VERSION 5.8 ;
BUSBITCHARS "[]" ;
DIVIDERCHAR "/" ;
UNITS
    DATABASE MICRONS 1000 ;
END UNITS

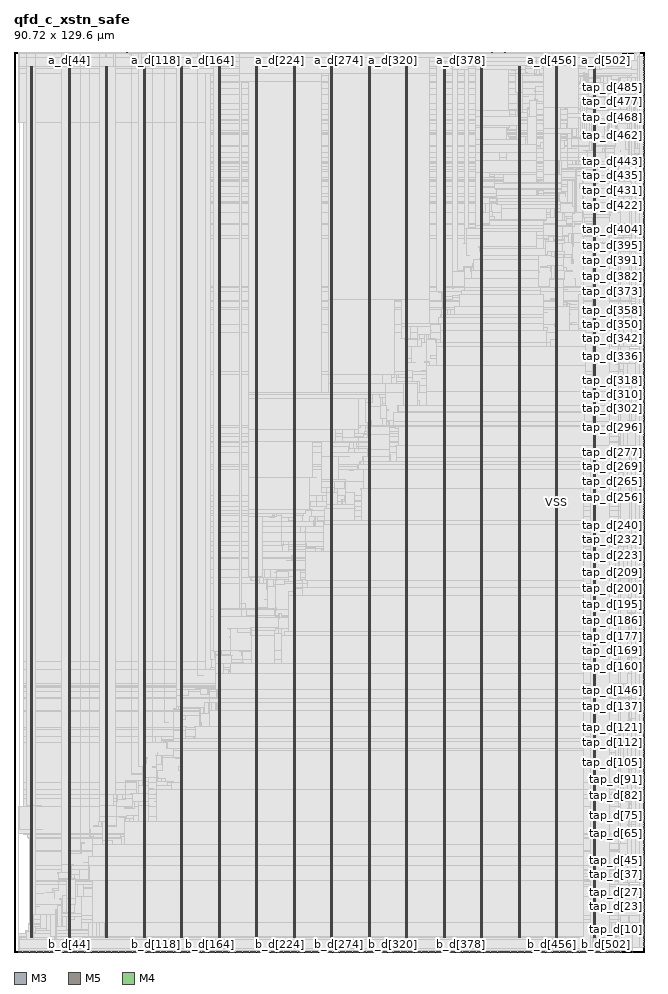
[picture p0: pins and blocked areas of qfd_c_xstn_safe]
MACRO qfd_c_xstn_safe
  FOREIGN qfd_c_xstn_safe 0 0 ;
  CLASS BLOCK ;
  SIZE 90.72 BY 129.6 ;
  PIN a_d[0]
    DIRECTION OUTPUT ;
    USE SIGNAL ;
    PORT
      LAYER M3 ;
        RECT  0.612 129.562 0.63 129.6 ;
    END
  END a_d[0]
  PIN a_d[100]
    DIRECTION OUTPUT ;
    USE SIGNAL ;
    PORT
      LAYER M3 ;
        RECT  17.46 129.562 17.478 129.6 ;
    END
  END a_d[100]
  PIN a_d[101]
    DIRECTION OUTPUT ;
    USE SIGNAL ;
    PORT
      LAYER M5 ;
        RECT  17.616 129.516 17.64 129.6 ;
    END
  END a_d[101]
  PIN a_d[102]
    DIRECTION OUTPUT ;
    USE SIGNAL ;
    PORT
      LAYER M3 ;
        RECT  17.784 129.562 17.802 129.6 ;
    END
  END a_d[102]
  PIN a_d[103]
    DIRECTION OUTPUT ;
    USE SIGNAL ;
    PORT
      LAYER M5 ;
        RECT  17.952 129.516 17.976 129.6 ;
    END
  END a_d[103]
  PIN a_d[104]
    DIRECTION OUTPUT ;
    USE SIGNAL ;
    PORT
      LAYER M3 ;
        RECT  18.144 129.562 18.162 129.6 ;
    END
  END a_d[104]
  PIN a_d[105]
    DIRECTION OUTPUT ;
    USE SIGNAL ;
    PORT
      LAYER M5 ;
        RECT  18.288 129.516 18.312 129.6 ;
    END
  END a_d[105]
  PIN a_d[106]
    DIRECTION OUTPUT ;
    USE SIGNAL ;
    PORT
      LAYER M3 ;
        RECT  18.468 129.562 18.486 129.6 ;
    END
  END a_d[106]
  PIN a_d[107]
    DIRECTION OUTPUT ;
    USE SIGNAL ;
    PORT
      LAYER M5 ;
        RECT  18.624 129.516 18.648 129.6 ;
    END
  END a_d[107]
  PIN a_d[108]
    DIRECTION OUTPUT ;
    USE SIGNAL ;
    PORT
      LAYER M3 ;
        RECT  18.828 129.562 18.846 129.6 ;
    END
  END a_d[108]
  PIN a_d[109]
    DIRECTION OUTPUT ;
    USE SIGNAL ;
    PORT
      LAYER M5 ;
        RECT  18.96 129.516 18.984 129.6 ;
    END
  END a_d[109]
  PIN a_d[10]
    DIRECTION OUTPUT ;
    USE SIGNAL ;
    PORT
      LAYER M3 ;
        RECT  2.304 129.562 2.322 129.6 ;
    END
  END a_d[10]
  PIN a_d[110]
    DIRECTION OUTPUT ;
    USE SIGNAL ;
    PORT
      LAYER M3 ;
        RECT  19.152 129.562 19.17 129.6 ;
    END
  END a_d[110]
  PIN a_d[111]
    DIRECTION OUTPUT ;
    USE SIGNAL ;
    PORT
      LAYER M5 ;
        RECT  19.296 129.516 19.32 129.6 ;
    END
  END a_d[111]
  PIN a_d[112]
    DIRECTION OUTPUT ;
    USE SIGNAL ;
    PORT
      LAYER M3 ;
        RECT  19.476 129.562 19.494 129.6 ;
    END
  END a_d[112]
  PIN a_d[113]
    DIRECTION OUTPUT ;
    USE SIGNAL ;
    PORT
      LAYER M5 ;
        RECT  19.632 129.516 19.656 129.6 ;
    END
  END a_d[113]
  PIN a_d[114]
    DIRECTION OUTPUT ;
    USE SIGNAL ;
    PORT
      LAYER M3 ;
        RECT  19.836 129.562 19.854 129.6 ;
    END
  END a_d[114]
  PIN a_d[115]
    DIRECTION OUTPUT ;
    USE SIGNAL ;
    PORT
      LAYER M5 ;
        RECT  19.968 129.516 19.992 129.6 ;
    END
  END a_d[115]
  PIN a_d[116]
    DIRECTION OUTPUT ;
    USE SIGNAL ;
    PORT
      LAYER M3 ;
        RECT  20.16 129.562 20.178 129.6 ;
    END
  END a_d[116]
  PIN a_d[117]
    DIRECTION OUTPUT ;
    USE SIGNAL ;
    PORT
      LAYER M5 ;
        RECT  20.304 129.516 20.328 129.6 ;
    END
  END a_d[117]
  PIN a_d[118]
    DIRECTION OUTPUT ;
    USE SIGNAL ;
    PORT
      LAYER M3 ;
        RECT  20.484 129.562 20.502 129.6 ;
    END
  END a_d[118]
  PIN a_d[119]
    DIRECTION OUTPUT ;
    USE SIGNAL ;
    PORT
      LAYER M5 ;
        RECT  20.64 129.516 20.664 129.6 ;
    END
  END a_d[119]
  PIN a_d[11]
    DIRECTION OUTPUT ;
    USE SIGNAL ;
    PORT
      LAYER M5 ;
        RECT  2.448 129.516 2.472 129.6 ;
    END
  END a_d[11]
  PIN a_d[120]
    DIRECTION OUTPUT ;
    USE SIGNAL ;
    PORT
      LAYER M3 ;
        RECT  20.844 129.562 20.862 129.6 ;
    END
  END a_d[120]
  PIN a_d[121]
    DIRECTION OUTPUT ;
    USE SIGNAL ;
    PORT
      LAYER M5 ;
        RECT  20.976 129.516 21 129.6 ;
    END
  END a_d[121]
  PIN a_d[122]
    DIRECTION OUTPUT ;
    USE SIGNAL ;
    PORT
      LAYER M3 ;
        RECT  21.168 129.562 21.186 129.6 ;
    END
  END a_d[122]
  PIN a_d[123]
    DIRECTION OUTPUT ;
    USE SIGNAL ;
    PORT
      LAYER M5 ;
        RECT  21.36 129.516 21.384 129.6 ;
    END
  END a_d[123]
  PIN a_d[124]
    DIRECTION OUTPUT ;
    USE SIGNAL ;
    PORT
      LAYER M3 ;
        RECT  21.492 129.562 21.51 129.6 ;
    END
  END a_d[124]
  PIN a_d[125]
    DIRECTION OUTPUT ;
    USE SIGNAL ;
    PORT
      LAYER M5 ;
        RECT  21.696 129.516 21.72 129.6 ;
    END
  END a_d[125]
  PIN a_d[126]
    DIRECTION OUTPUT ;
    USE SIGNAL ;
    PORT
      LAYER M3 ;
        RECT  21.852 129.562 21.87 129.6 ;
    END
  END a_d[126]
  PIN a_d[127]
    DIRECTION OUTPUT ;
    USE SIGNAL ;
    PORT
      LAYER M5 ;
        RECT  22.032 129.516 22.056 129.6 ;
    END
  END a_d[127]
  PIN a_d[128]
    DIRECTION OUTPUT ;
    USE SIGNAL ;
    PORT
      LAYER M3 ;
        RECT  22.176 129.562 22.194 129.6 ;
    END
  END a_d[128]
  PIN a_d[129]
    DIRECTION OUTPUT ;
    USE SIGNAL ;
    PORT
      LAYER M5 ;
        RECT  22.368 129.516 22.392 129.6 ;
    END
  END a_d[129]
  PIN a_d[12]
    DIRECTION OUTPUT ;
    USE SIGNAL ;
    PORT
      LAYER M3 ;
        RECT  2.628 129.562 2.646 129.6 ;
    END
  END a_d[12]
  PIN a_d[130]
    DIRECTION OUTPUT ;
    USE SIGNAL ;
    PORT
      LAYER M3 ;
        RECT  22.536 129.562 22.554 129.6 ;
    END
  END a_d[130]
  PIN a_d[131]
    DIRECTION OUTPUT ;
    USE SIGNAL ;
    PORT
      LAYER M5 ;
        RECT  22.704 129.516 22.728 129.6 ;
    END
  END a_d[131]
  PIN a_d[132]
    DIRECTION OUTPUT ;
    USE SIGNAL ;
    PORT
      LAYER M3 ;
        RECT  22.86 129.562 22.878 129.6 ;
    END
  END a_d[132]
  PIN a_d[133]
    DIRECTION OUTPUT ;
    USE SIGNAL ;
    PORT
      LAYER M5 ;
        RECT  23.04 129.516 23.064 129.6 ;
    END
  END a_d[133]
  PIN a_d[134]
    DIRECTION OUTPUT ;
    USE SIGNAL ;
    PORT
      LAYER M3 ;
        RECT  23.184 129.562 23.202 129.6 ;
    END
  END a_d[134]
  PIN a_d[135]
    DIRECTION OUTPUT ;
    USE SIGNAL ;
    PORT
      LAYER M5 ;
        RECT  23.376 129.516 23.4 129.6 ;
    END
  END a_d[135]
  PIN a_d[136]
    DIRECTION OUTPUT ;
    USE SIGNAL ;
    PORT
      LAYER M3 ;
        RECT  23.544 129.562 23.562 129.6 ;
    END
  END a_d[136]
  PIN a_d[137]
    DIRECTION OUTPUT ;
    USE SIGNAL ;
    PORT
      LAYER M5 ;
        RECT  23.712 129.516 23.736 129.6 ;
    END
  END a_d[137]
  PIN a_d[138]
    DIRECTION OUTPUT ;
    USE SIGNAL ;
    PORT
      LAYER M3 ;
        RECT  23.868 129.562 23.886 129.6 ;
    END
  END a_d[138]
  PIN a_d[139]
    DIRECTION OUTPUT ;
    USE SIGNAL ;
    PORT
      LAYER M5 ;
        RECT  24.048 129.516 24.072 129.6 ;
    END
  END a_d[139]
  PIN a_d[13]
    DIRECTION OUTPUT ;
    USE SIGNAL ;
    PORT
      LAYER M5 ;
        RECT  2.784 129.516 2.808 129.6 ;
    END
  END a_d[13]
  PIN a_d[140]
    DIRECTION OUTPUT ;
    USE SIGNAL ;
    PORT
      LAYER M3 ;
        RECT  24.192 129.562 24.21 129.6 ;
    END
  END a_d[140]
  PIN a_d[141]
    DIRECTION OUTPUT ;
    USE SIGNAL ;
    PORT
      LAYER M5 ;
        RECT  24.384 129.516 24.408 129.6 ;
    END
  END a_d[141]
  PIN a_d[142]
    DIRECTION OUTPUT ;
    USE SIGNAL ;
    PORT
      LAYER M3 ;
        RECT  24.552 129.562 24.57 129.6 ;
    END
  END a_d[142]
  PIN a_d[143]
    DIRECTION OUTPUT ;
    USE SIGNAL ;
    PORT
      LAYER M5 ;
        RECT  24.72 129.516 24.744 129.6 ;
    END
  END a_d[143]
  PIN a_d[144]
    DIRECTION OUTPUT ;
    USE SIGNAL ;
    PORT
      LAYER M3 ;
        RECT  24.876 129.562 24.894 129.6 ;
    END
  END a_d[144]
  PIN a_d[145]
    DIRECTION OUTPUT ;
    USE SIGNAL ;
    PORT
      LAYER M5 ;
        RECT  25.056 129.516 25.08 129.6 ;
    END
  END a_d[145]
  PIN a_d[146]
    DIRECTION OUTPUT ;
    USE SIGNAL ;
    PORT
      LAYER M3 ;
        RECT  25.2 129.562 25.218 129.6 ;
    END
  END a_d[146]
  PIN a_d[147]
    DIRECTION OUTPUT ;
    USE SIGNAL ;
    PORT
      LAYER M5 ;
        RECT  25.392 129.516 25.416 129.6 ;
    END
  END a_d[147]
  PIN a_d[148]
    DIRECTION OUTPUT ;
    USE SIGNAL ;
    PORT
      LAYER M3 ;
        RECT  25.56 129.562 25.578 129.6 ;
    END
  END a_d[148]
  PIN a_d[149]
    DIRECTION OUTPUT ;
    USE SIGNAL ;
    PORT
      LAYER M5 ;
        RECT  25.728 129.516 25.752 129.6 ;
    END
  END a_d[149]
  PIN a_d[14]
    DIRECTION OUTPUT ;
    USE SIGNAL ;
    PORT
      LAYER M3 ;
        RECT  2.988 129.562 3.006 129.6 ;
    END
  END a_d[14]
  PIN a_d[150]
    DIRECTION OUTPUT ;
    USE SIGNAL ;
    PORT
      LAYER M3 ;
        RECT  25.884 129.562 25.902 129.6 ;
    END
  END a_d[150]
  PIN a_d[151]
    DIRECTION OUTPUT ;
    USE SIGNAL ;
    PORT
      LAYER M5 ;
        RECT  26.064 129.516 26.088 129.6 ;
    END
  END a_d[151]
  PIN a_d[152]
    DIRECTION OUTPUT ;
    USE SIGNAL ;
    PORT
      LAYER M3 ;
        RECT  26.208 129.562 26.226 129.6 ;
    END
  END a_d[152]
  PIN a_d[153]
    DIRECTION OUTPUT ;
    USE SIGNAL ;
    PORT
      LAYER M5 ;
        RECT  26.4 129.516 26.424 129.6 ;
    END
  END a_d[153]
  PIN a_d[154]
    DIRECTION OUTPUT ;
    USE SIGNAL ;
    PORT
      LAYER M3 ;
        RECT  26.568 129.562 26.586 129.6 ;
    END
  END a_d[154]
  PIN a_d[155]
    DIRECTION OUTPUT ;
    USE SIGNAL ;
    PORT
      LAYER M5 ;
        RECT  26.736 129.516 26.76 129.6 ;
    END
  END a_d[155]
  PIN a_d[156]
    DIRECTION OUTPUT ;
    USE SIGNAL ;
    PORT
      LAYER M3 ;
        RECT  26.892 129.562 26.91 129.6 ;
    END
  END a_d[156]
  PIN a_d[157]
    DIRECTION OUTPUT ;
    USE SIGNAL ;
    PORT
      LAYER M5 ;
        RECT  27.072 129.516 27.096 129.6 ;
    END
  END a_d[157]
  PIN a_d[158]
    DIRECTION OUTPUT ;
    USE SIGNAL ;
    PORT
      LAYER M3 ;
        RECT  27.252 129.562 27.27 129.6 ;
    END
  END a_d[158]
  PIN a_d[159]
    DIRECTION OUTPUT ;
    USE SIGNAL ;
    PORT
      LAYER M5 ;
        RECT  27.408 129.516 27.432 129.6 ;
    END
  END a_d[159]
  PIN a_d[15]
    DIRECTION OUTPUT ;
    USE SIGNAL ;
    PORT
      LAYER M5 ;
        RECT  3.12 129.516 3.144 129.6 ;
    END
  END a_d[15]
  PIN a_d[160]
    DIRECTION OUTPUT ;
    USE SIGNAL ;
    PORT
      LAYER M3 ;
        RECT  27.576 129.562 27.594 129.6 ;
    END
  END a_d[160]
  PIN a_d[161]
    DIRECTION OUTPUT ;
    USE SIGNAL ;
    PORT
      LAYER M5 ;
        RECT  27.744 129.516 27.768 129.6 ;
    END
  END a_d[161]
  PIN a_d[162]
    DIRECTION OUTPUT ;
    USE SIGNAL ;
    PORT
      LAYER M3 ;
        RECT  27.9 129.562 27.918 129.6 ;
    END
  END a_d[162]
  PIN a_d[163]
    DIRECTION OUTPUT ;
    USE SIGNAL ;
    PORT
      LAYER M5 ;
        RECT  28.08 129.516 28.104 129.6 ;
    END
  END a_d[163]
  PIN a_d[164]
    DIRECTION OUTPUT ;
    USE SIGNAL ;
    PORT
      LAYER M3 ;
        RECT  28.26 129.562 28.278 129.6 ;
    END
  END a_d[164]
  PIN a_d[165]
    DIRECTION OUTPUT ;
    USE SIGNAL ;
    PORT
      LAYER M5 ;
        RECT  28.416 129.516 28.44 129.6 ;
    END
  END a_d[165]
  PIN a_d[166]
    DIRECTION OUTPUT ;
    USE SIGNAL ;
    PORT
      LAYER M3 ;
        RECT  28.584 129.562 28.602 129.6 ;
    END
  END a_d[166]
  PIN a_d[167]
    DIRECTION OUTPUT ;
    USE SIGNAL ;
    PORT
      LAYER M5 ;
        RECT  28.752 129.516 28.776 129.6 ;
    END
  END a_d[167]
  PIN a_d[168]
    DIRECTION OUTPUT ;
    USE SIGNAL ;
    PORT
      LAYER M3 ;
        RECT  28.908 129.562 28.926 129.6 ;
    END
  END a_d[168]
  PIN a_d[169]
    DIRECTION OUTPUT ;
    USE SIGNAL ;
    PORT
      LAYER M5 ;
        RECT  29.088 129.516 29.112 129.6 ;
    END
  END a_d[169]
  PIN a_d[16]
    DIRECTION OUTPUT ;
    USE SIGNAL ;
    PORT
      LAYER M3 ;
        RECT  3.312 129.562 3.33 129.6 ;
    END
  END a_d[16]
  PIN a_d[170]
    DIRECTION OUTPUT ;
    USE SIGNAL ;
    PORT
      LAYER M3 ;
        RECT  29.268 129.562 29.286 129.6 ;
    END
  END a_d[170]
  PIN a_d[171]
    DIRECTION OUTPUT ;
    USE SIGNAL ;
    PORT
      LAYER M5 ;
        RECT  29.424 129.516 29.448 129.6 ;
    END
  END a_d[171]
  PIN a_d[172]
    DIRECTION OUTPUT ;
    USE SIGNAL ;
    PORT
      LAYER M3 ;
        RECT  29.592 129.562 29.61 129.6 ;
    END
  END a_d[172]
  PIN a_d[173]
    DIRECTION OUTPUT ;
    USE SIGNAL ;
    PORT
      LAYER M5 ;
        RECT  29.76 129.516 29.784 129.6 ;
    END
  END a_d[173]
  PIN a_d[174]
    DIRECTION OUTPUT ;
    USE SIGNAL ;
    PORT
      LAYER M3 ;
        RECT  29.916 129.562 29.934 129.6 ;
    END
  END a_d[174]
  PIN a_d[175]
    DIRECTION OUTPUT ;
    USE SIGNAL ;
    PORT
      LAYER M5 ;
        RECT  30.096 129.516 30.12 129.6 ;
    END
  END a_d[175]
  PIN a_d[176]
    DIRECTION OUTPUT ;
    USE SIGNAL ;
    PORT
      LAYER M3 ;
        RECT  30.276 129.562 30.294 129.6 ;
    END
  END a_d[176]
  PIN a_d[177]
    DIRECTION OUTPUT ;
    USE SIGNAL ;
    PORT
      LAYER M5 ;
        RECT  30.432 129.516 30.456 129.6 ;
    END
  END a_d[177]
  PIN a_d[178]
    DIRECTION OUTPUT ;
    USE SIGNAL ;
    PORT
      LAYER M3 ;
        RECT  30.6 129.562 30.618 129.6 ;
    END
  END a_d[178]
  PIN a_d[179]
    DIRECTION OUTPUT ;
    USE SIGNAL ;
    PORT
      LAYER M5 ;
        RECT  30.768 129.516 30.792 129.6 ;
    END
  END a_d[179]
  PIN a_d[17]
    DIRECTION OUTPUT ;
    USE SIGNAL ;
    PORT
      LAYER M5 ;
        RECT  3.456 129.516 3.48 129.6 ;
    END
  END a_d[17]
  PIN a_d[180]
    DIRECTION OUTPUT ;
    USE SIGNAL ;
    PORT
      LAYER M3 ;
        RECT  30.96 129.562 30.978 129.6 ;
    END
  END a_d[180]
  PIN a_d[181]
    DIRECTION OUTPUT ;
    USE SIGNAL ;
    PORT
      LAYER M5 ;
        RECT  31.104 129.516 31.128 129.6 ;
    END
  END a_d[181]
  PIN a_d[182]
    DIRECTION OUTPUT ;
    USE SIGNAL ;
    PORT
      LAYER M3 ;
        RECT  31.284 129.562 31.302 129.6 ;
    END
  END a_d[182]
  PIN a_d[183]
    DIRECTION OUTPUT ;
    USE SIGNAL ;
    PORT
      LAYER M5 ;
        RECT  31.44 129.516 31.464 129.6 ;
    END
  END a_d[183]
  PIN a_d[184]
    DIRECTION OUTPUT ;
    USE SIGNAL ;
    PORT
      LAYER M3 ;
        RECT  31.608 129.562 31.626 129.6 ;
    END
  END a_d[184]
  PIN a_d[185]
    DIRECTION OUTPUT ;
    USE SIGNAL ;
    PORT
      LAYER M5 ;
        RECT  31.776 129.516 31.8 129.6 ;
    END
  END a_d[185]
  PIN a_d[186]
    DIRECTION OUTPUT ;
    USE SIGNAL ;
    PORT
      LAYER M3 ;
        RECT  31.968 129.562 31.986 129.6 ;
    END
  END a_d[186]
  PIN a_d[187]
    DIRECTION OUTPUT ;
    USE SIGNAL ;
    PORT
      LAYER M5 ;
        RECT  32.112 129.516 32.136 129.6 ;
    END
  END a_d[187]
  PIN a_d[188]
    DIRECTION OUTPUT ;
    USE SIGNAL ;
    PORT
      LAYER M3 ;
        RECT  32.292 129.562 32.31 129.6 ;
    END
  END a_d[188]
  PIN a_d[189]
    DIRECTION OUTPUT ;
    USE SIGNAL ;
    PORT
      LAYER M5 ;
        RECT  32.448 129.516 32.472 129.6 ;
    END
  END a_d[189]
  PIN a_d[18]
    DIRECTION OUTPUT ;
    USE SIGNAL ;
    PORT
      LAYER M3 ;
        RECT  3.636 129.562 3.654 129.6 ;
    END
  END a_d[18]
  PIN a_d[190]
    DIRECTION OUTPUT ;
    USE SIGNAL ;
    PORT
      LAYER M3 ;
        RECT  32.616 129.562 32.634 129.6 ;
    END
  END a_d[190]
  PIN a_d[191]
    DIRECTION OUTPUT ;
    USE SIGNAL ;
    PORT
      LAYER M5 ;
        RECT  32.784 129.516 32.808 129.6 ;
    END
  END a_d[191]
  PIN a_d[192]
    DIRECTION OUTPUT ;
    USE SIGNAL ;
    PORT
      LAYER M3 ;
        RECT  32.976 129.562 32.994 129.6 ;
    END
  END a_d[192]
  PIN a_d[193]
    DIRECTION OUTPUT ;
    USE SIGNAL ;
    PORT
      LAYER M5 ;
        RECT  33.12 129.516 33.144 129.6 ;
    END
  END a_d[193]
  PIN a_d[194]
    DIRECTION OUTPUT ;
    USE SIGNAL ;
    PORT
      LAYER M3 ;
        RECT  33.3 129.562 33.318 129.6 ;
    END
  END a_d[194]
  PIN a_d[195]
    DIRECTION OUTPUT ;
    USE SIGNAL ;
    PORT
      LAYER M5 ;
        RECT  33.456 129.516 33.48 129.6 ;
    END
  END a_d[195]
  PIN a_d[196]
    DIRECTION OUTPUT ;
    USE SIGNAL ;
    PORT
      LAYER M3 ;
        RECT  33.624 129.562 33.642 129.6 ;
    END
  END a_d[196]
  PIN a_d[197]
    DIRECTION OUTPUT ;
    USE SIGNAL ;
    PORT
      LAYER M5 ;
        RECT  33.792 129.516 33.816 129.6 ;
    END
  END a_d[197]
  PIN a_d[198]
    DIRECTION OUTPUT ;
    USE SIGNAL ;
    PORT
      LAYER M3 ;
        RECT  33.984 129.562 34.002 129.6 ;
    END
  END a_d[198]
  PIN a_d[199]
    DIRECTION OUTPUT ;
    USE SIGNAL ;
    PORT
      LAYER M5 ;
        RECT  34.128 129.516 34.152 129.6 ;
    END
  END a_d[199]
  PIN a_d[19]
    DIRECTION OUTPUT ;
    USE SIGNAL ;
    PORT
      LAYER M5 ;
        RECT  3.792 129.516 3.816 129.6 ;
    END
  END a_d[19]
  PIN a_d[1]
    DIRECTION OUTPUT ;
    USE SIGNAL ;
    PORT
      LAYER M5 ;
        RECT  0.768 129.516 0.792 129.6 ;
    END
  END a_d[1]
  PIN a_d[200]
    DIRECTION OUTPUT ;
    USE SIGNAL ;
    PORT
      LAYER M3 ;
        RECT  34.308 129.562 34.326 129.6 ;
    END
  END a_d[200]
  PIN a_d[201]
    DIRECTION OUTPUT ;
    USE SIGNAL ;
    PORT
      LAYER M5 ;
        RECT  34.464 129.516 34.488 129.6 ;
    END
  END a_d[201]
  PIN a_d[202]
    DIRECTION OUTPUT ;
    USE SIGNAL ;
    PORT
      LAYER M3 ;
        RECT  34.668 129.562 34.686 129.6 ;
    END
  END a_d[202]
  PIN a_d[203]
    DIRECTION OUTPUT ;
    USE SIGNAL ;
    PORT
      LAYER M5 ;
        RECT  34.8 129.516 34.824 129.6 ;
    END
  END a_d[203]
  PIN a_d[204]
    DIRECTION OUTPUT ;
    USE SIGNAL ;
    PORT
      LAYER M3 ;
        RECT  34.992 129.562 35.01 129.6 ;
    END
  END a_d[204]
  PIN a_d[205]
    DIRECTION OUTPUT ;
    USE SIGNAL ;
    PORT
      LAYER M5 ;
        RECT  35.136 129.516 35.16 129.6 ;
    END
  END a_d[205]
  PIN a_d[206]
    DIRECTION OUTPUT ;
    USE SIGNAL ;
    PORT
      LAYER M3 ;
        RECT  35.316 129.562 35.334 129.6 ;
    END
  END a_d[206]
  PIN a_d[207]
    DIRECTION OUTPUT ;
    USE SIGNAL ;
    PORT
      LAYER M5 ;
        RECT  35.472 129.516 35.496 129.6 ;
    END
  END a_d[207]
  PIN a_d[208]
    DIRECTION OUTPUT ;
    USE SIGNAL ;
    PORT
      LAYER M3 ;
        RECT  35.676 129.562 35.694 129.6 ;
    END
  END a_d[208]
  PIN a_d[209]
    DIRECTION OUTPUT ;
    USE SIGNAL ;
    PORT
      LAYER M5 ;
        RECT  35.808 129.516 35.832 129.6 ;
    END
  END a_d[209]
  PIN a_d[20]
    DIRECTION OUTPUT ;
    USE SIGNAL ;
    PORT
      LAYER M3 ;
        RECT  3.996 129.562 4.014 129.6 ;
    END
  END a_d[20]
  PIN a_d[210]
    DIRECTION OUTPUT ;
    USE SIGNAL ;
    PORT
      LAYER M3 ;
        RECT  36 129.562 36.018 129.6 ;
    END
  END a_d[210]
  PIN a_d[211]
    DIRECTION OUTPUT ;
    USE SIGNAL ;
    PORT
      LAYER M5 ;
        RECT  36.144 129.516 36.168 129.6 ;
    END
  END a_d[211]
  PIN a_d[212]
    DIRECTION OUTPUT ;
    USE SIGNAL ;
    PORT
      LAYER M3 ;
        RECT  36.324 129.562 36.342 129.6 ;
    END
  END a_d[212]
  PIN a_d[213]
    DIRECTION OUTPUT ;
    USE SIGNAL ;
    PORT
      LAYER M5 ;
        RECT  36.48 129.516 36.504 129.6 ;
    END
  END a_d[213]
  PIN a_d[214]
    DIRECTION OUTPUT ;
    USE SIGNAL ;
    PORT
      LAYER M3 ;
        RECT  36.684 129.562 36.702 129.6 ;
    END
  END a_d[214]
  PIN a_d[215]
    DIRECTION OUTPUT ;
    USE SIGNAL ;
    PORT
      LAYER M5 ;
        RECT  36.816 129.516 36.84 129.6 ;
    END
  END a_d[215]
  PIN a_d[216]
    DIRECTION OUTPUT ;
    USE SIGNAL ;
    PORT
      LAYER M3 ;
        RECT  37.008 129.562 37.026 129.6 ;
    END
  END a_d[216]
  PIN a_d[217]
    DIRECTION OUTPUT ;
    USE SIGNAL ;
    PORT
      LAYER M5 ;
        RECT  37.152 129.516 37.176 129.6 ;
    END
  END a_d[217]
  PIN a_d[218]
    DIRECTION OUTPUT ;
    USE SIGNAL ;
    PORT
      LAYER M3 ;
        RECT  37.332 129.562 37.35 129.6 ;
    END
  END a_d[218]
  PIN a_d[219]
    DIRECTION OUTPUT ;
    USE SIGNAL ;
    PORT
      LAYER M5 ;
        RECT  37.488 129.516 37.512 129.6 ;
    END
  END a_d[219]
  PIN a_d[21]
    DIRECTION OUTPUT ;
    USE SIGNAL ;
    PORT
      LAYER M5 ;
        RECT  4.128 129.516 4.152 129.6 ;
    END
  END a_d[21]
  PIN a_d[220]
    DIRECTION OUTPUT ;
    USE SIGNAL ;
    PORT
      LAYER M3 ;
        RECT  37.692 129.562 37.71 129.6 ;
    END
  END a_d[220]
  PIN a_d[221]
    DIRECTION OUTPUT ;
    USE SIGNAL ;
    PORT
      LAYER M5 ;
        RECT  37.872 129.516 37.896 129.6 ;
    END
  END a_d[221]
  PIN a_d[222]
    DIRECTION OUTPUT ;
    USE SIGNAL ;
    PORT
      LAYER M3 ;
        RECT  38.016 129.562 38.034 129.6 ;
    END
  END a_d[222]
  PIN a_d[223]
    DIRECTION OUTPUT ;
    USE SIGNAL ;
    PORT
      LAYER M5 ;
        RECT  38.208 129.516 38.232 129.6 ;
    END
  END a_d[223]
  PIN a_d[224]
    DIRECTION OUTPUT ;
    USE SIGNAL ;
    PORT
      LAYER M3 ;
        RECT  38.34 129.562 38.358 129.6 ;
    END
  END a_d[224]
  PIN a_d[225]
    DIRECTION OUTPUT ;
    USE SIGNAL ;
    PORT
      LAYER M5 ;
        RECT  38.544 129.516 38.568 129.6 ;
    END
  END a_d[225]
  PIN a_d[226]
    DIRECTION OUTPUT ;
    USE SIGNAL ;
    PORT
      LAYER M3 ;
        RECT  38.7 129.562 38.718 129.6 ;
    END
  END a_d[226]
  PIN a_d[227]
    DIRECTION OUTPUT ;
    USE SIGNAL ;
    PORT
      LAYER M5 ;
        RECT  38.88 129.516 38.904 129.6 ;
    END
  END a_d[227]
  PIN a_d[228]
    DIRECTION OUTPUT ;
    USE SIGNAL ;
    PORT
      LAYER M3 ;
        RECT  39.024 129.562 39.042 129.6 ;
    END
  END a_d[228]
  PIN a_d[229]
    DIRECTION OUTPUT ;
    USE SIGNAL ;
    PORT
      LAYER M5 ;
        RECT  39.216 129.516 39.24 129.6 ;
    END
  END a_d[229]
  PIN a_d[22]
    DIRECTION OUTPUT ;
    USE SIGNAL ;
    PORT
      LAYER M3 ;
        RECT  4.32 129.562 4.338 129.6 ;
    END
  END a_d[22]
  PIN a_d[230]
    DIRECTION OUTPUT ;
    USE SIGNAL ;
    PORT
      LAYER M3 ;
        RECT  39.384 129.562 39.402 129.6 ;
    END
  END a_d[230]
  PIN a_d[231]
    DIRECTION OUTPUT ;
    USE SIGNAL ;
    PORT
      LAYER M5 ;
        RECT  39.552 129.516 39.576 129.6 ;
    END
  END a_d[231]
  PIN a_d[232]
    DIRECTION OUTPUT ;
    USE SIGNAL ;
    PORT
      LAYER M3 ;
        RECT  39.708 129.562 39.726 129.6 ;
    END
  END a_d[232]
  PIN a_d[233]
    DIRECTION OUTPUT ;
    USE SIGNAL ;
    PORT
      LAYER M5 ;
        RECT  39.888 129.516 39.912 129.6 ;
    END
  END a_d[233]
  PIN a_d[234]
    DIRECTION OUTPUT ;
    USE SIGNAL ;
    PORT
      LAYER M3 ;
        RECT  40.032 129.562 40.05 129.6 ;
    END
  END a_d[234]
  PIN a_d[235]
    DIRECTION OUTPUT ;
    USE SIGNAL ;
    PORT
      LAYER M5 ;
        RECT  40.224 129.516 40.248 129.6 ;
    END
  END a_d[235]
  PIN a_d[236]
    DIRECTION OUTPUT ;
    USE SIGNAL ;
    PORT
      LAYER M3 ;
        RECT  40.392 129.562 40.41 129.6 ;
    END
  END a_d[236]
  PIN a_d[237]
    DIRECTION OUTPUT ;
    USE SIGNAL ;
    PORT
      LAYER M5 ;
        RECT  40.56 129.516 40.584 129.6 ;
    END
  END a_d[237]
  PIN a_d[238]
    DIRECTION OUTPUT ;
    USE SIGNAL ;
    PORT
      LAYER M3 ;
        RECT  40.716 129.562 40.734 129.6 ;
    END
  END a_d[238]
  PIN a_d[239]
    DIRECTION OUTPUT ;
    USE SIGNAL ;
    PORT
      LAYER M5 ;
        RECT  40.896 129.516 40.92 129.6 ;
    END
  END a_d[239]
  PIN a_d[23]
    DIRECTION OUTPUT ;
    USE SIGNAL ;
    PORT
      LAYER M5 ;
        RECT  4.464 129.516 4.488 129.6 ;
    END
  END a_d[23]
  PIN a_d[240]
    DIRECTION OUTPUT ;
    USE SIGNAL ;
    PORT
      LAYER M3 ;
        RECT  41.04 129.562 41.058 129.6 ;
    END
  END a_d[240]
  PIN a_d[241]
    DIRECTION OUTPUT ;
    USE SIGNAL ;
    PORT
      LAYER M5 ;
        RECT  41.232 129.516 41.256 129.6 ;
    END
  END a_d[241]
  PIN a_d[242]
    DIRECTION OUTPUT ;
    USE SIGNAL ;
    PORT
      LAYER M3 ;
        RECT  41.4 129.562 41.418 129.6 ;
    END
  END a_d[242]
  PIN a_d[243]
    DIRECTION OUTPUT ;
    USE SIGNAL ;
    PORT
      LAYER M5 ;
        RECT  41.568 129.516 41.592 129.6 ;
    END
  END a_d[243]
  PIN a_d[244]
    DIRECTION OUTPUT ;
    USE SIGNAL ;
    PORT
      LAYER M3 ;
        RECT  41.724 129.562 41.742 129.6 ;
    END
  END a_d[244]
  PIN a_d[245]
    DIRECTION OUTPUT ;
    USE SIGNAL ;
    PORT
      LAYER M5 ;
        RECT  41.904 129.516 41.928 129.6 ;
    END
  END a_d[245]
  PIN a_d[246]
    DIRECTION OUTPUT ;
    USE SIGNAL ;
    PORT
      LAYER M3 ;
        RECT  42.048 129.562 42.066 129.6 ;
    END
  END a_d[246]
  PIN a_d[247]
    DIRECTION OUTPUT ;
    USE SIGNAL ;
    PORT
      LAYER M5 ;
        RECT  42.24 129.516 42.264 129.6 ;
    END
  END a_d[247]
  PIN a_d[248]
    DIRECTION OUTPUT ;
    USE SIGNAL ;
    PORT
      LAYER M3 ;
        RECT  42.408 129.562 42.426 129.6 ;
    END
  END a_d[248]
  PIN a_d[249]
    DIRECTION OUTPUT ;
    USE SIGNAL ;
    PORT
      LAYER M5 ;
        RECT  42.576 129.516 42.6 129.6 ;
    END
  END a_d[249]
  PIN a_d[24]
    DIRECTION OUTPUT ;
    USE SIGNAL ;
    PORT
      LAYER M3 ;
        RECT  4.644 129.562 4.662 129.6 ;
    END
  END a_d[24]
  PIN a_d[250]
    DIRECTION OUTPUT ;
    USE SIGNAL ;
    PORT
      LAYER M3 ;
        RECT  42.732 129.562 42.75 129.6 ;
    END
  END a_d[250]
  PIN a_d[251]
    DIRECTION OUTPUT ;
    USE SIGNAL ;
    PORT
      LAYER M5 ;
        RECT  42.912 129.516 42.936 129.6 ;
    END
  END a_d[251]
  PIN a_d[252]
    DIRECTION OUTPUT ;
    USE SIGNAL ;
    PORT
      LAYER M3 ;
        RECT  43.092 129.562 43.11 129.6 ;
    END
  END a_d[252]
  PIN a_d[253]
    DIRECTION OUTPUT ;
    USE SIGNAL ;
    PORT
      LAYER M5 ;
        RECT  43.248 129.516 43.272 129.6 ;
    END
  END a_d[253]
  PIN a_d[254]
    DIRECTION OUTPUT ;
    USE SIGNAL ;
    PORT
      LAYER M3 ;
        RECT  43.416 129.562 43.434 129.6 ;
    END
  END a_d[254]
  PIN a_d[255]
    DIRECTION OUTPUT ;
    USE SIGNAL ;
    PORT
      LAYER M5 ;
        RECT  43.584 129.516 43.608 129.6 ;
    END
  END a_d[255]
  PIN a_d[256]
    DIRECTION OUTPUT ;
    USE SIGNAL ;
    PORT
      LAYER M3 ;
        RECT  43.74 129.562 43.758 129.6 ;
    END
  END a_d[256]
  PIN a_d[257]
    DIRECTION OUTPUT ;
    USE SIGNAL ;
    PORT
      LAYER M5 ;
        RECT  43.92 129.516 43.944 129.6 ;
    END
  END a_d[257]
  PIN a_d[258]
    DIRECTION OUTPUT ;
    USE SIGNAL ;
    PORT
      LAYER M3 ;
        RECT  44.1 129.562 44.118 129.6 ;
    END
  END a_d[258]
  PIN a_d[259]
    DIRECTION OUTPUT ;
    USE SIGNAL ;
    PORT
      LAYER M5 ;
        RECT  44.256 129.516 44.28 129.6 ;
    END
  END a_d[259]
  PIN a_d[25]
    DIRECTION OUTPUT ;
    USE SIGNAL ;
    PORT
      LAYER M5 ;
        RECT  4.848 129.516 4.872 129.6 ;
    END
  END a_d[25]
  PIN a_d[260]
    DIRECTION OUTPUT ;
    USE SIGNAL ;
    PORT
      LAYER M3 ;
        RECT  44.424 129.562 44.442 129.6 ;
    END
  END a_d[260]
  PIN a_d[261]
    DIRECTION OUTPUT ;
    USE SIGNAL ;
    PORT
      LAYER M5 ;
        RECT  44.592 129.516 44.616 129.6 ;
    END
  END a_d[261]
  PIN a_d[262]
    DIRECTION OUTPUT ;
    USE SIGNAL ;
    PORT
      LAYER M3 ;
        RECT  44.748 129.562 44.766 129.6 ;
    END
  END a_d[262]
  PIN a_d[263]
    DIRECTION OUTPUT ;
    USE SIGNAL ;
    PORT
      LAYER M5 ;
        RECT  44.928 129.516 44.952 129.6 ;
    END
  END a_d[263]
  PIN a_d[264]
    DIRECTION OUTPUT ;
    USE SIGNAL ;
    PORT
      LAYER M3 ;
        RECT  45.108 129.562 45.126 129.6 ;
    END
  END a_d[264]
  PIN a_d[265]
    DIRECTION OUTPUT ;
    USE SIGNAL ;
    PORT
      LAYER M5 ;
        RECT  45.264 129.516 45.288 129.6 ;
    END
  END a_d[265]
  PIN a_d[266]
    DIRECTION OUTPUT ;
    USE SIGNAL ;
    PORT
      LAYER M3 ;
        RECT  45.432 129.562 45.45 129.6 ;
    END
  END a_d[266]
  PIN a_d[267]
    DIRECTION OUTPUT ;
    USE SIGNAL ;
    PORT
      LAYER M5 ;
        RECT  45.6 129.516 45.624 129.6 ;
    END
  END a_d[267]
  PIN a_d[268]
    DIRECTION OUTPUT ;
    USE SIGNAL ;
    PORT
      LAYER M3 ;
        RECT  45.756 129.562 45.774 129.6 ;
    END
  END a_d[268]
  PIN a_d[269]
    DIRECTION OUTPUT ;
    USE SIGNAL ;
    PORT
      LAYER M5 ;
        RECT  45.936 129.516 45.96 129.6 ;
    END
  END a_d[269]
  PIN a_d[26]
    DIRECTION OUTPUT ;
    USE SIGNAL ;
    PORT
      LAYER M3 ;
        RECT  5.004 129.562 5.022 129.6 ;
    END
  END a_d[26]
  PIN a_d[270]
    DIRECTION OUTPUT ;
    USE SIGNAL ;
    PORT
      LAYER M3 ;
        RECT  46.116 129.562 46.134 129.6 ;
    END
  END a_d[270]
  PIN a_d[271]
    DIRECTION OUTPUT ;
    USE SIGNAL ;
    PORT
      LAYER M5 ;
        RECT  46.272 129.516 46.296 129.6 ;
    END
  END a_d[271]
  PIN a_d[272]
    DIRECTION OUTPUT ;
    USE SIGNAL ;
    PORT
      LAYER M3 ;
        RECT  46.44 129.562 46.458 129.6 ;
    END
  END a_d[272]
  PIN a_d[273]
    DIRECTION OUTPUT ;
    USE SIGNAL ;
    PORT
      LAYER M5 ;
        RECT  46.608 129.516 46.632 129.6 ;
    END
  END a_d[273]
  PIN a_d[274]
    DIRECTION OUTPUT ;
    USE SIGNAL ;
    PORT
      LAYER M3 ;
        RECT  46.764 129.562 46.782 129.6 ;
    END
  END a_d[274]
  PIN a_d[275]
    DIRECTION OUTPUT ;
    USE SIGNAL ;
    PORT
      LAYER M5 ;
        RECT  46.944 129.516 46.968 129.6 ;
    END
  END a_d[275]
  PIN a_d[276]
    DIRECTION OUTPUT ;
    USE SIGNAL ;
    PORT
      LAYER M3 ;
        RECT  47.124 129.562 47.142 129.6 ;
    END
  END a_d[276]
  PIN a_d[277]
    DIRECTION OUTPUT ;
    USE SIGNAL ;
    PORT
      LAYER M5 ;
        RECT  47.28 129.516 47.304 129.6 ;
    END
  END a_d[277]
  PIN a_d[278]
    DIRECTION OUTPUT ;
    USE SIGNAL ;
    PORT
      LAYER M3 ;
        RECT  47.448 129.562 47.466 129.6 ;
    END
  END a_d[278]
  PIN a_d[279]
    DIRECTION OUTPUT ;
    USE SIGNAL ;
    PORT
      LAYER M5 ;
        RECT  47.616 129.516 47.64 129.6 ;
    END
  END a_d[279]
  PIN a_d[27]
    DIRECTION OUTPUT ;
    USE SIGNAL ;
    PORT
      LAYER M5 ;
        RECT  5.184 129.516 5.208 129.6 ;
    END
  END a_d[27]
  PIN a_d[280]
    DIRECTION OUTPUT ;
    USE SIGNAL ;
    PORT
      LAYER M3 ;
        RECT  47.808 129.562 47.826 129.6 ;
    END
  END a_d[280]
  PIN a_d[281]
    DIRECTION OUTPUT ;
    USE SIGNAL ;
    PORT
      LAYER M5 ;
        RECT  47.952 129.516 47.976 129.6 ;
    END
  END a_d[281]
  PIN a_d[282]
    DIRECTION OUTPUT ;
    USE SIGNAL ;
    PORT
      LAYER M3 ;
        RECT  48.132 129.562 48.15 129.6 ;
    END
  END a_d[282]
  PIN a_d[283]
    DIRECTION OUTPUT ;
    USE SIGNAL ;
    PORT
      LAYER M5 ;
        RECT  48.288 129.516 48.312 129.6 ;
    END
  END a_d[283]
  PIN a_d[284]
    DIRECTION OUTPUT ;
    USE SIGNAL ;
    PORT
      LAYER M3 ;
        RECT  48.456 129.562 48.474 129.6 ;
    END
  END a_d[284]
  PIN a_d[285]
    DIRECTION OUTPUT ;
    USE SIGNAL ;
    PORT
      LAYER M5 ;
        RECT  48.624 129.516 48.648 129.6 ;
    END
  END a_d[285]
  PIN a_d[286]
    DIRECTION OUTPUT ;
    USE SIGNAL ;
    PORT
      LAYER M3 ;
        RECT  48.816 129.562 48.834 129.6 ;
    END
  END a_d[286]
  PIN a_d[287]
    DIRECTION OUTPUT ;
    USE SIGNAL ;
    PORT
      LAYER M5 ;
        RECT  48.96 129.516 48.984 129.6 ;
    END
  END a_d[287]
  PIN a_d[288]
    DIRECTION OUTPUT ;
    USE SIGNAL ;
    PORT
      LAYER M3 ;
        RECT  49.14 129.562 49.158 129.6 ;
    END
  END a_d[288]
  PIN a_d[289]
    DIRECTION OUTPUT ;
    USE SIGNAL ;
    PORT
      LAYER M5 ;
        RECT  49.296 129.516 49.32 129.6 ;
    END
  END a_d[289]
  PIN a_d[28]
    DIRECTION OUTPUT ;
    USE SIGNAL ;
    PORT
      LAYER M3 ;
        RECT  5.328 129.562 5.346 129.6 ;
    END
  END a_d[28]
  PIN a_d[290]
    DIRECTION OUTPUT ;
    USE SIGNAL ;
    PORT
      LAYER M3 ;
        RECT  49.464 129.562 49.482 129.6 ;
    END
  END a_d[290]
  PIN a_d[291]
    DIRECTION OUTPUT ;
    USE SIGNAL ;
    PORT
      LAYER M5 ;
        RECT  49.632 129.516 49.656 129.6 ;
    END
  END a_d[291]
  PIN a_d[292]
    DIRECTION OUTPUT ;
    USE SIGNAL ;
    PORT
      LAYER M3 ;
        RECT  49.824 129.562 49.842 129.6 ;
    END
  END a_d[292]
  PIN a_d[293]
    DIRECTION OUTPUT ;
    USE SIGNAL ;
    PORT
      LAYER M5 ;
        RECT  49.968 129.516 49.992 129.6 ;
    END
  END a_d[293]
  PIN a_d[294]
    DIRECTION OUTPUT ;
    USE SIGNAL ;
    PORT
      LAYER M3 ;
        RECT  50.148 129.562 50.166 129.6 ;
    END
  END a_d[294]
  PIN a_d[295]
    DIRECTION OUTPUT ;
    USE SIGNAL ;
    PORT
      LAYER M5 ;
        RECT  50.304 129.516 50.328 129.6 ;
    END
  END a_d[295]
  PIN a_d[296]
    DIRECTION OUTPUT ;
    USE SIGNAL ;
    PORT
      LAYER M3 ;
        RECT  50.472 129.562 50.49 129.6 ;
    END
  END a_d[296]
  PIN a_d[297]
    DIRECTION OUTPUT ;
    USE SIGNAL ;
    PORT
      LAYER M5 ;
        RECT  50.64 129.516 50.664 129.6 ;
    END
  END a_d[297]
  PIN a_d[298]
    DIRECTION OUTPUT ;
    USE SIGNAL ;
    PORT
      LAYER M3 ;
        RECT  50.832 129.562 50.85 129.6 ;
    END
  END a_d[298]
  PIN a_d[299]
    DIRECTION OUTPUT ;
    USE SIGNAL ;
    PORT
      LAYER M5 ;
        RECT  50.976 129.516 51 129.6 ;
    END
  END a_d[299]
  PIN a_d[29]
    DIRECTION OUTPUT ;
    USE SIGNAL ;
    PORT
      LAYER M5 ;
        RECT  5.52 129.516 5.544 129.6 ;
    END
  END a_d[29]
  PIN a_d[2]
    DIRECTION OUTPUT ;
    USE SIGNAL ;
    PORT
      LAYER M3 ;
        RECT  0.936 129.562 0.954 129.6 ;
    END
  END a_d[2]
  PIN a_d[300]
    DIRECTION OUTPUT ;
    USE SIGNAL ;
    PORT
      LAYER M3 ;
        RECT  51.156 129.562 51.174 129.6 ;
    END
  END a_d[300]
  PIN a_d[301]
    DIRECTION OUTPUT ;
    USE SIGNAL ;
    PORT
      LAYER M5 ;
        RECT  51.312 129.516 51.336 129.6 ;
    END
  END a_d[301]
  PIN a_d[302]
    DIRECTION OUTPUT ;
    USE SIGNAL ;
    PORT
      LAYER M3 ;
        RECT  51.516 129.562 51.534 129.6 ;
    END
  END a_d[302]
  PIN a_d[303]
    DIRECTION OUTPUT ;
    USE SIGNAL ;
    PORT
      LAYER M5 ;
        RECT  51.648 129.516 51.672 129.6 ;
    END
  END a_d[303]
  PIN a_d[304]
    DIRECTION OUTPUT ;
    USE SIGNAL ;
    PORT
      LAYER M3 ;
        RECT  51.84 129.562 51.858 129.6 ;
    END
  END a_d[304]
  PIN a_d[305]
    DIRECTION OUTPUT ;
    USE SIGNAL ;
    PORT
      LAYER M5 ;
        RECT  51.984 129.516 52.008 129.6 ;
    END
  END a_d[305]
  PIN a_d[306]
    DIRECTION OUTPUT ;
    USE SIGNAL ;
    PORT
      LAYER M3 ;
        RECT  52.164 129.562 52.182 129.6 ;
    END
  END a_d[306]
  PIN a_d[307]
    DIRECTION OUTPUT ;
    USE SIGNAL ;
    PORT
      LAYER M5 ;
        RECT  52.32 129.516 52.344 129.6 ;
    END
  END a_d[307]
  PIN a_d[308]
    DIRECTION OUTPUT ;
    USE SIGNAL ;
    PORT
      LAYER M3 ;
        RECT  52.524 129.562 52.542 129.6 ;
    END
  END a_d[308]
  PIN a_d[309]
    DIRECTION OUTPUT ;
    USE SIGNAL ;
    PORT
      LAYER M5 ;
        RECT  52.656 129.516 52.68 129.6 ;
    END
  END a_d[309]
  PIN a_d[30]
    DIRECTION OUTPUT ;
    USE SIGNAL ;
    PORT
      LAYER M3 ;
        RECT  5.688 129.562 5.706 129.6 ;
    END
  END a_d[30]
  PIN a_d[310]
    DIRECTION OUTPUT ;
    USE SIGNAL ;
    PORT
      LAYER M3 ;
        RECT  52.848 129.562 52.866 129.6 ;
    END
  END a_d[310]
  PIN a_d[311]
    DIRECTION OUTPUT ;
    USE SIGNAL ;
    PORT
      LAYER M5 ;
        RECT  52.992 129.516 53.016 129.6 ;
    END
  END a_d[311]
  PIN a_d[312]
    DIRECTION OUTPUT ;
    USE SIGNAL ;
    PORT
      LAYER M3 ;
        RECT  53.172 129.562 53.19 129.6 ;
    END
  END a_d[312]
  PIN a_d[313]
    DIRECTION OUTPUT ;
    USE SIGNAL ;
    PORT
      LAYER M5 ;
        RECT  53.328 129.516 53.352 129.6 ;
    END
  END a_d[313]
  PIN a_d[314]
    DIRECTION OUTPUT ;
    USE SIGNAL ;
    PORT
      LAYER M3 ;
        RECT  53.532 129.562 53.55 129.6 ;
    END
  END a_d[314]
  PIN a_d[315]
    DIRECTION OUTPUT ;
    USE SIGNAL ;
    PORT
      LAYER M5 ;
        RECT  53.664 129.516 53.688 129.6 ;
    END
  END a_d[315]
  PIN a_d[316]
    DIRECTION OUTPUT ;
    USE SIGNAL ;
    PORT
      LAYER M3 ;
        RECT  53.856 129.562 53.874 129.6 ;
    END
  END a_d[316]
  PIN a_d[317]
    DIRECTION OUTPUT ;
    USE SIGNAL ;
    PORT
      LAYER M5 ;
        RECT  54 129.516 54.024 129.6 ;
    END
  END a_d[317]
  PIN a_d[318]
    DIRECTION OUTPUT ;
    USE SIGNAL ;
    PORT
      LAYER M3 ;
        RECT  54.18 129.562 54.198 129.6 ;
    END
  END a_d[318]
  PIN a_d[319]
    DIRECTION OUTPUT ;
    USE SIGNAL ;
    PORT
      LAYER M5 ;
        RECT  54.384 129.516 54.408 129.6 ;
    END
  END a_d[319]
  PIN a_d[31]
    DIRECTION OUTPUT ;
    USE SIGNAL ;
    PORT
      LAYER M5 ;
        RECT  5.856 129.516 5.88 129.6 ;
    END
  END a_d[31]
  PIN a_d[320]
    DIRECTION OUTPUT ;
    USE SIGNAL ;
    PORT
      LAYER M3 ;
        RECT  54.54 129.562 54.558 129.6 ;
    END
  END a_d[320]
  PIN a_d[321]
    DIRECTION OUTPUT ;
    USE SIGNAL ;
    PORT
      LAYER M5 ;
        RECT  54.72 129.516 54.744 129.6 ;
    END
  END a_d[321]
  PIN a_d[322]
    DIRECTION OUTPUT ;
    USE SIGNAL ;
    PORT
      LAYER M3 ;
        RECT  54.864 129.562 54.882 129.6 ;
    END
  END a_d[322]
  PIN a_d[323]
    DIRECTION OUTPUT ;
    USE SIGNAL ;
    PORT
      LAYER M5 ;
        RECT  55.056 129.516 55.08 129.6 ;
    END
  END a_d[323]
  PIN a_d[324]
    DIRECTION OUTPUT ;
    USE SIGNAL ;
    PORT
      LAYER M3 ;
        RECT  55.188 129.562 55.206 129.6 ;
    END
  END a_d[324]
  PIN a_d[325]
    DIRECTION OUTPUT ;
    USE SIGNAL ;
    PORT
      LAYER M5 ;
        RECT  55.392 129.516 55.416 129.6 ;
    END
  END a_d[325]
  PIN a_d[326]
    DIRECTION OUTPUT ;
    USE SIGNAL ;
    PORT
      LAYER M3 ;
        RECT  55.548 129.562 55.566 129.6 ;
    END
  END a_d[326]
  PIN a_d[327]
    DIRECTION OUTPUT ;
    USE SIGNAL ;
    PORT
      LAYER M5 ;
        RECT  55.728 129.516 55.752 129.6 ;
    END
  END a_d[327]
  PIN a_d[328]
    DIRECTION OUTPUT ;
    USE SIGNAL ;
    PORT
      LAYER M3 ;
        RECT  55.872 129.562 55.89 129.6 ;
    END
  END a_d[328]
  PIN a_d[329]
    DIRECTION OUTPUT ;
    USE SIGNAL ;
    PORT
      LAYER M5 ;
        RECT  56.064 129.516 56.088 129.6 ;
    END
  END a_d[329]
  PIN a_d[32]
    DIRECTION OUTPUT ;
    USE SIGNAL ;
    PORT
      LAYER M3 ;
        RECT  6.012 129.562 6.03 129.6 ;
    END
  END a_d[32]
  PIN a_d[330]
    DIRECTION OUTPUT ;
    USE SIGNAL ;
    PORT
      LAYER M3 ;
        RECT  56.232 129.562 56.25 129.6 ;
    END
  END a_d[330]
  PIN a_d[331]
    DIRECTION OUTPUT ;
    USE SIGNAL ;
    PORT
      LAYER M5 ;
        RECT  56.4 129.516 56.424 129.6 ;
    END
  END a_d[331]
  PIN a_d[332]
    DIRECTION OUTPUT ;
    USE SIGNAL ;
    PORT
      LAYER M3 ;
        RECT  56.556 129.562 56.574 129.6 ;
    END
  END a_d[332]
  PIN a_d[333]
    DIRECTION OUTPUT ;
    USE SIGNAL ;
    PORT
      LAYER M5 ;
        RECT  56.736 129.516 56.76 129.6 ;
    END
  END a_d[333]
  PIN a_d[334]
    DIRECTION OUTPUT ;
    USE SIGNAL ;
    PORT
      LAYER M3 ;
        RECT  56.88 129.562 56.898 129.6 ;
    END
  END a_d[334]
  PIN a_d[335]
    DIRECTION OUTPUT ;
    USE SIGNAL ;
    PORT
      LAYER M5 ;
        RECT  57.072 129.516 57.096 129.6 ;
    END
  END a_d[335]
  PIN a_d[336]
    DIRECTION OUTPUT ;
    USE SIGNAL ;
    PORT
      LAYER M3 ;
        RECT  57.24 129.562 57.258 129.6 ;
    END
  END a_d[336]
  PIN a_d[337]
    DIRECTION OUTPUT ;
    USE SIGNAL ;
    PORT
      LAYER M5 ;
        RECT  57.408 129.516 57.432 129.6 ;
    END
  END a_d[337]
  PIN a_d[338]
    DIRECTION OUTPUT ;
    USE SIGNAL ;
    PORT
      LAYER M3 ;
        RECT  57.564 129.562 57.582 129.6 ;
    END
  END a_d[338]
  PIN a_d[339]
    DIRECTION OUTPUT ;
    USE SIGNAL ;
    PORT
      LAYER M5 ;
        RECT  57.744 129.516 57.768 129.6 ;
    END
  END a_d[339]
  PIN a_d[33]
    DIRECTION OUTPUT ;
    USE SIGNAL ;
    PORT
      LAYER M5 ;
        RECT  6.192 129.516 6.216 129.6 ;
    END
  END a_d[33]
  PIN a_d[340]
    DIRECTION OUTPUT ;
    USE SIGNAL ;
    PORT
      LAYER M3 ;
        RECT  57.888 129.562 57.906 129.6 ;
    END
  END a_d[340]
  PIN a_d[341]
    DIRECTION OUTPUT ;
    USE SIGNAL ;
    PORT
      LAYER M5 ;
        RECT  58.08 129.516 58.104 129.6 ;
    END
  END a_d[341]
  PIN a_d[342]
    DIRECTION OUTPUT ;
    USE SIGNAL ;
    PORT
      LAYER M3 ;
        RECT  58.248 129.562 58.266 129.6 ;
    END
  END a_d[342]
  PIN a_d[343]
    DIRECTION OUTPUT ;
    USE SIGNAL ;
    PORT
      LAYER M5 ;
        RECT  58.416 129.516 58.44 129.6 ;
    END
  END a_d[343]
  PIN a_d[344]
    DIRECTION OUTPUT ;
    USE SIGNAL ;
    PORT
      LAYER M3 ;
        RECT  58.572 129.562 58.59 129.6 ;
    END
  END a_d[344]
  PIN a_d[345]
    DIRECTION OUTPUT ;
    USE SIGNAL ;
    PORT
      LAYER M5 ;
        RECT  58.752 129.516 58.776 129.6 ;
    END
  END a_d[345]
  PIN a_d[346]
    DIRECTION OUTPUT ;
    USE SIGNAL ;
    PORT
      LAYER M3 ;
        RECT  58.896 129.562 58.914 129.6 ;
    END
  END a_d[346]
  PIN a_d[347]
    DIRECTION OUTPUT ;
    USE SIGNAL ;
    PORT
      LAYER M5 ;
        RECT  59.088 129.516 59.112 129.6 ;
    END
  END a_d[347]
  PIN a_d[348]
    DIRECTION OUTPUT ;
    USE SIGNAL ;
    PORT
      LAYER M3 ;
        RECT  59.256 129.562 59.274 129.6 ;
    END
  END a_d[348]
  PIN a_d[349]
    DIRECTION OUTPUT ;
    USE SIGNAL ;
    PORT
      LAYER M5 ;
        RECT  59.424 129.516 59.448 129.6 ;
    END
  END a_d[349]
  PIN a_d[34]
    DIRECTION OUTPUT ;
    USE SIGNAL ;
    PORT
      LAYER M3 ;
        RECT  6.336 129.562 6.354 129.6 ;
    END
  END a_d[34]
  PIN a_d[350]
    DIRECTION OUTPUT ;
    USE SIGNAL ;
    PORT
      LAYER M3 ;
        RECT  59.58 129.562 59.598 129.6 ;
    END
  END a_d[350]
  PIN a_d[351]
    DIRECTION OUTPUT ;
    USE SIGNAL ;
    PORT
      LAYER M5 ;
        RECT  59.76 129.516 59.784 129.6 ;
    END
  END a_d[351]
  PIN a_d[352]
    DIRECTION OUTPUT ;
    USE SIGNAL ;
    PORT
      LAYER M3 ;
        RECT  59.94 129.562 59.958 129.6 ;
    END
  END a_d[352]
  PIN a_d[353]
    DIRECTION OUTPUT ;
    USE SIGNAL ;
    PORT
      LAYER M5 ;
        RECT  60.096 129.516 60.12 129.6 ;
    END
  END a_d[353]
  PIN a_d[354]
    DIRECTION OUTPUT ;
    USE SIGNAL ;
    PORT
      LAYER M3 ;
        RECT  60.264 129.562 60.282 129.6 ;
    END
  END a_d[354]
  PIN a_d[355]
    DIRECTION OUTPUT ;
    USE SIGNAL ;
    PORT
      LAYER M5 ;
        RECT  60.432 129.516 60.456 129.6 ;
    END
  END a_d[355]
  PIN a_d[356]
    DIRECTION OUTPUT ;
    USE SIGNAL ;
    PORT
      LAYER M3 ;
        RECT  60.588 129.562 60.606 129.6 ;
    END
  END a_d[356]
  PIN a_d[357]
    DIRECTION OUTPUT ;
    USE SIGNAL ;
    PORT
      LAYER M5 ;
        RECT  60.768 129.516 60.792 129.6 ;
    END
  END a_d[357]
  PIN a_d[358]
    DIRECTION OUTPUT ;
    USE SIGNAL ;
    PORT
      LAYER M3 ;
        RECT  60.948 129.562 60.966 129.6 ;
    END
  END a_d[358]
  PIN a_d[359]
    DIRECTION OUTPUT ;
    USE SIGNAL ;
    PORT
      LAYER M5 ;
        RECT  61.104 129.516 61.128 129.6 ;
    END
  END a_d[359]
  PIN a_d[35]
    DIRECTION OUTPUT ;
    USE SIGNAL ;
    PORT
      LAYER M5 ;
        RECT  6.528 129.516 6.552 129.6 ;
    END
  END a_d[35]
  PIN a_d[360]
    DIRECTION OUTPUT ;
    USE SIGNAL ;
    PORT
      LAYER M3 ;
        RECT  61.272 129.562 61.29 129.6 ;
    END
  END a_d[360]
  PIN a_d[361]
    DIRECTION OUTPUT ;
    USE SIGNAL ;
    PORT
      LAYER M5 ;
        RECT  61.44 129.516 61.464 129.6 ;
    END
  END a_d[361]
  PIN a_d[362]
    DIRECTION OUTPUT ;
    USE SIGNAL ;
    PORT
      LAYER M3 ;
        RECT  61.596 129.562 61.614 129.6 ;
    END
  END a_d[362]
  PIN a_d[363]
    DIRECTION OUTPUT ;
    USE SIGNAL ;
    PORT
      LAYER M5 ;
        RECT  61.776 129.516 61.8 129.6 ;
    END
  END a_d[363]
  PIN a_d[364]
    DIRECTION OUTPUT ;
    USE SIGNAL ;
    PORT
      LAYER M3 ;
        RECT  61.956 129.562 61.974 129.6 ;
    END
  END a_d[364]
  PIN a_d[365]
    DIRECTION OUTPUT ;
    USE SIGNAL ;
    PORT
      LAYER M5 ;
        RECT  62.112 129.516 62.136 129.6 ;
    END
  END a_d[365]
  PIN a_d[366]
    DIRECTION OUTPUT ;
    USE SIGNAL ;
    PORT
      LAYER M3 ;
        RECT  62.28 129.562 62.298 129.6 ;
    END
  END a_d[366]
  PIN a_d[367]
    DIRECTION OUTPUT ;
    USE SIGNAL ;
    PORT
      LAYER M5 ;
        RECT  62.448 129.516 62.472 129.6 ;
    END
  END a_d[367]
  PIN a_d[368]
    DIRECTION OUTPUT ;
    USE SIGNAL ;
    PORT
      LAYER M3 ;
        RECT  62.604 129.562 62.622 129.6 ;
    END
  END a_d[368]
  PIN a_d[369]
    DIRECTION OUTPUT ;
    USE SIGNAL ;
    PORT
      LAYER M5 ;
        RECT  62.784 129.516 62.808 129.6 ;
    END
  END a_d[369]
  PIN a_d[36]
    DIRECTION OUTPUT ;
    USE SIGNAL ;
    PORT
      LAYER M3 ;
        RECT  6.696 129.562 6.714 129.6 ;
    END
  END a_d[36]
  PIN a_d[370]
    DIRECTION OUTPUT ;
    USE SIGNAL ;
    PORT
      LAYER M3 ;
        RECT  62.964 129.562 62.982 129.6 ;
    END
  END a_d[370]
  PIN a_d[371]
    DIRECTION OUTPUT ;
    USE SIGNAL ;
    PORT
      LAYER M5 ;
        RECT  63.12 129.516 63.144 129.6 ;
    END
  END a_d[371]
  PIN a_d[372]
    DIRECTION OUTPUT ;
    USE SIGNAL ;
    PORT
      LAYER M3 ;
        RECT  63.288 129.562 63.306 129.6 ;
    END
  END a_d[372]
  PIN a_d[373]
    DIRECTION OUTPUT ;
    USE SIGNAL ;
    PORT
      LAYER M5 ;
        RECT  63.456 129.516 63.48 129.6 ;
    END
  END a_d[373]
  PIN a_d[374]
    DIRECTION OUTPUT ;
    USE SIGNAL ;
    PORT
      LAYER M3 ;
        RECT  63.648 129.562 63.666 129.6 ;
    END
  END a_d[374]
  PIN a_d[375]
    DIRECTION OUTPUT ;
    USE SIGNAL ;
    PORT
      LAYER M5 ;
        RECT  63.792 129.516 63.816 129.6 ;
    END
  END a_d[375]
  PIN a_d[376]
    DIRECTION OUTPUT ;
    USE SIGNAL ;
    PORT
      LAYER M3 ;
        RECT  63.972 129.562 63.99 129.6 ;
    END
  END a_d[376]
  PIN a_d[377]
    DIRECTION OUTPUT ;
    USE SIGNAL ;
    PORT
      LAYER M5 ;
        RECT  64.128 129.516 64.152 129.6 ;
    END
  END a_d[377]
  PIN a_d[378]
    DIRECTION OUTPUT ;
    USE SIGNAL ;
    PORT
      LAYER M3 ;
        RECT  64.296 129.562 64.314 129.6 ;
    END
  END a_d[378]
  PIN a_d[379]
    DIRECTION OUTPUT ;
    USE SIGNAL ;
    PORT
      LAYER M5 ;
        RECT  64.464 129.516 64.488 129.6 ;
    END
  END a_d[379]
  PIN a_d[37]
    DIRECTION OUTPUT ;
    USE SIGNAL ;
    PORT
      LAYER M5 ;
        RECT  6.864 129.516 6.888 129.6 ;
    END
  END a_d[37]
  PIN a_d[380]
    DIRECTION OUTPUT ;
    USE SIGNAL ;
    PORT
      LAYER M3 ;
        RECT  64.656 129.562 64.674 129.6 ;
    END
  END a_d[380]
  PIN a_d[381]
    DIRECTION OUTPUT ;
    USE SIGNAL ;
    PORT
      LAYER M5 ;
        RECT  64.8 129.516 64.824 129.6 ;
    END
  END a_d[381]
  PIN a_d[382]
    DIRECTION OUTPUT ;
    USE SIGNAL ;
    PORT
      LAYER M3 ;
        RECT  64.98 129.562 64.998 129.6 ;
    END
  END a_d[382]
  PIN a_d[383]
    DIRECTION OUTPUT ;
    USE SIGNAL ;
    PORT
      LAYER M5 ;
        RECT  65.136 129.516 65.16 129.6 ;
    END
  END a_d[383]
  PIN a_d[384]
    DIRECTION OUTPUT ;
    USE SIGNAL ;
    PORT
      LAYER M3 ;
        RECT  65.304 129.562 65.322 129.6 ;
    END
  END a_d[384]
  PIN a_d[385]
    DIRECTION OUTPUT ;
    USE SIGNAL ;
    PORT
      LAYER M5 ;
        RECT  65.472 129.516 65.496 129.6 ;
    END
  END a_d[385]
  PIN a_d[386]
    DIRECTION OUTPUT ;
    USE SIGNAL ;
    PORT
      LAYER M3 ;
        RECT  65.664 129.562 65.682 129.6 ;
    END
  END a_d[386]
  PIN a_d[387]
    DIRECTION OUTPUT ;
    USE SIGNAL ;
    PORT
      LAYER M5 ;
        RECT  65.808 129.516 65.832 129.6 ;
    END
  END a_d[387]
  PIN a_d[388]
    DIRECTION OUTPUT ;
    USE SIGNAL ;
    PORT
      LAYER M3 ;
        RECT  65.988 129.562 66.006 129.6 ;
    END
  END a_d[388]
  PIN a_d[389]
    DIRECTION OUTPUT ;
    USE SIGNAL ;
    PORT
      LAYER M5 ;
        RECT  66.144 129.516 66.168 129.6 ;
    END
  END a_d[389]
  PIN a_d[38]
    DIRECTION OUTPUT ;
    USE SIGNAL ;
    PORT
      LAYER M3 ;
        RECT  7.02 129.562 7.038 129.6 ;
    END
  END a_d[38]
  PIN a_d[390]
    DIRECTION OUTPUT ;
    USE SIGNAL ;
    PORT
      LAYER M3 ;
        RECT  66.312 129.562 66.33 129.6 ;
    END
  END a_d[390]
  PIN a_d[391]
    DIRECTION OUTPUT ;
    USE SIGNAL ;
    PORT
      LAYER M5 ;
        RECT  66.48 129.516 66.504 129.6 ;
    END
  END a_d[391]
  PIN a_d[392]
    DIRECTION OUTPUT ;
    USE SIGNAL ;
    PORT
      LAYER M3 ;
        RECT  66.672 129.562 66.69 129.6 ;
    END
  END a_d[392]
  PIN a_d[393]
    DIRECTION OUTPUT ;
    USE SIGNAL ;
    PORT
      LAYER M5 ;
        RECT  66.816 129.516 66.84 129.6 ;
    END
  END a_d[393]
  PIN a_d[394]
    DIRECTION OUTPUT ;
    USE SIGNAL ;
    PORT
      LAYER M3 ;
        RECT  66.996 129.562 67.014 129.6 ;
    END
  END a_d[394]
  PIN a_d[395]
    DIRECTION OUTPUT ;
    USE SIGNAL ;
    PORT
      LAYER M5 ;
        RECT  67.152 129.516 67.176 129.6 ;
    END
  END a_d[395]
  PIN a_d[396]
    DIRECTION OUTPUT ;
    USE SIGNAL ;
    PORT
      LAYER M3 ;
        RECT  67.32 129.562 67.338 129.6 ;
    END
  END a_d[396]
  PIN a_d[397]
    DIRECTION OUTPUT ;
    USE SIGNAL ;
    PORT
      LAYER M5 ;
        RECT  67.488 129.516 67.512 129.6 ;
    END
  END a_d[397]
  PIN a_d[398]
    DIRECTION OUTPUT ;
    USE SIGNAL ;
    PORT
      LAYER M3 ;
        RECT  67.68 129.562 67.698 129.6 ;
    END
  END a_d[398]
  PIN a_d[399]
    DIRECTION OUTPUT ;
    USE SIGNAL ;
    PORT
      LAYER M5 ;
        RECT  67.824 129.516 67.848 129.6 ;
    END
  END a_d[399]
  PIN a_d[39]
    DIRECTION OUTPUT ;
    USE SIGNAL ;
    PORT
      LAYER M5 ;
        RECT  7.2 129.516 7.224 129.6 ;
    END
  END a_d[39]
  PIN a_d[3]
    DIRECTION OUTPUT ;
    USE SIGNAL ;
    PORT
      LAYER M5 ;
        RECT  1.104 129.516 1.128 129.6 ;
    END
  END a_d[3]
  PIN a_d[400]
    DIRECTION OUTPUT ;
    USE SIGNAL ;
    PORT
      LAYER M3 ;
        RECT  68.004 129.562 68.022 129.6 ;
    END
  END a_d[400]
  PIN a_d[401]
    DIRECTION OUTPUT ;
    USE SIGNAL ;
    PORT
      LAYER M5 ;
        RECT  68.16 129.516 68.184 129.6 ;
    END
  END a_d[401]
  PIN a_d[402]
    DIRECTION OUTPUT ;
    USE SIGNAL ;
    PORT
      LAYER M3 ;
        RECT  68.364 129.562 68.382 129.6 ;
    END
  END a_d[402]
  PIN a_d[403]
    DIRECTION OUTPUT ;
    USE SIGNAL ;
    PORT
      LAYER M5 ;
        RECT  68.496 129.516 68.52 129.6 ;
    END
  END a_d[403]
  PIN a_d[404]
    DIRECTION OUTPUT ;
    USE SIGNAL ;
    PORT
      LAYER M3 ;
        RECT  68.688 129.562 68.706 129.6 ;
    END
  END a_d[404]
  PIN a_d[405]
    DIRECTION OUTPUT ;
    USE SIGNAL ;
    PORT
      LAYER M5 ;
        RECT  68.832 129.516 68.856 129.6 ;
    END
  END a_d[405]
  PIN a_d[406]
    DIRECTION OUTPUT ;
    USE SIGNAL ;
    PORT
      LAYER M3 ;
        RECT  69.012 129.562 69.03 129.6 ;
    END
  END a_d[406]
  PIN a_d[407]
    DIRECTION OUTPUT ;
    USE SIGNAL ;
    PORT
      LAYER M5 ;
        RECT  69.168 129.516 69.192 129.6 ;
    END
  END a_d[407]
  PIN a_d[408]
    DIRECTION OUTPUT ;
    USE SIGNAL ;
    PORT
      LAYER M3 ;
        RECT  69.372 129.562 69.39 129.6 ;
    END
  END a_d[408]
  PIN a_d[409]
    DIRECTION OUTPUT ;
    USE SIGNAL ;
    PORT
      LAYER M5 ;
        RECT  69.504 129.516 69.528 129.6 ;
    END
  END a_d[409]
  PIN a_d[40]
    DIRECTION OUTPUT ;
    USE SIGNAL ;
    PORT
      LAYER M3 ;
        RECT  7.344 129.562 7.362 129.6 ;
    END
  END a_d[40]
  PIN a_d[410]
    DIRECTION OUTPUT ;
    USE SIGNAL ;
    PORT
      LAYER M3 ;
        RECT  69.696 129.562 69.714 129.6 ;
    END
  END a_d[410]
  PIN a_d[411]
    DIRECTION OUTPUT ;
    USE SIGNAL ;
    PORT
      LAYER M5 ;
        RECT  69.84 129.516 69.864 129.6 ;
    END
  END a_d[411]
  PIN a_d[412]
    DIRECTION OUTPUT ;
    USE SIGNAL ;
    PORT
      LAYER M3 ;
        RECT  70.02 129.562 70.038 129.6 ;
    END
  END a_d[412]
  PIN a_d[413]
    DIRECTION OUTPUT ;
    USE SIGNAL ;
    PORT
      LAYER M5 ;
        RECT  70.176 129.516 70.2 129.6 ;
    END
  END a_d[413]
  PIN a_d[414]
    DIRECTION OUTPUT ;
    USE SIGNAL ;
    PORT
      LAYER M3 ;
        RECT  70.38 129.562 70.398 129.6 ;
    END
  END a_d[414]
  PIN a_d[415]
    DIRECTION OUTPUT ;
    USE SIGNAL ;
    PORT
      LAYER M5 ;
        RECT  70.512 129.516 70.536 129.6 ;
    END
  END a_d[415]
  PIN a_d[416]
    DIRECTION OUTPUT ;
    USE SIGNAL ;
    PORT
      LAYER M3 ;
        RECT  70.704 129.562 70.722 129.6 ;
    END
  END a_d[416]
  PIN a_d[417]
    DIRECTION OUTPUT ;
    USE SIGNAL ;
    PORT
      LAYER M5 ;
        RECT  70.896 129.516 70.92 129.6 ;
    END
  END a_d[417]
  PIN a_d[418]
    DIRECTION OUTPUT ;
    USE SIGNAL ;
    PORT
      LAYER M3 ;
        RECT  71.028 129.562 71.046 129.6 ;
    END
  END a_d[418]
  PIN a_d[419]
    DIRECTION OUTPUT ;
    USE SIGNAL ;
    PORT
      LAYER M5 ;
        RECT  71.232 129.516 71.256 129.6 ;
    END
  END a_d[419]
  PIN a_d[41]
    DIRECTION OUTPUT ;
    USE SIGNAL ;
    PORT
      LAYER M5 ;
        RECT  7.536 129.516 7.56 129.6 ;
    END
  END a_d[41]
  PIN a_d[420]
    DIRECTION OUTPUT ;
    USE SIGNAL ;
    PORT
      LAYER M3 ;
        RECT  71.388 129.562 71.406 129.6 ;
    END
  END a_d[420]
  PIN a_d[421]
    DIRECTION OUTPUT ;
    USE SIGNAL ;
    PORT
      LAYER M5 ;
        RECT  71.568 129.516 71.592 129.6 ;
    END
  END a_d[421]
  PIN a_d[422]
    DIRECTION OUTPUT ;
    USE SIGNAL ;
    PORT
      LAYER M3 ;
        RECT  71.712 129.562 71.73 129.6 ;
    END
  END a_d[422]
  PIN a_d[423]
    DIRECTION OUTPUT ;
    USE SIGNAL ;
    PORT
      LAYER M5 ;
        RECT  71.904 129.516 71.928 129.6 ;
    END
  END a_d[423]
  PIN a_d[424]
    DIRECTION OUTPUT ;
    USE SIGNAL ;
    PORT
      LAYER M3 ;
        RECT  72.072 129.562 72.09 129.6 ;
    END
  END a_d[424]
  PIN a_d[425]
    DIRECTION OUTPUT ;
    USE SIGNAL ;
    PORT
      LAYER M5 ;
        RECT  72.24 129.516 72.264 129.6 ;
    END
  END a_d[425]
  PIN a_d[426]
    DIRECTION OUTPUT ;
    USE SIGNAL ;
    PORT
      LAYER M3 ;
        RECT  72.396 129.562 72.414 129.6 ;
    END
  END a_d[426]
  PIN a_d[427]
    DIRECTION OUTPUT ;
    USE SIGNAL ;
    PORT
      LAYER M5 ;
        RECT  72.576 129.516 72.6 129.6 ;
    END
  END a_d[427]
  PIN a_d[428]
    DIRECTION OUTPUT ;
    USE SIGNAL ;
    PORT
      LAYER M3 ;
        RECT  72.72 129.562 72.738 129.6 ;
    END
  END a_d[428]
  PIN a_d[429]
    DIRECTION OUTPUT ;
    USE SIGNAL ;
    PORT
      LAYER M5 ;
        RECT  72.912 129.516 72.936 129.6 ;
    END
  END a_d[429]
  PIN a_d[42]
    DIRECTION OUTPUT ;
    USE SIGNAL ;
    PORT
      LAYER M3 ;
        RECT  7.704 129.562 7.722 129.6 ;
    END
  END a_d[42]
  PIN a_d[430]
    DIRECTION OUTPUT ;
    USE SIGNAL ;
    PORT
      LAYER M3 ;
        RECT  73.08 129.562 73.098 129.6 ;
    END
  END a_d[430]
  PIN a_d[431]
    DIRECTION OUTPUT ;
    USE SIGNAL ;
    PORT
      LAYER M5 ;
        RECT  73.248 129.516 73.272 129.6 ;
    END
  END a_d[431]
  PIN a_d[432]
    DIRECTION OUTPUT ;
    USE SIGNAL ;
    PORT
      LAYER M3 ;
        RECT  73.404 129.562 73.422 129.6 ;
    END
  END a_d[432]
  PIN a_d[433]
    DIRECTION OUTPUT ;
    USE SIGNAL ;
    PORT
      LAYER M5 ;
        RECT  73.584 129.516 73.608 129.6 ;
    END
  END a_d[433]
  PIN a_d[434]
    DIRECTION OUTPUT ;
    USE SIGNAL ;
    PORT
      LAYER M3 ;
        RECT  73.728 129.562 73.746 129.6 ;
    END
  END a_d[434]
  PIN a_d[435]
    DIRECTION OUTPUT ;
    USE SIGNAL ;
    PORT
      LAYER M5 ;
        RECT  73.92 129.516 73.944 129.6 ;
    END
  END a_d[435]
  PIN a_d[436]
    DIRECTION OUTPUT ;
    USE SIGNAL ;
    PORT
      LAYER M3 ;
        RECT  74.088 129.562 74.106 129.6 ;
    END
  END a_d[436]
  PIN a_d[437]
    DIRECTION OUTPUT ;
    USE SIGNAL ;
    PORT
      LAYER M5 ;
        RECT  74.256 129.516 74.28 129.6 ;
    END
  END a_d[437]
  PIN a_d[438]
    DIRECTION OUTPUT ;
    USE SIGNAL ;
    PORT
      LAYER M3 ;
        RECT  74.412 129.562 74.43 129.6 ;
    END
  END a_d[438]
  PIN a_d[439]
    DIRECTION OUTPUT ;
    USE SIGNAL ;
    PORT
      LAYER M5 ;
        RECT  74.592 129.516 74.616 129.6 ;
    END
  END a_d[439]
  PIN a_d[43]
    DIRECTION OUTPUT ;
    USE SIGNAL ;
    PORT
      LAYER M5 ;
        RECT  7.872 129.516 7.896 129.6 ;
    END
  END a_d[43]
  PIN a_d[440]
    DIRECTION OUTPUT ;
    USE SIGNAL ;
    PORT
      LAYER M3 ;
        RECT  74.736 129.562 74.754 129.6 ;
    END
  END a_d[440]
  PIN a_d[441]
    DIRECTION OUTPUT ;
    USE SIGNAL ;
    PORT
      LAYER M5 ;
        RECT  74.928 129.516 74.952 129.6 ;
    END
  END a_d[441]
  PIN a_d[442]
    DIRECTION OUTPUT ;
    USE SIGNAL ;
    PORT
      LAYER M3 ;
        RECT  75.096 129.562 75.114 129.6 ;
    END
  END a_d[442]
  PIN a_d[443]
    DIRECTION OUTPUT ;
    USE SIGNAL ;
    PORT
      LAYER M5 ;
        RECT  75.264 129.516 75.288 129.6 ;
    END
  END a_d[443]
  PIN a_d[444]
    DIRECTION OUTPUT ;
    USE SIGNAL ;
    PORT
      LAYER M3 ;
        RECT  75.42 129.562 75.438 129.6 ;
    END
  END a_d[444]
  PIN a_d[445]
    DIRECTION OUTPUT ;
    USE SIGNAL ;
    PORT
      LAYER M5 ;
        RECT  75.6 129.516 75.624 129.6 ;
    END
  END a_d[445]
  PIN a_d[446]
    DIRECTION OUTPUT ;
    USE SIGNAL ;
    PORT
      LAYER M3 ;
        RECT  75.744 129.562 75.762 129.6 ;
    END
  END a_d[446]
  PIN a_d[447]
    DIRECTION OUTPUT ;
    USE SIGNAL ;
    PORT
      LAYER M5 ;
        RECT  75.936 129.516 75.96 129.6 ;
    END
  END a_d[447]
  PIN a_d[448]
    DIRECTION OUTPUT ;
    USE SIGNAL ;
    PORT
      LAYER M3 ;
        RECT  76.104 129.562 76.122 129.6 ;
    END
  END a_d[448]
  PIN a_d[449]
    DIRECTION OUTPUT ;
    USE SIGNAL ;
    PORT
      LAYER M5 ;
        RECT  76.272 129.516 76.296 129.6 ;
    END
  END a_d[449]
  PIN a_d[44]
    DIRECTION OUTPUT ;
    USE SIGNAL ;
    PORT
      LAYER M3 ;
        RECT  8.028 129.562 8.046 129.6 ;
    END
  END a_d[44]
  PIN a_d[450]
    DIRECTION OUTPUT ;
    USE SIGNAL ;
    PORT
      LAYER M3 ;
        RECT  76.428 129.562 76.446 129.6 ;
    END
  END a_d[450]
  PIN a_d[451]
    DIRECTION OUTPUT ;
    USE SIGNAL ;
    PORT
      LAYER M5 ;
        RECT  76.608 129.516 76.632 129.6 ;
    END
  END a_d[451]
  PIN a_d[452]
    DIRECTION OUTPUT ;
    USE SIGNAL ;
    PORT
      LAYER M3 ;
        RECT  76.788 129.562 76.806 129.6 ;
    END
  END a_d[452]
  PIN a_d[453]
    DIRECTION OUTPUT ;
    USE SIGNAL ;
    PORT
      LAYER M5 ;
        RECT  76.944 129.516 76.968 129.6 ;
    END
  END a_d[453]
  PIN a_d[454]
    DIRECTION OUTPUT ;
    USE SIGNAL ;
    PORT
      LAYER M3 ;
        RECT  77.112 129.562 77.13 129.6 ;
    END
  END a_d[454]
  PIN a_d[455]
    DIRECTION OUTPUT ;
    USE SIGNAL ;
    PORT
      LAYER M5 ;
        RECT  77.28 129.516 77.304 129.6 ;
    END
  END a_d[455]
  PIN a_d[456]
    DIRECTION OUTPUT ;
    USE SIGNAL ;
    PORT
      LAYER M3 ;
        RECT  77.436 129.562 77.454 129.6 ;
    END
  END a_d[456]
  PIN a_d[457]
    DIRECTION OUTPUT ;
    USE SIGNAL ;
    PORT
      LAYER M5 ;
        RECT  77.616 129.516 77.64 129.6 ;
    END
  END a_d[457]
  PIN a_d[458]
    DIRECTION OUTPUT ;
    USE SIGNAL ;
    PORT
      LAYER M3 ;
        RECT  77.796 129.562 77.814 129.6 ;
    END
  END a_d[458]
  PIN a_d[459]
    DIRECTION OUTPUT ;
    USE SIGNAL ;
    PORT
      LAYER M5 ;
        RECT  77.952 129.516 77.976 129.6 ;
    END
  END a_d[459]
  PIN a_d[45]
    DIRECTION OUTPUT ;
    USE SIGNAL ;
    PORT
      LAYER M5 ;
        RECT  8.208 129.516 8.232 129.6 ;
    END
  END a_d[45]
  PIN a_d[460]
    DIRECTION OUTPUT ;
    USE SIGNAL ;
    PORT
      LAYER M3 ;
        RECT  78.12 129.562 78.138 129.6 ;
    END
  END a_d[460]
  PIN a_d[461]
    DIRECTION OUTPUT ;
    USE SIGNAL ;
    PORT
      LAYER M5 ;
        RECT  78.288 129.516 78.312 129.6 ;
    END
  END a_d[461]
  PIN a_d[462]
    DIRECTION OUTPUT ;
    USE SIGNAL ;
    PORT
      LAYER M3 ;
        RECT  78.444 129.562 78.462 129.6 ;
    END
  END a_d[462]
  PIN a_d[463]
    DIRECTION OUTPUT ;
    USE SIGNAL ;
    PORT
      LAYER M5 ;
        RECT  78.624 129.516 78.648 129.6 ;
    END
  END a_d[463]
  PIN a_d[464]
    DIRECTION OUTPUT ;
    USE SIGNAL ;
    PORT
      LAYER M3 ;
        RECT  78.804 129.562 78.822 129.6 ;
    END
  END a_d[464]
  PIN a_d[465]
    DIRECTION OUTPUT ;
    USE SIGNAL ;
    PORT
      LAYER M5 ;
        RECT  78.96 129.516 78.984 129.6 ;
    END
  END a_d[465]
  PIN a_d[466]
    DIRECTION OUTPUT ;
    USE SIGNAL ;
    PORT
      LAYER M3 ;
        RECT  79.128 129.562 79.146 129.6 ;
    END
  END a_d[466]
  PIN a_d[467]
    DIRECTION OUTPUT ;
    USE SIGNAL ;
    PORT
      LAYER M5 ;
        RECT  79.296 129.516 79.32 129.6 ;
    END
  END a_d[467]
  PIN a_d[468]
    DIRECTION OUTPUT ;
    USE SIGNAL ;
    PORT
      LAYER M3 ;
        RECT  79.452 129.562 79.47 129.6 ;
    END
  END a_d[468]
  PIN a_d[469]
    DIRECTION OUTPUT ;
    USE SIGNAL ;
    PORT
      LAYER M5 ;
        RECT  79.632 129.516 79.656 129.6 ;
    END
  END a_d[469]
  PIN a_d[46]
    DIRECTION OUTPUT ;
    USE SIGNAL ;
    PORT
      LAYER M3 ;
        RECT  8.352 129.562 8.37 129.6 ;
    END
  END a_d[46]
  PIN a_d[470]
    DIRECTION OUTPUT ;
    USE SIGNAL ;
    PORT
      LAYER M3 ;
        RECT  79.812 129.562 79.83 129.6 ;
    END
  END a_d[470]
  PIN a_d[471]
    DIRECTION OUTPUT ;
    USE SIGNAL ;
    PORT
      LAYER M5 ;
        RECT  79.968 129.516 79.992 129.6 ;
    END
  END a_d[471]
  PIN a_d[472]
    DIRECTION OUTPUT ;
    USE SIGNAL ;
    PORT
      LAYER M3 ;
        RECT  80.136 129.562 80.154 129.6 ;
    END
  END a_d[472]
  PIN a_d[473]
    DIRECTION OUTPUT ;
    USE SIGNAL ;
    PORT
      LAYER M5 ;
        RECT  80.304 129.516 80.328 129.6 ;
    END
  END a_d[473]
  PIN a_d[474]
    DIRECTION OUTPUT ;
    USE SIGNAL ;
    PORT
      LAYER M3 ;
        RECT  80.496 129.562 80.514 129.6 ;
    END
  END a_d[474]
  PIN a_d[475]
    DIRECTION OUTPUT ;
    USE SIGNAL ;
    PORT
      LAYER M5 ;
        RECT  80.64 129.516 80.664 129.6 ;
    END
  END a_d[475]
  PIN a_d[476]
    DIRECTION OUTPUT ;
    USE SIGNAL ;
    PORT
      LAYER M3 ;
        RECT  80.82 129.562 80.838 129.6 ;
    END
  END a_d[476]
  PIN a_d[477]
    DIRECTION OUTPUT ;
    USE SIGNAL ;
    PORT
      LAYER M5 ;
        RECT  80.976 129.516 81 129.6 ;
    END
  END a_d[477]
  PIN a_d[478]
    DIRECTION OUTPUT ;
    USE SIGNAL ;
    PORT
      LAYER M3 ;
        RECT  81.144 129.562 81.162 129.6 ;
    END
  END a_d[478]
  PIN a_d[479]
    DIRECTION OUTPUT ;
    USE SIGNAL ;
    PORT
      LAYER M5 ;
        RECT  81.312 129.516 81.336 129.6 ;
    END
  END a_d[479]
  PIN a_d[47]
    DIRECTION OUTPUT ;
    USE SIGNAL ;
    PORT
      LAYER M5 ;
        RECT  8.544 129.516 8.568 129.6 ;
    END
  END a_d[47]
  PIN a_d[480]
    DIRECTION OUTPUT ;
    USE SIGNAL ;
    PORT
      LAYER M3 ;
        RECT  81.504 129.562 81.522 129.6 ;
    END
  END a_d[480]
  PIN a_d[481]
    DIRECTION OUTPUT ;
    USE SIGNAL ;
    PORT
      LAYER M5 ;
        RECT  81.648 129.516 81.672 129.6 ;
    END
  END a_d[481]
  PIN a_d[482]
    DIRECTION OUTPUT ;
    USE SIGNAL ;
    PORT
      LAYER M3 ;
        RECT  81.828 129.562 81.846 129.6 ;
    END
  END a_d[482]
  PIN a_d[483]
    DIRECTION OUTPUT ;
    USE SIGNAL ;
    PORT
      LAYER M5 ;
        RECT  81.984 129.516 82.008 129.6 ;
    END
  END a_d[483]
  PIN a_d[484]
    DIRECTION OUTPUT ;
    USE SIGNAL ;
    PORT
      LAYER M3 ;
        RECT  82.152 129.562 82.17 129.6 ;
    END
  END a_d[484]
  PIN a_d[485]
    DIRECTION OUTPUT ;
    USE SIGNAL ;
    PORT
      LAYER M5 ;
        RECT  82.32 129.516 82.344 129.6 ;
    END
  END a_d[485]
  PIN a_d[486]
    DIRECTION OUTPUT ;
    USE SIGNAL ;
    PORT
      LAYER M3 ;
        RECT  82.512 129.562 82.53 129.6 ;
    END
  END a_d[486]
  PIN a_d[487]
    DIRECTION OUTPUT ;
    USE SIGNAL ;
    PORT
      LAYER M5 ;
        RECT  82.656 129.516 82.68 129.6 ;
    END
  END a_d[487]
  PIN a_d[488]
    DIRECTION OUTPUT ;
    USE SIGNAL ;
    PORT
      LAYER M3 ;
        RECT  82.836 129.562 82.854 129.6 ;
    END
  END a_d[488]
  PIN a_d[489]
    DIRECTION OUTPUT ;
    USE SIGNAL ;
    PORT
      LAYER M5 ;
        RECT  82.992 129.516 83.016 129.6 ;
    END
  END a_d[489]
  PIN a_d[48]
    DIRECTION OUTPUT ;
    USE SIGNAL ;
    PORT
      LAYER M3 ;
        RECT  8.712 129.562 8.73 129.6 ;
    END
  END a_d[48]
  PIN a_d[490]
    DIRECTION OUTPUT ;
    USE SIGNAL ;
    PORT
      LAYER M3 ;
        RECT  83.16 129.562 83.178 129.6 ;
    END
  END a_d[490]
  PIN a_d[491]
    DIRECTION OUTPUT ;
    USE SIGNAL ;
    PORT
      LAYER M5 ;
        RECT  83.328 129.516 83.352 129.6 ;
    END
  END a_d[491]
  PIN a_d[492]
    DIRECTION OUTPUT ;
    USE SIGNAL ;
    PORT
      LAYER M3 ;
        RECT  83.52 129.562 83.538 129.6 ;
    END
  END a_d[492]
  PIN a_d[493]
    DIRECTION OUTPUT ;
    USE SIGNAL ;
    PORT
      LAYER M5 ;
        RECT  83.664 129.516 83.688 129.6 ;
    END
  END a_d[493]
  PIN a_d[494]
    DIRECTION OUTPUT ;
    USE SIGNAL ;
    PORT
      LAYER M3 ;
        RECT  83.844 129.562 83.862 129.6 ;
    END
  END a_d[494]
  PIN a_d[495]
    DIRECTION OUTPUT ;
    USE SIGNAL ;
    PORT
      LAYER M5 ;
        RECT  84 129.516 84.024 129.6 ;
    END
  END a_d[495]
  PIN a_d[496]
    DIRECTION OUTPUT ;
    USE SIGNAL ;
    PORT
      LAYER M3 ;
        RECT  84.168 129.562 84.186 129.6 ;
    END
  END a_d[496]
  PIN a_d[497]
    DIRECTION OUTPUT ;
    USE SIGNAL ;
    PORT
      LAYER M5 ;
        RECT  84.336 129.516 84.36 129.6 ;
    END
  END a_d[497]
  PIN a_d[498]
    DIRECTION OUTPUT ;
    USE SIGNAL ;
    PORT
      LAYER M3 ;
        RECT  84.528 129.562 84.546 129.6 ;
    END
  END a_d[498]
  PIN a_d[499]
    DIRECTION OUTPUT ;
    USE SIGNAL ;
    PORT
      LAYER M5 ;
        RECT  84.672 129.516 84.696 129.6 ;
    END
  END a_d[499]
  PIN a_d[49]
    DIRECTION OUTPUT ;
    USE SIGNAL ;
    PORT
      LAYER M5 ;
        RECT  8.88 129.516 8.904 129.6 ;
    END
  END a_d[49]
  PIN a_d[4]
    DIRECTION OUTPUT ;
    USE SIGNAL ;
    PORT
      LAYER M3 ;
        RECT  1.296 129.562 1.314 129.6 ;
    END
  END a_d[4]
  PIN a_d[500]
    DIRECTION OUTPUT ;
    USE SIGNAL ;
    PORT
      LAYER M3 ;
        RECT  84.852 129.562 84.87 129.6 ;
    END
  END a_d[500]
  PIN a_d[501]
    DIRECTION OUTPUT ;
    USE SIGNAL ;
    PORT
      LAYER M5 ;
        RECT  85.008 129.516 85.032 129.6 ;
    END
  END a_d[501]
  PIN a_d[502]
    DIRECTION OUTPUT ;
    USE SIGNAL ;
    PORT
      LAYER M3 ;
        RECT  85.212 129.562 85.23 129.6 ;
    END
  END a_d[502]
  PIN a_d[503]
    DIRECTION OUTPUT ;
    USE SIGNAL ;
    PORT
      LAYER M5 ;
        RECT  85.344 129.516 85.368 129.6 ;
    END
  END a_d[503]
  PIN a_d[504]
    DIRECTION OUTPUT ;
    USE SIGNAL ;
    PORT
      LAYER M3 ;
        RECT  85.536 129.562 85.554 129.6 ;
    END
  END a_d[504]
  PIN a_d[505]
    DIRECTION OUTPUT ;
    USE SIGNAL ;
    PORT
      LAYER M5 ;
        RECT  85.68 129.516 85.704 129.6 ;
    END
  END a_d[505]
  PIN a_d[506]
    DIRECTION OUTPUT ;
    USE SIGNAL ;
    PORT
      LAYER M3 ;
        RECT  85.86 129.562 85.878 129.6 ;
    END
  END a_d[506]
  PIN a_d[507]
    DIRECTION OUTPUT ;
    USE SIGNAL ;
    PORT
      LAYER M5 ;
        RECT  86.016 129.516 86.04 129.6 ;
    END
  END a_d[507]
  PIN a_d[508]
    DIRECTION OUTPUT ;
    USE SIGNAL ;
    PORT
      LAYER M3 ;
        RECT  86.22 129.562 86.238 129.6 ;
    END
  END a_d[508]
  PIN a_d[509]
    DIRECTION OUTPUT ;
    USE SIGNAL ;
    PORT
      LAYER M5 ;
        RECT  86.352 129.516 86.376 129.6 ;
    END
  END a_d[509]
  PIN a_d[50]
    DIRECTION OUTPUT ;
    USE SIGNAL ;
    PORT
      LAYER M3 ;
        RECT  9.036 129.562 9.054 129.6 ;
    END
  END a_d[50]
  PIN a_d[510]
    DIRECTION OUTPUT ;
    USE SIGNAL ;
    PORT
      LAYER M3 ;
        RECT  86.544 129.562 86.562 129.6 ;
    END
  END a_d[510]
  PIN a_d[511]
    DIRECTION OUTPUT ;
    USE SIGNAL ;
    PORT
      LAYER M5 ;
        RECT  86.688 129.516 86.712 129.6 ;
    END
  END a_d[511]
  PIN a_d[512]
    DIRECTION OUTPUT ;
    USE SIGNAL ;
    PORT
      LAYER M3 ;
        RECT  86.868 129.562 86.886 129.6 ;
    END
  END a_d[512]
  PIN a_d[513]
    DIRECTION OUTPUT ;
    USE SIGNAL ;
    PORT
      LAYER M5 ;
        RECT  87.024 129.516 87.048 129.6 ;
    END
  END a_d[513]
  PIN a_d[514]
    DIRECTION OUTPUT ;
    USE SIGNAL ;
    PORT
      LAYER M3 ;
        RECT  87.228 129.562 87.246 129.6 ;
    END
  END a_d[514]
  PIN a_d[515]
    DIRECTION OUTPUT ;
    USE SIGNAL ;
    PORT
      LAYER M5 ;
        RECT  87.408 129.516 87.432 129.6 ;
    END
  END a_d[515]
  PIN a_d[51]
    DIRECTION OUTPUT ;
    USE SIGNAL ;
    PORT
      LAYER M5 ;
        RECT  9.216 129.516 9.24 129.6 ;
    END
  END a_d[51]
  PIN a_d[52]
    DIRECTION OUTPUT ;
    USE SIGNAL ;
    PORT
      LAYER M3 ;
        RECT  9.36 129.562 9.378 129.6 ;
    END
  END a_d[52]
  PIN a_d[53]
    DIRECTION OUTPUT ;
    USE SIGNAL ;
    PORT
      LAYER M5 ;
        RECT  9.552 129.516 9.576 129.6 ;
    END
  END a_d[53]
  PIN a_d[54]
    DIRECTION OUTPUT ;
    USE SIGNAL ;
    PORT
      LAYER M3 ;
        RECT  9.72 129.562 9.738 129.6 ;
    END
  END a_d[54]
  PIN a_d[55]
    DIRECTION OUTPUT ;
    USE SIGNAL ;
    PORT
      LAYER M5 ;
        RECT  9.888 129.516 9.912 129.6 ;
    END
  END a_d[55]
  PIN a_d[56]
    DIRECTION OUTPUT ;
    USE SIGNAL ;
    PORT
      LAYER M3 ;
        RECT  10.044 129.562 10.062 129.6 ;
    END
  END a_d[56]
  PIN a_d[57]
    DIRECTION OUTPUT ;
    USE SIGNAL ;
    PORT
      LAYER M5 ;
        RECT  10.224 129.516 10.248 129.6 ;
    END
  END a_d[57]
  PIN a_d[58]
    DIRECTION OUTPUT ;
    USE SIGNAL ;
    PORT
      LAYER M3 ;
        RECT  10.404 129.562 10.422 129.6 ;
    END
  END a_d[58]
  PIN a_d[59]
    DIRECTION OUTPUT ;
    USE SIGNAL ;
    PORT
      LAYER M5 ;
        RECT  10.56 129.516 10.584 129.6 ;
    END
  END a_d[59]
  PIN a_d[5]
    DIRECTION OUTPUT ;
    USE SIGNAL ;
    PORT
      LAYER M5 ;
        RECT  1.44 129.516 1.464 129.6 ;
    END
  END a_d[5]
  PIN a_d[60]
    DIRECTION OUTPUT ;
    USE SIGNAL ;
    PORT
      LAYER M3 ;
        RECT  10.728 129.562 10.746 129.6 ;
    END
  END a_d[60]
  PIN a_d[61]
    DIRECTION OUTPUT ;
    USE SIGNAL ;
    PORT
      LAYER M5 ;
        RECT  10.896 129.516 10.92 129.6 ;
    END
  END a_d[61]
  PIN a_d[62]
    DIRECTION OUTPUT ;
    USE SIGNAL ;
    PORT
      LAYER M3 ;
        RECT  11.052 129.562 11.07 129.6 ;
    END
  END a_d[62]
  PIN a_d[63]
    DIRECTION OUTPUT ;
    USE SIGNAL ;
    PORT
      LAYER M5 ;
        RECT  11.232 129.516 11.256 129.6 ;
    END
  END a_d[63]
  PIN a_d[64]
    DIRECTION OUTPUT ;
    USE SIGNAL ;
    PORT
      LAYER M3 ;
        RECT  11.412 129.562 11.43 129.6 ;
    END
  END a_d[64]
  PIN a_d[65]
    DIRECTION OUTPUT ;
    USE SIGNAL ;
    PORT
      LAYER M5 ;
        RECT  11.568 129.516 11.592 129.6 ;
    END
  END a_d[65]
  PIN a_d[66]
    DIRECTION OUTPUT ;
    USE SIGNAL ;
    PORT
      LAYER M3 ;
        RECT  11.736 129.562 11.754 129.6 ;
    END
  END a_d[66]
  PIN a_d[67]
    DIRECTION OUTPUT ;
    USE SIGNAL ;
    PORT
      LAYER M5 ;
        RECT  11.904 129.516 11.928 129.6 ;
    END
  END a_d[67]
  PIN a_d[68]
    DIRECTION OUTPUT ;
    USE SIGNAL ;
    PORT
      LAYER M3 ;
        RECT  12.06 129.562 12.078 129.6 ;
    END
  END a_d[68]
  PIN a_d[69]
    DIRECTION OUTPUT ;
    USE SIGNAL ;
    PORT
      LAYER M5 ;
        RECT  12.24 129.516 12.264 129.6 ;
    END
  END a_d[69]
  PIN a_d[6]
    DIRECTION OUTPUT ;
    USE SIGNAL ;
    PORT
      LAYER M3 ;
        RECT  1.62 129.562 1.638 129.6 ;
    END
  END a_d[6]
  PIN a_d[70]
    DIRECTION OUTPUT ;
    USE SIGNAL ;
    PORT
      LAYER M3 ;
        RECT  12.42 129.562 12.438 129.6 ;
    END
  END a_d[70]
  PIN a_d[71]
    DIRECTION OUTPUT ;
    USE SIGNAL ;
    PORT
      LAYER M5 ;
        RECT  12.576 129.516 12.6 129.6 ;
    END
  END a_d[71]
  PIN a_d[72]
    DIRECTION OUTPUT ;
    USE SIGNAL ;
    PORT
      LAYER M3 ;
        RECT  12.744 129.562 12.762 129.6 ;
    END
  END a_d[72]
  PIN a_d[73]
    DIRECTION OUTPUT ;
    USE SIGNAL ;
    PORT
      LAYER M5 ;
        RECT  12.912 129.516 12.936 129.6 ;
    END
  END a_d[73]
  PIN a_d[74]
    DIRECTION OUTPUT ;
    USE SIGNAL ;
    PORT
      LAYER M3 ;
        RECT  13.068 129.562 13.086 129.6 ;
    END
  END a_d[74]
  PIN a_d[75]
    DIRECTION OUTPUT ;
    USE SIGNAL ;
    PORT
      LAYER M5 ;
        RECT  13.248 129.516 13.272 129.6 ;
    END
  END a_d[75]
  PIN a_d[76]
    DIRECTION OUTPUT ;
    USE SIGNAL ;
    PORT
      LAYER M3 ;
        RECT  13.428 129.562 13.446 129.6 ;
    END
  END a_d[76]
  PIN a_d[77]
    DIRECTION OUTPUT ;
    USE SIGNAL ;
    PORT
      LAYER M5 ;
        RECT  13.584 129.516 13.608 129.6 ;
    END
  END a_d[77]
  PIN a_d[78]
    DIRECTION OUTPUT ;
    USE SIGNAL ;
    PORT
      LAYER M3 ;
        RECT  13.752 129.562 13.77 129.6 ;
    END
  END a_d[78]
  PIN a_d[79]
    DIRECTION OUTPUT ;
    USE SIGNAL ;
    PORT
      LAYER M5 ;
        RECT  13.92 129.516 13.944 129.6 ;
    END
  END a_d[79]
  PIN a_d[7]
    DIRECTION OUTPUT ;
    USE SIGNAL ;
    PORT
      LAYER M5 ;
        RECT  1.776 129.516 1.8 129.6 ;
    END
  END a_d[7]
  PIN a_d[80]
    DIRECTION OUTPUT ;
    USE SIGNAL ;
    PORT
      LAYER M3 ;
        RECT  14.112 129.562 14.13 129.6 ;
    END
  END a_d[80]
  PIN a_d[81]
    DIRECTION OUTPUT ;
    USE SIGNAL ;
    PORT
      LAYER M5 ;
        RECT  14.256 129.516 14.28 129.6 ;
    END
  END a_d[81]
  PIN a_d[82]
    DIRECTION OUTPUT ;
    USE SIGNAL ;
    PORT
      LAYER M3 ;
        RECT  14.436 129.562 14.454 129.6 ;
    END
  END a_d[82]
  PIN a_d[83]
    DIRECTION OUTPUT ;
    USE SIGNAL ;
    PORT
      LAYER M5 ;
        RECT  14.592 129.516 14.616 129.6 ;
    END
  END a_d[83]
  PIN a_d[84]
    DIRECTION OUTPUT ;
    USE SIGNAL ;
    PORT
      LAYER M3 ;
        RECT  14.76 129.562 14.778 129.6 ;
    END
  END a_d[84]
  PIN a_d[85]
    DIRECTION OUTPUT ;
    USE SIGNAL ;
    PORT
      LAYER M5 ;
        RECT  14.928 129.516 14.952 129.6 ;
    END
  END a_d[85]
  PIN a_d[86]
    DIRECTION OUTPUT ;
    USE SIGNAL ;
    PORT
      LAYER M3 ;
        RECT  15.12 129.562 15.138 129.6 ;
    END
  END a_d[86]
  PIN a_d[87]
    DIRECTION OUTPUT ;
    USE SIGNAL ;
    PORT
      LAYER M5 ;
        RECT  15.264 129.516 15.288 129.6 ;
    END
  END a_d[87]
  PIN a_d[88]
    DIRECTION OUTPUT ;
    USE SIGNAL ;
    PORT
      LAYER M3 ;
        RECT  15.444 129.562 15.462 129.6 ;
    END
  END a_d[88]
  PIN a_d[89]
    DIRECTION OUTPUT ;
    USE SIGNAL ;
    PORT
      LAYER M5 ;
        RECT  15.6 129.516 15.624 129.6 ;
    END
  END a_d[89]
  PIN a_d[8]
    DIRECTION OUTPUT ;
    USE SIGNAL ;
    PORT
      LAYER M3 ;
        RECT  1.98 129.562 1.998 129.6 ;
    END
  END a_d[8]
  PIN a_d[90]
    DIRECTION OUTPUT ;
    USE SIGNAL ;
    PORT
      LAYER M3 ;
        RECT  15.768 129.562 15.786 129.6 ;
    END
  END a_d[90]
  PIN a_d[91]
    DIRECTION OUTPUT ;
    USE SIGNAL ;
    PORT
      LAYER M5 ;
        RECT  15.936 129.516 15.96 129.6 ;
    END
  END a_d[91]
  PIN a_d[92]
    DIRECTION OUTPUT ;
    USE SIGNAL ;
    PORT
      LAYER M3 ;
        RECT  16.128 129.562 16.146 129.6 ;
    END
  END a_d[92]
  PIN a_d[93]
    DIRECTION OUTPUT ;
    USE SIGNAL ;
    PORT
      LAYER M5 ;
        RECT  16.272 129.516 16.296 129.6 ;
    END
  END a_d[93]
  PIN a_d[94]
    DIRECTION OUTPUT ;
    USE SIGNAL ;
    PORT
      LAYER M3 ;
        RECT  16.452 129.562 16.47 129.6 ;
    END
  END a_d[94]
  PIN a_d[95]
    DIRECTION OUTPUT ;
    USE SIGNAL ;
    PORT
      LAYER M5 ;
        RECT  16.608 129.516 16.632 129.6 ;
    END
  END a_d[95]
  PIN a_d[96]
    DIRECTION OUTPUT ;
    USE SIGNAL ;
    PORT
      LAYER M3 ;
        RECT  16.776 129.562 16.794 129.6 ;
    END
  END a_d[96]
  PIN a_d[97]
    DIRECTION OUTPUT ;
    USE SIGNAL ;
    PORT
      LAYER M5 ;
        RECT  16.944 129.516 16.968 129.6 ;
    END
  END a_d[97]
  PIN a_d[98]
    DIRECTION OUTPUT ;
    USE SIGNAL ;
    PORT
      LAYER M3 ;
        RECT  17.136 129.562 17.154 129.6 ;
    END
  END a_d[98]
  PIN a_d[99]
    DIRECTION OUTPUT ;
    USE SIGNAL ;
    PORT
      LAYER M5 ;
        RECT  17.28 129.516 17.304 129.6 ;
    END
  END a_d[99]
  PIN a_d[9]
    DIRECTION OUTPUT ;
    USE SIGNAL ;
    PORT
      LAYER M5 ;
        RECT  2.112 129.516 2.136 129.6 ;
    END
  END a_d[9]
  PIN b_d[0]
    DIRECTION INPUT ;
    USE SIGNAL ;
    PORT
      LAYER M3 ;
        RECT  0.612 0 0.63 0.038 ;
    END
  END b_d[0]
  PIN b_d[100]
    DIRECTION INPUT ;
    USE SIGNAL ;
    PORT
      LAYER M3 ;
        RECT  17.46 0 17.478 0.038 ;
    END
  END b_d[100]
  PIN b_d[101]
    DIRECTION INPUT ;
    USE SIGNAL ;
    PORT
      LAYER M5 ;
        RECT  17.616 0 17.64 0.084 ;
    END
  END b_d[101]
  PIN b_d[102]
    DIRECTION INPUT ;
    USE SIGNAL ;
    PORT
      LAYER M3 ;
        RECT  17.784 0 17.802 0.038 ;
    END
  END b_d[102]
  PIN b_d[103]
    DIRECTION INPUT ;
    USE SIGNAL ;
    PORT
      LAYER M5 ;
        RECT  17.952 0 17.976 0.084 ;
    END
  END b_d[103]
  PIN b_d[104]
    DIRECTION INPUT ;
    USE SIGNAL ;
    PORT
      LAYER M3 ;
        RECT  18.144 0 18.162 0.038 ;
    END
  END b_d[104]
  PIN b_d[105]
    DIRECTION INPUT ;
    USE SIGNAL ;
    PORT
      LAYER M5 ;
        RECT  18.288 0 18.312 0.084 ;
    END
  END b_d[105]
  PIN b_d[106]
    DIRECTION INPUT ;
    USE SIGNAL ;
    PORT
      LAYER M3 ;
        RECT  18.468 0 18.486 0.038 ;
    END
  END b_d[106]
  PIN b_d[107]
    DIRECTION INPUT ;
    USE SIGNAL ;
    PORT
      LAYER M5 ;
        RECT  18.624 0 18.648 0.084 ;
    END
  END b_d[107]
  PIN b_d[108]
    DIRECTION INPUT ;
    USE SIGNAL ;
    PORT
      LAYER M3 ;
        RECT  18.828 0 18.846 0.038 ;
    END
  END b_d[108]
  PIN b_d[109]
    DIRECTION INPUT ;
    USE SIGNAL ;
    PORT
      LAYER M5 ;
        RECT  18.96 0 18.984 0.084 ;
    END
  END b_d[109]
  PIN b_d[10]
    DIRECTION INPUT ;
    USE SIGNAL ;
    PORT
      LAYER M3 ;
        RECT  2.304 0 2.322 0.038 ;
    END
  END b_d[10]
  PIN b_d[110]
    DIRECTION INPUT ;
    USE SIGNAL ;
    PORT
      LAYER M3 ;
        RECT  19.152 0 19.17 0.038 ;
    END
  END b_d[110]
  PIN b_d[111]
    DIRECTION INPUT ;
    USE SIGNAL ;
    PORT
      LAYER M5 ;
        RECT  19.296 0 19.32 0.084 ;
    END
  END b_d[111]
  PIN b_d[112]
    DIRECTION INPUT ;
    USE SIGNAL ;
    PORT
      LAYER M3 ;
        RECT  19.476 0 19.494 0.038 ;
    END
  END b_d[112]
  PIN b_d[113]
    DIRECTION INPUT ;
    USE SIGNAL ;
    PORT
      LAYER M5 ;
        RECT  19.632 0 19.656 0.084 ;
    END
  END b_d[113]
  PIN b_d[114]
    DIRECTION INPUT ;
    USE SIGNAL ;
    PORT
      LAYER M3 ;
        RECT  19.836 0 19.854 0.038 ;
    END
  END b_d[114]
  PIN b_d[115]
    DIRECTION INPUT ;
    USE SIGNAL ;
    PORT
      LAYER M5 ;
        RECT  19.968 0 19.992 0.084 ;
    END
  END b_d[115]
  PIN b_d[116]
    DIRECTION INPUT ;
    USE SIGNAL ;
    PORT
      LAYER M3 ;
        RECT  20.16 0 20.178 0.038 ;
    END
  END b_d[116]
  PIN b_d[117]
    DIRECTION INPUT ;
    USE SIGNAL ;
    PORT
      LAYER M5 ;
        RECT  20.304 0 20.328 0.084 ;
    END
  END b_d[117]
  PIN b_d[118]
    DIRECTION INPUT ;
    USE SIGNAL ;
    PORT
      LAYER M3 ;
        RECT  20.484 0 20.502 0.038 ;
    END
  END b_d[118]
  PIN b_d[119]
    DIRECTION INPUT ;
    USE SIGNAL ;
    PORT
      LAYER M5 ;
        RECT  20.64 0 20.664 0.084 ;
    END
  END b_d[119]
  PIN b_d[11]
    DIRECTION INPUT ;
    USE SIGNAL ;
    PORT
      LAYER M5 ;
        RECT  2.448 0 2.472 0.084 ;
    END
  END b_d[11]
  PIN b_d[120]
    DIRECTION INPUT ;
    USE SIGNAL ;
    PORT
      LAYER M3 ;
        RECT  20.844 0 20.862 0.038 ;
    END
  END b_d[120]
  PIN b_d[121]
    DIRECTION INPUT ;
    USE SIGNAL ;
    PORT
      LAYER M5 ;
        RECT  20.976 0 21 0.084 ;
    END
  END b_d[121]
  PIN b_d[122]
    DIRECTION INPUT ;
    USE SIGNAL ;
    PORT
      LAYER M3 ;
        RECT  21.168 0 21.186 0.038 ;
    END
  END b_d[122]
  PIN b_d[123]
    DIRECTION INPUT ;
    USE SIGNAL ;
    PORT
      LAYER M5 ;
        RECT  21.36 0 21.384 0.084 ;
    END
  END b_d[123]
  PIN b_d[124]
    DIRECTION INPUT ;
    USE SIGNAL ;
    PORT
      LAYER M3 ;
        RECT  21.492 0 21.51 0.038 ;
    END
  END b_d[124]
  PIN b_d[125]
    DIRECTION INPUT ;
    USE SIGNAL ;
    PORT
      LAYER M5 ;
        RECT  21.696 0 21.72 0.084 ;
    END
  END b_d[125]
  PIN b_d[126]
    DIRECTION INPUT ;
    USE SIGNAL ;
    PORT
      LAYER M3 ;
        RECT  21.852 0 21.87 0.038 ;
    END
  END b_d[126]
  PIN b_d[127]
    DIRECTION INPUT ;
    USE SIGNAL ;
    PORT
      LAYER M5 ;
        RECT  22.032 0 22.056 0.084 ;
    END
  END b_d[127]
  PIN b_d[128]
    DIRECTION INPUT ;
    USE SIGNAL ;
    PORT
      LAYER M3 ;
        RECT  22.176 0 22.194 0.038 ;
    END
  END b_d[128]
  PIN b_d[129]
    DIRECTION INPUT ;
    USE SIGNAL ;
    PORT
      LAYER M5 ;
        RECT  22.368 0 22.392 0.084 ;
    END
  END b_d[129]
  PIN b_d[12]
    DIRECTION INPUT ;
    USE SIGNAL ;
    PORT
      LAYER M3 ;
        RECT  2.628 0 2.646 0.038 ;
    END
  END b_d[12]
  PIN b_d[130]
    DIRECTION INPUT ;
    USE SIGNAL ;
    PORT
      LAYER M3 ;
        RECT  22.536 0 22.554 0.038 ;
    END
  END b_d[130]
  PIN b_d[131]
    DIRECTION INPUT ;
    USE SIGNAL ;
    PORT
      LAYER M5 ;
        RECT  22.704 0 22.728 0.084 ;
    END
  END b_d[131]
  PIN b_d[132]
    DIRECTION INPUT ;
    USE SIGNAL ;
    PORT
      LAYER M3 ;
        RECT  22.86 0 22.878 0.038 ;
    END
  END b_d[132]
  PIN b_d[133]
    DIRECTION INPUT ;
    USE SIGNAL ;
    PORT
      LAYER M5 ;
        RECT  23.04 0 23.064 0.084 ;
    END
  END b_d[133]
  PIN b_d[134]
    DIRECTION INPUT ;
    USE SIGNAL ;
    PORT
      LAYER M3 ;
        RECT  23.184 0 23.202 0.038 ;
    END
  END b_d[134]
  PIN b_d[135]
    DIRECTION INPUT ;
    USE SIGNAL ;
    PORT
      LAYER M5 ;
        RECT  23.376 0 23.4 0.084 ;
    END
  END b_d[135]
  PIN b_d[136]
    DIRECTION INPUT ;
    USE SIGNAL ;
    PORT
      LAYER M3 ;
        RECT  23.544 0 23.562 0.038 ;
    END
  END b_d[136]
  PIN b_d[137]
    DIRECTION INPUT ;
    USE SIGNAL ;
    PORT
      LAYER M5 ;
        RECT  23.712 0 23.736 0.084 ;
    END
  END b_d[137]
  PIN b_d[138]
    DIRECTION INPUT ;
    USE SIGNAL ;
    PORT
      LAYER M3 ;
        RECT  23.868 0 23.886 0.038 ;
    END
  END b_d[138]
  PIN b_d[139]
    DIRECTION INPUT ;
    USE SIGNAL ;
    PORT
      LAYER M5 ;
        RECT  24.048 0 24.072 0.084 ;
    END
  END b_d[139]
  PIN b_d[13]
    DIRECTION INPUT ;
    USE SIGNAL ;
    PORT
      LAYER M5 ;
        RECT  2.784 0 2.808 0.084 ;
    END
  END b_d[13]
  PIN b_d[140]
    DIRECTION INPUT ;
    USE SIGNAL ;
    PORT
      LAYER M3 ;
        RECT  24.192 0 24.21 0.038 ;
    END
  END b_d[140]
  PIN b_d[141]
    DIRECTION INPUT ;
    USE SIGNAL ;
    PORT
      LAYER M5 ;
        RECT  24.384 0 24.408 0.084 ;
    END
  END b_d[141]
  PIN b_d[142]
    DIRECTION INPUT ;
    USE SIGNAL ;
    PORT
      LAYER M3 ;
        RECT  24.552 0 24.57 0.038 ;
    END
  END b_d[142]
  PIN b_d[143]
    DIRECTION INPUT ;
    USE SIGNAL ;
    PORT
      LAYER M5 ;
        RECT  24.72 0 24.744 0.084 ;
    END
  END b_d[143]
  PIN b_d[144]
    DIRECTION INPUT ;
    USE SIGNAL ;
    PORT
      LAYER M3 ;
        RECT  24.876 0 24.894 0.038 ;
    END
  END b_d[144]
  PIN b_d[145]
    DIRECTION INPUT ;
    USE SIGNAL ;
    PORT
      LAYER M5 ;
        RECT  25.056 0 25.08 0.084 ;
    END
  END b_d[145]
  PIN b_d[146]
    DIRECTION INPUT ;
    USE SIGNAL ;
    PORT
      LAYER M3 ;
        RECT  25.2 0 25.218 0.038 ;
    END
  END b_d[146]
  PIN b_d[147]
    DIRECTION INPUT ;
    USE SIGNAL ;
    PORT
      LAYER M5 ;
        RECT  25.392 0 25.416 0.084 ;
    END
  END b_d[147]
  PIN b_d[148]
    DIRECTION INPUT ;
    USE SIGNAL ;
    PORT
      LAYER M3 ;
        RECT  25.56 0 25.578 0.038 ;
    END
  END b_d[148]
  PIN b_d[149]
    DIRECTION INPUT ;
    USE SIGNAL ;
    PORT
      LAYER M5 ;
        RECT  25.728 0 25.752 0.084 ;
    END
  END b_d[149]
  PIN b_d[14]
    DIRECTION INPUT ;
    USE SIGNAL ;
    PORT
      LAYER M3 ;
        RECT  2.988 0 3.006 0.038 ;
    END
  END b_d[14]
  PIN b_d[150]
    DIRECTION INPUT ;
    USE SIGNAL ;
    PORT
      LAYER M3 ;
        RECT  25.884 0 25.902 0.038 ;
    END
  END b_d[150]
  PIN b_d[151]
    DIRECTION INPUT ;
    USE SIGNAL ;
    PORT
      LAYER M5 ;
        RECT  26.064 0 26.088 0.084 ;
    END
  END b_d[151]
  PIN b_d[152]
    DIRECTION INPUT ;
    USE SIGNAL ;
    PORT
      LAYER M3 ;
        RECT  26.208 0 26.226 0.038 ;
    END
  END b_d[152]
  PIN b_d[153]
    DIRECTION INPUT ;
    USE SIGNAL ;
    PORT
      LAYER M5 ;
        RECT  26.4 0 26.424 0.084 ;
    END
  END b_d[153]
  PIN b_d[154]
    DIRECTION INPUT ;
    USE SIGNAL ;
    PORT
      LAYER M3 ;
        RECT  26.568 0 26.586 0.038 ;
    END
  END b_d[154]
  PIN b_d[155]
    DIRECTION INPUT ;
    USE SIGNAL ;
    PORT
      LAYER M5 ;
        RECT  26.736 0 26.76 0.084 ;
    END
  END b_d[155]
  PIN b_d[156]
    DIRECTION INPUT ;
    USE SIGNAL ;
    PORT
      LAYER M3 ;
        RECT  26.892 0 26.91 0.038 ;
    END
  END b_d[156]
  PIN b_d[157]
    DIRECTION INPUT ;
    USE SIGNAL ;
    PORT
      LAYER M5 ;
        RECT  27.072 0 27.096 0.084 ;
    END
  END b_d[157]
  PIN b_d[158]
    DIRECTION INPUT ;
    USE SIGNAL ;
    PORT
      LAYER M3 ;
        RECT  27.252 0 27.27 0.038 ;
    END
  END b_d[158]
  PIN b_d[159]
    DIRECTION INPUT ;
    USE SIGNAL ;
    PORT
      LAYER M5 ;
        RECT  27.408 0 27.432 0.084 ;
    END
  END b_d[159]
  PIN b_d[15]
    DIRECTION INPUT ;
    USE SIGNAL ;
    PORT
      LAYER M5 ;
        RECT  3.12 0 3.144 0.084 ;
    END
  END b_d[15]
  PIN b_d[160]
    DIRECTION INPUT ;
    USE SIGNAL ;
    PORT
      LAYER M3 ;
        RECT  27.576 0 27.594 0.038 ;
    END
  END b_d[160]
  PIN b_d[161]
    DIRECTION INPUT ;
    USE SIGNAL ;
    PORT
      LAYER M5 ;
        RECT  27.744 0 27.768 0.084 ;
    END
  END b_d[161]
  PIN b_d[162]
    DIRECTION INPUT ;
    USE SIGNAL ;
    PORT
      LAYER M3 ;
        RECT  27.9 0 27.918 0.038 ;
    END
  END b_d[162]
  PIN b_d[163]
    DIRECTION INPUT ;
    USE SIGNAL ;
    PORT
      LAYER M5 ;
        RECT  28.08 0 28.104 0.084 ;
    END
  END b_d[163]
  PIN b_d[164]
    DIRECTION INPUT ;
    USE SIGNAL ;
    PORT
      LAYER M3 ;
        RECT  28.26 0 28.278 0.038 ;
    END
  END b_d[164]
  PIN b_d[165]
    DIRECTION INPUT ;
    USE SIGNAL ;
    PORT
      LAYER M5 ;
        RECT  28.416 0 28.44 0.084 ;
    END
  END b_d[165]
  PIN b_d[166]
    DIRECTION INPUT ;
    USE SIGNAL ;
    PORT
      LAYER M3 ;
        RECT  28.584 0 28.602 0.038 ;
    END
  END b_d[166]
  PIN b_d[167]
    DIRECTION INPUT ;
    USE SIGNAL ;
    PORT
      LAYER M5 ;
        RECT  28.752 0 28.776 0.084 ;
    END
  END b_d[167]
  PIN b_d[168]
    DIRECTION INPUT ;
    USE SIGNAL ;
    PORT
      LAYER M3 ;
        RECT  28.908 0 28.926 0.038 ;
    END
  END b_d[168]
  PIN b_d[169]
    DIRECTION INPUT ;
    USE SIGNAL ;
    PORT
      LAYER M5 ;
        RECT  29.088 0 29.112 0.084 ;
    END
  END b_d[169]
  PIN b_d[16]
    DIRECTION INPUT ;
    USE SIGNAL ;
    PORT
      LAYER M3 ;
        RECT  3.312 0 3.33 0.038 ;
    END
  END b_d[16]
  PIN b_d[170]
    DIRECTION INPUT ;
    USE SIGNAL ;
    PORT
      LAYER M3 ;
        RECT  29.268 0 29.286 0.038 ;
    END
  END b_d[170]
  PIN b_d[171]
    DIRECTION INPUT ;
    USE SIGNAL ;
    PORT
      LAYER M5 ;
        RECT  29.424 0 29.448 0.084 ;
    END
  END b_d[171]
  PIN b_d[172]
    DIRECTION INPUT ;
    USE SIGNAL ;
    PORT
      LAYER M3 ;
        RECT  29.592 0 29.61 0.038 ;
    END
  END b_d[172]
  PIN b_d[173]
    DIRECTION INPUT ;
    USE SIGNAL ;
    PORT
      LAYER M5 ;
        RECT  29.76 0 29.784 0.084 ;
    END
  END b_d[173]
  PIN b_d[174]
    DIRECTION INPUT ;
    USE SIGNAL ;
    PORT
      LAYER M3 ;
        RECT  29.916 0 29.934 0.038 ;
    END
  END b_d[174]
  PIN b_d[175]
    DIRECTION INPUT ;
    USE SIGNAL ;
    PORT
      LAYER M5 ;
        RECT  30.096 0 30.12 0.084 ;
    END
  END b_d[175]
  PIN b_d[176]
    DIRECTION INPUT ;
    USE SIGNAL ;
    PORT
      LAYER M3 ;
        RECT  30.276 0 30.294 0.038 ;
    END
  END b_d[176]
  PIN b_d[177]
    DIRECTION INPUT ;
    USE SIGNAL ;
    PORT
      LAYER M5 ;
        RECT  30.432 0 30.456 0.084 ;
    END
  END b_d[177]
  PIN b_d[178]
    DIRECTION INPUT ;
    USE SIGNAL ;
    PORT
      LAYER M3 ;
        RECT  30.6 0 30.618 0.038 ;
    END
  END b_d[178]
  PIN b_d[179]
    DIRECTION INPUT ;
    USE SIGNAL ;
    PORT
      LAYER M5 ;
        RECT  30.768 0 30.792 0.084 ;
    END
  END b_d[179]
  PIN b_d[17]
    DIRECTION INPUT ;
    USE SIGNAL ;
    PORT
      LAYER M5 ;
        RECT  3.456 0 3.48 0.084 ;
    END
  END b_d[17]
  PIN b_d[180]
    DIRECTION INPUT ;
    USE SIGNAL ;
    PORT
      LAYER M3 ;
        RECT  30.96 0 30.978 0.038 ;
    END
  END b_d[180]
  PIN b_d[181]
    DIRECTION INPUT ;
    USE SIGNAL ;
    PORT
      LAYER M5 ;
        RECT  31.104 0 31.128 0.084 ;
    END
  END b_d[181]
  PIN b_d[182]
    DIRECTION INPUT ;
    USE SIGNAL ;
    PORT
      LAYER M3 ;
        RECT  31.284 0 31.302 0.038 ;
    END
  END b_d[182]
  PIN b_d[183]
    DIRECTION INPUT ;
    USE SIGNAL ;
    PORT
      LAYER M5 ;
        RECT  31.44 0 31.464 0.084 ;
    END
  END b_d[183]
  PIN b_d[184]
    DIRECTION INPUT ;
    USE SIGNAL ;
    PORT
      LAYER M3 ;
        RECT  31.608 0 31.626 0.038 ;
    END
  END b_d[184]
  PIN b_d[185]
    DIRECTION INPUT ;
    USE SIGNAL ;
    PORT
      LAYER M5 ;
        RECT  31.776 0 31.8 0.084 ;
    END
  END b_d[185]
  PIN b_d[186]
    DIRECTION INPUT ;
    USE SIGNAL ;
    PORT
      LAYER M3 ;
        RECT  31.968 0 31.986 0.038 ;
    END
  END b_d[186]
  PIN b_d[187]
    DIRECTION INPUT ;
    USE SIGNAL ;
    PORT
      LAYER M5 ;
        RECT  32.112 0 32.136 0.084 ;
    END
  END b_d[187]
  PIN b_d[188]
    DIRECTION INPUT ;
    USE SIGNAL ;
    PORT
      LAYER M3 ;
        RECT  32.292 0 32.31 0.038 ;
    END
  END b_d[188]
  PIN b_d[189]
    DIRECTION INPUT ;
    USE SIGNAL ;
    PORT
      LAYER M5 ;
        RECT  32.448 0 32.472 0.084 ;
    END
  END b_d[189]
  PIN b_d[18]
    DIRECTION INPUT ;
    USE SIGNAL ;
    PORT
      LAYER M3 ;
        RECT  3.636 0 3.654 0.038 ;
    END
  END b_d[18]
  PIN b_d[190]
    DIRECTION INPUT ;
    USE SIGNAL ;
    PORT
      LAYER M3 ;
        RECT  32.616 0 32.634 0.038 ;
    END
  END b_d[190]
  PIN b_d[191]
    DIRECTION INPUT ;
    USE SIGNAL ;
    PORT
      LAYER M5 ;
        RECT  32.784 0 32.808 0.084 ;
    END
  END b_d[191]
  PIN b_d[192]
    DIRECTION INPUT ;
    USE SIGNAL ;
    PORT
      LAYER M3 ;
        RECT  32.976 0 32.994 0.038 ;
    END
  END b_d[192]
  PIN b_d[193]
    DIRECTION INPUT ;
    USE SIGNAL ;
    PORT
      LAYER M5 ;
        RECT  33.12 0 33.144 0.084 ;
    END
  END b_d[193]
  PIN b_d[194]
    DIRECTION INPUT ;
    USE SIGNAL ;
    PORT
      LAYER M3 ;
        RECT  33.3 0 33.318 0.038 ;
    END
  END b_d[194]
  PIN b_d[195]
    DIRECTION INPUT ;
    USE SIGNAL ;
    PORT
      LAYER M5 ;
        RECT  33.456 0 33.48 0.084 ;
    END
  END b_d[195]
  PIN b_d[196]
    DIRECTION INPUT ;
    USE SIGNAL ;
    PORT
      LAYER M3 ;
        RECT  33.624 0 33.642 0.038 ;
    END
  END b_d[196]
  PIN b_d[197]
    DIRECTION INPUT ;
    USE SIGNAL ;
    PORT
      LAYER M5 ;
        RECT  33.792 0 33.816 0.084 ;
    END
  END b_d[197]
  PIN b_d[198]
    DIRECTION INPUT ;
    USE SIGNAL ;
    PORT
      LAYER M3 ;
        RECT  33.984 0 34.002 0.038 ;
    END
  END b_d[198]
  PIN b_d[199]
    DIRECTION INPUT ;
    USE SIGNAL ;
    PORT
      LAYER M5 ;
        RECT  34.128 0 34.152 0.084 ;
    END
  END b_d[199]
  PIN b_d[19]
    DIRECTION INPUT ;
    USE SIGNAL ;
    PORT
      LAYER M5 ;
        RECT  3.792 0 3.816 0.084 ;
    END
  END b_d[19]
  PIN b_d[1]
    DIRECTION INPUT ;
    USE SIGNAL ;
    PORT
      LAYER M5 ;
        RECT  0.768 0 0.792 0.084 ;
    END
  END b_d[1]
  PIN b_d[200]
    DIRECTION INPUT ;
    USE SIGNAL ;
    PORT
      LAYER M3 ;
        RECT  34.308 0 34.326 0.038 ;
    END
  END b_d[200]
  PIN b_d[201]
    DIRECTION INPUT ;
    USE SIGNAL ;
    PORT
      LAYER M5 ;
        RECT  34.464 0 34.488 0.084 ;
    END
  END b_d[201]
  PIN b_d[202]
    DIRECTION INPUT ;
    USE SIGNAL ;
    PORT
      LAYER M3 ;
        RECT  34.668 0 34.686 0.038 ;
    END
  END b_d[202]
  PIN b_d[203]
    DIRECTION INPUT ;
    USE SIGNAL ;
    PORT
      LAYER M5 ;
        RECT  34.8 0 34.824 0.084 ;
    END
  END b_d[203]
  PIN b_d[204]
    DIRECTION INPUT ;
    USE SIGNAL ;
    PORT
      LAYER M3 ;
        RECT  34.992 0 35.01 0.038 ;
    END
  END b_d[204]
  PIN b_d[205]
    DIRECTION INPUT ;
    USE SIGNAL ;
    PORT
      LAYER M5 ;
        RECT  35.136 0 35.16 0.084 ;
    END
  END b_d[205]
  PIN b_d[206]
    DIRECTION INPUT ;
    USE SIGNAL ;
    PORT
      LAYER M3 ;
        RECT  35.316 0 35.334 0.038 ;
    END
  END b_d[206]
  PIN b_d[207]
    DIRECTION INPUT ;
    USE SIGNAL ;
    PORT
      LAYER M5 ;
        RECT  35.472 0 35.496 0.084 ;
    END
  END b_d[207]
  PIN b_d[208]
    DIRECTION INPUT ;
    USE SIGNAL ;
    PORT
      LAYER M3 ;
        RECT  35.676 0 35.694 0.038 ;
    END
  END b_d[208]
  PIN b_d[209]
    DIRECTION INPUT ;
    USE SIGNAL ;
    PORT
      LAYER M5 ;
        RECT  35.808 0 35.832 0.084 ;
    END
  END b_d[209]
  PIN b_d[20]
    DIRECTION INPUT ;
    USE SIGNAL ;
    PORT
      LAYER M3 ;
        RECT  3.996 0 4.014 0.038 ;
    END
  END b_d[20]
  PIN b_d[210]
    DIRECTION INPUT ;
    USE SIGNAL ;
    PORT
      LAYER M3 ;
        RECT  36 0 36.018 0.038 ;
    END
  END b_d[210]
  PIN b_d[211]
    DIRECTION INPUT ;
    USE SIGNAL ;
    PORT
      LAYER M5 ;
        RECT  36.144 0 36.168 0.084 ;
    END
  END b_d[211]
  PIN b_d[212]
    DIRECTION INPUT ;
    USE SIGNAL ;
    PORT
      LAYER M3 ;
        RECT  36.324 0 36.342 0.038 ;
    END
  END b_d[212]
  PIN b_d[213]
    DIRECTION INPUT ;
    USE SIGNAL ;
    PORT
      LAYER M5 ;
        RECT  36.48 0 36.504 0.084 ;
    END
  END b_d[213]
  PIN b_d[214]
    DIRECTION INPUT ;
    USE SIGNAL ;
    PORT
      LAYER M3 ;
        RECT  36.684 0 36.702 0.038 ;
    END
  END b_d[214]
  PIN b_d[215]
    DIRECTION INPUT ;
    USE SIGNAL ;
    PORT
      LAYER M5 ;
        RECT  36.816 0 36.84 0.084 ;
    END
  END b_d[215]
  PIN b_d[216]
    DIRECTION INPUT ;
    USE SIGNAL ;
    PORT
      LAYER M3 ;
        RECT  37.008 0 37.026 0.038 ;
    END
  END b_d[216]
  PIN b_d[217]
    DIRECTION INPUT ;
    USE SIGNAL ;
    PORT
      LAYER M5 ;
        RECT  37.152 0 37.176 0.084 ;
    END
  END b_d[217]
  PIN b_d[218]
    DIRECTION INPUT ;
    USE SIGNAL ;
    PORT
      LAYER M3 ;
        RECT  37.332 0 37.35 0.038 ;
    END
  END b_d[218]
  PIN b_d[219]
    DIRECTION INPUT ;
    USE SIGNAL ;
    PORT
      LAYER M5 ;
        RECT  37.488 0 37.512 0.084 ;
    END
  END b_d[219]
  PIN b_d[21]
    DIRECTION INPUT ;
    USE SIGNAL ;
    PORT
      LAYER M5 ;
        RECT  4.128 0 4.152 0.084 ;
    END
  END b_d[21]
  PIN b_d[220]
    DIRECTION INPUT ;
    USE SIGNAL ;
    PORT
      LAYER M3 ;
        RECT  37.692 0 37.71 0.038 ;
    END
  END b_d[220]
  PIN b_d[221]
    DIRECTION INPUT ;
    USE SIGNAL ;
    PORT
      LAYER M5 ;
        RECT  37.872 0 37.896 0.084 ;
    END
  END b_d[221]
  PIN b_d[222]
    DIRECTION INPUT ;
    USE SIGNAL ;
    PORT
      LAYER M3 ;
        RECT  38.016 0 38.034 0.038 ;
    END
  END b_d[222]
  PIN b_d[223]
    DIRECTION INPUT ;
    USE SIGNAL ;
    PORT
      LAYER M5 ;
        RECT  38.208 0 38.232 0.084 ;
    END
  END b_d[223]
  PIN b_d[224]
    DIRECTION INPUT ;
    USE SIGNAL ;
    PORT
      LAYER M3 ;
        RECT  38.34 0 38.358 0.038 ;
    END
  END b_d[224]
  PIN b_d[225]
    DIRECTION INPUT ;
    USE SIGNAL ;
    PORT
      LAYER M5 ;
        RECT  38.544 0 38.568 0.084 ;
    END
  END b_d[225]
  PIN b_d[226]
    DIRECTION INPUT ;
    USE SIGNAL ;
    PORT
      LAYER M3 ;
        RECT  38.7 0 38.718 0.038 ;
    END
  END b_d[226]
  PIN b_d[227]
    DIRECTION INPUT ;
    USE SIGNAL ;
    PORT
      LAYER M5 ;
        RECT  38.88 0 38.904 0.084 ;
    END
  END b_d[227]
  PIN b_d[228]
    DIRECTION INPUT ;
    USE SIGNAL ;
    PORT
      LAYER M3 ;
        RECT  39.024 0 39.042 0.038 ;
    END
  END b_d[228]
  PIN b_d[229]
    DIRECTION INPUT ;
    USE SIGNAL ;
    PORT
      LAYER M5 ;
        RECT  39.216 0 39.24 0.084 ;
    END
  END b_d[229]
  PIN b_d[22]
    DIRECTION INPUT ;
    USE SIGNAL ;
    PORT
      LAYER M3 ;
        RECT  4.32 0 4.338 0.038 ;
    END
  END b_d[22]
  PIN b_d[230]
    DIRECTION INPUT ;
    USE SIGNAL ;
    PORT
      LAYER M3 ;
        RECT  39.384 0 39.402 0.038 ;
    END
  END b_d[230]
  PIN b_d[231]
    DIRECTION INPUT ;
    USE SIGNAL ;
    PORT
      LAYER M5 ;
        RECT  39.552 0 39.576 0.084 ;
    END
  END b_d[231]
  PIN b_d[232]
    DIRECTION INPUT ;
    USE SIGNAL ;
    PORT
      LAYER M3 ;
        RECT  39.708 0 39.726 0.038 ;
    END
  END b_d[232]
  PIN b_d[233]
    DIRECTION INPUT ;
    USE SIGNAL ;
    PORT
      LAYER M5 ;
        RECT  39.888 0 39.912 0.084 ;
    END
  END b_d[233]
  PIN b_d[234]
    DIRECTION INPUT ;
    USE SIGNAL ;
    PORT
      LAYER M3 ;
        RECT  40.032 0 40.05 0.038 ;
    END
  END b_d[234]
  PIN b_d[235]
    DIRECTION INPUT ;
    USE SIGNAL ;
    PORT
      LAYER M5 ;
        RECT  40.224 0 40.248 0.084 ;
    END
  END b_d[235]
  PIN b_d[236]
    DIRECTION INPUT ;
    USE SIGNAL ;
    PORT
      LAYER M3 ;
        RECT  40.392 0 40.41 0.038 ;
    END
  END b_d[236]
  PIN b_d[237]
    DIRECTION INPUT ;
    USE SIGNAL ;
    PORT
      LAYER M5 ;
        RECT  40.56 0 40.584 0.084 ;
    END
  END b_d[237]
  PIN b_d[238]
    DIRECTION INPUT ;
    USE SIGNAL ;
    PORT
      LAYER M3 ;
        RECT  40.716 0 40.734 0.038 ;
    END
  END b_d[238]
  PIN b_d[239]
    DIRECTION INPUT ;
    USE SIGNAL ;
    PORT
      LAYER M5 ;
        RECT  40.896 0 40.92 0.084 ;
    END
  END b_d[239]
  PIN b_d[23]
    DIRECTION INPUT ;
    USE SIGNAL ;
    PORT
      LAYER M5 ;
        RECT  4.464 0 4.488 0.084 ;
    END
  END b_d[23]
  PIN b_d[240]
    DIRECTION INPUT ;
    USE SIGNAL ;
    PORT
      LAYER M3 ;
        RECT  41.04 0 41.058 0.038 ;
    END
  END b_d[240]
  PIN b_d[241]
    DIRECTION INPUT ;
    USE SIGNAL ;
    PORT
      LAYER M5 ;
        RECT  41.232 0 41.256 0.084 ;
    END
  END b_d[241]
  PIN b_d[242]
    DIRECTION INPUT ;
    USE SIGNAL ;
    PORT
      LAYER M3 ;
        RECT  41.4 0 41.418 0.038 ;
    END
  END b_d[242]
  PIN b_d[243]
    DIRECTION INPUT ;
    USE SIGNAL ;
    PORT
      LAYER M5 ;
        RECT  41.568 0 41.592 0.084 ;
    END
  END b_d[243]
  PIN b_d[244]
    DIRECTION INPUT ;
    USE SIGNAL ;
    PORT
      LAYER M3 ;
        RECT  41.724 0 41.742 0.038 ;
    END
  END b_d[244]
  PIN b_d[245]
    DIRECTION INPUT ;
    USE SIGNAL ;
    PORT
      LAYER M5 ;
        RECT  41.904 0 41.928 0.084 ;
    END
  END b_d[245]
  PIN b_d[246]
    DIRECTION INPUT ;
    USE SIGNAL ;
    PORT
      LAYER M3 ;
        RECT  42.048 0 42.066 0.038 ;
    END
  END b_d[246]
  PIN b_d[247]
    DIRECTION INPUT ;
    USE SIGNAL ;
    PORT
      LAYER M5 ;
        RECT  42.24 0 42.264 0.084 ;
    END
  END b_d[247]
  PIN b_d[248]
    DIRECTION INPUT ;
    USE SIGNAL ;
    PORT
      LAYER M3 ;
        RECT  42.408 0 42.426 0.038 ;
    END
  END b_d[248]
  PIN b_d[249]
    DIRECTION INPUT ;
    USE SIGNAL ;
    PORT
      LAYER M5 ;
        RECT  42.576 0 42.6 0.084 ;
    END
  END b_d[249]
  PIN b_d[24]
    DIRECTION INPUT ;
    USE SIGNAL ;
    PORT
      LAYER M3 ;
        RECT  4.644 0 4.662 0.038 ;
    END
  END b_d[24]
  PIN b_d[250]
    DIRECTION INPUT ;
    USE SIGNAL ;
    PORT
      LAYER M3 ;
        RECT  42.732 0 42.75 0.038 ;
    END
  END b_d[250]
  PIN b_d[251]
    DIRECTION INPUT ;
    USE SIGNAL ;
    PORT
      LAYER M5 ;
        RECT  42.912 0 42.936 0.084 ;
    END
  END b_d[251]
  PIN b_d[252]
    DIRECTION INPUT ;
    USE SIGNAL ;
    PORT
      LAYER M3 ;
        RECT  43.092 0 43.11 0.038 ;
    END
  END b_d[252]
  PIN b_d[253]
    DIRECTION INPUT ;
    USE SIGNAL ;
    PORT
      LAYER M5 ;
        RECT  43.248 0 43.272 0.084 ;
    END
  END b_d[253]
  PIN b_d[254]
    DIRECTION INPUT ;
    USE SIGNAL ;
    PORT
      LAYER M3 ;
        RECT  43.416 0 43.434 0.038 ;
    END
  END b_d[254]
  PIN b_d[255]
    DIRECTION INPUT ;
    USE SIGNAL ;
    PORT
      LAYER M5 ;
        RECT  43.584 0 43.608 0.084 ;
    END
  END b_d[255]
  PIN b_d[256]
    DIRECTION INPUT ;
    USE SIGNAL ;
    PORT
      LAYER M3 ;
        RECT  43.74 0 43.758 0.038 ;
    END
  END b_d[256]
  PIN b_d[257]
    DIRECTION INPUT ;
    USE SIGNAL ;
    PORT
      LAYER M5 ;
        RECT  43.92 0 43.944 0.084 ;
    END
  END b_d[257]
  PIN b_d[258]
    DIRECTION INPUT ;
    USE SIGNAL ;
    PORT
      LAYER M3 ;
        RECT  44.1 0 44.118 0.038 ;
    END
  END b_d[258]
  PIN b_d[259]
    DIRECTION INPUT ;
    USE SIGNAL ;
    PORT
      LAYER M5 ;
        RECT  44.256 0 44.28 0.084 ;
    END
  END b_d[259]
  PIN b_d[25]
    DIRECTION INPUT ;
    USE SIGNAL ;
    PORT
      LAYER M5 ;
        RECT  4.848 0 4.872 0.084 ;
    END
  END b_d[25]
  PIN b_d[260]
    DIRECTION INPUT ;
    USE SIGNAL ;
    PORT
      LAYER M3 ;
        RECT  44.424 0 44.442 0.038 ;
    END
  END b_d[260]
  PIN b_d[261]
    DIRECTION INPUT ;
    USE SIGNAL ;
    PORT
      LAYER M5 ;
        RECT  44.592 0 44.616 0.084 ;
    END
  END b_d[261]
  PIN b_d[262]
    DIRECTION INPUT ;
    USE SIGNAL ;
    PORT
      LAYER M3 ;
        RECT  44.748 0 44.766 0.038 ;
    END
  END b_d[262]
  PIN b_d[263]
    DIRECTION INPUT ;
    USE SIGNAL ;
    PORT
      LAYER M5 ;
        RECT  44.928 0 44.952 0.084 ;
    END
  END b_d[263]
  PIN b_d[264]
    DIRECTION INPUT ;
    USE SIGNAL ;
    PORT
      LAYER M3 ;
        RECT  45.108 0 45.126 0.038 ;
    END
  END b_d[264]
  PIN b_d[265]
    DIRECTION INPUT ;
    USE SIGNAL ;
    PORT
      LAYER M5 ;
        RECT  45.264 0 45.288 0.084 ;
    END
  END b_d[265]
  PIN b_d[266]
    DIRECTION INPUT ;
    USE SIGNAL ;
    PORT
      LAYER M3 ;
        RECT  45.432 0 45.45 0.038 ;
    END
  END b_d[266]
  PIN b_d[267]
    DIRECTION INPUT ;
    USE SIGNAL ;
    PORT
      LAYER M5 ;
        RECT  45.6 0 45.624 0.084 ;
    END
  END b_d[267]
  PIN b_d[268]
    DIRECTION INPUT ;
    USE SIGNAL ;
    PORT
      LAYER M3 ;
        RECT  45.756 0 45.774 0.038 ;
    END
  END b_d[268]
  PIN b_d[269]
    DIRECTION INPUT ;
    USE SIGNAL ;
    PORT
      LAYER M5 ;
        RECT  45.936 0 45.96 0.084 ;
    END
  END b_d[269]
  PIN b_d[26]
    DIRECTION INPUT ;
    USE SIGNAL ;
    PORT
      LAYER M3 ;
        RECT  5.004 0 5.022 0.038 ;
    END
  END b_d[26]
  PIN b_d[270]
    DIRECTION INPUT ;
    USE SIGNAL ;
    PORT
      LAYER M3 ;
        RECT  46.116 0 46.134 0.038 ;
    END
  END b_d[270]
  PIN b_d[271]
    DIRECTION INPUT ;
    USE SIGNAL ;
    PORT
      LAYER M5 ;
        RECT  46.272 0 46.296 0.084 ;
    END
  END b_d[271]
  PIN b_d[272]
    DIRECTION INPUT ;
    USE SIGNAL ;
    PORT
      LAYER M3 ;
        RECT  46.44 0 46.458 0.038 ;
    END
  END b_d[272]
  PIN b_d[273]
    DIRECTION INPUT ;
    USE SIGNAL ;
    PORT
      LAYER M5 ;
        RECT  46.608 0 46.632 0.084 ;
    END
  END b_d[273]
  PIN b_d[274]
    DIRECTION INPUT ;
    USE SIGNAL ;
    PORT
      LAYER M3 ;
        RECT  46.764 0 46.782 0.038 ;
    END
  END b_d[274]
  PIN b_d[275]
    DIRECTION INPUT ;
    USE SIGNAL ;
    PORT
      LAYER M5 ;
        RECT  46.944 0 46.968 0.084 ;
    END
  END b_d[275]
  PIN b_d[276]
    DIRECTION INPUT ;
    USE SIGNAL ;
    PORT
      LAYER M3 ;
        RECT  47.124 0 47.142 0.038 ;
    END
  END b_d[276]
  PIN b_d[277]
    DIRECTION INPUT ;
    USE SIGNAL ;
    PORT
      LAYER M5 ;
        RECT  47.28 0 47.304 0.084 ;
    END
  END b_d[277]
  PIN b_d[278]
    DIRECTION INPUT ;
    USE SIGNAL ;
    PORT
      LAYER M3 ;
        RECT  47.448 0 47.466 0.038 ;
    END
  END b_d[278]
  PIN b_d[279]
    DIRECTION INPUT ;
    USE SIGNAL ;
    PORT
      LAYER M5 ;
        RECT  47.616 0 47.64 0.084 ;
    END
  END b_d[279]
  PIN b_d[27]
    DIRECTION INPUT ;
    USE SIGNAL ;
    PORT
      LAYER M5 ;
        RECT  5.184 0 5.208 0.084 ;
    END
  END b_d[27]
  PIN b_d[280]
    DIRECTION INPUT ;
    USE SIGNAL ;
    PORT
      LAYER M3 ;
        RECT  47.808 0 47.826 0.038 ;
    END
  END b_d[280]
  PIN b_d[281]
    DIRECTION INPUT ;
    USE SIGNAL ;
    PORT
      LAYER M5 ;
        RECT  47.952 0 47.976 0.084 ;
    END
  END b_d[281]
  PIN b_d[282]
    DIRECTION INPUT ;
    USE SIGNAL ;
    PORT
      LAYER M3 ;
        RECT  48.132 0 48.15 0.038 ;
    END
  END b_d[282]
  PIN b_d[283]
    DIRECTION INPUT ;
    USE SIGNAL ;
    PORT
      LAYER M5 ;
        RECT  48.288 0 48.312 0.084 ;
    END
  END b_d[283]
  PIN b_d[284]
    DIRECTION INPUT ;
    USE SIGNAL ;
    PORT
      LAYER M3 ;
        RECT  48.456 0 48.474 0.038 ;
    END
  END b_d[284]
  PIN b_d[285]
    DIRECTION INPUT ;
    USE SIGNAL ;
    PORT
      LAYER M5 ;
        RECT  48.624 0 48.648 0.084 ;
    END
  END b_d[285]
  PIN b_d[286]
    DIRECTION INPUT ;
    USE SIGNAL ;
    PORT
      LAYER M3 ;
        RECT  48.816 0 48.834 0.038 ;
    END
  END b_d[286]
  PIN b_d[287]
    DIRECTION INPUT ;
    USE SIGNAL ;
    PORT
      LAYER M5 ;
        RECT  48.96 0 48.984 0.084 ;
    END
  END b_d[287]
  PIN b_d[288]
    DIRECTION INPUT ;
    USE SIGNAL ;
    PORT
      LAYER M3 ;
        RECT  49.14 0 49.158 0.038 ;
    END
  END b_d[288]
  PIN b_d[289]
    DIRECTION INPUT ;
    USE SIGNAL ;
    PORT
      LAYER M5 ;
        RECT  49.296 0 49.32 0.084 ;
    END
  END b_d[289]
  PIN b_d[28]
    DIRECTION INPUT ;
    USE SIGNAL ;
    PORT
      LAYER M3 ;
        RECT  5.328 0 5.346 0.038 ;
    END
  END b_d[28]
  PIN b_d[290]
    DIRECTION INPUT ;
    USE SIGNAL ;
    PORT
      LAYER M3 ;
        RECT  49.464 0 49.482 0.038 ;
    END
  END b_d[290]
  PIN b_d[291]
    DIRECTION INPUT ;
    USE SIGNAL ;
    PORT
      LAYER M5 ;
        RECT  49.632 0 49.656 0.084 ;
    END
  END b_d[291]
  PIN b_d[292]
    DIRECTION INPUT ;
    USE SIGNAL ;
    PORT
      LAYER M3 ;
        RECT  49.824 0 49.842 0.038 ;
    END
  END b_d[292]
  PIN b_d[293]
    DIRECTION INPUT ;
    USE SIGNAL ;
    PORT
      LAYER M5 ;
        RECT  49.968 0 49.992 0.084 ;
    END
  END b_d[293]
  PIN b_d[294]
    DIRECTION INPUT ;
    USE SIGNAL ;
    PORT
      LAYER M3 ;
        RECT  50.148 0 50.166 0.038 ;
    END
  END b_d[294]
  PIN b_d[295]
    DIRECTION INPUT ;
    USE SIGNAL ;
    PORT
      LAYER M5 ;
        RECT  50.304 0 50.328 0.084 ;
    END
  END b_d[295]
  PIN b_d[296]
    DIRECTION INPUT ;
    USE SIGNAL ;
    PORT
      LAYER M3 ;
        RECT  50.472 0 50.49 0.038 ;
    END
  END b_d[296]
  PIN b_d[297]
    DIRECTION INPUT ;
    USE SIGNAL ;
    PORT
      LAYER M5 ;
        RECT  50.64 0 50.664 0.084 ;
    END
  END b_d[297]
  PIN b_d[298]
    DIRECTION INPUT ;
    USE SIGNAL ;
    PORT
      LAYER M3 ;
        RECT  50.832 0 50.85 0.038 ;
    END
  END b_d[298]
  PIN b_d[299]
    DIRECTION INPUT ;
    USE SIGNAL ;
    PORT
      LAYER M5 ;
        RECT  50.976 0 51 0.084 ;
    END
  END b_d[299]
  PIN b_d[29]
    DIRECTION INPUT ;
    USE SIGNAL ;
    PORT
      LAYER M5 ;
        RECT  5.52 0 5.544 0.084 ;
    END
  END b_d[29]
  PIN b_d[2]
    DIRECTION INPUT ;
    USE SIGNAL ;
    PORT
      LAYER M3 ;
        RECT  0.936 0 0.954 0.038 ;
    END
  END b_d[2]
  PIN b_d[300]
    DIRECTION INPUT ;
    USE SIGNAL ;
    PORT
      LAYER M3 ;
        RECT  51.156 0 51.174 0.038 ;
    END
  END b_d[300]
  PIN b_d[301]
    DIRECTION INPUT ;
    USE SIGNAL ;
    PORT
      LAYER M5 ;
        RECT  51.312 0 51.336 0.084 ;
    END
  END b_d[301]
  PIN b_d[302]
    DIRECTION INPUT ;
    USE SIGNAL ;
    PORT
      LAYER M3 ;
        RECT  51.516 0 51.534 0.038 ;
    END
  END b_d[302]
  PIN b_d[303]
    DIRECTION INPUT ;
    USE SIGNAL ;
    PORT
      LAYER M5 ;
        RECT  51.648 0 51.672 0.084 ;
    END
  END b_d[303]
  PIN b_d[304]
    DIRECTION INPUT ;
    USE SIGNAL ;
    PORT
      LAYER M3 ;
        RECT  51.84 0 51.858 0.038 ;
    END
  END b_d[304]
  PIN b_d[305]
    DIRECTION INPUT ;
    USE SIGNAL ;
    PORT
      LAYER M5 ;
        RECT  51.984 0 52.008 0.084 ;
    END
  END b_d[305]
  PIN b_d[306]
    DIRECTION INPUT ;
    USE SIGNAL ;
    PORT
      LAYER M3 ;
        RECT  52.164 0 52.182 0.038 ;
    END
  END b_d[306]
  PIN b_d[307]
    DIRECTION INPUT ;
    USE SIGNAL ;
    PORT
      LAYER M5 ;
        RECT  52.32 0 52.344 0.084 ;
    END
  END b_d[307]
  PIN b_d[308]
    DIRECTION INPUT ;
    USE SIGNAL ;
    PORT
      LAYER M3 ;
        RECT  52.524 0 52.542 0.038 ;
    END
  END b_d[308]
  PIN b_d[309]
    DIRECTION INPUT ;
    USE SIGNAL ;
    PORT
      LAYER M5 ;
        RECT  52.656 0 52.68 0.084 ;
    END
  END b_d[309]
  PIN b_d[30]
    DIRECTION INPUT ;
    USE SIGNAL ;
    PORT
      LAYER M3 ;
        RECT  5.688 0 5.706 0.038 ;
    END
  END b_d[30]
  PIN b_d[310]
    DIRECTION INPUT ;
    USE SIGNAL ;
    PORT
      LAYER M3 ;
        RECT  52.848 0 52.866 0.038 ;
    END
  END b_d[310]
  PIN b_d[311]
    DIRECTION INPUT ;
    USE SIGNAL ;
    PORT
      LAYER M5 ;
        RECT  52.992 0 53.016 0.084 ;
    END
  END b_d[311]
  PIN b_d[312]
    DIRECTION INPUT ;
    USE SIGNAL ;
    PORT
      LAYER M3 ;
        RECT  53.172 0 53.19 0.038 ;
    END
  END b_d[312]
  PIN b_d[313]
    DIRECTION INPUT ;
    USE SIGNAL ;
    PORT
      LAYER M5 ;
        RECT  53.328 0 53.352 0.084 ;
    END
  END b_d[313]
  PIN b_d[314]
    DIRECTION INPUT ;
    USE SIGNAL ;
    PORT
      LAYER M3 ;
        RECT  53.532 0 53.55 0.038 ;
    END
  END b_d[314]
  PIN b_d[315]
    DIRECTION INPUT ;
    USE SIGNAL ;
    PORT
      LAYER M5 ;
        RECT  53.664 0 53.688 0.084 ;
    END
  END b_d[315]
  PIN b_d[316]
    DIRECTION INPUT ;
    USE SIGNAL ;
    PORT
      LAYER M3 ;
        RECT  53.856 0 53.874 0.038 ;
    END
  END b_d[316]
  PIN b_d[317]
    DIRECTION INPUT ;
    USE SIGNAL ;
    PORT
      LAYER M5 ;
        RECT  54 0 54.024 0.084 ;
    END
  END b_d[317]
  PIN b_d[318]
    DIRECTION INPUT ;
    USE SIGNAL ;
    PORT
      LAYER M3 ;
        RECT  54.18 0 54.198 0.038 ;
    END
  END b_d[318]
  PIN b_d[319]
    DIRECTION INPUT ;
    USE SIGNAL ;
    PORT
      LAYER M5 ;
        RECT  54.384 0 54.408 0.084 ;
    END
  END b_d[319]
  PIN b_d[31]
    DIRECTION INPUT ;
    USE SIGNAL ;
    PORT
      LAYER M5 ;
        RECT  5.856 0 5.88 0.084 ;
    END
  END b_d[31]
  PIN b_d[320]
    DIRECTION INPUT ;
    USE SIGNAL ;
    PORT
      LAYER M3 ;
        RECT  54.54 0 54.558 0.038 ;
    END
  END b_d[320]
  PIN b_d[321]
    DIRECTION INPUT ;
    USE SIGNAL ;
    PORT
      LAYER M5 ;
        RECT  54.72 0 54.744 0.084 ;
    END
  END b_d[321]
  PIN b_d[322]
    DIRECTION INPUT ;
    USE SIGNAL ;
    PORT
      LAYER M3 ;
        RECT  54.864 0 54.882 0.038 ;
    END
  END b_d[322]
  PIN b_d[323]
    DIRECTION INPUT ;
    USE SIGNAL ;
    PORT
      LAYER M5 ;
        RECT  55.056 0 55.08 0.084 ;
    END
  END b_d[323]
  PIN b_d[324]
    DIRECTION INPUT ;
    USE SIGNAL ;
    PORT
      LAYER M3 ;
        RECT  55.188 0 55.206 0.038 ;
    END
  END b_d[324]
  PIN b_d[325]
    DIRECTION INPUT ;
    USE SIGNAL ;
    PORT
      LAYER M5 ;
        RECT  55.392 0 55.416 0.084 ;
    END
  END b_d[325]
  PIN b_d[326]
    DIRECTION INPUT ;
    USE SIGNAL ;
    PORT
      LAYER M3 ;
        RECT  55.548 0 55.566 0.038 ;
    END
  END b_d[326]
  PIN b_d[327]
    DIRECTION INPUT ;
    USE SIGNAL ;
    PORT
      LAYER M5 ;
        RECT  55.728 0 55.752 0.084 ;
    END
  END b_d[327]
  PIN b_d[328]
    DIRECTION INPUT ;
    USE SIGNAL ;
    PORT
      LAYER M3 ;
        RECT  55.872 0 55.89 0.038 ;
    END
  END b_d[328]
  PIN b_d[329]
    DIRECTION INPUT ;
    USE SIGNAL ;
    PORT
      LAYER M5 ;
        RECT  56.064 0 56.088 0.084 ;
    END
  END b_d[329]
  PIN b_d[32]
    DIRECTION INPUT ;
    USE SIGNAL ;
    PORT
      LAYER M3 ;
        RECT  6.012 0 6.03 0.038 ;
    END
  END b_d[32]
  PIN b_d[330]
    DIRECTION INPUT ;
    USE SIGNAL ;
    PORT
      LAYER M3 ;
        RECT  56.232 0 56.25 0.038 ;
    END
  END b_d[330]
  PIN b_d[331]
    DIRECTION INPUT ;
    USE SIGNAL ;
    PORT
      LAYER M5 ;
        RECT  56.4 0 56.424 0.084 ;
    END
  END b_d[331]
  PIN b_d[332]
    DIRECTION INPUT ;
    USE SIGNAL ;
    PORT
      LAYER M3 ;
        RECT  56.556 0 56.574 0.038 ;
    END
  END b_d[332]
  PIN b_d[333]
    DIRECTION INPUT ;
    USE SIGNAL ;
    PORT
      LAYER M5 ;
        RECT  56.736 0 56.76 0.084 ;
    END
  END b_d[333]
  PIN b_d[334]
    DIRECTION INPUT ;
    USE SIGNAL ;
    PORT
      LAYER M3 ;
        RECT  56.88 0 56.898 0.038 ;
    END
  END b_d[334]
  PIN b_d[335]
    DIRECTION INPUT ;
    USE SIGNAL ;
    PORT
      LAYER M5 ;
        RECT  57.072 0 57.096 0.084 ;
    END
  END b_d[335]
  PIN b_d[336]
    DIRECTION INPUT ;
    USE SIGNAL ;
    PORT
      LAYER M3 ;
        RECT  57.24 0 57.258 0.038 ;
    END
  END b_d[336]
  PIN b_d[337]
    DIRECTION INPUT ;
    USE SIGNAL ;
    PORT
      LAYER M5 ;
        RECT  57.408 0 57.432 0.084 ;
    END
  END b_d[337]
  PIN b_d[338]
    DIRECTION INPUT ;
    USE SIGNAL ;
    PORT
      LAYER M3 ;
        RECT  57.564 0 57.582 0.038 ;
    END
  END b_d[338]
  PIN b_d[339]
    DIRECTION INPUT ;
    USE SIGNAL ;
    PORT
      LAYER M5 ;
        RECT  57.744 0 57.768 0.084 ;
    END
  END b_d[339]
  PIN b_d[33]
    DIRECTION INPUT ;
    USE SIGNAL ;
    PORT
      LAYER M5 ;
        RECT  6.192 0 6.216 0.084 ;
    END
  END b_d[33]
  PIN b_d[340]
    DIRECTION INPUT ;
    USE SIGNAL ;
    PORT
      LAYER M3 ;
        RECT  57.888 0 57.906 0.038 ;
    END
  END b_d[340]
  PIN b_d[341]
    DIRECTION INPUT ;
    USE SIGNAL ;
    PORT
      LAYER M5 ;
        RECT  58.08 0 58.104 0.084 ;
    END
  END b_d[341]
  PIN b_d[342]
    DIRECTION INPUT ;
    USE SIGNAL ;
    PORT
      LAYER M3 ;
        RECT  58.248 0 58.266 0.038 ;
    END
  END b_d[342]
  PIN b_d[343]
    DIRECTION INPUT ;
    USE SIGNAL ;
    PORT
      LAYER M5 ;
        RECT  58.416 0 58.44 0.084 ;
    END
  END b_d[343]
  PIN b_d[344]
    DIRECTION INPUT ;
    USE SIGNAL ;
    PORT
      LAYER M3 ;
        RECT  58.572 0 58.59 0.038 ;
    END
  END b_d[344]
  PIN b_d[345]
    DIRECTION INPUT ;
    USE SIGNAL ;
    PORT
      LAYER M5 ;
        RECT  58.752 0 58.776 0.084 ;
    END
  END b_d[345]
  PIN b_d[346]
    DIRECTION INPUT ;
    USE SIGNAL ;
    PORT
      LAYER M3 ;
        RECT  58.896 0 58.914 0.038 ;
    END
  END b_d[346]
  PIN b_d[347]
    DIRECTION INPUT ;
    USE SIGNAL ;
    PORT
      LAYER M5 ;
        RECT  59.088 0 59.112 0.084 ;
    END
  END b_d[347]
  PIN b_d[348]
    DIRECTION INPUT ;
    USE SIGNAL ;
    PORT
      LAYER M3 ;
        RECT  59.256 0 59.274 0.038 ;
    END
  END b_d[348]
  PIN b_d[349]
    DIRECTION INPUT ;
    USE SIGNAL ;
    PORT
      LAYER M5 ;
        RECT  59.424 0 59.448 0.084 ;
    END
  END b_d[349]
  PIN b_d[34]
    DIRECTION INPUT ;
    USE SIGNAL ;
    PORT
      LAYER M3 ;
        RECT  6.336 0 6.354 0.038 ;
    END
  END b_d[34]
  PIN b_d[350]
    DIRECTION INPUT ;
    USE SIGNAL ;
    PORT
      LAYER M3 ;
        RECT  59.58 0 59.598 0.038 ;
    END
  END b_d[350]
  PIN b_d[351]
    DIRECTION INPUT ;
    USE SIGNAL ;
    PORT
      LAYER M5 ;
        RECT  59.76 0 59.784 0.084 ;
    END
  END b_d[351]
  PIN b_d[352]
    DIRECTION INPUT ;
    USE SIGNAL ;
    PORT
      LAYER M3 ;
        RECT  59.94 0 59.958 0.038 ;
    END
  END b_d[352]
  PIN b_d[353]
    DIRECTION INPUT ;
    USE SIGNAL ;
    PORT
      LAYER M5 ;
        RECT  60.096 0 60.12 0.084 ;
    END
  END b_d[353]
  PIN b_d[354]
    DIRECTION INPUT ;
    USE SIGNAL ;
    PORT
      LAYER M3 ;
        RECT  60.264 0 60.282 0.038 ;
    END
  END b_d[354]
  PIN b_d[355]
    DIRECTION INPUT ;
    USE SIGNAL ;
    PORT
      LAYER M5 ;
        RECT  60.432 0 60.456 0.084 ;
    END
  END b_d[355]
  PIN b_d[356]
    DIRECTION INPUT ;
    USE SIGNAL ;
    PORT
      LAYER M3 ;
        RECT  60.588 0 60.606 0.038 ;
    END
  END b_d[356]
  PIN b_d[357]
    DIRECTION INPUT ;
    USE SIGNAL ;
    PORT
      LAYER M5 ;
        RECT  60.768 0 60.792 0.084 ;
    END
  END b_d[357]
  PIN b_d[358]
    DIRECTION INPUT ;
    USE SIGNAL ;
    PORT
      LAYER M3 ;
        RECT  60.948 0 60.966 0.038 ;
    END
  END b_d[358]
  PIN b_d[359]
    DIRECTION INPUT ;
    USE SIGNAL ;
    PORT
      LAYER M5 ;
        RECT  61.104 0 61.128 0.084 ;
    END
  END b_d[359]
  PIN b_d[35]
    DIRECTION INPUT ;
    USE SIGNAL ;
    PORT
      LAYER M5 ;
        RECT  6.528 0 6.552 0.084 ;
    END
  END b_d[35]
  PIN b_d[360]
    DIRECTION INPUT ;
    USE SIGNAL ;
    PORT
      LAYER M3 ;
        RECT  61.272 0 61.29 0.038 ;
    END
  END b_d[360]
  PIN b_d[361]
    DIRECTION INPUT ;
    USE SIGNAL ;
    PORT
      LAYER M5 ;
        RECT  61.44 0 61.464 0.084 ;
    END
  END b_d[361]
  PIN b_d[362]
    DIRECTION INPUT ;
    USE SIGNAL ;
    PORT
      LAYER M3 ;
        RECT  61.596 0 61.614 0.038 ;
    END
  END b_d[362]
  PIN b_d[363]
    DIRECTION INPUT ;
    USE SIGNAL ;
    PORT
      LAYER M5 ;
        RECT  61.776 0 61.8 0.084 ;
    END
  END b_d[363]
  PIN b_d[364]
    DIRECTION INPUT ;
    USE SIGNAL ;
    PORT
      LAYER M3 ;
        RECT  61.956 0 61.974 0.038 ;
    END
  END b_d[364]
  PIN b_d[365]
    DIRECTION INPUT ;
    USE SIGNAL ;
    PORT
      LAYER M5 ;
        RECT  62.112 0 62.136 0.084 ;
    END
  END b_d[365]
  PIN b_d[366]
    DIRECTION INPUT ;
    USE SIGNAL ;
    PORT
      LAYER M3 ;
        RECT  62.28 0 62.298 0.038 ;
    END
  END b_d[366]
  PIN b_d[367]
    DIRECTION INPUT ;
    USE SIGNAL ;
    PORT
      LAYER M5 ;
        RECT  62.448 0 62.472 0.084 ;
    END
  END b_d[367]
  PIN b_d[368]
    DIRECTION INPUT ;
    USE SIGNAL ;
    PORT
      LAYER M3 ;
        RECT  62.604 0 62.622 0.038 ;
    END
  END b_d[368]
  PIN b_d[369]
    DIRECTION INPUT ;
    USE SIGNAL ;
    PORT
      LAYER M5 ;
        RECT  62.784 0 62.808 0.084 ;
    END
  END b_d[369]
  PIN b_d[36]
    DIRECTION INPUT ;
    USE SIGNAL ;
    PORT
      LAYER M3 ;
        RECT  6.696 0 6.714 0.038 ;
    END
  END b_d[36]
  PIN b_d[370]
    DIRECTION INPUT ;
    USE SIGNAL ;
    PORT
      LAYER M3 ;
        RECT  62.964 0 62.982 0.038 ;
    END
  END b_d[370]
  PIN b_d[371]
    DIRECTION INPUT ;
    USE SIGNAL ;
    PORT
      LAYER M5 ;
        RECT  63.12 0 63.144 0.084 ;
    END
  END b_d[371]
  PIN b_d[372]
    DIRECTION INPUT ;
    USE SIGNAL ;
    PORT
      LAYER M3 ;
        RECT  63.288 0 63.306 0.038 ;
    END
  END b_d[372]
  PIN b_d[373]
    DIRECTION INPUT ;
    USE SIGNAL ;
    PORT
      LAYER M5 ;
        RECT  63.456 0 63.48 0.084 ;
    END
  END b_d[373]
  PIN b_d[374]
    DIRECTION INPUT ;
    USE SIGNAL ;
    PORT
      LAYER M3 ;
        RECT  63.648 0 63.666 0.038 ;
    END
  END b_d[374]
  PIN b_d[375]
    DIRECTION INPUT ;
    USE SIGNAL ;
    PORT
      LAYER M5 ;
        RECT  63.792 0 63.816 0.084 ;
    END
  END b_d[375]
  PIN b_d[376]
    DIRECTION INPUT ;
    USE SIGNAL ;
    PORT
      LAYER M3 ;
        RECT  63.972 0 63.99 0.038 ;
    END
  END b_d[376]
  PIN b_d[377]
    DIRECTION INPUT ;
    USE SIGNAL ;
    PORT
      LAYER M5 ;
        RECT  64.128 0 64.152 0.084 ;
    END
  END b_d[377]
  PIN b_d[378]
    DIRECTION INPUT ;
    USE SIGNAL ;
    PORT
      LAYER M3 ;
        RECT  64.296 0 64.314 0.038 ;
    END
  END b_d[378]
  PIN b_d[379]
    DIRECTION INPUT ;
    USE SIGNAL ;
    PORT
      LAYER M5 ;
        RECT  64.464 0 64.488 0.084 ;
    END
  END b_d[379]
  PIN b_d[37]
    DIRECTION INPUT ;
    USE SIGNAL ;
    PORT
      LAYER M5 ;
        RECT  6.864 0 6.888 0.084 ;
    END
  END b_d[37]
  PIN b_d[380]
    DIRECTION INPUT ;
    USE SIGNAL ;
    PORT
      LAYER M3 ;
        RECT  64.656 0 64.674 0.038 ;
    END
  END b_d[380]
  PIN b_d[381]
    DIRECTION INPUT ;
    USE SIGNAL ;
    PORT
      LAYER M5 ;
        RECT  64.8 0 64.824 0.084 ;
    END
  END b_d[381]
  PIN b_d[382]
    DIRECTION INPUT ;
    USE SIGNAL ;
    PORT
      LAYER M3 ;
        RECT  64.98 0 64.998 0.038 ;
    END
  END b_d[382]
  PIN b_d[383]
    DIRECTION INPUT ;
    USE SIGNAL ;
    PORT
      LAYER M5 ;
        RECT  65.136 0 65.16 0.084 ;
    END
  END b_d[383]
  PIN b_d[384]
    DIRECTION INPUT ;
    USE SIGNAL ;
    PORT
      LAYER M3 ;
        RECT  65.304 0 65.322 0.038 ;
    END
  END b_d[384]
  PIN b_d[385]
    DIRECTION INPUT ;
    USE SIGNAL ;
    PORT
      LAYER M5 ;
        RECT  65.472 0 65.496 0.084 ;
    END
  END b_d[385]
  PIN b_d[386]
    DIRECTION INPUT ;
    USE SIGNAL ;
    PORT
      LAYER M3 ;
        RECT  65.664 0 65.682 0.038 ;
    END
  END b_d[386]
  PIN b_d[387]
    DIRECTION INPUT ;
    USE SIGNAL ;
    PORT
      LAYER M5 ;
        RECT  65.808 0 65.832 0.084 ;
    END
  END b_d[387]
  PIN b_d[388]
    DIRECTION INPUT ;
    USE SIGNAL ;
    PORT
      LAYER M3 ;
        RECT  65.988 0 66.006 0.038 ;
    END
  END b_d[388]
  PIN b_d[389]
    DIRECTION INPUT ;
    USE SIGNAL ;
    PORT
      LAYER M5 ;
        RECT  66.144 0 66.168 0.084 ;
    END
  END b_d[389]
  PIN b_d[38]
    DIRECTION INPUT ;
    USE SIGNAL ;
    PORT
      LAYER M3 ;
        RECT  7.02 0 7.038 0.038 ;
    END
  END b_d[38]
  PIN b_d[390]
    DIRECTION INPUT ;
    USE SIGNAL ;
    PORT
      LAYER M3 ;
        RECT  66.312 0 66.33 0.038 ;
    END
  END b_d[390]
  PIN b_d[391]
    DIRECTION INPUT ;
    USE SIGNAL ;
    PORT
      LAYER M5 ;
        RECT  66.48 0 66.504 0.084 ;
    END
  END b_d[391]
  PIN b_d[392]
    DIRECTION INPUT ;
    USE SIGNAL ;
    PORT
      LAYER M3 ;
        RECT  66.672 0 66.69 0.038 ;
    END
  END b_d[392]
  PIN b_d[393]
    DIRECTION INPUT ;
    USE SIGNAL ;
    PORT
      LAYER M5 ;
        RECT  66.816 0 66.84 0.084 ;
    END
  END b_d[393]
  PIN b_d[394]
    DIRECTION INPUT ;
    USE SIGNAL ;
    PORT
      LAYER M3 ;
        RECT  66.996 0 67.014 0.038 ;
    END
  END b_d[394]
  PIN b_d[395]
    DIRECTION INPUT ;
    USE SIGNAL ;
    PORT
      LAYER M5 ;
        RECT  67.152 0 67.176 0.084 ;
    END
  END b_d[395]
  PIN b_d[396]
    DIRECTION INPUT ;
    USE SIGNAL ;
    PORT
      LAYER M3 ;
        RECT  67.32 0 67.338 0.038 ;
    END
  END b_d[396]
  PIN b_d[397]
    DIRECTION INPUT ;
    USE SIGNAL ;
    PORT
      LAYER M5 ;
        RECT  67.488 0 67.512 0.084 ;
    END
  END b_d[397]
  PIN b_d[398]
    DIRECTION INPUT ;
    USE SIGNAL ;
    PORT
      LAYER M3 ;
        RECT  67.68 0 67.698 0.038 ;
    END
  END b_d[398]
  PIN b_d[399]
    DIRECTION INPUT ;
    USE SIGNAL ;
    PORT
      LAYER M5 ;
        RECT  67.824 0 67.848 0.084 ;
    END
  END b_d[399]
  PIN b_d[39]
    DIRECTION INPUT ;
    USE SIGNAL ;
    PORT
      LAYER M5 ;
        RECT  7.2 0 7.224 0.084 ;
    END
  END b_d[39]
  PIN b_d[3]
    DIRECTION INPUT ;
    USE SIGNAL ;
    PORT
      LAYER M5 ;
        RECT  1.104 0 1.128 0.084 ;
    END
  END b_d[3]
  PIN b_d[400]
    DIRECTION INPUT ;
    USE SIGNAL ;
    PORT
      LAYER M3 ;
        RECT  68.004 0 68.022 0.038 ;
    END
  END b_d[400]
  PIN b_d[401]
    DIRECTION INPUT ;
    USE SIGNAL ;
    PORT
      LAYER M5 ;
        RECT  68.16 0 68.184 0.084 ;
    END
  END b_d[401]
  PIN b_d[402]
    DIRECTION INPUT ;
    USE SIGNAL ;
    PORT
      LAYER M3 ;
        RECT  68.364 0 68.382 0.038 ;
    END
  END b_d[402]
  PIN b_d[403]
    DIRECTION INPUT ;
    USE SIGNAL ;
    PORT
      LAYER M5 ;
        RECT  68.496 0 68.52 0.084 ;
    END
  END b_d[403]
  PIN b_d[404]
    DIRECTION INPUT ;
    USE SIGNAL ;
    PORT
      LAYER M3 ;
        RECT  68.688 0 68.706 0.038 ;
    END
  END b_d[404]
  PIN b_d[405]
    DIRECTION INPUT ;
    USE SIGNAL ;
    PORT
      LAYER M5 ;
        RECT  68.832 0 68.856 0.084 ;
    END
  END b_d[405]
  PIN b_d[406]
    DIRECTION INPUT ;
    USE SIGNAL ;
    PORT
      LAYER M3 ;
        RECT  69.012 0 69.03 0.038 ;
    END
  END b_d[406]
  PIN b_d[407]
    DIRECTION INPUT ;
    USE SIGNAL ;
    PORT
      LAYER M5 ;
        RECT  69.168 0 69.192 0.084 ;
    END
  END b_d[407]
  PIN b_d[408]
    DIRECTION INPUT ;
    USE SIGNAL ;
    PORT
      LAYER M3 ;
        RECT  69.372 0 69.39 0.038 ;
    END
  END b_d[408]
  PIN b_d[409]
    DIRECTION INPUT ;
    USE SIGNAL ;
    PORT
      LAYER M5 ;
        RECT  69.504 0 69.528 0.084 ;
    END
  END b_d[409]
  PIN b_d[40]
    DIRECTION INPUT ;
    USE SIGNAL ;
    PORT
      LAYER M3 ;
        RECT  7.344 0 7.362 0.038 ;
    END
  END b_d[40]
  PIN b_d[410]
    DIRECTION INPUT ;
    USE SIGNAL ;
    PORT
      LAYER M3 ;
        RECT  69.696 0 69.714 0.038 ;
    END
  END b_d[410]
  PIN b_d[411]
    DIRECTION INPUT ;
    USE SIGNAL ;
    PORT
      LAYER M5 ;
        RECT  69.84 0 69.864 0.084 ;
    END
  END b_d[411]
  PIN b_d[412]
    DIRECTION INPUT ;
    USE SIGNAL ;
    PORT
      LAYER M3 ;
        RECT  70.02 0 70.038 0.038 ;
    END
  END b_d[412]
  PIN b_d[413]
    DIRECTION INPUT ;
    USE SIGNAL ;
    PORT
      LAYER M5 ;
        RECT  70.176 0 70.2 0.084 ;
    END
  END b_d[413]
  PIN b_d[414]
    DIRECTION INPUT ;
    USE SIGNAL ;
    PORT
      LAYER M3 ;
        RECT  70.38 0 70.398 0.038 ;
    END
  END b_d[414]
  PIN b_d[415]
    DIRECTION INPUT ;
    USE SIGNAL ;
    PORT
      LAYER M5 ;
        RECT  70.512 0 70.536 0.084 ;
    END
  END b_d[415]
  PIN b_d[416]
    DIRECTION INPUT ;
    USE SIGNAL ;
    PORT
      LAYER M3 ;
        RECT  70.704 0 70.722 0.038 ;
    END
  END b_d[416]
  PIN b_d[417]
    DIRECTION INPUT ;
    USE SIGNAL ;
    PORT
      LAYER M5 ;
        RECT  70.896 0 70.92 0.084 ;
    END
  END b_d[417]
  PIN b_d[418]
    DIRECTION INPUT ;
    USE SIGNAL ;
    PORT
      LAYER M3 ;
        RECT  71.028 0 71.046 0.038 ;
    END
  END b_d[418]
  PIN b_d[419]
    DIRECTION INPUT ;
    USE SIGNAL ;
    PORT
      LAYER M5 ;
        RECT  71.232 0 71.256 0.084 ;
    END
  END b_d[419]
  PIN b_d[41]
    DIRECTION INPUT ;
    USE SIGNAL ;
    PORT
      LAYER M5 ;
        RECT  7.536 0 7.56 0.084 ;
    END
  END b_d[41]
  PIN b_d[420]
    DIRECTION INPUT ;
    USE SIGNAL ;
    PORT
      LAYER M3 ;
        RECT  71.388 0 71.406 0.038 ;
    END
  END b_d[420]
  PIN b_d[421]
    DIRECTION INPUT ;
    USE SIGNAL ;
    PORT
      LAYER M5 ;
        RECT  71.568 0 71.592 0.084 ;
    END
  END b_d[421]
  PIN b_d[422]
    DIRECTION INPUT ;
    USE SIGNAL ;
    PORT
      LAYER M3 ;
        RECT  71.712 0 71.73 0.038 ;
    END
  END b_d[422]
  PIN b_d[423]
    DIRECTION INPUT ;
    USE SIGNAL ;
    PORT
      LAYER M5 ;
        RECT  71.904 0 71.928 0.084 ;
    END
  END b_d[423]
  PIN b_d[424]
    DIRECTION INPUT ;
    USE SIGNAL ;
    PORT
      LAYER M3 ;
        RECT  72.072 0 72.09 0.038 ;
    END
  END b_d[424]
  PIN b_d[425]
    DIRECTION INPUT ;
    USE SIGNAL ;
    PORT
      LAYER M5 ;
        RECT  72.24 0 72.264 0.084 ;
    END
  END b_d[425]
  PIN b_d[426]
    DIRECTION INPUT ;
    USE SIGNAL ;
    PORT
      LAYER M3 ;
        RECT  72.396 0 72.414 0.038 ;
    END
  END b_d[426]
  PIN b_d[427]
    DIRECTION INPUT ;
    USE SIGNAL ;
    PORT
      LAYER M5 ;
        RECT  72.576 0 72.6 0.084 ;
    END
  END b_d[427]
  PIN b_d[428]
    DIRECTION INPUT ;
    USE SIGNAL ;
    PORT
      LAYER M3 ;
        RECT  72.72 0 72.738 0.038 ;
    END
  END b_d[428]
  PIN b_d[429]
    DIRECTION INPUT ;
    USE SIGNAL ;
    PORT
      LAYER M5 ;
        RECT  72.912 0 72.936 0.084 ;
    END
  END b_d[429]
  PIN b_d[42]
    DIRECTION INPUT ;
    USE SIGNAL ;
    PORT
      LAYER M3 ;
        RECT  7.704 0 7.722 0.038 ;
    END
  END b_d[42]
  PIN b_d[430]
    DIRECTION INPUT ;
    USE SIGNAL ;
    PORT
      LAYER M3 ;
        RECT  73.08 0 73.098 0.038 ;
    END
  END b_d[430]
  PIN b_d[431]
    DIRECTION INPUT ;
    USE SIGNAL ;
    PORT
      LAYER M5 ;
        RECT  73.248 0 73.272 0.084 ;
    END
  END b_d[431]
  PIN b_d[432]
    DIRECTION INPUT ;
    USE SIGNAL ;
    PORT
      LAYER M3 ;
        RECT  73.404 0 73.422 0.038 ;
    END
  END b_d[432]
  PIN b_d[433]
    DIRECTION INPUT ;
    USE SIGNAL ;
    PORT
      LAYER M5 ;
        RECT  73.584 0 73.608 0.084 ;
    END
  END b_d[433]
  PIN b_d[434]
    DIRECTION INPUT ;
    USE SIGNAL ;
    PORT
      LAYER M3 ;
        RECT  73.728 0 73.746 0.038 ;
    END
  END b_d[434]
  PIN b_d[435]
    DIRECTION INPUT ;
    USE SIGNAL ;
    PORT
      LAYER M5 ;
        RECT  73.92 0 73.944 0.084 ;
    END
  END b_d[435]
  PIN b_d[436]
    DIRECTION INPUT ;
    USE SIGNAL ;
    PORT
      LAYER M3 ;
        RECT  74.088 0 74.106 0.038 ;
    END
  END b_d[436]
  PIN b_d[437]
    DIRECTION INPUT ;
    USE SIGNAL ;
    PORT
      LAYER M5 ;
        RECT  74.256 0 74.28 0.084 ;
    END
  END b_d[437]
  PIN b_d[438]
    DIRECTION INPUT ;
    USE SIGNAL ;
    PORT
      LAYER M3 ;
        RECT  74.412 0 74.43 0.038 ;
    END
  END b_d[438]
  PIN b_d[439]
    DIRECTION INPUT ;
    USE SIGNAL ;
    PORT
      LAYER M5 ;
        RECT  74.592 0 74.616 0.084 ;
    END
  END b_d[439]
  PIN b_d[43]
    DIRECTION INPUT ;
    USE SIGNAL ;
    PORT
      LAYER M5 ;
        RECT  7.872 0 7.896 0.084 ;
    END
  END b_d[43]
  PIN b_d[440]
    DIRECTION INPUT ;
    USE SIGNAL ;
    PORT
      LAYER M3 ;
        RECT  74.736 0 74.754 0.038 ;
    END
  END b_d[440]
  PIN b_d[441]
    DIRECTION INPUT ;
    USE SIGNAL ;
    PORT
      LAYER M5 ;
        RECT  74.928 0 74.952 0.084 ;
    END
  END b_d[441]
  PIN b_d[442]
    DIRECTION INPUT ;
    USE SIGNAL ;
    PORT
      LAYER M3 ;
        RECT  75.096 0 75.114 0.038 ;
    END
  END b_d[442]
  PIN b_d[443]
    DIRECTION INPUT ;
    USE SIGNAL ;
    PORT
      LAYER M5 ;
        RECT  75.264 0 75.288 0.084 ;
    END
  END b_d[443]
  PIN b_d[444]
    DIRECTION INPUT ;
    USE SIGNAL ;
    PORT
      LAYER M3 ;
        RECT  75.42 0 75.438 0.038 ;
    END
  END b_d[444]
  PIN b_d[445]
    DIRECTION INPUT ;
    USE SIGNAL ;
    PORT
      LAYER M5 ;
        RECT  75.6 0 75.624 0.084 ;
    END
  END b_d[445]
  PIN b_d[446]
    DIRECTION INPUT ;
    USE SIGNAL ;
    PORT
      LAYER M3 ;
        RECT  75.744 0 75.762 0.038 ;
    END
  END b_d[446]
  PIN b_d[447]
    DIRECTION INPUT ;
    USE SIGNAL ;
    PORT
      LAYER M5 ;
        RECT  75.936 0 75.96 0.084 ;
    END
  END b_d[447]
  PIN b_d[448]
    DIRECTION INPUT ;
    USE SIGNAL ;
    PORT
      LAYER M3 ;
        RECT  76.104 0 76.122 0.038 ;
    END
  END b_d[448]
  PIN b_d[449]
    DIRECTION INPUT ;
    USE SIGNAL ;
    PORT
      LAYER M5 ;
        RECT  76.272 0 76.296 0.084 ;
    END
  END b_d[449]
  PIN b_d[44]
    DIRECTION INPUT ;
    USE SIGNAL ;
    PORT
      LAYER M3 ;
        RECT  8.028 0 8.046 0.038 ;
    END
  END b_d[44]
  PIN b_d[450]
    DIRECTION INPUT ;
    USE SIGNAL ;
    PORT
      LAYER M3 ;
        RECT  76.428 0 76.446 0.038 ;
    END
  END b_d[450]
  PIN b_d[451]
    DIRECTION INPUT ;
    USE SIGNAL ;
    PORT
      LAYER M5 ;
        RECT  76.608 0 76.632 0.084 ;
    END
  END b_d[451]
  PIN b_d[452]
    DIRECTION INPUT ;
    USE SIGNAL ;
    PORT
      LAYER M3 ;
        RECT  76.788 0 76.806 0.038 ;
    END
  END b_d[452]
  PIN b_d[453]
    DIRECTION INPUT ;
    USE SIGNAL ;
    PORT
      LAYER M5 ;
        RECT  76.944 0 76.968 0.084 ;
    END
  END b_d[453]
  PIN b_d[454]
    DIRECTION INPUT ;
    USE SIGNAL ;
    PORT
      LAYER M3 ;
        RECT  77.112 0 77.13 0.038 ;
    END
  END b_d[454]
  PIN b_d[455]
    DIRECTION INPUT ;
    USE SIGNAL ;
    PORT
      LAYER M5 ;
        RECT  77.28 0 77.304 0.084 ;
    END
  END b_d[455]
  PIN b_d[456]
    DIRECTION INPUT ;
    USE SIGNAL ;
    PORT
      LAYER M3 ;
        RECT  77.436 0 77.454 0.038 ;
    END
  END b_d[456]
  PIN b_d[457]
    DIRECTION INPUT ;
    USE SIGNAL ;
    PORT
      LAYER M5 ;
        RECT  77.616 0 77.64 0.084 ;
    END
  END b_d[457]
  PIN b_d[458]
    DIRECTION INPUT ;
    USE SIGNAL ;
    PORT
      LAYER M3 ;
        RECT  77.796 0 77.814 0.038 ;
    END
  END b_d[458]
  PIN b_d[459]
    DIRECTION INPUT ;
    USE SIGNAL ;
    PORT
      LAYER M5 ;
        RECT  77.952 0 77.976 0.084 ;
    END
  END b_d[459]
  PIN b_d[45]
    DIRECTION INPUT ;
    USE SIGNAL ;
    PORT
      LAYER M5 ;
        RECT  8.208 0 8.232 0.084 ;
    END
  END b_d[45]
  PIN b_d[460]
    DIRECTION INPUT ;
    USE SIGNAL ;
    PORT
      LAYER M3 ;
        RECT  78.12 0 78.138 0.038 ;
    END
  END b_d[460]
  PIN b_d[461]
    DIRECTION INPUT ;
    USE SIGNAL ;
    PORT
      LAYER M5 ;
        RECT  78.288 0 78.312 0.084 ;
    END
  END b_d[461]
  PIN b_d[462]
    DIRECTION INPUT ;
    USE SIGNAL ;
    PORT
      LAYER M3 ;
        RECT  78.444 0 78.462 0.038 ;
    END
  END b_d[462]
  PIN b_d[463]
    DIRECTION INPUT ;
    USE SIGNAL ;
    PORT
      LAYER M5 ;
        RECT  78.624 0 78.648 0.084 ;
    END
  END b_d[463]
  PIN b_d[464]
    DIRECTION INPUT ;
    USE SIGNAL ;
    PORT
      LAYER M3 ;
        RECT  78.804 0 78.822 0.038 ;
    END
  END b_d[464]
  PIN b_d[465]
    DIRECTION INPUT ;
    USE SIGNAL ;
    PORT
      LAYER M5 ;
        RECT  78.96 0 78.984 0.084 ;
    END
  END b_d[465]
  PIN b_d[466]
    DIRECTION INPUT ;
    USE SIGNAL ;
    PORT
      LAYER M3 ;
        RECT  79.128 0 79.146 0.038 ;
    END
  END b_d[466]
  PIN b_d[467]
    DIRECTION INPUT ;
    USE SIGNAL ;
    PORT
      LAYER M5 ;
        RECT  79.296 0 79.32 0.084 ;
    END
  END b_d[467]
  PIN b_d[468]
    DIRECTION INPUT ;
    USE SIGNAL ;
    PORT
      LAYER M3 ;
        RECT  79.452 0 79.47 0.038 ;
    END
  END b_d[468]
  PIN b_d[469]
    DIRECTION INPUT ;
    USE SIGNAL ;
    PORT
      LAYER M5 ;
        RECT  79.632 0 79.656 0.084 ;
    END
  END b_d[469]
  PIN b_d[46]
    DIRECTION INPUT ;
    USE SIGNAL ;
    PORT
      LAYER M3 ;
        RECT  8.352 0 8.37 0.038 ;
    END
  END b_d[46]
  PIN b_d[470]
    DIRECTION INPUT ;
    USE SIGNAL ;
    PORT
      LAYER M3 ;
        RECT  79.812 0 79.83 0.038 ;
    END
  END b_d[470]
  PIN b_d[471]
    DIRECTION INPUT ;
    USE SIGNAL ;
    PORT
      LAYER M5 ;
        RECT  79.968 0 79.992 0.084 ;
    END
  END b_d[471]
  PIN b_d[472]
    DIRECTION INPUT ;
    USE SIGNAL ;
    PORT
      LAYER M3 ;
        RECT  80.136 0 80.154 0.038 ;
    END
  END b_d[472]
  PIN b_d[473]
    DIRECTION INPUT ;
    USE SIGNAL ;
    PORT
      LAYER M5 ;
        RECT  80.304 0 80.328 0.084 ;
    END
  END b_d[473]
  PIN b_d[474]
    DIRECTION INPUT ;
    USE SIGNAL ;
    PORT
      LAYER M3 ;
        RECT  80.496 0 80.514 0.038 ;
    END
  END b_d[474]
  PIN b_d[475]
    DIRECTION INPUT ;
    USE SIGNAL ;
    PORT
      LAYER M5 ;
        RECT  80.64 0 80.664 0.084 ;
    END
  END b_d[475]
  PIN b_d[476]
    DIRECTION INPUT ;
    USE SIGNAL ;
    PORT
      LAYER M3 ;
        RECT  80.82 0 80.838 0.038 ;
    END
  END b_d[476]
  PIN b_d[477]
    DIRECTION INPUT ;
    USE SIGNAL ;
    PORT
      LAYER M5 ;
        RECT  80.976 0 81 0.084 ;
    END
  END b_d[477]
  PIN b_d[478]
    DIRECTION INPUT ;
    USE SIGNAL ;
    PORT
      LAYER M3 ;
        RECT  81.144 0 81.162 0.038 ;
    END
  END b_d[478]
  PIN b_d[479]
    DIRECTION INPUT ;
    USE SIGNAL ;
    PORT
      LAYER M5 ;
        RECT  81.312 0 81.336 0.084 ;
    END
  END b_d[479]
  PIN b_d[47]
    DIRECTION INPUT ;
    USE SIGNAL ;
    PORT
      LAYER M5 ;
        RECT  8.544 0 8.568 0.084 ;
    END
  END b_d[47]
  PIN b_d[480]
    DIRECTION INPUT ;
    USE SIGNAL ;
    PORT
      LAYER M3 ;
        RECT  81.504 0 81.522 0.038 ;
    END
  END b_d[480]
  PIN b_d[481]
    DIRECTION INPUT ;
    USE SIGNAL ;
    PORT
      LAYER M5 ;
        RECT  81.648 0 81.672 0.084 ;
    END
  END b_d[481]
  PIN b_d[482]
    DIRECTION INPUT ;
    USE SIGNAL ;
    PORT
      LAYER M3 ;
        RECT  81.828 0 81.846 0.038 ;
    END
  END b_d[482]
  PIN b_d[483]
    DIRECTION INPUT ;
    USE SIGNAL ;
    PORT
      LAYER M5 ;
        RECT  81.984 0 82.008 0.084 ;
    END
  END b_d[483]
  PIN b_d[484]
    DIRECTION INPUT ;
    USE SIGNAL ;
    PORT
      LAYER M3 ;
        RECT  82.152 0 82.17 0.038 ;
    END
  END b_d[484]
  PIN b_d[485]
    DIRECTION INPUT ;
    USE SIGNAL ;
    PORT
      LAYER M5 ;
        RECT  82.32 0 82.344 0.084 ;
    END
  END b_d[485]
  PIN b_d[486]
    DIRECTION INPUT ;
    USE SIGNAL ;
    PORT
      LAYER M3 ;
        RECT  82.512 0 82.53 0.038 ;
    END
  END b_d[486]
  PIN b_d[487]
    DIRECTION INPUT ;
    USE SIGNAL ;
    PORT
      LAYER M5 ;
        RECT  82.656 0 82.68 0.084 ;
    END
  END b_d[487]
  PIN b_d[488]
    DIRECTION INPUT ;
    USE SIGNAL ;
    PORT
      LAYER M3 ;
        RECT  82.836 0 82.854 0.038 ;
    END
  END b_d[488]
  PIN b_d[489]
    DIRECTION INPUT ;
    USE SIGNAL ;
    PORT
      LAYER M5 ;
        RECT  82.992 0 83.016 0.084 ;
    END
  END b_d[489]
  PIN b_d[48]
    DIRECTION INPUT ;
    USE SIGNAL ;
    PORT
      LAYER M3 ;
        RECT  8.712 0 8.73 0.038 ;
    END
  END b_d[48]
  PIN b_d[490]
    DIRECTION INPUT ;
    USE SIGNAL ;
    PORT
      LAYER M3 ;
        RECT  83.16 0 83.178 0.038 ;
    END
  END b_d[490]
  PIN b_d[491]
    DIRECTION INPUT ;
    USE SIGNAL ;
    PORT
      LAYER M5 ;
        RECT  83.328 0 83.352 0.084 ;
    END
  END b_d[491]
  PIN b_d[492]
    DIRECTION INPUT ;
    USE SIGNAL ;
    PORT
      LAYER M3 ;
        RECT  83.52 0 83.538 0.038 ;
    END
  END b_d[492]
  PIN b_d[493]
    DIRECTION INPUT ;
    USE SIGNAL ;
    PORT
      LAYER M5 ;
        RECT  83.664 0 83.688 0.084 ;
    END
  END b_d[493]
  PIN b_d[494]
    DIRECTION INPUT ;
    USE SIGNAL ;
    PORT
      LAYER M3 ;
        RECT  83.844 0 83.862 0.038 ;
    END
  END b_d[494]
  PIN b_d[495]
    DIRECTION INPUT ;
    USE SIGNAL ;
    PORT
      LAYER M5 ;
        RECT  84 0 84.024 0.084 ;
    END
  END b_d[495]
  PIN b_d[496]
    DIRECTION INPUT ;
    USE SIGNAL ;
    PORT
      LAYER M3 ;
        RECT  84.168 0 84.186 0.038 ;
    END
  END b_d[496]
  PIN b_d[497]
    DIRECTION INPUT ;
    USE SIGNAL ;
    PORT
      LAYER M5 ;
        RECT  84.336 0 84.36 0.084 ;
    END
  END b_d[497]
  PIN b_d[498]
    DIRECTION INPUT ;
    USE SIGNAL ;
    PORT
      LAYER M3 ;
        RECT  84.528 0 84.546 0.038 ;
    END
  END b_d[498]
  PIN b_d[499]
    DIRECTION INPUT ;
    USE SIGNAL ;
    PORT
      LAYER M5 ;
        RECT  84.672 0 84.696 0.084 ;
    END
  END b_d[499]
  PIN b_d[49]
    DIRECTION INPUT ;
    USE SIGNAL ;
    PORT
      LAYER M5 ;
        RECT  8.88 0 8.904 0.084 ;
    END
  END b_d[49]
  PIN b_d[4]
    DIRECTION INPUT ;
    USE SIGNAL ;
    PORT
      LAYER M3 ;
        RECT  1.296 0 1.314 0.038 ;
    END
  END b_d[4]
  PIN b_d[500]
    DIRECTION INPUT ;
    USE SIGNAL ;
    PORT
      LAYER M3 ;
        RECT  84.852 0 84.87 0.038 ;
    END
  END b_d[500]
  PIN b_d[501]
    DIRECTION INPUT ;
    USE SIGNAL ;
    PORT
      LAYER M5 ;
        RECT  85.008 0 85.032 0.084 ;
    END
  END b_d[501]
  PIN b_d[502]
    DIRECTION INPUT ;
    USE SIGNAL ;
    PORT
      LAYER M3 ;
        RECT  85.212 0 85.23 0.038 ;
    END
  END b_d[502]
  PIN b_d[503]
    DIRECTION INPUT ;
    USE SIGNAL ;
    PORT
      LAYER M5 ;
        RECT  85.344 0 85.368 0.084 ;
    END
  END b_d[503]
  PIN b_d[504]
    DIRECTION INPUT ;
    USE SIGNAL ;
    PORT
      LAYER M3 ;
        RECT  85.536 0 85.554 0.038 ;
    END
  END b_d[504]
  PIN b_d[505]
    DIRECTION INPUT ;
    USE SIGNAL ;
    PORT
      LAYER M5 ;
        RECT  85.68 0 85.704 0.084 ;
    END
  END b_d[505]
  PIN b_d[506]
    DIRECTION INPUT ;
    USE SIGNAL ;
    PORT
      LAYER M3 ;
        RECT  85.86 0 85.878 0.038 ;
    END
  END b_d[506]
  PIN b_d[507]
    DIRECTION INPUT ;
    USE SIGNAL ;
    PORT
      LAYER M5 ;
        RECT  86.016 0 86.04 0.084 ;
    END
  END b_d[507]
  PIN b_d[508]
    DIRECTION INPUT ;
    USE SIGNAL ;
    PORT
      LAYER M3 ;
        RECT  86.22 0 86.238 0.038 ;
    END
  END b_d[508]
  PIN b_d[509]
    DIRECTION INPUT ;
    USE SIGNAL ;
    PORT
      LAYER M5 ;
        RECT  86.352 0 86.376 0.084 ;
    END
  END b_d[509]
  PIN b_d[50]
    DIRECTION INPUT ;
    USE SIGNAL ;
    PORT
      LAYER M3 ;
        RECT  9.036 0 9.054 0.038 ;
    END
  END b_d[50]
  PIN b_d[510]
    DIRECTION INPUT ;
    USE SIGNAL ;
    PORT
      LAYER M3 ;
        RECT  86.544 0 86.562 0.038 ;
    END
  END b_d[510]
  PIN b_d[511]
    DIRECTION INPUT ;
    USE SIGNAL ;
    PORT
      LAYER M5 ;
        RECT  86.688 0 86.712 0.084 ;
    END
  END b_d[511]
  PIN b_d[512]
    DIRECTION INPUT ;
    USE SIGNAL ;
    PORT
      LAYER M3 ;
        RECT  86.868 0 86.886 0.038 ;
    END
  END b_d[512]
  PIN b_d[513]
    DIRECTION INPUT ;
    USE SIGNAL ;
    PORT
      LAYER M5 ;
        RECT  87.024 0 87.048 0.084 ;
    END
  END b_d[513]
  PIN b_d[514]
    DIRECTION INPUT ;
    USE SIGNAL ;
    PORT
      LAYER M3 ;
        RECT  87.228 0 87.246 0.038 ;
    END
  END b_d[514]
  PIN b_d[515]
    DIRECTION INPUT ;
    USE SIGNAL ;
    PORT
      LAYER M5 ;
        RECT  87.408 0 87.432 0.084 ;
    END
  END b_d[515]
  PIN b_d[51]
    DIRECTION INPUT ;
    USE SIGNAL ;
    PORT
      LAYER M5 ;
        RECT  9.216 0 9.24 0.084 ;
    END
  END b_d[51]
  PIN b_d[52]
    DIRECTION INPUT ;
    USE SIGNAL ;
    PORT
      LAYER M3 ;
        RECT  9.36 0 9.378 0.038 ;
    END
  END b_d[52]
  PIN b_d[53]
    DIRECTION INPUT ;
    USE SIGNAL ;
    PORT
      LAYER M5 ;
        RECT  9.552 0 9.576 0.084 ;
    END
  END b_d[53]
  PIN b_d[54]
    DIRECTION INPUT ;
    USE SIGNAL ;
    PORT
      LAYER M3 ;
        RECT  9.72 0 9.738 0.038 ;
    END
  END b_d[54]
  PIN b_d[55]
    DIRECTION INPUT ;
    USE SIGNAL ;
    PORT
      LAYER M5 ;
        RECT  9.888 0 9.912 0.084 ;
    END
  END b_d[55]
  PIN b_d[56]
    DIRECTION INPUT ;
    USE SIGNAL ;
    PORT
      LAYER M3 ;
        RECT  10.044 0 10.062 0.038 ;
    END
  END b_d[56]
  PIN b_d[57]
    DIRECTION INPUT ;
    USE SIGNAL ;
    PORT
      LAYER M5 ;
        RECT  10.224 0 10.248 0.084 ;
    END
  END b_d[57]
  PIN b_d[58]
    DIRECTION INPUT ;
    USE SIGNAL ;
    PORT
      LAYER M3 ;
        RECT  10.404 0 10.422 0.038 ;
    END
  END b_d[58]
  PIN b_d[59]
    DIRECTION INPUT ;
    USE SIGNAL ;
    PORT
      LAYER M5 ;
        RECT  10.56 0 10.584 0.084 ;
    END
  END b_d[59]
  PIN b_d[5]
    DIRECTION INPUT ;
    USE SIGNAL ;
    PORT
      LAYER M5 ;
        RECT  1.44 0 1.464 0.084 ;
    END
  END b_d[5]
  PIN b_d[60]
    DIRECTION INPUT ;
    USE SIGNAL ;
    PORT
      LAYER M3 ;
        RECT  10.728 0 10.746 0.038 ;
    END
  END b_d[60]
  PIN b_d[61]
    DIRECTION INPUT ;
    USE SIGNAL ;
    PORT
      LAYER M5 ;
        RECT  10.896 0 10.92 0.084 ;
    END
  END b_d[61]
  PIN b_d[62]
    DIRECTION INPUT ;
    USE SIGNAL ;
    PORT
      LAYER M3 ;
        RECT  11.052 0 11.07 0.038 ;
    END
  END b_d[62]
  PIN b_d[63]
    DIRECTION INPUT ;
    USE SIGNAL ;
    PORT
      LAYER M5 ;
        RECT  11.232 0 11.256 0.084 ;
    END
  END b_d[63]
  PIN b_d[64]
    DIRECTION INPUT ;
    USE SIGNAL ;
    PORT
      LAYER M3 ;
        RECT  11.412 0 11.43 0.038 ;
    END
  END b_d[64]
  PIN b_d[65]
    DIRECTION INPUT ;
    USE SIGNAL ;
    PORT
      LAYER M5 ;
        RECT  11.568 0 11.592 0.084 ;
    END
  END b_d[65]
  PIN b_d[66]
    DIRECTION INPUT ;
    USE SIGNAL ;
    PORT
      LAYER M3 ;
        RECT  11.736 0 11.754 0.038 ;
    END
  END b_d[66]
  PIN b_d[67]
    DIRECTION INPUT ;
    USE SIGNAL ;
    PORT
      LAYER M5 ;
        RECT  11.904 0 11.928 0.084 ;
    END
  END b_d[67]
  PIN b_d[68]
    DIRECTION INPUT ;
    USE SIGNAL ;
    PORT
      LAYER M3 ;
        RECT  12.06 0 12.078 0.038 ;
    END
  END b_d[68]
  PIN b_d[69]
    DIRECTION INPUT ;
    USE SIGNAL ;
    PORT
      LAYER M5 ;
        RECT  12.24 0 12.264 0.084 ;
    END
  END b_d[69]
  PIN b_d[6]
    DIRECTION INPUT ;
    USE SIGNAL ;
    PORT
      LAYER M3 ;
        RECT  1.62 0 1.638 0.038 ;
    END
  END b_d[6]
  PIN b_d[70]
    DIRECTION INPUT ;
    USE SIGNAL ;
    PORT
      LAYER M3 ;
        RECT  12.42 0 12.438 0.038 ;
    END
  END b_d[70]
  PIN b_d[71]
    DIRECTION INPUT ;
    USE SIGNAL ;
    PORT
      LAYER M5 ;
        RECT  12.576 0 12.6 0.084 ;
    END
  END b_d[71]
  PIN b_d[72]
    DIRECTION INPUT ;
    USE SIGNAL ;
    PORT
      LAYER M3 ;
        RECT  12.744 0 12.762 0.038 ;
    END
  END b_d[72]
  PIN b_d[73]
    DIRECTION INPUT ;
    USE SIGNAL ;
    PORT
      LAYER M5 ;
        RECT  12.912 0 12.936 0.084 ;
    END
  END b_d[73]
  PIN b_d[74]
    DIRECTION INPUT ;
    USE SIGNAL ;
    PORT
      LAYER M3 ;
        RECT  13.068 0 13.086 0.038 ;
    END
  END b_d[74]
  PIN b_d[75]
    DIRECTION INPUT ;
    USE SIGNAL ;
    PORT
      LAYER M5 ;
        RECT  13.248 0 13.272 0.084 ;
    END
  END b_d[75]
  PIN b_d[76]
    DIRECTION INPUT ;
    USE SIGNAL ;
    PORT
      LAYER M3 ;
        RECT  13.428 0 13.446 0.038 ;
    END
  END b_d[76]
  PIN b_d[77]
    DIRECTION INPUT ;
    USE SIGNAL ;
    PORT
      LAYER M5 ;
        RECT  13.584 0 13.608 0.084 ;
    END
  END b_d[77]
  PIN b_d[78]
    DIRECTION INPUT ;
    USE SIGNAL ;
    PORT
      LAYER M3 ;
        RECT  13.752 0 13.77 0.038 ;
    END
  END b_d[78]
  PIN b_d[79]
    DIRECTION INPUT ;
    USE SIGNAL ;
    PORT
      LAYER M5 ;
        RECT  13.92 0 13.944 0.084 ;
    END
  END b_d[79]
  PIN b_d[7]
    DIRECTION INPUT ;
    USE SIGNAL ;
    PORT
      LAYER M5 ;
        RECT  1.776 0 1.8 0.084 ;
    END
  END b_d[7]
  PIN b_d[80]
    DIRECTION INPUT ;
    USE SIGNAL ;
    PORT
      LAYER M3 ;
        RECT  14.112 0 14.13 0.038 ;
    END
  END b_d[80]
  PIN b_d[81]
    DIRECTION INPUT ;
    USE SIGNAL ;
    PORT
      LAYER M5 ;
        RECT  14.256 0 14.28 0.084 ;
    END
  END b_d[81]
  PIN b_d[82]
    DIRECTION INPUT ;
    USE SIGNAL ;
    PORT
      LAYER M3 ;
        RECT  14.436 0 14.454 0.038 ;
    END
  END b_d[82]
  PIN b_d[83]
    DIRECTION INPUT ;
    USE SIGNAL ;
    PORT
      LAYER M5 ;
        RECT  14.592 0 14.616 0.084 ;
    END
  END b_d[83]
  PIN b_d[84]
    DIRECTION INPUT ;
    USE SIGNAL ;
    PORT
      LAYER M3 ;
        RECT  14.76 0 14.778 0.038 ;
    END
  END b_d[84]
  PIN b_d[85]
    DIRECTION INPUT ;
    USE SIGNAL ;
    PORT
      LAYER M5 ;
        RECT  14.928 0 14.952 0.084 ;
    END
  END b_d[85]
  PIN b_d[86]
    DIRECTION INPUT ;
    USE SIGNAL ;
    PORT
      LAYER M3 ;
        RECT  15.12 0 15.138 0.038 ;
    END
  END b_d[86]
  PIN b_d[87]
    DIRECTION INPUT ;
    USE SIGNAL ;
    PORT
      LAYER M5 ;
        RECT  15.264 0 15.288 0.084 ;
    END
  END b_d[87]
  PIN b_d[88]
    DIRECTION INPUT ;
    USE SIGNAL ;
    PORT
      LAYER M3 ;
        RECT  15.444 0 15.462 0.038 ;
    END
  END b_d[88]
  PIN b_d[89]
    DIRECTION INPUT ;
    USE SIGNAL ;
    PORT
      LAYER M5 ;
        RECT  15.6 0 15.624 0.084 ;
    END
  END b_d[89]
  PIN b_d[8]
    DIRECTION INPUT ;
    USE SIGNAL ;
    PORT
      LAYER M3 ;
        RECT  1.98 0 1.998 0.038 ;
    END
  END b_d[8]
  PIN b_d[90]
    DIRECTION INPUT ;
    USE SIGNAL ;
    PORT
      LAYER M3 ;
        RECT  15.768 0 15.786 0.038 ;
    END
  END b_d[90]
  PIN b_d[91]
    DIRECTION INPUT ;
    USE SIGNAL ;
    PORT
      LAYER M5 ;
        RECT  15.936 0 15.96 0.084 ;
    END
  END b_d[91]
  PIN b_d[92]
    DIRECTION INPUT ;
    USE SIGNAL ;
    PORT
      LAYER M3 ;
        RECT  16.128 0 16.146 0.038 ;
    END
  END b_d[92]
  PIN b_d[93]
    DIRECTION INPUT ;
    USE SIGNAL ;
    PORT
      LAYER M5 ;
        RECT  16.272 0 16.296 0.084 ;
    END
  END b_d[93]
  PIN b_d[94]
    DIRECTION INPUT ;
    USE SIGNAL ;
    PORT
      LAYER M3 ;
        RECT  16.452 0 16.47 0.038 ;
    END
  END b_d[94]
  PIN b_d[95]
    DIRECTION INPUT ;
    USE SIGNAL ;
    PORT
      LAYER M5 ;
        RECT  16.608 0 16.632 0.084 ;
    END
  END b_d[95]
  PIN b_d[96]
    DIRECTION INPUT ;
    USE SIGNAL ;
    PORT
      LAYER M3 ;
        RECT  16.776 0 16.794 0.038 ;
    END
  END b_d[96]
  PIN b_d[97]
    DIRECTION INPUT ;
    USE SIGNAL ;
    PORT
      LAYER M5 ;
        RECT  16.944 0 16.968 0.084 ;
    END
  END b_d[97]
  PIN b_d[98]
    DIRECTION INPUT ;
    USE SIGNAL ;
    PORT
      LAYER M3 ;
        RECT  17.136 0 17.154 0.038 ;
    END
  END b_d[98]
  PIN b_d[99]
    DIRECTION INPUT ;
    USE SIGNAL ;
    PORT
      LAYER M5 ;
        RECT  17.28 0 17.304 0.084 ;
    END
  END b_d[99]
  PIN b_d[9]
    DIRECTION INPUT ;
    USE SIGNAL ;
    PORT
      LAYER M5 ;
        RECT  2.112 0 2.136 0.084 ;
    END
  END b_d[9]
  PIN ck
    DIRECTION INPUT ;
    USE SIGNAL ;
    PORT
      LAYER M3 ;
        RECT  89.1 0 89.118 0.038 ;
    END
  END ck
  PIN rst_n
    DIRECTION INPUT ;
    USE SIGNAL ;
    PORT
      LAYER M3 ;
        RECT  88.272 129.562 88.29 129.6 ;
    END
  END rst_n
  PIN sidx[0]
    DIRECTION INPUT ;
    USE SIGNAL ;
    PORT
      LAYER M3 ;
        RECT  89.28 129.562 89.298 129.6 ;
    END
  END sidx[0]
  PIN sidx[1]
    DIRECTION INPUT ;
    USE SIGNAL ;
    PORT
      LAYER M5 ;
        RECT  89.616 129.516 89.64 129.6 ;
    END
  END sidx[1]
  PIN sidx[2]
    DIRECTION INPUT ;
    USE SIGNAL ;
    PORT
      LAYER M3 ;
        RECT  90 129.562 90.018 129.6 ;
    END
  END sidx[2]
  PIN tap_d[0]
    DIRECTION OUTPUT ;
    USE SIGNAL ;
    PORT
      LAYER M4 ;
        RECT  90.636 0.672 90.72 0.696 ;
    END
  END tap_d[0]
  PIN tap_d[100]
    DIRECTION OUTPUT ;
    USE SIGNAL ;
    PORT
      LAYER M4 ;
        RECT  90.636 25.968 90.72 25.992 ;
    END
  END tap_d[100]
  PIN tap_d[101]
    DIRECTION OUTPUT ;
    USE SIGNAL ;
    PORT
      LAYER M4 ;
        RECT  90.636 26.208 90.72 26.232 ;
    END
  END tap_d[101]
  PIN tap_d[102]
    DIRECTION OUTPUT ;
    USE SIGNAL ;
    PORT
      LAYER M4 ;
        RECT  90.636 26.448 90.72 26.472 ;
    END
  END tap_d[102]
  PIN tap_d[103]
    DIRECTION OUTPUT ;
    USE SIGNAL ;
    PORT
      LAYER M4 ;
        RECT  90.636 26.736 90.72 26.76 ;
    END
  END tap_d[103]
  PIN tap_d[104]
    DIRECTION OUTPUT ;
    USE SIGNAL ;
    PORT
      LAYER M4 ;
        RECT  90.636 26.976 90.72 27 ;
    END
  END tap_d[104]
  PIN tap_d[105]
    DIRECTION OUTPUT ;
    USE SIGNAL ;
    PORT
      LAYER M4 ;
        RECT  90.636 27.216 90.72 27.24 ;
    END
  END tap_d[105]
  PIN tap_d[106]
    DIRECTION OUTPUT ;
    USE SIGNAL ;
    PORT
      LAYER M4 ;
        RECT  90.636 27.456 90.72 27.48 ;
    END
  END tap_d[106]
  PIN tap_d[107]
    DIRECTION OUTPUT ;
    USE SIGNAL ;
    PORT
      LAYER M4 ;
        RECT  90.636 27.744 90.72 27.768 ;
    END
  END tap_d[107]
  PIN tap_d[108]
    DIRECTION OUTPUT ;
    USE SIGNAL ;
    PORT
      LAYER M4 ;
        RECT  90.636 27.984 90.72 28.008 ;
    END
  END tap_d[108]
  PIN tap_d[109]
    DIRECTION OUTPUT ;
    USE SIGNAL ;
    PORT
      LAYER M4 ;
        RECT  90.636 28.224 90.72 28.248 ;
    END
  END tap_d[109]
  PIN tap_d[10]
    DIRECTION OUTPUT ;
    USE SIGNAL ;
    PORT
      LAYER M4 ;
        RECT  90.636 3.168 90.72 3.192 ;
    END
  END tap_d[10]
  PIN tap_d[110]
    DIRECTION OUTPUT ;
    USE SIGNAL ;
    PORT
      LAYER M4 ;
        RECT  90.636 28.464 90.72 28.488 ;
    END
  END tap_d[110]
  PIN tap_d[111]
    DIRECTION OUTPUT ;
    USE SIGNAL ;
    PORT
      LAYER M4 ;
        RECT  90.636 28.752 90.72 28.776 ;
    END
  END tap_d[111]
  PIN tap_d[112]
    DIRECTION OUTPUT ;
    USE SIGNAL ;
    PORT
      LAYER M4 ;
        RECT  90.636 28.992 90.72 29.016 ;
    END
  END tap_d[112]
  PIN tap_d[113]
    DIRECTION OUTPUT ;
    USE SIGNAL ;
    PORT
      LAYER M4 ;
        RECT  90.636 29.232 90.72 29.256 ;
    END
  END tap_d[113]
  PIN tap_d[114]
    DIRECTION OUTPUT ;
    USE SIGNAL ;
    PORT
      LAYER M4 ;
        RECT  90.636 29.52 90.72 29.544 ;
    END
  END tap_d[114]
  PIN tap_d[115]
    DIRECTION OUTPUT ;
    USE SIGNAL ;
    PORT
      LAYER M4 ;
        RECT  90.636 29.76 90.72 29.784 ;
    END
  END tap_d[115]
  PIN tap_d[116]
    DIRECTION OUTPUT ;
    USE SIGNAL ;
    PORT
      LAYER M4 ;
        RECT  90.636 30 90.72 30.024 ;
    END
  END tap_d[116]
  PIN tap_d[117]
    DIRECTION OUTPUT ;
    USE SIGNAL ;
    PORT
      LAYER M4 ;
        RECT  90.636 30.24 90.72 30.264 ;
    END
  END tap_d[117]
  PIN tap_d[118]
    DIRECTION OUTPUT ;
    USE SIGNAL ;
    PORT
      LAYER M4 ;
        RECT  90.636 30.528 90.72 30.552 ;
    END
  END tap_d[118]
  PIN tap_d[119]
    DIRECTION OUTPUT ;
    USE SIGNAL ;
    PORT
      LAYER M4 ;
        RECT  90.636 30.768 90.72 30.792 ;
    END
  END tap_d[119]
  PIN tap_d[11]
    DIRECTION OUTPUT ;
    USE SIGNAL ;
    PORT
      LAYER M4 ;
        RECT  90.636 3.456 90.72 3.48 ;
    END
  END tap_d[11]
  PIN tap_d[120]
    DIRECTION OUTPUT ;
    USE SIGNAL ;
    PORT
      LAYER M4 ;
        RECT  90.636 31.008 90.72 31.032 ;
    END
  END tap_d[120]
  PIN tap_d[121]
    DIRECTION OUTPUT ;
    USE SIGNAL ;
    PORT
      LAYER M4 ;
        RECT  90.636 31.248 90.72 31.272 ;
    END
  END tap_d[121]
  PIN tap_d[122]
    DIRECTION OUTPUT ;
    USE SIGNAL ;
    PORT
      LAYER M4 ;
        RECT  90.636 31.536 90.72 31.56 ;
    END
  END tap_d[122]
  PIN tap_d[123]
    DIRECTION OUTPUT ;
    USE SIGNAL ;
    PORT
      LAYER M4 ;
        RECT  90.636 31.776 90.72 31.8 ;
    END
  END tap_d[123]
  PIN tap_d[124]
    DIRECTION OUTPUT ;
    USE SIGNAL ;
    PORT
      LAYER M4 ;
        RECT  90.636 32.016 90.72 32.04 ;
    END
  END tap_d[124]
  PIN tap_d[125]
    DIRECTION OUTPUT ;
    USE SIGNAL ;
    PORT
      LAYER M4 ;
        RECT  90.636 32.256 90.72 32.28 ;
    END
  END tap_d[125]
  PIN tap_d[126]
    DIRECTION OUTPUT ;
    USE SIGNAL ;
    PORT
      LAYER M4 ;
        RECT  90.636 32.544 90.72 32.568 ;
    END
  END tap_d[126]
  PIN tap_d[127]
    DIRECTION OUTPUT ;
    USE SIGNAL ;
    PORT
      LAYER M4 ;
        RECT  90.636 32.784 90.72 32.808 ;
    END
  END tap_d[127]
  PIN tap_d[128]
    DIRECTION OUTPUT ;
    USE SIGNAL ;
    PORT
      LAYER M4 ;
        RECT  90.636 33.024 90.72 33.048 ;
    END
  END tap_d[128]
  PIN tap_d[129]
    DIRECTION OUTPUT ;
    USE SIGNAL ;
    PORT
      LAYER M4 ;
        RECT  90.636 33.312 90.72 33.336 ;
    END
  END tap_d[129]
  PIN tap_d[12]
    DIRECTION OUTPUT ;
    USE SIGNAL ;
    PORT
      LAYER M4 ;
        RECT  90.636 3.696 90.72 3.72 ;
    END
  END tap_d[12]
  PIN tap_d[130]
    DIRECTION OUTPUT ;
    USE SIGNAL ;
    PORT
      LAYER M4 ;
        RECT  90.636 33.552 90.72 33.576 ;
    END
  END tap_d[130]
  PIN tap_d[131]
    DIRECTION OUTPUT ;
    USE SIGNAL ;
    PORT
      LAYER M4 ;
        RECT  90.636 33.792 90.72 33.816 ;
    END
  END tap_d[131]
  PIN tap_d[132]
    DIRECTION OUTPUT ;
    USE SIGNAL ;
    PORT
      LAYER M4 ;
        RECT  90.636 34.032 90.72 34.056 ;
    END
  END tap_d[132]
  PIN tap_d[133]
    DIRECTION OUTPUT ;
    USE SIGNAL ;
    PORT
      LAYER M4 ;
        RECT  90.636 34.32 90.72 34.344 ;
    END
  END tap_d[133]
  PIN tap_d[134]
    DIRECTION OUTPUT ;
    USE SIGNAL ;
    PORT
      LAYER M4 ;
        RECT  90.636 34.56 90.72 34.584 ;
    END
  END tap_d[134]
  PIN tap_d[135]
    DIRECTION OUTPUT ;
    USE SIGNAL ;
    PORT
      LAYER M4 ;
        RECT  90.636 34.8 90.72 34.824 ;
    END
  END tap_d[135]
  PIN tap_d[136]
    DIRECTION OUTPUT ;
    USE SIGNAL ;
    PORT
      LAYER M4 ;
        RECT  90.636 35.04 90.72 35.064 ;
    END
  END tap_d[136]
  PIN tap_d[137]
    DIRECTION OUTPUT ;
    USE SIGNAL ;
    PORT
      LAYER M4 ;
        RECT  90.636 35.328 90.72 35.352 ;
    END
  END tap_d[137]
  PIN tap_d[138]
    DIRECTION OUTPUT ;
    USE SIGNAL ;
    PORT
      LAYER M4 ;
        RECT  90.636 35.568 90.72 35.592 ;
    END
  END tap_d[138]
  PIN tap_d[139]
    DIRECTION OUTPUT ;
    USE SIGNAL ;
    PORT
      LAYER M4 ;
        RECT  90.636 35.808 90.72 35.832 ;
    END
  END tap_d[139]
  PIN tap_d[13]
    DIRECTION OUTPUT ;
    USE SIGNAL ;
    PORT
      LAYER M4 ;
        RECT  90.636 3.936 90.72 3.96 ;
    END
  END tap_d[13]
  PIN tap_d[140]
    DIRECTION OUTPUT ;
    USE SIGNAL ;
    PORT
      LAYER M4 ;
        RECT  90.636 36.096 90.72 36.12 ;
    END
  END tap_d[140]
  PIN tap_d[141]
    DIRECTION OUTPUT ;
    USE SIGNAL ;
    PORT
      LAYER M4 ;
        RECT  90.636 36.336 90.72 36.36 ;
    END
  END tap_d[141]
  PIN tap_d[142]
    DIRECTION OUTPUT ;
    USE SIGNAL ;
    PORT
      LAYER M4 ;
        RECT  90.636 36.576 90.72 36.6 ;
    END
  END tap_d[142]
  PIN tap_d[143]
    DIRECTION OUTPUT ;
    USE SIGNAL ;
    PORT
      LAYER M4 ;
        RECT  90.636 36.816 90.72 36.84 ;
    END
  END tap_d[143]
  PIN tap_d[144]
    DIRECTION OUTPUT ;
    USE SIGNAL ;
    PORT
      LAYER M4 ;
        RECT  90.636 37.104 90.72 37.128 ;
    END
  END tap_d[144]
  PIN tap_d[145]
    DIRECTION OUTPUT ;
    USE SIGNAL ;
    PORT
      LAYER M4 ;
        RECT  90.636 37.344 90.72 37.368 ;
    END
  END tap_d[145]
  PIN tap_d[146]
    DIRECTION OUTPUT ;
    USE SIGNAL ;
    PORT
      LAYER M4 ;
        RECT  90.636 37.584 90.72 37.608 ;
    END
  END tap_d[146]
  PIN tap_d[147]
    DIRECTION OUTPUT ;
    USE SIGNAL ;
    PORT
      LAYER M4 ;
        RECT  90.636 37.824 90.72 37.848 ;
    END
  END tap_d[147]
  PIN tap_d[148]
    DIRECTION OUTPUT ;
    USE SIGNAL ;
    PORT
      LAYER M4 ;
        RECT  90.636 38.112 90.72 38.136 ;
    END
  END tap_d[148]
  PIN tap_d[149]
    DIRECTION OUTPUT ;
    USE SIGNAL ;
    PORT
      LAYER M4 ;
        RECT  90.636 38.352 90.72 38.376 ;
    END
  END tap_d[149]
  PIN tap_d[14]
    DIRECTION OUTPUT ;
    USE SIGNAL ;
    PORT
      LAYER M4 ;
        RECT  90.636 4.176 90.72 4.2 ;
    END
  END tap_d[14]
  PIN tap_d[150]
    DIRECTION OUTPUT ;
    USE SIGNAL ;
    PORT
      LAYER M4 ;
        RECT  90.636 38.592 90.72 38.616 ;
    END
  END tap_d[150]
  PIN tap_d[151]
    DIRECTION OUTPUT ;
    USE SIGNAL ;
    PORT
      LAYER M4 ;
        RECT  90.636 38.88 90.72 38.904 ;
    END
  END tap_d[151]
  PIN tap_d[152]
    DIRECTION OUTPUT ;
    USE SIGNAL ;
    PORT
      LAYER M4 ;
        RECT  90.636 39.12 90.72 39.144 ;
    END
  END tap_d[152]
  PIN tap_d[153]
    DIRECTION OUTPUT ;
    USE SIGNAL ;
    PORT
      LAYER M4 ;
        RECT  90.636 39.36 90.72 39.384 ;
    END
  END tap_d[153]
  PIN tap_d[154]
    DIRECTION OUTPUT ;
    USE SIGNAL ;
    PORT
      LAYER M4 ;
        RECT  90.636 39.6 90.72 39.624 ;
    END
  END tap_d[154]
  PIN tap_d[155]
    DIRECTION OUTPUT ;
    USE SIGNAL ;
    PORT
      LAYER M4 ;
        RECT  90.636 39.888 90.72 39.912 ;
    END
  END tap_d[155]
  PIN tap_d[156]
    DIRECTION OUTPUT ;
    USE SIGNAL ;
    PORT
      LAYER M4 ;
        RECT  90.636 40.128 90.72 40.152 ;
    END
  END tap_d[156]
  PIN tap_d[157]
    DIRECTION OUTPUT ;
    USE SIGNAL ;
    PORT
      LAYER M4 ;
        RECT  90.636 40.368 90.72 40.392 ;
    END
  END tap_d[157]
  PIN tap_d[158]
    DIRECTION OUTPUT ;
    USE SIGNAL ;
    PORT
      LAYER M4 ;
        RECT  90.636 40.608 90.72 40.632 ;
    END
  END tap_d[158]
  PIN tap_d[159]
    DIRECTION OUTPUT ;
    USE SIGNAL ;
    PORT
      LAYER M4 ;
        RECT  90.636 40.896 90.72 40.92 ;
    END
  END tap_d[159]
  PIN tap_d[15]
    DIRECTION OUTPUT ;
    USE SIGNAL ;
    PORT
      LAYER M4 ;
        RECT  90.636 4.464 90.72 4.488 ;
    END
  END tap_d[15]
  PIN tap_d[160]
    DIRECTION OUTPUT ;
    USE SIGNAL ;
    PORT
      LAYER M4 ;
        RECT  90.636 41.136 90.72 41.16 ;
    END
  END tap_d[160]
  PIN tap_d[161]
    DIRECTION OUTPUT ;
    USE SIGNAL ;
    PORT
      LAYER M4 ;
        RECT  90.636 41.376 90.72 41.4 ;
    END
  END tap_d[161]
  PIN tap_d[162]
    DIRECTION OUTPUT ;
    USE SIGNAL ;
    PORT
      LAYER M4 ;
        RECT  90.636 41.616 90.72 41.64 ;
    END
  END tap_d[162]
  PIN tap_d[163]
    DIRECTION OUTPUT ;
    USE SIGNAL ;
    PORT
      LAYER M4 ;
        RECT  90.636 41.904 90.72 41.928 ;
    END
  END tap_d[163]
  PIN tap_d[164]
    DIRECTION OUTPUT ;
    USE SIGNAL ;
    PORT
      LAYER M4 ;
        RECT  90.636 42.144 90.72 42.168 ;
    END
  END tap_d[164]
  PIN tap_d[165]
    DIRECTION OUTPUT ;
    USE SIGNAL ;
    PORT
      LAYER M4 ;
        RECT  90.636 42.384 90.72 42.408 ;
    END
  END tap_d[165]
  PIN tap_d[166]
    DIRECTION OUTPUT ;
    USE SIGNAL ;
    PORT
      LAYER M4 ;
        RECT  90.636 42.672 90.72 42.696 ;
    END
  END tap_d[166]
  PIN tap_d[167]
    DIRECTION OUTPUT ;
    USE SIGNAL ;
    PORT
      LAYER M4 ;
        RECT  90.636 42.912 90.72 42.936 ;
    END
  END tap_d[167]
  PIN tap_d[168]
    DIRECTION OUTPUT ;
    USE SIGNAL ;
    PORT
      LAYER M4 ;
        RECT  90.636 43.152 90.72 43.176 ;
    END
  END tap_d[168]
  PIN tap_d[169]
    DIRECTION OUTPUT ;
    USE SIGNAL ;
    PORT
      LAYER M4 ;
        RECT  90.636 43.392 90.72 43.416 ;
    END
  END tap_d[169]
  PIN tap_d[16]
    DIRECTION OUTPUT ;
    USE SIGNAL ;
    PORT
      LAYER M4 ;
        RECT  90.636 4.704 90.72 4.728 ;
    END
  END tap_d[16]
  PIN tap_d[170]
    DIRECTION OUTPUT ;
    USE SIGNAL ;
    PORT
      LAYER M4 ;
        RECT  90.636 43.68 90.72 43.704 ;
    END
  END tap_d[170]
  PIN tap_d[171]
    DIRECTION OUTPUT ;
    USE SIGNAL ;
    PORT
      LAYER M4 ;
        RECT  90.636 43.92 90.72 43.944 ;
    END
  END tap_d[171]
  PIN tap_d[172]
    DIRECTION OUTPUT ;
    USE SIGNAL ;
    PORT
      LAYER M4 ;
        RECT  90.636 44.16 90.72 44.184 ;
    END
  END tap_d[172]
  PIN tap_d[173]
    DIRECTION OUTPUT ;
    USE SIGNAL ;
    PORT
      LAYER M4 ;
        RECT  90.636 44.4 90.72 44.424 ;
    END
  END tap_d[173]
  PIN tap_d[174]
    DIRECTION OUTPUT ;
    USE SIGNAL ;
    PORT
      LAYER M4 ;
        RECT  90.636 44.688 90.72 44.712 ;
    END
  END tap_d[174]
  PIN tap_d[175]
    DIRECTION OUTPUT ;
    USE SIGNAL ;
    PORT
      LAYER M4 ;
        RECT  90.636 44.928 90.72 44.952 ;
    END
  END tap_d[175]
  PIN tap_d[176]
    DIRECTION OUTPUT ;
    USE SIGNAL ;
    PORT
      LAYER M4 ;
        RECT  90.636 45.168 90.72 45.192 ;
    END
  END tap_d[176]
  PIN tap_d[177]
    DIRECTION OUTPUT ;
    USE SIGNAL ;
    PORT
      LAYER M4 ;
        RECT  90.636 45.456 90.72 45.48 ;
    END
  END tap_d[177]
  PIN tap_d[178]
    DIRECTION OUTPUT ;
    USE SIGNAL ;
    PORT
      LAYER M4 ;
        RECT  90.636 45.696 90.72 45.72 ;
    END
  END tap_d[178]
  PIN tap_d[179]
    DIRECTION OUTPUT ;
    USE SIGNAL ;
    PORT
      LAYER M4 ;
        RECT  90.636 45.936 90.72 45.96 ;
    END
  END tap_d[179]
  PIN tap_d[17]
    DIRECTION OUTPUT ;
    USE SIGNAL ;
    PORT
      LAYER M4 ;
        RECT  90.636 4.944 90.72 4.968 ;
    END
  END tap_d[17]
  PIN tap_d[180]
    DIRECTION OUTPUT ;
    USE SIGNAL ;
    PORT
      LAYER M4 ;
        RECT  90.636 46.176 90.72 46.2 ;
    END
  END tap_d[180]
  PIN tap_d[181]
    DIRECTION OUTPUT ;
    USE SIGNAL ;
    PORT
      LAYER M4 ;
        RECT  90.636 46.464 90.72 46.488 ;
    END
  END tap_d[181]
  PIN tap_d[182]
    DIRECTION OUTPUT ;
    USE SIGNAL ;
    PORT
      LAYER M4 ;
        RECT  90.636 46.704 90.72 46.728 ;
    END
  END tap_d[182]
  PIN tap_d[183]
    DIRECTION OUTPUT ;
    USE SIGNAL ;
    PORT
      LAYER M4 ;
        RECT  90.636 46.944 90.72 46.968 ;
    END
  END tap_d[183]
  PIN tap_d[184]
    DIRECTION OUTPUT ;
    USE SIGNAL ;
    PORT
      LAYER M4 ;
        RECT  90.636 47.184 90.72 47.208 ;
    END
  END tap_d[184]
  PIN tap_d[185]
    DIRECTION OUTPUT ;
    USE SIGNAL ;
    PORT
      LAYER M4 ;
        RECT  90.636 47.472 90.72 47.496 ;
    END
  END tap_d[185]
  PIN tap_d[186]
    DIRECTION OUTPUT ;
    USE SIGNAL ;
    PORT
      LAYER M4 ;
        RECT  90.636 47.712 90.72 47.736 ;
    END
  END tap_d[186]
  PIN tap_d[187]
    DIRECTION OUTPUT ;
    USE SIGNAL ;
    PORT
      LAYER M4 ;
        RECT  90.636 47.952 90.72 47.976 ;
    END
  END tap_d[187]
  PIN tap_d[188]
    DIRECTION OUTPUT ;
    USE SIGNAL ;
    PORT
      LAYER M4 ;
        RECT  90.636 48.24 90.72 48.264 ;
    END
  END tap_d[188]
  PIN tap_d[189]
    DIRECTION OUTPUT ;
    USE SIGNAL ;
    PORT
      LAYER M4 ;
        RECT  90.636 48.48 90.72 48.504 ;
    END
  END tap_d[189]
  PIN tap_d[18]
    DIRECTION OUTPUT ;
    USE SIGNAL ;
    PORT
      LAYER M4 ;
        RECT  90.636 5.232 90.72 5.256 ;
    END
  END tap_d[18]
  PIN tap_d[190]
    DIRECTION OUTPUT ;
    USE SIGNAL ;
    PORT
      LAYER M4 ;
        RECT  90.636 48.72 90.72 48.744 ;
    END
  END tap_d[190]
  PIN tap_d[191]
    DIRECTION OUTPUT ;
    USE SIGNAL ;
    PORT
      LAYER M4 ;
        RECT  90.636 48.96 90.72 48.984 ;
    END
  END tap_d[191]
  PIN tap_d[192]
    DIRECTION OUTPUT ;
    USE SIGNAL ;
    PORT
      LAYER M4 ;
        RECT  90.636 49.248 90.72 49.272 ;
    END
  END tap_d[192]
  PIN tap_d[193]
    DIRECTION OUTPUT ;
    USE SIGNAL ;
    PORT
      LAYER M4 ;
        RECT  90.636 49.488 90.72 49.512 ;
    END
  END tap_d[193]
  PIN tap_d[194]
    DIRECTION OUTPUT ;
    USE SIGNAL ;
    PORT
      LAYER M4 ;
        RECT  90.636 49.728 90.72 49.752 ;
    END
  END tap_d[194]
  PIN tap_d[195]
    DIRECTION OUTPUT ;
    USE SIGNAL ;
    PORT
      LAYER M4 ;
        RECT  90.636 49.968 90.72 49.992 ;
    END
  END tap_d[195]
  PIN tap_d[196]
    DIRECTION OUTPUT ;
    USE SIGNAL ;
    PORT
      LAYER M4 ;
        RECT  90.636 50.256 90.72 50.28 ;
    END
  END tap_d[196]
  PIN tap_d[197]
    DIRECTION OUTPUT ;
    USE SIGNAL ;
    PORT
      LAYER M4 ;
        RECT  90.636 50.496 90.72 50.52 ;
    END
  END tap_d[197]
  PIN tap_d[198]
    DIRECTION OUTPUT ;
    USE SIGNAL ;
    PORT
      LAYER M4 ;
        RECT  90.636 50.736 90.72 50.76 ;
    END
  END tap_d[198]
  PIN tap_d[199]
    DIRECTION OUTPUT ;
    USE SIGNAL ;
    PORT
      LAYER M4 ;
        RECT  90.636 51.024 90.72 51.048 ;
    END
  END tap_d[199]
  PIN tap_d[19]
    DIRECTION OUTPUT ;
    USE SIGNAL ;
    PORT
      LAYER M4 ;
        RECT  90.636 5.472 90.72 5.496 ;
    END
  END tap_d[19]
  PIN tap_d[1]
    DIRECTION OUTPUT ;
    USE SIGNAL ;
    PORT
      LAYER M4 ;
        RECT  90.636 0.912 90.72 0.936 ;
    END
  END tap_d[1]
  PIN tap_d[200]
    DIRECTION OUTPUT ;
    USE SIGNAL ;
    PORT
      LAYER M4 ;
        RECT  90.636 51.264 90.72 51.288 ;
    END
  END tap_d[200]
  PIN tap_d[201]
    DIRECTION OUTPUT ;
    USE SIGNAL ;
    PORT
      LAYER M4 ;
        RECT  90.636 51.504 90.72 51.528 ;
    END
  END tap_d[201]
  PIN tap_d[202]
    DIRECTION OUTPUT ;
    USE SIGNAL ;
    PORT
      LAYER M4 ;
        RECT  90.636 51.744 90.72 51.768 ;
    END
  END tap_d[202]
  PIN tap_d[203]
    DIRECTION OUTPUT ;
    USE SIGNAL ;
    PORT
      LAYER M4 ;
        RECT  90.636 52.032 90.72 52.056 ;
    END
  END tap_d[203]
  PIN tap_d[204]
    DIRECTION OUTPUT ;
    USE SIGNAL ;
    PORT
      LAYER M4 ;
        RECT  90.636 52.272 90.72 52.296 ;
    END
  END tap_d[204]
  PIN tap_d[205]
    DIRECTION OUTPUT ;
    USE SIGNAL ;
    PORT
      LAYER M4 ;
        RECT  90.636 52.512 90.72 52.536 ;
    END
  END tap_d[205]
  PIN tap_d[206]
    DIRECTION OUTPUT ;
    USE SIGNAL ;
    PORT
      LAYER M4 ;
        RECT  90.636 52.752 90.72 52.776 ;
    END
  END tap_d[206]
  PIN tap_d[207]
    DIRECTION OUTPUT ;
    USE SIGNAL ;
    PORT
      LAYER M4 ;
        RECT  90.636 53.04 90.72 53.064 ;
    END
  END tap_d[207]
  PIN tap_d[208]
    DIRECTION OUTPUT ;
    USE SIGNAL ;
    PORT
      LAYER M4 ;
        RECT  90.636 53.28 90.72 53.304 ;
    END
  END tap_d[208]
  PIN tap_d[209]
    DIRECTION OUTPUT ;
    USE SIGNAL ;
    PORT
      LAYER M4 ;
        RECT  90.636 53.52 90.72 53.544 ;
    END
  END tap_d[209]
  PIN tap_d[20]
    DIRECTION OUTPUT ;
    USE SIGNAL ;
    PORT
      LAYER M4 ;
        RECT  90.636 5.712 90.72 5.736 ;
    END
  END tap_d[20]
  PIN tap_d[210]
    DIRECTION OUTPUT ;
    USE SIGNAL ;
    PORT
      LAYER M4 ;
        RECT  90.636 53.76 90.72 53.784 ;
    END
  END tap_d[210]
  PIN tap_d[211]
    DIRECTION OUTPUT ;
    USE SIGNAL ;
    PORT
      LAYER M4 ;
        RECT  90.636 54.048 90.72 54.072 ;
    END
  END tap_d[211]
  PIN tap_d[212]
    DIRECTION OUTPUT ;
    USE SIGNAL ;
    PORT
      LAYER M4 ;
        RECT  90.636 54.288 90.72 54.312 ;
    END
  END tap_d[212]
  PIN tap_d[213]
    DIRECTION OUTPUT ;
    USE SIGNAL ;
    PORT
      LAYER M4 ;
        RECT  90.636 54.528 90.72 54.552 ;
    END
  END tap_d[213]
  PIN tap_d[214]
    DIRECTION OUTPUT ;
    USE SIGNAL ;
    PORT
      LAYER M4 ;
        RECT  90.636 54.816 90.72 54.84 ;
    END
  END tap_d[214]
  PIN tap_d[215]
    DIRECTION OUTPUT ;
    USE SIGNAL ;
    PORT
      LAYER M4 ;
        RECT  90.636 55.056 90.72 55.08 ;
    END
  END tap_d[215]
  PIN tap_d[216]
    DIRECTION OUTPUT ;
    USE SIGNAL ;
    PORT
      LAYER M4 ;
        RECT  90.636 55.296 90.72 55.32 ;
    END
  END tap_d[216]
  PIN tap_d[217]
    DIRECTION OUTPUT ;
    USE SIGNAL ;
    PORT
      LAYER M4 ;
        RECT  90.636 55.536 90.72 55.56 ;
    END
  END tap_d[217]
  PIN tap_d[218]
    DIRECTION OUTPUT ;
    USE SIGNAL ;
    PORT
      LAYER M4 ;
        RECT  90.636 55.824 90.72 55.848 ;
    END
  END tap_d[218]
  PIN tap_d[219]
    DIRECTION OUTPUT ;
    USE SIGNAL ;
    PORT
      LAYER M4 ;
        RECT  90.636 56.064 90.72 56.088 ;
    END
  END tap_d[219]
  PIN tap_d[21]
    DIRECTION OUTPUT ;
    USE SIGNAL ;
    PORT
      LAYER M4 ;
        RECT  90.636 5.952 90.72 5.976 ;
    END
  END tap_d[21]
  PIN tap_d[220]
    DIRECTION OUTPUT ;
    USE SIGNAL ;
    PORT
      LAYER M4 ;
        RECT  90.636 56.304 90.72 56.328 ;
    END
  END tap_d[220]
  PIN tap_d[221]
    DIRECTION OUTPUT ;
    USE SIGNAL ;
    PORT
      LAYER M4 ;
        RECT  90.636 56.544 90.72 56.568 ;
    END
  END tap_d[221]
  PIN tap_d[222]
    DIRECTION OUTPUT ;
    USE SIGNAL ;
    PORT
      LAYER M4 ;
        RECT  90.636 56.832 90.72 56.856 ;
    END
  END tap_d[222]
  PIN tap_d[223]
    DIRECTION OUTPUT ;
    USE SIGNAL ;
    PORT
      LAYER M4 ;
        RECT  90.636 57.072 90.72 57.096 ;
    END
  END tap_d[223]
  PIN tap_d[224]
    DIRECTION OUTPUT ;
    USE SIGNAL ;
    PORT
      LAYER M4 ;
        RECT  90.636 57.312 90.72 57.336 ;
    END
  END tap_d[224]
  PIN tap_d[225]
    DIRECTION OUTPUT ;
    USE SIGNAL ;
    PORT
      LAYER M4 ;
        RECT  90.636 57.6 90.72 57.624 ;
    END
  END tap_d[225]
  PIN tap_d[226]
    DIRECTION OUTPUT ;
    USE SIGNAL ;
    PORT
      LAYER M4 ;
        RECT  90.636 57.84 90.72 57.864 ;
    END
  END tap_d[226]
  PIN tap_d[227]
    DIRECTION OUTPUT ;
    USE SIGNAL ;
    PORT
      LAYER M4 ;
        RECT  90.636 58.08 90.72 58.104 ;
    END
  END tap_d[227]
  PIN tap_d[228]
    DIRECTION OUTPUT ;
    USE SIGNAL ;
    PORT
      LAYER M4 ;
        RECT  90.636 58.32 90.72 58.344 ;
    END
  END tap_d[228]
  PIN tap_d[229]
    DIRECTION OUTPUT ;
    USE SIGNAL ;
    PORT
      LAYER M4 ;
        RECT  90.636 58.608 90.72 58.632 ;
    END
  END tap_d[229]
  PIN tap_d[22]
    DIRECTION OUTPUT ;
    USE SIGNAL ;
    PORT
      LAYER M4 ;
        RECT  90.636 6.24 90.72 6.264 ;
    END
  END tap_d[22]
  PIN tap_d[230]
    DIRECTION OUTPUT ;
    USE SIGNAL ;
    PORT
      LAYER M4 ;
        RECT  90.636 58.848 90.72 58.872 ;
    END
  END tap_d[230]
  PIN tap_d[231]
    DIRECTION OUTPUT ;
    USE SIGNAL ;
    PORT
      LAYER M4 ;
        RECT  90.636 59.088 90.72 59.112 ;
    END
  END tap_d[231]
  PIN tap_d[232]
    DIRECTION OUTPUT ;
    USE SIGNAL ;
    PORT
      LAYER M4 ;
        RECT  90.636 59.328 90.72 59.352 ;
    END
  END tap_d[232]
  PIN tap_d[233]
    DIRECTION OUTPUT ;
    USE SIGNAL ;
    PORT
      LAYER M4 ;
        RECT  90.636 59.616 90.72 59.64 ;
    END
  END tap_d[233]
  PIN tap_d[234]
    DIRECTION OUTPUT ;
    USE SIGNAL ;
    PORT
      LAYER M4 ;
        RECT  90.636 59.856 90.72 59.88 ;
    END
  END tap_d[234]
  PIN tap_d[235]
    DIRECTION OUTPUT ;
    USE SIGNAL ;
    PORT
      LAYER M4 ;
        RECT  90.636 60.096 90.72 60.12 ;
    END
  END tap_d[235]
  PIN tap_d[236]
    DIRECTION OUTPUT ;
    USE SIGNAL ;
    PORT
      LAYER M4 ;
        RECT  90.636 60.384 90.72 60.408 ;
    END
  END tap_d[236]
  PIN tap_d[237]
    DIRECTION OUTPUT ;
    USE SIGNAL ;
    PORT
      LAYER M4 ;
        RECT  90.636 60.624 90.72 60.648 ;
    END
  END tap_d[237]
  PIN tap_d[238]
    DIRECTION OUTPUT ;
    USE SIGNAL ;
    PORT
      LAYER M4 ;
        RECT  90.636 60.864 90.72 60.888 ;
    END
  END tap_d[238]
  PIN tap_d[239]
    DIRECTION OUTPUT ;
    USE SIGNAL ;
    PORT
      LAYER M4 ;
        RECT  90.636 61.104 90.72 61.128 ;
    END
  END tap_d[239]
  PIN tap_d[23]
    DIRECTION OUTPUT ;
    USE SIGNAL ;
    PORT
      LAYER M4 ;
        RECT  90.636 6.48 90.72 6.504 ;
    END
  END tap_d[23]
  PIN tap_d[240]
    DIRECTION OUTPUT ;
    USE SIGNAL ;
    PORT
      LAYER M4 ;
        RECT  90.636 61.392 90.72 61.416 ;
    END
  END tap_d[240]
  PIN tap_d[241]
    DIRECTION OUTPUT ;
    USE SIGNAL ;
    PORT
      LAYER M4 ;
        RECT  90.636 61.632 90.72 61.656 ;
    END
  END tap_d[241]
  PIN tap_d[242]
    DIRECTION OUTPUT ;
    USE SIGNAL ;
    PORT
      LAYER M4 ;
        RECT  90.636 61.872 90.72 61.896 ;
    END
  END tap_d[242]
  PIN tap_d[243]
    DIRECTION OUTPUT ;
    USE SIGNAL ;
    PORT
      LAYER M4 ;
        RECT  90.636 62.112 90.72 62.136 ;
    END
  END tap_d[243]
  PIN tap_d[244]
    DIRECTION OUTPUT ;
    USE SIGNAL ;
    PORT
      LAYER M4 ;
        RECT  90.636 62.4 90.72 62.424 ;
    END
  END tap_d[244]
  PIN tap_d[245]
    DIRECTION OUTPUT ;
    USE SIGNAL ;
    PORT
      LAYER M4 ;
        RECT  90.636 62.64 90.72 62.664 ;
    END
  END tap_d[245]
  PIN tap_d[246]
    DIRECTION OUTPUT ;
    USE SIGNAL ;
    PORT
      LAYER M4 ;
        RECT  90.636 62.88 90.72 62.904 ;
    END
  END tap_d[246]
  PIN tap_d[247]
    DIRECTION OUTPUT ;
    USE SIGNAL ;
    PORT
      LAYER M4 ;
        RECT  90.636 63.168 90.72 63.192 ;
    END
  END tap_d[247]
  PIN tap_d[248]
    DIRECTION OUTPUT ;
    USE SIGNAL ;
    PORT
      LAYER M4 ;
        RECT  90.636 63.408 90.72 63.432 ;
    END
  END tap_d[248]
  PIN tap_d[249]
    DIRECTION OUTPUT ;
    USE SIGNAL ;
    PORT
      LAYER M4 ;
        RECT  90.636 63.648 90.72 63.672 ;
    END
  END tap_d[249]
  PIN tap_d[24]
    DIRECTION OUTPUT ;
    USE SIGNAL ;
    PORT
      LAYER M4 ;
        RECT  90.636 6.72 90.72 6.744 ;
    END
  END tap_d[24]
  PIN tap_d[250]
    DIRECTION OUTPUT ;
    USE SIGNAL ;
    PORT
      LAYER M4 ;
        RECT  90.636 63.888 90.72 63.912 ;
    END
  END tap_d[250]
  PIN tap_d[251]
    DIRECTION OUTPUT ;
    USE SIGNAL ;
    PORT
      LAYER M4 ;
        RECT  90.636 64.176 90.72 64.2 ;
    END
  END tap_d[251]
  PIN tap_d[252]
    DIRECTION OUTPUT ;
    USE SIGNAL ;
    PORT
      LAYER M4 ;
        RECT  90.636 64.416 90.72 64.44 ;
    END
  END tap_d[252]
  PIN tap_d[253]
    DIRECTION OUTPUT ;
    USE SIGNAL ;
    PORT
      LAYER M4 ;
        RECT  90.636 64.656 90.72 64.68 ;
    END
  END tap_d[253]
  PIN tap_d[254]
    DIRECTION OUTPUT ;
    USE SIGNAL ;
    PORT
      LAYER M4 ;
        RECT  90.636 64.896 90.72 64.92 ;
    END
  END tap_d[254]
  PIN tap_d[255]
    DIRECTION OUTPUT ;
    USE SIGNAL ;
    PORT
      LAYER M4 ;
        RECT  90.636 65.184 90.72 65.208 ;
    END
  END tap_d[255]
  PIN tap_d[256]
    DIRECTION OUTPUT ;
    USE SIGNAL ;
    PORT
      LAYER M4 ;
        RECT  90.636 65.424 90.72 65.448 ;
    END
  END tap_d[256]
  PIN tap_d[257]
    DIRECTION OUTPUT ;
    USE SIGNAL ;
    PORT
      LAYER M4 ;
        RECT  90.636 65.664 90.72 65.688 ;
    END
  END tap_d[257]
  PIN tap_d[258]
    DIRECTION OUTPUT ;
    USE SIGNAL ;
    PORT
      LAYER M4 ;
        RECT  90.636 65.904 90.72 65.928 ;
    END
  END tap_d[258]
  PIN tap_d[259]
    DIRECTION OUTPUT ;
    USE SIGNAL ;
    PORT
      LAYER M4 ;
        RECT  90.636 66.192 90.72 66.216 ;
    END
  END tap_d[259]
  PIN tap_d[25]
    DIRECTION OUTPUT ;
    USE SIGNAL ;
    PORT
      LAYER M4 ;
        RECT  90.636 6.96 90.72 6.984 ;
    END
  END tap_d[25]
  PIN tap_d[260]
    DIRECTION OUTPUT ;
    USE SIGNAL ;
    PORT
      LAYER M4 ;
        RECT  90.636 66.432 90.72 66.456 ;
    END
  END tap_d[260]
  PIN tap_d[261]
    DIRECTION OUTPUT ;
    USE SIGNAL ;
    PORT
      LAYER M4 ;
        RECT  90.636 66.672 90.72 66.696 ;
    END
  END tap_d[261]
  PIN tap_d[262]
    DIRECTION OUTPUT ;
    USE SIGNAL ;
    PORT
      LAYER M4 ;
        RECT  90.636 66.96 90.72 66.984 ;
    END
  END tap_d[262]
  PIN tap_d[263]
    DIRECTION OUTPUT ;
    USE SIGNAL ;
    PORT
      LAYER M4 ;
        RECT  90.636 67.2 90.72 67.224 ;
    END
  END tap_d[263]
  PIN tap_d[264]
    DIRECTION OUTPUT ;
    USE SIGNAL ;
    PORT
      LAYER M4 ;
        RECT  90.636 67.44 90.72 67.464 ;
    END
  END tap_d[264]
  PIN tap_d[265]
    DIRECTION OUTPUT ;
    USE SIGNAL ;
    PORT
      LAYER M4 ;
        RECT  90.636 67.68 90.72 67.704 ;
    END
  END tap_d[265]
  PIN tap_d[266]
    DIRECTION OUTPUT ;
    USE SIGNAL ;
    PORT
      LAYER M4 ;
        RECT  90.636 67.968 90.72 67.992 ;
    END
  END tap_d[266]
  PIN tap_d[267]
    DIRECTION OUTPUT ;
    USE SIGNAL ;
    PORT
      LAYER M4 ;
        RECT  90.636 68.208 90.72 68.232 ;
    END
  END tap_d[267]
  PIN tap_d[268]
    DIRECTION OUTPUT ;
    USE SIGNAL ;
    PORT
      LAYER M4 ;
        RECT  90.636 68.448 90.72 68.472 ;
    END
  END tap_d[268]
  PIN tap_d[269]
    DIRECTION OUTPUT ;
    USE SIGNAL ;
    PORT
      LAYER M4 ;
        RECT  90.636 68.688 90.72 68.712 ;
    END
  END tap_d[269]
  PIN tap_d[26]
    DIRECTION OUTPUT ;
    USE SIGNAL ;
    PORT
      LAYER M4 ;
        RECT  90.636 7.248 90.72 7.272 ;
    END
  END tap_d[26]
  PIN tap_d[270]
    DIRECTION OUTPUT ;
    USE SIGNAL ;
    PORT
      LAYER M4 ;
        RECT  90.636 68.976 90.72 69 ;
    END
  END tap_d[270]
  PIN tap_d[271]
    DIRECTION OUTPUT ;
    USE SIGNAL ;
    PORT
      LAYER M4 ;
        RECT  90.636 69.216 90.72 69.24 ;
    END
  END tap_d[271]
  PIN tap_d[272]
    DIRECTION OUTPUT ;
    USE SIGNAL ;
    PORT
      LAYER M4 ;
        RECT  90.636 69.456 90.72 69.48 ;
    END
  END tap_d[272]
  PIN tap_d[273]
    DIRECTION OUTPUT ;
    USE SIGNAL ;
    PORT
      LAYER M4 ;
        RECT  90.636 69.744 90.72 69.768 ;
    END
  END tap_d[273]
  PIN tap_d[274]
    DIRECTION OUTPUT ;
    USE SIGNAL ;
    PORT
      LAYER M4 ;
        RECT  90.636 69.984 90.72 70.008 ;
    END
  END tap_d[274]
  PIN tap_d[275]
    DIRECTION OUTPUT ;
    USE SIGNAL ;
    PORT
      LAYER M4 ;
        RECT  90.636 70.224 90.72 70.248 ;
    END
  END tap_d[275]
  PIN tap_d[276]
    DIRECTION OUTPUT ;
    USE SIGNAL ;
    PORT
      LAYER M4 ;
        RECT  90.636 70.464 90.72 70.488 ;
    END
  END tap_d[276]
  PIN tap_d[277]
    DIRECTION OUTPUT ;
    USE SIGNAL ;
    PORT
      LAYER M4 ;
        RECT  90.636 70.752 90.72 70.776 ;
    END
  END tap_d[277]
  PIN tap_d[278]
    DIRECTION OUTPUT ;
    USE SIGNAL ;
    PORT
      LAYER M4 ;
        RECT  90.636 70.992 90.72 71.016 ;
    END
  END tap_d[278]
  PIN tap_d[279]
    DIRECTION OUTPUT ;
    USE SIGNAL ;
    PORT
      LAYER M4 ;
        RECT  90.636 71.232 90.72 71.256 ;
    END
  END tap_d[279]
  PIN tap_d[27]
    DIRECTION OUTPUT ;
    USE SIGNAL ;
    PORT
      LAYER M4 ;
        RECT  90.636 7.488 90.72 7.512 ;
    END
  END tap_d[27]
  PIN tap_d[280]
    DIRECTION OUTPUT ;
    USE SIGNAL ;
    PORT
      LAYER M4 ;
        RECT  90.636 71.472 90.72 71.496 ;
    END
  END tap_d[280]
  PIN tap_d[281]
    DIRECTION OUTPUT ;
    USE SIGNAL ;
    PORT
      LAYER M4 ;
        RECT  90.636 71.76 90.72 71.784 ;
    END
  END tap_d[281]
  PIN tap_d[282]
    DIRECTION OUTPUT ;
    USE SIGNAL ;
    PORT
      LAYER M4 ;
        RECT  90.636 72 90.72 72.024 ;
    END
  END tap_d[282]
  PIN tap_d[283]
    DIRECTION OUTPUT ;
    USE SIGNAL ;
    PORT
      LAYER M4 ;
        RECT  90.636 72.24 90.72 72.264 ;
    END
  END tap_d[283]
  PIN tap_d[284]
    DIRECTION OUTPUT ;
    USE SIGNAL ;
    PORT
      LAYER M4 ;
        RECT  90.636 72.528 90.72 72.552 ;
    END
  END tap_d[284]
  PIN tap_d[285]
    DIRECTION OUTPUT ;
    USE SIGNAL ;
    PORT
      LAYER M4 ;
        RECT  90.636 72.768 90.72 72.792 ;
    END
  END tap_d[285]
  PIN tap_d[286]
    DIRECTION OUTPUT ;
    USE SIGNAL ;
    PORT
      LAYER M4 ;
        RECT  90.636 73.008 90.72 73.032 ;
    END
  END tap_d[286]
  PIN tap_d[287]
    DIRECTION OUTPUT ;
    USE SIGNAL ;
    PORT
      LAYER M4 ;
        RECT  90.636 73.248 90.72 73.272 ;
    END
  END tap_d[287]
  PIN tap_d[288]
    DIRECTION OUTPUT ;
    USE SIGNAL ;
    PORT
      LAYER M4 ;
        RECT  90.636 73.536 90.72 73.56 ;
    END
  END tap_d[288]
  PIN tap_d[289]
    DIRECTION OUTPUT ;
    USE SIGNAL ;
    PORT
      LAYER M4 ;
        RECT  90.636 73.776 90.72 73.8 ;
    END
  END tap_d[289]
  PIN tap_d[28]
    DIRECTION OUTPUT ;
    USE SIGNAL ;
    PORT
      LAYER M4 ;
        RECT  90.636 7.728 90.72 7.752 ;
    END
  END tap_d[28]
  PIN tap_d[290]
    DIRECTION OUTPUT ;
    USE SIGNAL ;
    PORT
      LAYER M4 ;
        RECT  90.636 74.016 90.72 74.04 ;
    END
  END tap_d[290]
  PIN tap_d[291]
    DIRECTION OUTPUT ;
    USE SIGNAL ;
    PORT
      LAYER M4 ;
        RECT  90.636 74.256 90.72 74.28 ;
    END
  END tap_d[291]
  PIN tap_d[292]
    DIRECTION OUTPUT ;
    USE SIGNAL ;
    PORT
      LAYER M4 ;
        RECT  90.636 74.544 90.72 74.568 ;
    END
  END tap_d[292]
  PIN tap_d[293]
    DIRECTION OUTPUT ;
    USE SIGNAL ;
    PORT
      LAYER M4 ;
        RECT  90.636 74.784 90.72 74.808 ;
    END
  END tap_d[293]
  PIN tap_d[294]
    DIRECTION OUTPUT ;
    USE SIGNAL ;
    PORT
      LAYER M4 ;
        RECT  90.636 75.024 90.72 75.048 ;
    END
  END tap_d[294]
  PIN tap_d[295]
    DIRECTION OUTPUT ;
    USE SIGNAL ;
    PORT
      LAYER M4 ;
        RECT  90.636 75.264 90.72 75.288 ;
    END
  END tap_d[295]
  PIN tap_d[296]
    DIRECTION OUTPUT ;
    USE SIGNAL ;
    PORT
      LAYER M4 ;
        RECT  90.636 75.552 90.72 75.576 ;
    END
  END tap_d[296]
  PIN tap_d[297]
    DIRECTION OUTPUT ;
    USE SIGNAL ;
    PORT
      LAYER M4 ;
        RECT  90.636 75.792 90.72 75.816 ;
    END
  END tap_d[297]
  PIN tap_d[298]
    DIRECTION OUTPUT ;
    USE SIGNAL ;
    PORT
      LAYER M4 ;
        RECT  90.636 76.032 90.72 76.056 ;
    END
  END tap_d[298]
  PIN tap_d[299]
    DIRECTION OUTPUT ;
    USE SIGNAL ;
    PORT
      LAYER M4 ;
        RECT  90.636 76.32 90.72 76.344 ;
    END
  END tap_d[299]
  PIN tap_d[29]
    DIRECTION OUTPUT ;
    USE SIGNAL ;
    PORT
      LAYER M4 ;
        RECT  90.636 7.968 90.72 7.992 ;
    END
  END tap_d[29]
  PIN tap_d[2]
    DIRECTION OUTPUT ;
    USE SIGNAL ;
    PORT
      LAYER M4 ;
        RECT  90.636 1.152 90.72 1.176 ;
    END
  END tap_d[2]
  PIN tap_d[300]
    DIRECTION OUTPUT ;
    USE SIGNAL ;
    PORT
      LAYER M4 ;
        RECT  90.636 76.56 90.72 76.584 ;
    END
  END tap_d[300]
  PIN tap_d[301]
    DIRECTION OUTPUT ;
    USE SIGNAL ;
    PORT
      LAYER M4 ;
        RECT  90.636 76.8 90.72 76.824 ;
    END
  END tap_d[301]
  PIN tap_d[302]
    DIRECTION OUTPUT ;
    USE SIGNAL ;
    PORT
      LAYER M4 ;
        RECT  90.636 77.04 90.72 77.064 ;
    END
  END tap_d[302]
  PIN tap_d[303]
    DIRECTION OUTPUT ;
    USE SIGNAL ;
    PORT
      LAYER M4 ;
        RECT  90.636 77.328 90.72 77.352 ;
    END
  END tap_d[303]
  PIN tap_d[304]
    DIRECTION OUTPUT ;
    USE SIGNAL ;
    PORT
      LAYER M4 ;
        RECT  90.636 77.568 90.72 77.592 ;
    END
  END tap_d[304]
  PIN tap_d[305]
    DIRECTION OUTPUT ;
    USE SIGNAL ;
    PORT
      LAYER M4 ;
        RECT  90.636 77.808 90.72 77.832 ;
    END
  END tap_d[305]
  PIN tap_d[306]
    DIRECTION OUTPUT ;
    USE SIGNAL ;
    PORT
      LAYER M4 ;
        RECT  90.636 78.048 90.72 78.072 ;
    END
  END tap_d[306]
  PIN tap_d[307]
    DIRECTION OUTPUT ;
    USE SIGNAL ;
    PORT
      LAYER M4 ;
        RECT  90.636 78.336 90.72 78.36 ;
    END
  END tap_d[307]
  PIN tap_d[308]
    DIRECTION OUTPUT ;
    USE SIGNAL ;
    PORT
      LAYER M4 ;
        RECT  90.636 78.576 90.72 78.6 ;
    END
  END tap_d[308]
  PIN tap_d[309]
    DIRECTION OUTPUT ;
    USE SIGNAL ;
    PORT
      LAYER M4 ;
        RECT  90.636 78.816 90.72 78.84 ;
    END
  END tap_d[309]
  PIN tap_d[30]
    DIRECTION OUTPUT ;
    USE SIGNAL ;
    PORT
      LAYER M4 ;
        RECT  90.636 8.256 90.72 8.28 ;
    END
  END tap_d[30]
  PIN tap_d[310]
    DIRECTION OUTPUT ;
    USE SIGNAL ;
    PORT
      LAYER M4 ;
        RECT  90.636 79.104 90.72 79.128 ;
    END
  END tap_d[310]
  PIN tap_d[311]
    DIRECTION OUTPUT ;
    USE SIGNAL ;
    PORT
      LAYER M4 ;
        RECT  90.636 79.344 90.72 79.368 ;
    END
  END tap_d[311]
  PIN tap_d[312]
    DIRECTION OUTPUT ;
    USE SIGNAL ;
    PORT
      LAYER M4 ;
        RECT  90.636 79.584 90.72 79.608 ;
    END
  END tap_d[312]
  PIN tap_d[313]
    DIRECTION OUTPUT ;
    USE SIGNAL ;
    PORT
      LAYER M4 ;
        RECT  90.636 79.824 90.72 79.848 ;
    END
  END tap_d[313]
  PIN tap_d[314]
    DIRECTION OUTPUT ;
    USE SIGNAL ;
    PORT
      LAYER M4 ;
        RECT  90.636 80.112 90.72 80.136 ;
    END
  END tap_d[314]
  PIN tap_d[315]
    DIRECTION OUTPUT ;
    USE SIGNAL ;
    PORT
      LAYER M4 ;
        RECT  90.636 80.352 90.72 80.376 ;
    END
  END tap_d[315]
  PIN tap_d[316]
    DIRECTION OUTPUT ;
    USE SIGNAL ;
    PORT
      LAYER M4 ;
        RECT  90.636 80.592 90.72 80.616 ;
    END
  END tap_d[316]
  PIN tap_d[317]
    DIRECTION OUTPUT ;
    USE SIGNAL ;
    PORT
      LAYER M4 ;
        RECT  90.636 80.832 90.72 80.856 ;
    END
  END tap_d[317]
  PIN tap_d[318]
    DIRECTION OUTPUT ;
    USE SIGNAL ;
    PORT
      LAYER M4 ;
        RECT  90.636 81.12 90.72 81.144 ;
    END
  END tap_d[318]
  PIN tap_d[319]
    DIRECTION OUTPUT ;
    USE SIGNAL ;
    PORT
      LAYER M4 ;
        RECT  90.636 81.36 90.72 81.384 ;
    END
  END tap_d[319]
  PIN tap_d[31]
    DIRECTION OUTPUT ;
    USE SIGNAL ;
    PORT
      LAYER M4 ;
        RECT  90.636 8.496 90.72 8.52 ;
    END
  END tap_d[31]
  PIN tap_d[320]
    DIRECTION OUTPUT ;
    USE SIGNAL ;
    PORT
      LAYER M4 ;
        RECT  90.636 81.6 90.72 81.624 ;
    END
  END tap_d[320]
  PIN tap_d[321]
    DIRECTION OUTPUT ;
    USE SIGNAL ;
    PORT
      LAYER M4 ;
        RECT  90.636 81.888 90.72 81.912 ;
    END
  END tap_d[321]
  PIN tap_d[322]
    DIRECTION OUTPUT ;
    USE SIGNAL ;
    PORT
      LAYER M4 ;
        RECT  90.636 82.128 90.72 82.152 ;
    END
  END tap_d[322]
  PIN tap_d[323]
    DIRECTION OUTPUT ;
    USE SIGNAL ;
    PORT
      LAYER M4 ;
        RECT  90.636 82.368 90.72 82.392 ;
    END
  END tap_d[323]
  PIN tap_d[324]
    DIRECTION OUTPUT ;
    USE SIGNAL ;
    PORT
      LAYER M4 ;
        RECT  90.636 82.608 90.72 82.632 ;
    END
  END tap_d[324]
  PIN tap_d[325]
    DIRECTION OUTPUT ;
    USE SIGNAL ;
    PORT
      LAYER M4 ;
        RECT  90.636 82.896 90.72 82.92 ;
    END
  END tap_d[325]
  PIN tap_d[326]
    DIRECTION OUTPUT ;
    USE SIGNAL ;
    PORT
      LAYER M4 ;
        RECT  90.636 83.136 90.72 83.16 ;
    END
  END tap_d[326]
  PIN tap_d[327]
    DIRECTION OUTPUT ;
    USE SIGNAL ;
    PORT
      LAYER M4 ;
        RECT  90.636 83.376 90.72 83.4 ;
    END
  END tap_d[327]
  PIN tap_d[328]
    DIRECTION OUTPUT ;
    USE SIGNAL ;
    PORT
      LAYER M4 ;
        RECT  90.636 83.616 90.72 83.64 ;
    END
  END tap_d[328]
  PIN tap_d[329]
    DIRECTION OUTPUT ;
    USE SIGNAL ;
    PORT
      LAYER M4 ;
        RECT  90.636 83.904 90.72 83.928 ;
    END
  END tap_d[329]
  PIN tap_d[32]
    DIRECTION OUTPUT ;
    USE SIGNAL ;
    PORT
      LAYER M4 ;
        RECT  90.636 8.736 90.72 8.76 ;
    END
  END tap_d[32]
  PIN tap_d[330]
    DIRECTION OUTPUT ;
    USE SIGNAL ;
    PORT
      LAYER M4 ;
        RECT  90.636 84.144 90.72 84.168 ;
    END
  END tap_d[330]
  PIN tap_d[331]
    DIRECTION OUTPUT ;
    USE SIGNAL ;
    PORT
      LAYER M4 ;
        RECT  90.636 84.384 90.72 84.408 ;
    END
  END tap_d[331]
  PIN tap_d[332]
    DIRECTION OUTPUT ;
    USE SIGNAL ;
    PORT
      LAYER M4 ;
        RECT  90.636 84.672 90.72 84.696 ;
    END
  END tap_d[332]
  PIN tap_d[333]
    DIRECTION OUTPUT ;
    USE SIGNAL ;
    PORT
      LAYER M4 ;
        RECT  90.636 84.912 90.72 84.936 ;
    END
  END tap_d[333]
  PIN tap_d[334]
    DIRECTION OUTPUT ;
    USE SIGNAL ;
    PORT
      LAYER M4 ;
        RECT  90.636 85.152 90.72 85.176 ;
    END
  END tap_d[334]
  PIN tap_d[335]
    DIRECTION OUTPUT ;
    USE SIGNAL ;
    PORT
      LAYER M4 ;
        RECT  90.636 85.392 90.72 85.416 ;
    END
  END tap_d[335]
  PIN tap_d[336]
    DIRECTION OUTPUT ;
    USE SIGNAL ;
    PORT
      LAYER M4 ;
        RECT  90.636 85.68 90.72 85.704 ;
    END
  END tap_d[336]
  PIN tap_d[337]
    DIRECTION OUTPUT ;
    USE SIGNAL ;
    PORT
      LAYER M4 ;
        RECT  90.636 85.92 90.72 85.944 ;
    END
  END tap_d[337]
  PIN tap_d[338]
    DIRECTION OUTPUT ;
    USE SIGNAL ;
    PORT
      LAYER M4 ;
        RECT  90.636 86.16 90.72 86.184 ;
    END
  END tap_d[338]
  PIN tap_d[339]
    DIRECTION OUTPUT ;
    USE SIGNAL ;
    PORT
      LAYER M4 ;
        RECT  90.636 86.4 90.72 86.424 ;
    END
  END tap_d[339]
  PIN tap_d[33]
    DIRECTION OUTPUT ;
    USE SIGNAL ;
    PORT
      LAYER M4 ;
        RECT  90.636 9.024 90.72 9.048 ;
    END
  END tap_d[33]
  PIN tap_d[340]
    DIRECTION OUTPUT ;
    USE SIGNAL ;
    PORT
      LAYER M4 ;
        RECT  90.636 86.688 90.72 86.712 ;
    END
  END tap_d[340]
  PIN tap_d[341]
    DIRECTION OUTPUT ;
    USE SIGNAL ;
    PORT
      LAYER M4 ;
        RECT  90.636 86.928 90.72 86.952 ;
    END
  END tap_d[341]
  PIN tap_d[342]
    DIRECTION OUTPUT ;
    USE SIGNAL ;
    PORT
      LAYER M4 ;
        RECT  90.636 87.168 90.72 87.192 ;
    END
  END tap_d[342]
  PIN tap_d[343]
    DIRECTION OUTPUT ;
    USE SIGNAL ;
    PORT
      LAYER M4 ;
        RECT  90.636 87.408 90.72 87.432 ;
    END
  END tap_d[343]
  PIN tap_d[344]
    DIRECTION OUTPUT ;
    USE SIGNAL ;
    PORT
      LAYER M4 ;
        RECT  90.636 87.696 90.72 87.72 ;
    END
  END tap_d[344]
  PIN tap_d[345]
    DIRECTION OUTPUT ;
    USE SIGNAL ;
    PORT
      LAYER M4 ;
        RECT  90.636 87.936 90.72 87.96 ;
    END
  END tap_d[345]
  PIN tap_d[346]
    DIRECTION OUTPUT ;
    USE SIGNAL ;
    PORT
      LAYER M4 ;
        RECT  90.636 88.176 90.72 88.2 ;
    END
  END tap_d[346]
  PIN tap_d[347]
    DIRECTION OUTPUT ;
    USE SIGNAL ;
    PORT
      LAYER M4 ;
        RECT  90.636 88.464 90.72 88.488 ;
    END
  END tap_d[347]
  PIN tap_d[348]
    DIRECTION OUTPUT ;
    USE SIGNAL ;
    PORT
      LAYER M4 ;
        RECT  90.636 88.704 90.72 88.728 ;
    END
  END tap_d[348]
  PIN tap_d[349]
    DIRECTION OUTPUT ;
    USE SIGNAL ;
    PORT
      LAYER M4 ;
        RECT  90.636 88.944 90.72 88.968 ;
    END
  END tap_d[349]
  PIN tap_d[34]
    DIRECTION OUTPUT ;
    USE SIGNAL ;
    PORT
      LAYER M4 ;
        RECT  90.636 9.264 90.72 9.288 ;
    END
  END tap_d[34]
  PIN tap_d[350]
    DIRECTION OUTPUT ;
    USE SIGNAL ;
    PORT
      LAYER M4 ;
        RECT  90.636 89.184 90.72 89.208 ;
    END
  END tap_d[350]
  PIN tap_d[351]
    DIRECTION OUTPUT ;
    USE SIGNAL ;
    PORT
      LAYER M4 ;
        RECT  90.636 89.472 90.72 89.496 ;
    END
  END tap_d[351]
  PIN tap_d[352]
    DIRECTION OUTPUT ;
    USE SIGNAL ;
    PORT
      LAYER M4 ;
        RECT  90.636 89.712 90.72 89.736 ;
    END
  END tap_d[352]
  PIN tap_d[353]
    DIRECTION OUTPUT ;
    USE SIGNAL ;
    PORT
      LAYER M4 ;
        RECT  90.636 89.952 90.72 89.976 ;
    END
  END tap_d[353]
  PIN tap_d[354]
    DIRECTION OUTPUT ;
    USE SIGNAL ;
    PORT
      LAYER M4 ;
        RECT  90.636 90.192 90.72 90.216 ;
    END
  END tap_d[354]
  PIN tap_d[355]
    DIRECTION OUTPUT ;
    USE SIGNAL ;
    PORT
      LAYER M4 ;
        RECT  90.636 90.48 90.72 90.504 ;
    END
  END tap_d[355]
  PIN tap_d[356]
    DIRECTION OUTPUT ;
    USE SIGNAL ;
    PORT
      LAYER M4 ;
        RECT  90.636 90.72 90.72 90.744 ;
    END
  END tap_d[356]
  PIN tap_d[357]
    DIRECTION OUTPUT ;
    USE SIGNAL ;
    PORT
      LAYER M4 ;
        RECT  90.636 90.96 90.72 90.984 ;
    END
  END tap_d[357]
  PIN tap_d[358]
    DIRECTION OUTPUT ;
    USE SIGNAL ;
    PORT
      LAYER M4 ;
        RECT  90.636 91.248 90.72 91.272 ;
    END
  END tap_d[358]
  PIN tap_d[359]
    DIRECTION OUTPUT ;
    USE SIGNAL ;
    PORT
      LAYER M4 ;
        RECT  90.636 91.488 90.72 91.512 ;
    END
  END tap_d[359]
  PIN tap_d[35]
    DIRECTION OUTPUT ;
    USE SIGNAL ;
    PORT
      LAYER M4 ;
        RECT  90.636 9.504 90.72 9.528 ;
    END
  END tap_d[35]
  PIN tap_d[360]
    DIRECTION OUTPUT ;
    USE SIGNAL ;
    PORT
      LAYER M4 ;
        RECT  90.636 91.728 90.72 91.752 ;
    END
  END tap_d[360]
  PIN tap_d[361]
    DIRECTION OUTPUT ;
    USE SIGNAL ;
    PORT
      LAYER M4 ;
        RECT  90.636 91.968 90.72 91.992 ;
    END
  END tap_d[361]
  PIN tap_d[362]
    DIRECTION OUTPUT ;
    USE SIGNAL ;
    PORT
      LAYER M4 ;
        RECT  90.636 92.256 90.72 92.28 ;
    END
  END tap_d[362]
  PIN tap_d[363]
    DIRECTION OUTPUT ;
    USE SIGNAL ;
    PORT
      LAYER M4 ;
        RECT  90.636 92.496 90.72 92.52 ;
    END
  END tap_d[363]
  PIN tap_d[364]
    DIRECTION OUTPUT ;
    USE SIGNAL ;
    PORT
      LAYER M4 ;
        RECT  90.636 92.736 90.72 92.76 ;
    END
  END tap_d[364]
  PIN tap_d[365]
    DIRECTION OUTPUT ;
    USE SIGNAL ;
    PORT
      LAYER M4 ;
        RECT  90.636 92.976 90.72 93 ;
    END
  END tap_d[365]
  PIN tap_d[366]
    DIRECTION OUTPUT ;
    USE SIGNAL ;
    PORT
      LAYER M4 ;
        RECT  90.636 93.264 90.72 93.288 ;
    END
  END tap_d[366]
  PIN tap_d[367]
    DIRECTION OUTPUT ;
    USE SIGNAL ;
    PORT
      LAYER M4 ;
        RECT  90.636 93.504 90.72 93.528 ;
    END
  END tap_d[367]
  PIN tap_d[368]
    DIRECTION OUTPUT ;
    USE SIGNAL ;
    PORT
      LAYER M4 ;
        RECT  90.636 93.744 90.72 93.768 ;
    END
  END tap_d[368]
  PIN tap_d[369]
    DIRECTION OUTPUT ;
    USE SIGNAL ;
    PORT
      LAYER M4 ;
        RECT  90.636 94.032 90.72 94.056 ;
    END
  END tap_d[369]
  PIN tap_d[36]
    DIRECTION OUTPUT ;
    USE SIGNAL ;
    PORT
      LAYER M4 ;
        RECT  90.636 9.744 90.72 9.768 ;
    END
  END tap_d[36]
  PIN tap_d[370]
    DIRECTION OUTPUT ;
    USE SIGNAL ;
    PORT
      LAYER M4 ;
        RECT  90.636 94.272 90.72 94.296 ;
    END
  END tap_d[370]
  PIN tap_d[371]
    DIRECTION OUTPUT ;
    USE SIGNAL ;
    PORT
      LAYER M4 ;
        RECT  90.636 94.512 90.72 94.536 ;
    END
  END tap_d[371]
  PIN tap_d[372]
    DIRECTION OUTPUT ;
    USE SIGNAL ;
    PORT
      LAYER M4 ;
        RECT  90.636 94.752 90.72 94.776 ;
    END
  END tap_d[372]
  PIN tap_d[373]
    DIRECTION OUTPUT ;
    USE SIGNAL ;
    PORT
      LAYER M4 ;
        RECT  90.636 95.04 90.72 95.064 ;
    END
  END tap_d[373]
  PIN tap_d[374]
    DIRECTION OUTPUT ;
    USE SIGNAL ;
    PORT
      LAYER M4 ;
        RECT  90.636 95.28 90.72 95.304 ;
    END
  END tap_d[374]
  PIN tap_d[375]
    DIRECTION OUTPUT ;
    USE SIGNAL ;
    PORT
      LAYER M4 ;
        RECT  90.636 95.52 90.72 95.544 ;
    END
  END tap_d[375]
  PIN tap_d[376]
    DIRECTION OUTPUT ;
    USE SIGNAL ;
    PORT
      LAYER M4 ;
        RECT  90.636 95.76 90.72 95.784 ;
    END
  END tap_d[376]
  PIN tap_d[377]
    DIRECTION OUTPUT ;
    USE SIGNAL ;
    PORT
      LAYER M4 ;
        RECT  90.636 96.048 90.72 96.072 ;
    END
  END tap_d[377]
  PIN tap_d[378]
    DIRECTION OUTPUT ;
    USE SIGNAL ;
    PORT
      LAYER M4 ;
        RECT  90.636 96.288 90.72 96.312 ;
    END
  END tap_d[378]
  PIN tap_d[379]
    DIRECTION OUTPUT ;
    USE SIGNAL ;
    PORT
      LAYER M4 ;
        RECT  90.636 96.528 90.72 96.552 ;
    END
  END tap_d[379]
  PIN tap_d[37]
    DIRECTION OUTPUT ;
    USE SIGNAL ;
    PORT
      LAYER M4 ;
        RECT  90.636 10.032 90.72 10.056 ;
    END
  END tap_d[37]
  PIN tap_d[380]
    DIRECTION OUTPUT ;
    USE SIGNAL ;
    PORT
      LAYER M4 ;
        RECT  90.636 96.816 90.72 96.84 ;
    END
  END tap_d[380]
  PIN tap_d[381]
    DIRECTION OUTPUT ;
    USE SIGNAL ;
    PORT
      LAYER M4 ;
        RECT  90.636 97.056 90.72 97.08 ;
    END
  END tap_d[381]
  PIN tap_d[382]
    DIRECTION OUTPUT ;
    USE SIGNAL ;
    PORT
      LAYER M4 ;
        RECT  90.636 97.296 90.72 97.32 ;
    END
  END tap_d[382]
  PIN tap_d[383]
    DIRECTION OUTPUT ;
    USE SIGNAL ;
    PORT
      LAYER M4 ;
        RECT  90.636 97.536 90.72 97.56 ;
    END
  END tap_d[383]
  PIN tap_d[384]
    DIRECTION OUTPUT ;
    USE SIGNAL ;
    PORT
      LAYER M4 ;
        RECT  90.636 97.824 90.72 97.848 ;
    END
  END tap_d[384]
  PIN tap_d[385]
    DIRECTION OUTPUT ;
    USE SIGNAL ;
    PORT
      LAYER M4 ;
        RECT  90.636 98.064 90.72 98.088 ;
    END
  END tap_d[385]
  PIN tap_d[386]
    DIRECTION OUTPUT ;
    USE SIGNAL ;
    PORT
      LAYER M4 ;
        RECT  90.636 98.304 90.72 98.328 ;
    END
  END tap_d[386]
  PIN tap_d[387]
    DIRECTION OUTPUT ;
    USE SIGNAL ;
    PORT
      LAYER M4 ;
        RECT  90.636 98.544 90.72 98.568 ;
    END
  END tap_d[387]
  PIN tap_d[388]
    DIRECTION OUTPUT ;
    USE SIGNAL ;
    PORT
      LAYER M4 ;
        RECT  90.636 98.832 90.72 98.856 ;
    END
  END tap_d[388]
  PIN tap_d[389]
    DIRECTION OUTPUT ;
    USE SIGNAL ;
    PORT
      LAYER M4 ;
        RECT  90.636 99.072 90.72 99.096 ;
    END
  END tap_d[389]
  PIN tap_d[38]
    DIRECTION OUTPUT ;
    USE SIGNAL ;
    PORT
      LAYER M4 ;
        RECT  90.636 10.272 90.72 10.296 ;
    END
  END tap_d[38]
  PIN tap_d[390]
    DIRECTION OUTPUT ;
    USE SIGNAL ;
    PORT
      LAYER M4 ;
        RECT  90.636 99.312 90.72 99.336 ;
    END
  END tap_d[390]
  PIN tap_d[391]
    DIRECTION OUTPUT ;
    USE SIGNAL ;
    PORT
      LAYER M4 ;
        RECT  90.636 99.552 90.72 99.576 ;
    END
  END tap_d[391]
  PIN tap_d[392]
    DIRECTION OUTPUT ;
    USE SIGNAL ;
    PORT
      LAYER M4 ;
        RECT  90.636 99.84 90.72 99.864 ;
    END
  END tap_d[392]
  PIN tap_d[393]
    DIRECTION OUTPUT ;
    USE SIGNAL ;
    PORT
      LAYER M4 ;
        RECT  90.636 100.08 90.72 100.104 ;
    END
  END tap_d[393]
  PIN tap_d[394]
    DIRECTION OUTPUT ;
    USE SIGNAL ;
    PORT
      LAYER M4 ;
        RECT  90.636 100.32 90.72 100.344 ;
    END
  END tap_d[394]
  PIN tap_d[395]
    DIRECTION OUTPUT ;
    USE SIGNAL ;
    PORT
      LAYER M4 ;
        RECT  90.636 100.608 90.72 100.632 ;
    END
  END tap_d[395]
  PIN tap_d[396]
    DIRECTION OUTPUT ;
    USE SIGNAL ;
    PORT
      LAYER M4 ;
        RECT  90.636 100.848 90.72 100.872 ;
    END
  END tap_d[396]
  PIN tap_d[397]
    DIRECTION OUTPUT ;
    USE SIGNAL ;
    PORT
      LAYER M4 ;
        RECT  90.636 101.088 90.72 101.112 ;
    END
  END tap_d[397]
  PIN tap_d[398]
    DIRECTION OUTPUT ;
    USE SIGNAL ;
    PORT
      LAYER M4 ;
        RECT  90.636 101.328 90.72 101.352 ;
    END
  END tap_d[398]
  PIN tap_d[399]
    DIRECTION OUTPUT ;
    USE SIGNAL ;
    PORT
      LAYER M4 ;
        RECT  90.636 101.616 90.72 101.64 ;
    END
  END tap_d[399]
  PIN tap_d[39]
    DIRECTION OUTPUT ;
    USE SIGNAL ;
    PORT
      LAYER M4 ;
        RECT  90.636 10.512 90.72 10.536 ;
    END
  END tap_d[39]
  PIN tap_d[3]
    DIRECTION OUTPUT ;
    USE SIGNAL ;
    PORT
      LAYER M4 ;
        RECT  90.636 1.392 90.72 1.416 ;
    END
  END tap_d[3]
  PIN tap_d[400]
    DIRECTION OUTPUT ;
    USE SIGNAL ;
    PORT
      LAYER M4 ;
        RECT  90.636 101.856 90.72 101.88 ;
    END
  END tap_d[400]
  PIN tap_d[401]
    DIRECTION OUTPUT ;
    USE SIGNAL ;
    PORT
      LAYER M4 ;
        RECT  90.636 102.096 90.72 102.12 ;
    END
  END tap_d[401]
  PIN tap_d[402]
    DIRECTION OUTPUT ;
    USE SIGNAL ;
    PORT
      LAYER M4 ;
        RECT  90.636 102.336 90.72 102.36 ;
    END
  END tap_d[402]
  PIN tap_d[403]
    DIRECTION OUTPUT ;
    USE SIGNAL ;
    PORT
      LAYER M4 ;
        RECT  90.636 102.624 90.72 102.648 ;
    END
  END tap_d[403]
  PIN tap_d[404]
    DIRECTION OUTPUT ;
    USE SIGNAL ;
    PORT
      LAYER M4 ;
        RECT  90.636 102.864 90.72 102.888 ;
    END
  END tap_d[404]
  PIN tap_d[405]
    DIRECTION OUTPUT ;
    USE SIGNAL ;
    PORT
      LAYER M4 ;
        RECT  90.636 103.104 90.72 103.128 ;
    END
  END tap_d[405]
  PIN tap_d[406]
    DIRECTION OUTPUT ;
    USE SIGNAL ;
    PORT
      LAYER M4 ;
        RECT  90.636 103.392 90.72 103.416 ;
    END
  END tap_d[406]
  PIN tap_d[407]
    DIRECTION OUTPUT ;
    USE SIGNAL ;
    PORT
      LAYER M4 ;
        RECT  90.636 103.632 90.72 103.656 ;
    END
  END tap_d[407]
  PIN tap_d[408]
    DIRECTION OUTPUT ;
    USE SIGNAL ;
    PORT
      LAYER M4 ;
        RECT  90.636 103.872 90.72 103.896 ;
    END
  END tap_d[408]
  PIN tap_d[409]
    DIRECTION OUTPUT ;
    USE SIGNAL ;
    PORT
      LAYER M4 ;
        RECT  90.636 104.112 90.72 104.136 ;
    END
  END tap_d[409]
  PIN tap_d[40]
    DIRECTION OUTPUT ;
    USE SIGNAL ;
    PORT
      LAYER M4 ;
        RECT  90.636 10.752 90.72 10.776 ;
    END
  END tap_d[40]
  PIN tap_d[410]
    DIRECTION OUTPUT ;
    USE SIGNAL ;
    PORT
      LAYER M4 ;
        RECT  90.636 104.4 90.72 104.424 ;
    END
  END tap_d[410]
  PIN tap_d[411]
    DIRECTION OUTPUT ;
    USE SIGNAL ;
    PORT
      LAYER M4 ;
        RECT  90.636 104.64 90.72 104.664 ;
    END
  END tap_d[411]
  PIN tap_d[412]
    DIRECTION OUTPUT ;
    USE SIGNAL ;
    PORT
      LAYER M4 ;
        RECT  90.636 104.88 90.72 104.904 ;
    END
  END tap_d[412]
  PIN tap_d[413]
    DIRECTION OUTPUT ;
    USE SIGNAL ;
    PORT
      LAYER M4 ;
        RECT  90.636 105.12 90.72 105.144 ;
    END
  END tap_d[413]
  PIN tap_d[414]
    DIRECTION OUTPUT ;
    USE SIGNAL ;
    PORT
      LAYER M4 ;
        RECT  90.636 105.408 90.72 105.432 ;
    END
  END tap_d[414]
  PIN tap_d[415]
    DIRECTION OUTPUT ;
    USE SIGNAL ;
    PORT
      LAYER M4 ;
        RECT  90.636 105.648 90.72 105.672 ;
    END
  END tap_d[415]
  PIN tap_d[416]
    DIRECTION OUTPUT ;
    USE SIGNAL ;
    PORT
      LAYER M4 ;
        RECT  90.636 105.888 90.72 105.912 ;
    END
  END tap_d[416]
  PIN tap_d[417]
    DIRECTION OUTPUT ;
    USE SIGNAL ;
    PORT
      LAYER M4 ;
        RECT  90.636 106.176 90.72 106.2 ;
    END
  END tap_d[417]
  PIN tap_d[418]
    DIRECTION OUTPUT ;
    USE SIGNAL ;
    PORT
      LAYER M4 ;
        RECT  90.636 106.416 90.72 106.44 ;
    END
  END tap_d[418]
  PIN tap_d[419]
    DIRECTION OUTPUT ;
    USE SIGNAL ;
    PORT
      LAYER M4 ;
        RECT  90.636 106.656 90.72 106.68 ;
    END
  END tap_d[419]
  PIN tap_d[41]
    DIRECTION OUTPUT ;
    USE SIGNAL ;
    PORT
      LAYER M4 ;
        RECT  90.636 11.04 90.72 11.064 ;
    END
  END tap_d[41]
  PIN tap_d[420]
    DIRECTION OUTPUT ;
    USE SIGNAL ;
    PORT
      LAYER M4 ;
        RECT  90.636 106.896 90.72 106.92 ;
    END
  END tap_d[420]
  PIN tap_d[421]
    DIRECTION OUTPUT ;
    USE SIGNAL ;
    PORT
      LAYER M4 ;
        RECT  90.636 107.184 90.72 107.208 ;
    END
  END tap_d[421]
  PIN tap_d[422]
    DIRECTION OUTPUT ;
    USE SIGNAL ;
    PORT
      LAYER M4 ;
        RECT  90.636 107.424 90.72 107.448 ;
    END
  END tap_d[422]
  PIN tap_d[423]
    DIRECTION OUTPUT ;
    USE SIGNAL ;
    PORT
      LAYER M4 ;
        RECT  90.636 107.664 90.72 107.688 ;
    END
  END tap_d[423]
  PIN tap_d[424]
    DIRECTION OUTPUT ;
    USE SIGNAL ;
    PORT
      LAYER M4 ;
        RECT  90.636 107.904 90.72 107.928 ;
    END
  END tap_d[424]
  PIN tap_d[425]
    DIRECTION OUTPUT ;
    USE SIGNAL ;
    PORT
      LAYER M4 ;
        RECT  90.636 108.192 90.72 108.216 ;
    END
  END tap_d[425]
  PIN tap_d[426]
    DIRECTION OUTPUT ;
    USE SIGNAL ;
    PORT
      LAYER M4 ;
        RECT  90.636 108.432 90.72 108.456 ;
    END
  END tap_d[426]
  PIN tap_d[427]
    DIRECTION OUTPUT ;
    USE SIGNAL ;
    PORT
      LAYER M4 ;
        RECT  90.636 108.672 90.72 108.696 ;
    END
  END tap_d[427]
  PIN tap_d[428]
    DIRECTION OUTPUT ;
    USE SIGNAL ;
    PORT
      LAYER M4 ;
        RECT  90.636 108.912 90.72 108.936 ;
    END
  END tap_d[428]
  PIN tap_d[429]
    DIRECTION OUTPUT ;
    USE SIGNAL ;
    PORT
      LAYER M4 ;
        RECT  90.636 109.2 90.72 109.224 ;
    END
  END tap_d[429]
  PIN tap_d[42]
    DIRECTION OUTPUT ;
    USE SIGNAL ;
    PORT
      LAYER M4 ;
        RECT  90.636 11.28 90.72 11.304 ;
    END
  END tap_d[42]
  PIN tap_d[430]
    DIRECTION OUTPUT ;
    USE SIGNAL ;
    PORT
      LAYER M4 ;
        RECT  90.636 109.44 90.72 109.464 ;
    END
  END tap_d[430]
  PIN tap_d[431]
    DIRECTION OUTPUT ;
    USE SIGNAL ;
    PORT
      LAYER M4 ;
        RECT  90.636 109.68 90.72 109.704 ;
    END
  END tap_d[431]
  PIN tap_d[432]
    DIRECTION OUTPUT ;
    USE SIGNAL ;
    PORT
      LAYER M4 ;
        RECT  90.636 109.968 90.72 109.992 ;
    END
  END tap_d[432]
  PIN tap_d[433]
    DIRECTION OUTPUT ;
    USE SIGNAL ;
    PORT
      LAYER M4 ;
        RECT  90.636 110.208 90.72 110.232 ;
    END
  END tap_d[433]
  PIN tap_d[434]
    DIRECTION OUTPUT ;
    USE SIGNAL ;
    PORT
      LAYER M4 ;
        RECT  90.636 110.448 90.72 110.472 ;
    END
  END tap_d[434]
  PIN tap_d[435]
    DIRECTION OUTPUT ;
    USE SIGNAL ;
    PORT
      LAYER M4 ;
        RECT  90.636 110.688 90.72 110.712 ;
    END
  END tap_d[435]
  PIN tap_d[436]
    DIRECTION OUTPUT ;
    USE SIGNAL ;
    PORT
      LAYER M4 ;
        RECT  90.636 110.976 90.72 111 ;
    END
  END tap_d[436]
  PIN tap_d[437]
    DIRECTION OUTPUT ;
    USE SIGNAL ;
    PORT
      LAYER M4 ;
        RECT  90.636 111.216 90.72 111.24 ;
    END
  END tap_d[437]
  PIN tap_d[438]
    DIRECTION OUTPUT ;
    USE SIGNAL ;
    PORT
      LAYER M4 ;
        RECT  90.636 111.456 90.72 111.48 ;
    END
  END tap_d[438]
  PIN tap_d[439]
    DIRECTION OUTPUT ;
    USE SIGNAL ;
    PORT
      LAYER M4 ;
        RECT  90.636 111.696 90.72 111.72 ;
    END
  END tap_d[439]
  PIN tap_d[43]
    DIRECTION OUTPUT ;
    USE SIGNAL ;
    PORT
      LAYER M4 ;
        RECT  90.636 11.52 90.72 11.544 ;
    END
  END tap_d[43]
  PIN tap_d[440]
    DIRECTION OUTPUT ;
    USE SIGNAL ;
    PORT
      LAYER M4 ;
        RECT  90.636 111.984 90.72 112.008 ;
    END
  END tap_d[440]
  PIN tap_d[441]
    DIRECTION OUTPUT ;
    USE SIGNAL ;
    PORT
      LAYER M4 ;
        RECT  90.636 112.224 90.72 112.248 ;
    END
  END tap_d[441]
  PIN tap_d[442]
    DIRECTION OUTPUT ;
    USE SIGNAL ;
    PORT
      LAYER M4 ;
        RECT  90.636 112.464 90.72 112.488 ;
    END
  END tap_d[442]
  PIN tap_d[443]
    DIRECTION OUTPUT ;
    USE SIGNAL ;
    PORT
      LAYER M4 ;
        RECT  90.636 112.752 90.72 112.776 ;
    END
  END tap_d[443]
  PIN tap_d[444]
    DIRECTION OUTPUT ;
    USE SIGNAL ;
    PORT
      LAYER M4 ;
        RECT  90.636 112.992 90.72 113.016 ;
    END
  END tap_d[444]
  PIN tap_d[445]
    DIRECTION OUTPUT ;
    USE SIGNAL ;
    PORT
      LAYER M4 ;
        RECT  90.636 113.232 90.72 113.256 ;
    END
  END tap_d[445]
  PIN tap_d[446]
    DIRECTION OUTPUT ;
    USE SIGNAL ;
    PORT
      LAYER M4 ;
        RECT  90.636 113.472 90.72 113.496 ;
    END
  END tap_d[446]
  PIN tap_d[447]
    DIRECTION OUTPUT ;
    USE SIGNAL ;
    PORT
      LAYER M4 ;
        RECT  90.636 113.76 90.72 113.784 ;
    END
  END tap_d[447]
  PIN tap_d[448]
    DIRECTION OUTPUT ;
    USE SIGNAL ;
    PORT
      LAYER M4 ;
        RECT  90.636 114 90.72 114.024 ;
    END
  END tap_d[448]
  PIN tap_d[449]
    DIRECTION OUTPUT ;
    USE SIGNAL ;
    PORT
      LAYER M4 ;
        RECT  90.636 114.24 90.72 114.264 ;
    END
  END tap_d[449]
  PIN tap_d[44]
    DIRECTION OUTPUT ;
    USE SIGNAL ;
    PORT
      LAYER M4 ;
        RECT  90.636 11.808 90.72 11.832 ;
    END
  END tap_d[44]
  PIN tap_d[450]
    DIRECTION OUTPUT ;
    USE SIGNAL ;
    PORT
      LAYER M4 ;
        RECT  90.636 114.48 90.72 114.504 ;
    END
  END tap_d[450]
  PIN tap_d[451]
    DIRECTION OUTPUT ;
    USE SIGNAL ;
    PORT
      LAYER M4 ;
        RECT  90.636 114.768 90.72 114.792 ;
    END
  END tap_d[451]
  PIN tap_d[452]
    DIRECTION OUTPUT ;
    USE SIGNAL ;
    PORT
      LAYER M4 ;
        RECT  90.636 115.008 90.72 115.032 ;
    END
  END tap_d[452]
  PIN tap_d[453]
    DIRECTION OUTPUT ;
    USE SIGNAL ;
    PORT
      LAYER M4 ;
        RECT  90.636 115.248 90.72 115.272 ;
    END
  END tap_d[453]
  PIN tap_d[454]
    DIRECTION OUTPUT ;
    USE SIGNAL ;
    PORT
      LAYER M4 ;
        RECT  90.636 115.536 90.72 115.56 ;
    END
  END tap_d[454]
  PIN tap_d[455]
    DIRECTION OUTPUT ;
    USE SIGNAL ;
    PORT
      LAYER M4 ;
        RECT  90.636 115.776 90.72 115.8 ;
    END
  END tap_d[455]
  PIN tap_d[456]
    DIRECTION OUTPUT ;
    USE SIGNAL ;
    PORT
      LAYER M4 ;
        RECT  90.636 116.016 90.72 116.04 ;
    END
  END tap_d[456]
  PIN tap_d[457]
    DIRECTION OUTPUT ;
    USE SIGNAL ;
    PORT
      LAYER M4 ;
        RECT  90.636 116.256 90.72 116.28 ;
    END
  END tap_d[457]
  PIN tap_d[458]
    DIRECTION OUTPUT ;
    USE SIGNAL ;
    PORT
      LAYER M4 ;
        RECT  90.636 116.544 90.72 116.568 ;
    END
  END tap_d[458]
  PIN tap_d[459]
    DIRECTION OUTPUT ;
    USE SIGNAL ;
    PORT
      LAYER M4 ;
        RECT  90.636 116.784 90.72 116.808 ;
    END
  END tap_d[459]
  PIN tap_d[45]
    DIRECTION OUTPUT ;
    USE SIGNAL ;
    PORT
      LAYER M4 ;
        RECT  90.636 12.048 90.72 12.072 ;
    END
  END tap_d[45]
  PIN tap_d[460]
    DIRECTION OUTPUT ;
    USE SIGNAL ;
    PORT
      LAYER M4 ;
        RECT  90.636 117.024 90.72 117.048 ;
    END
  END tap_d[460]
  PIN tap_d[461]
    DIRECTION OUTPUT ;
    USE SIGNAL ;
    PORT
      LAYER M4 ;
        RECT  90.636 117.264 90.72 117.288 ;
    END
  END tap_d[461]
  PIN tap_d[462]
    DIRECTION OUTPUT ;
    USE SIGNAL ;
    PORT
      LAYER M4 ;
        RECT  90.636 117.552 90.72 117.576 ;
    END
  END tap_d[462]
  PIN tap_d[463]
    DIRECTION OUTPUT ;
    USE SIGNAL ;
    PORT
      LAYER M4 ;
        RECT  90.636 117.792 90.72 117.816 ;
    END
  END tap_d[463]
  PIN tap_d[464]
    DIRECTION OUTPUT ;
    USE SIGNAL ;
    PORT
      LAYER M4 ;
        RECT  90.636 118.032 90.72 118.056 ;
    END
  END tap_d[464]
  PIN tap_d[465]
    DIRECTION OUTPUT ;
    USE SIGNAL ;
    PORT
      LAYER M4 ;
        RECT  90.636 118.32 90.72 118.344 ;
    END
  END tap_d[465]
  PIN tap_d[466]
    DIRECTION OUTPUT ;
    USE SIGNAL ;
    PORT
      LAYER M4 ;
        RECT  90.636 118.56 90.72 118.584 ;
    END
  END tap_d[466]
  PIN tap_d[467]
    DIRECTION OUTPUT ;
    USE SIGNAL ;
    PORT
      LAYER M4 ;
        RECT  90.636 118.8 90.72 118.824 ;
    END
  END tap_d[467]
  PIN tap_d[468]
    DIRECTION OUTPUT ;
    USE SIGNAL ;
    PORT
      LAYER M4 ;
        RECT  90.636 119.04 90.72 119.064 ;
    END
  END tap_d[468]
  PIN tap_d[469]
    DIRECTION OUTPUT ;
    USE SIGNAL ;
    PORT
      LAYER M4 ;
        RECT  90.636 119.328 90.72 119.352 ;
    END
  END tap_d[469]
  PIN tap_d[46]
    DIRECTION OUTPUT ;
    USE SIGNAL ;
    PORT
      LAYER M4 ;
        RECT  90.636 12.288 90.72 12.312 ;
    END
  END tap_d[46]
  PIN tap_d[470]
    DIRECTION OUTPUT ;
    USE SIGNAL ;
    PORT
      LAYER M4 ;
        RECT  90.636 119.568 90.72 119.592 ;
    END
  END tap_d[470]
  PIN tap_d[471]
    DIRECTION OUTPUT ;
    USE SIGNAL ;
    PORT
      LAYER M4 ;
        RECT  90.636 119.808 90.72 119.832 ;
    END
  END tap_d[471]
  PIN tap_d[472]
    DIRECTION OUTPUT ;
    USE SIGNAL ;
    PORT
      LAYER M4 ;
        RECT  90.636 120.048 90.72 120.072 ;
    END
  END tap_d[472]
  PIN tap_d[473]
    DIRECTION OUTPUT ;
    USE SIGNAL ;
    PORT
      LAYER M4 ;
        RECT  90.636 120.336 90.72 120.36 ;
    END
  END tap_d[473]
  PIN tap_d[474]
    DIRECTION OUTPUT ;
    USE SIGNAL ;
    PORT
      LAYER M4 ;
        RECT  90.636 120.576 90.72 120.6 ;
    END
  END tap_d[474]
  PIN tap_d[475]
    DIRECTION OUTPUT ;
    USE SIGNAL ;
    PORT
      LAYER M4 ;
        RECT  90.636 120.816 90.72 120.84 ;
    END
  END tap_d[475]
  PIN tap_d[476]
    DIRECTION OUTPUT ;
    USE SIGNAL ;
    PORT
      LAYER M4 ;
        RECT  90.636 121.056 90.72 121.08 ;
    END
  END tap_d[476]
  PIN tap_d[477]
    DIRECTION OUTPUT ;
    USE SIGNAL ;
    PORT
      LAYER M4 ;
        RECT  90.636 121.344 90.72 121.368 ;
    END
  END tap_d[477]
  PIN tap_d[478]
    DIRECTION OUTPUT ;
    USE SIGNAL ;
    PORT
      LAYER M4 ;
        RECT  90.636 121.584 90.72 121.608 ;
    END
  END tap_d[478]
  PIN tap_d[479]
    DIRECTION OUTPUT ;
    USE SIGNAL ;
    PORT
      LAYER M4 ;
        RECT  90.636 121.824 90.72 121.848 ;
    END
  END tap_d[479]
  PIN tap_d[47]
    DIRECTION OUTPUT ;
    USE SIGNAL ;
    PORT
      LAYER M4 ;
        RECT  90.636 12.528 90.72 12.552 ;
    END
  END tap_d[47]
  PIN tap_d[480]
    DIRECTION OUTPUT ;
    USE SIGNAL ;
    PORT
      LAYER M4 ;
        RECT  90.636 122.112 90.72 122.136 ;
    END
  END tap_d[480]
  PIN tap_d[481]
    DIRECTION OUTPUT ;
    USE SIGNAL ;
    PORT
      LAYER M4 ;
        RECT  90.636 122.352 90.72 122.376 ;
    END
  END tap_d[481]
  PIN tap_d[482]
    DIRECTION OUTPUT ;
    USE SIGNAL ;
    PORT
      LAYER M4 ;
        RECT  90.636 122.592 90.72 122.616 ;
    END
  END tap_d[482]
  PIN tap_d[483]
    DIRECTION OUTPUT ;
    USE SIGNAL ;
    PORT
      LAYER M4 ;
        RECT  90.636 122.832 90.72 122.856 ;
    END
  END tap_d[483]
  PIN tap_d[484]
    DIRECTION OUTPUT ;
    USE SIGNAL ;
    PORT
      LAYER M4 ;
        RECT  90.636 123.12 90.72 123.144 ;
    END
  END tap_d[484]
  PIN tap_d[485]
    DIRECTION OUTPUT ;
    USE SIGNAL ;
    PORT
      LAYER M4 ;
        RECT  90.636 123.36 90.72 123.384 ;
    END
  END tap_d[485]
  PIN tap_d[486]
    DIRECTION OUTPUT ;
    USE SIGNAL ;
    PORT
      LAYER M4 ;
        RECT  90.636 123.6 90.72 123.624 ;
    END
  END tap_d[486]
  PIN tap_d[487]
    DIRECTION OUTPUT ;
    USE SIGNAL ;
    PORT
      LAYER M4 ;
        RECT  90.636 123.84 90.72 123.864 ;
    END
  END tap_d[487]
  PIN tap_d[488]
    DIRECTION OUTPUT ;
    USE SIGNAL ;
    PORT
      LAYER M4 ;
        RECT  90.636 124.128 90.72 124.152 ;
    END
  END tap_d[488]
  PIN tap_d[489]
    DIRECTION OUTPUT ;
    USE SIGNAL ;
    PORT
      LAYER M4 ;
        RECT  90.636 124.368 90.72 124.392 ;
    END
  END tap_d[489]
  PIN tap_d[48]
    DIRECTION OUTPUT ;
    USE SIGNAL ;
    PORT
      LAYER M4 ;
        RECT  90.636 12.816 90.72 12.84 ;
    END
  END tap_d[48]
  PIN tap_d[490]
    DIRECTION OUTPUT ;
    USE SIGNAL ;
    PORT
      LAYER M4 ;
        RECT  90.636 124.608 90.72 124.632 ;
    END
  END tap_d[490]
  PIN tap_d[491]
    DIRECTION OUTPUT ;
    USE SIGNAL ;
    PORT
      LAYER M4 ;
        RECT  90.636 124.896 90.72 124.92 ;
    END
  END tap_d[491]
  PIN tap_d[492]
    DIRECTION OUTPUT ;
    USE SIGNAL ;
    PORT
      LAYER M4 ;
        RECT  90.636 125.136 90.72 125.16 ;
    END
  END tap_d[492]
  PIN tap_d[493]
    DIRECTION OUTPUT ;
    USE SIGNAL ;
    PORT
      LAYER M4 ;
        RECT  90.636 125.376 90.72 125.4 ;
    END
  END tap_d[493]
  PIN tap_d[494]
    DIRECTION OUTPUT ;
    USE SIGNAL ;
    PORT
      LAYER M4 ;
        RECT  90.636 125.616 90.72 125.64 ;
    END
  END tap_d[494]
  PIN tap_d[495]
    DIRECTION OUTPUT ;
    USE SIGNAL ;
    PORT
      LAYER M4 ;
        RECT  90.636 125.904 90.72 125.928 ;
    END
  END tap_d[495]
  PIN tap_d[496]
    DIRECTION OUTPUT ;
    USE SIGNAL ;
    PORT
      LAYER M4 ;
        RECT  90.636 126.144 90.72 126.168 ;
    END
  END tap_d[496]
  PIN tap_d[497]
    DIRECTION OUTPUT ;
    USE SIGNAL ;
    PORT
      LAYER M4 ;
        RECT  90.636 126.384 90.72 126.408 ;
    END
  END tap_d[497]
  PIN tap_d[498]
    DIRECTION OUTPUT ;
    USE SIGNAL ;
    PORT
      LAYER M4 ;
        RECT  90.636 126.624 90.72 126.648 ;
    END
  END tap_d[498]
  PIN tap_d[499]
    DIRECTION OUTPUT ;
    USE SIGNAL ;
    PORT
      LAYER M4 ;
        RECT  90.636 126.912 90.72 126.936 ;
    END
  END tap_d[499]
  PIN tap_d[49]
    DIRECTION OUTPUT ;
    USE SIGNAL ;
    PORT
      LAYER M4 ;
        RECT  90.636 13.056 90.72 13.08 ;
    END
  END tap_d[49]
  PIN tap_d[4]
    DIRECTION OUTPUT ;
    USE SIGNAL ;
    PORT
      LAYER M4 ;
        RECT  90.636 1.68 90.72 1.704 ;
    END
  END tap_d[4]
  PIN tap_d[500]
    DIRECTION OUTPUT ;
    USE SIGNAL ;
    PORT
      LAYER M4 ;
        RECT  90.636 127.152 90.72 127.176 ;
    END
  END tap_d[500]
  PIN tap_d[501]
    DIRECTION OUTPUT ;
    USE SIGNAL ;
    PORT
      LAYER M4 ;
        RECT  90.636 127.392 90.72 127.416 ;
    END
  END tap_d[501]
  PIN tap_d[502]
    DIRECTION OUTPUT ;
    USE SIGNAL ;
    PORT
      LAYER M4 ;
        RECT  90.636 127.68 90.72 127.704 ;
    END
  END tap_d[502]
  PIN tap_d[503]
    DIRECTION OUTPUT ;
    USE SIGNAL ;
    PORT
      LAYER M4 ;
        RECT  90.636 127.92 90.72 127.944 ;
    END
  END tap_d[503]
  PIN tap_d[504]
    DIRECTION OUTPUT ;
    USE SIGNAL ;
    PORT
      LAYER M4 ;
        RECT  90.636 128.16 90.72 128.184 ;
    END
  END tap_d[504]
  PIN tap_d[505]
    DIRECTION OUTPUT ;
    USE SIGNAL ;
    PORT
      LAYER M4 ;
        RECT  90.636 128.4 90.72 128.424 ;
    END
  END tap_d[505]
  PIN tap_d[506]
    DIRECTION OUTPUT ;
    USE SIGNAL ;
    PORT
      LAYER M4 ;
        RECT  90.636 128.688 90.72 128.712 ;
    END
  END tap_d[506]
  PIN tap_d[507]
    DIRECTION OUTPUT ;
    USE SIGNAL ;
    PORT
      LAYER M4 ;
        RECT  90.636 128.928 90.72 128.952 ;
    END
  END tap_d[507]
  PIN tap_d[50]
    DIRECTION OUTPUT ;
    USE SIGNAL ;
    PORT
      LAYER M4 ;
        RECT  90.636 13.296 90.72 13.32 ;
    END
  END tap_d[50]
  PIN tap_d[51]
    DIRECTION OUTPUT ;
    USE SIGNAL ;
    PORT
      LAYER M4 ;
        RECT  90.636 13.536 90.72 13.56 ;
    END
  END tap_d[51]
  PIN tap_d[52]
    DIRECTION OUTPUT ;
    USE SIGNAL ;
    PORT
      LAYER M4 ;
        RECT  90.636 13.824 90.72 13.848 ;
    END
  END tap_d[52]
  PIN tap_d[53]
    DIRECTION OUTPUT ;
    USE SIGNAL ;
    PORT
      LAYER M4 ;
        RECT  90.636 14.064 90.72 14.088 ;
    END
  END tap_d[53]
  PIN tap_d[54]
    DIRECTION OUTPUT ;
    USE SIGNAL ;
    PORT
      LAYER M4 ;
        RECT  90.636 14.304 90.72 14.328 ;
    END
  END tap_d[54]
  PIN tap_d[55]
    DIRECTION OUTPUT ;
    USE SIGNAL ;
    PORT
      LAYER M4 ;
        RECT  90.636 14.592 90.72 14.616 ;
    END
  END tap_d[55]
  PIN tap_d[56]
    DIRECTION OUTPUT ;
    USE SIGNAL ;
    PORT
      LAYER M4 ;
        RECT  90.636 14.832 90.72 14.856 ;
    END
  END tap_d[56]
  PIN tap_d[57]
    DIRECTION OUTPUT ;
    USE SIGNAL ;
    PORT
      LAYER M4 ;
        RECT  90.636 15.072 90.72 15.096 ;
    END
  END tap_d[57]
  PIN tap_d[58]
    DIRECTION OUTPUT ;
    USE SIGNAL ;
    PORT
      LAYER M4 ;
        RECT  90.636 15.312 90.72 15.336 ;
    END
  END tap_d[58]
  PIN tap_d[59]
    DIRECTION OUTPUT ;
    USE SIGNAL ;
    PORT
      LAYER M4 ;
        RECT  90.636 15.6 90.72 15.624 ;
    END
  END tap_d[59]
  PIN tap_d[5]
    DIRECTION OUTPUT ;
    USE SIGNAL ;
    PORT
      LAYER M4 ;
        RECT  90.636 1.92 90.72 1.944 ;
    END
  END tap_d[5]
  PIN tap_d[60]
    DIRECTION OUTPUT ;
    USE SIGNAL ;
    PORT
      LAYER M4 ;
        RECT  90.636 15.84 90.72 15.864 ;
    END
  END tap_d[60]
  PIN tap_d[61]
    DIRECTION OUTPUT ;
    USE SIGNAL ;
    PORT
      LAYER M4 ;
        RECT  90.636 16.08 90.72 16.104 ;
    END
  END tap_d[61]
  PIN tap_d[62]
    DIRECTION OUTPUT ;
    USE SIGNAL ;
    PORT
      LAYER M4 ;
        RECT  90.636 16.32 90.72 16.344 ;
    END
  END tap_d[62]
  PIN tap_d[63]
    DIRECTION OUTPUT ;
    USE SIGNAL ;
    PORT
      LAYER M4 ;
        RECT  90.636 16.608 90.72 16.632 ;
    END
  END tap_d[63]
  PIN tap_d[64]
    DIRECTION OUTPUT ;
    USE SIGNAL ;
    PORT
      LAYER M4 ;
        RECT  90.636 16.848 90.72 16.872 ;
    END
  END tap_d[64]
  PIN tap_d[65]
    DIRECTION OUTPUT ;
    USE SIGNAL ;
    PORT
      LAYER M4 ;
        RECT  90.636 17.088 90.72 17.112 ;
    END
  END tap_d[65]
  PIN tap_d[66]
    DIRECTION OUTPUT ;
    USE SIGNAL ;
    PORT
      LAYER M4 ;
        RECT  90.636 17.376 90.72 17.4 ;
    END
  END tap_d[66]
  PIN tap_d[67]
    DIRECTION OUTPUT ;
    USE SIGNAL ;
    PORT
      LAYER M4 ;
        RECT  90.636 17.616 90.72 17.64 ;
    END
  END tap_d[67]
  PIN tap_d[68]
    DIRECTION OUTPUT ;
    USE SIGNAL ;
    PORT
      LAYER M4 ;
        RECT  90.636 17.856 90.72 17.88 ;
    END
  END tap_d[68]
  PIN tap_d[69]
    DIRECTION OUTPUT ;
    USE SIGNAL ;
    PORT
      LAYER M4 ;
        RECT  90.636 18.096 90.72 18.12 ;
    END
  END tap_d[69]
  PIN tap_d[6]
    DIRECTION OUTPUT ;
    USE SIGNAL ;
    PORT
      LAYER M4 ;
        RECT  90.636 2.16 90.72 2.184 ;
    END
  END tap_d[6]
  PIN tap_d[70]
    DIRECTION OUTPUT ;
    USE SIGNAL ;
    PORT
      LAYER M4 ;
        RECT  90.636 18.384 90.72 18.408 ;
    END
  END tap_d[70]
  PIN tap_d[71]
    DIRECTION OUTPUT ;
    USE SIGNAL ;
    PORT
      LAYER M4 ;
        RECT  90.636 18.624 90.72 18.648 ;
    END
  END tap_d[71]
  PIN tap_d[72]
    DIRECTION OUTPUT ;
    USE SIGNAL ;
    PORT
      LAYER M4 ;
        RECT  90.636 18.864 90.72 18.888 ;
    END
  END tap_d[72]
  PIN tap_d[73]
    DIRECTION OUTPUT ;
    USE SIGNAL ;
    PORT
      LAYER M4 ;
        RECT  90.636 19.104 90.72 19.128 ;
    END
  END tap_d[73]
  PIN tap_d[74]
    DIRECTION OUTPUT ;
    USE SIGNAL ;
    PORT
      LAYER M4 ;
        RECT  90.636 19.392 90.72 19.416 ;
    END
  END tap_d[74]
  PIN tap_d[75]
    DIRECTION OUTPUT ;
    USE SIGNAL ;
    PORT
      LAYER M4 ;
        RECT  90.636 19.632 90.72 19.656 ;
    END
  END tap_d[75]
  PIN tap_d[76]
    DIRECTION OUTPUT ;
    USE SIGNAL ;
    PORT
      LAYER M4 ;
        RECT  90.636 19.872 90.72 19.896 ;
    END
  END tap_d[76]
  PIN tap_d[77]
    DIRECTION OUTPUT ;
    USE SIGNAL ;
    PORT
      LAYER M4 ;
        RECT  90.636 20.112 90.72 20.136 ;
    END
  END tap_d[77]
  PIN tap_d[78]
    DIRECTION OUTPUT ;
    USE SIGNAL ;
    PORT
      LAYER M4 ;
        RECT  90.636 20.4 90.72 20.424 ;
    END
  END tap_d[78]
  PIN tap_d[79]
    DIRECTION OUTPUT ;
    USE SIGNAL ;
    PORT
      LAYER M4 ;
        RECT  90.636 20.64 90.72 20.664 ;
    END
  END tap_d[79]
  PIN tap_d[7]
    DIRECTION OUTPUT ;
    USE SIGNAL ;
    PORT
      LAYER M4 ;
        RECT  90.636 2.448 90.72 2.472 ;
    END
  END tap_d[7]
  PIN tap_d[80]
    DIRECTION OUTPUT ;
    USE SIGNAL ;
    PORT
      LAYER M4 ;
        RECT  90.636 20.88 90.72 20.904 ;
    END
  END tap_d[80]
  PIN tap_d[81]
    DIRECTION OUTPUT ;
    USE SIGNAL ;
    PORT
      LAYER M4 ;
        RECT  90.636 21.168 90.72 21.192 ;
    END
  END tap_d[81]
  PIN tap_d[82]
    DIRECTION OUTPUT ;
    USE SIGNAL ;
    PORT
      LAYER M4 ;
        RECT  90.636 21.408 90.72 21.432 ;
    END
  END tap_d[82]
  PIN tap_d[83]
    DIRECTION OUTPUT ;
    USE SIGNAL ;
    PORT
      LAYER M4 ;
        RECT  90.636 21.648 90.72 21.672 ;
    END
  END tap_d[83]
  PIN tap_d[84]
    DIRECTION OUTPUT ;
    USE SIGNAL ;
    PORT
      LAYER M4 ;
        RECT  90.636 21.888 90.72 21.912 ;
    END
  END tap_d[84]
  PIN tap_d[85]
    DIRECTION OUTPUT ;
    USE SIGNAL ;
    PORT
      LAYER M4 ;
        RECT  90.636 22.176 90.72 22.2 ;
    END
  END tap_d[85]
  PIN tap_d[86]
    DIRECTION OUTPUT ;
    USE SIGNAL ;
    PORT
      LAYER M4 ;
        RECT  90.636 22.416 90.72 22.44 ;
    END
  END tap_d[86]
  PIN tap_d[87]
    DIRECTION OUTPUT ;
    USE SIGNAL ;
    PORT
      LAYER M4 ;
        RECT  90.636 22.656 90.72 22.68 ;
    END
  END tap_d[87]
  PIN tap_d[88]
    DIRECTION OUTPUT ;
    USE SIGNAL ;
    PORT
      LAYER M4 ;
        RECT  90.636 22.896 90.72 22.92 ;
    END
  END tap_d[88]
  PIN tap_d[89]
    DIRECTION OUTPUT ;
    USE SIGNAL ;
    PORT
      LAYER M4 ;
        RECT  90.636 23.184 90.72 23.208 ;
    END
  END tap_d[89]
  PIN tap_d[8]
    DIRECTION OUTPUT ;
    USE SIGNAL ;
    PORT
      LAYER M4 ;
        RECT  90.636 2.688 90.72 2.712 ;
    END
  END tap_d[8]
  PIN tap_d[90]
    DIRECTION OUTPUT ;
    USE SIGNAL ;
    PORT
      LAYER M4 ;
        RECT  90.636 23.424 90.72 23.448 ;
    END
  END tap_d[90]
  PIN tap_d[91]
    DIRECTION OUTPUT ;
    USE SIGNAL ;
    PORT
      LAYER M4 ;
        RECT  90.636 23.664 90.72 23.688 ;
    END
  END tap_d[91]
  PIN tap_d[92]
    DIRECTION OUTPUT ;
    USE SIGNAL ;
    PORT
      LAYER M4 ;
        RECT  90.636 23.952 90.72 23.976 ;
    END
  END tap_d[92]
  PIN tap_d[93]
    DIRECTION OUTPUT ;
    USE SIGNAL ;
    PORT
      LAYER M4 ;
        RECT  90.636 24.192 90.72 24.216 ;
    END
  END tap_d[93]
  PIN tap_d[94]
    DIRECTION OUTPUT ;
    USE SIGNAL ;
    PORT
      LAYER M4 ;
        RECT  90.636 24.432 90.72 24.456 ;
    END
  END tap_d[94]
  PIN tap_d[95]
    DIRECTION OUTPUT ;
    USE SIGNAL ;
    PORT
      LAYER M4 ;
        RECT  90.636 24.672 90.72 24.696 ;
    END
  END tap_d[95]
  PIN tap_d[96]
    DIRECTION OUTPUT ;
    USE SIGNAL ;
    PORT
      LAYER M4 ;
        RECT  90.636 24.96 90.72 24.984 ;
    END
  END tap_d[96]
  PIN tap_d[97]
    DIRECTION OUTPUT ;
    USE SIGNAL ;
    PORT
      LAYER M4 ;
        RECT  90.636 25.2 90.72 25.224 ;
    END
  END tap_d[97]
  PIN tap_d[98]
    DIRECTION OUTPUT ;
    USE SIGNAL ;
    PORT
      LAYER M4 ;
        RECT  90.636 25.44 90.72 25.464 ;
    END
  END tap_d[98]
  PIN tap_d[99]
    DIRECTION OUTPUT ;
    USE SIGNAL ;
    PORT
      LAYER M4 ;
        RECT  90.636 25.68 90.72 25.704 ;
    END
  END tap_d[99]
  PIN tap_d[9]
    DIRECTION OUTPUT ;
    USE SIGNAL ;
    PORT
      LAYER M4 ;
        RECT  90.636 2.928 90.72 2.952 ;
    END
  END tap_d[9]
  PIN VDD
    DIRECTION INOUT ;
    USE POWER ;
    PORT
      LAYER M5 ;
        RECT  83.592 2.151 83.712 127.449 ;
        RECT  78.192 2.151 78.312 127.449 ;
        RECT  72.792 2.151 72.912 127.449 ;
        RECT  67.392 2.151 67.512 127.449 ;
        RECT  61.992 2.151 62.112 127.449 ;
        RECT  56.592 2.151 56.712 127.449 ;
        RECT  51.192 2.151 51.312 127.449 ;
        RECT  45.792 2.151 45.912 127.449 ;
        RECT  40.392 2.151 40.512 127.449 ;
        RECT  34.992 2.151 35.112 127.449 ;
        RECT  29.592 2.151 29.712 127.449 ;
        RECT  24.192 2.151 24.312 127.449 ;
        RECT  18.792 2.151 18.912 127.449 ;
        RECT  13.392 2.151 13.512 127.449 ;
        RECT  7.992 2.151 8.112 127.449 ;
        RECT  2.592 2.151 2.712 127.449 ;
    END
  END VDD
  PIN VSS
    DIRECTION INOUT ;
    USE GROUND ;
    PORT
      LAYER M5 ;
        RECT  83.4 2.137 83.52 127.463 ;
        RECT  78 2.137 78.12 127.463 ;
        RECT  72.6 2.137 72.72 127.463 ;
        RECT  67.2 2.137 67.32 127.463 ;
        RECT  61.8 2.137 61.92 127.463 ;
        RECT  56.4 2.137 56.52 127.463 ;
        RECT  51 2.137 51.12 127.463 ;
        RECT  45.6 2.137 45.72 127.463 ;
        RECT  40.2 2.137 40.32 127.463 ;
        RECT  34.8 2.137 34.92 127.463 ;
        RECT  29.4 2.137 29.52 127.463 ;
        RECT  24 2.137 24.12 127.463 ;
        RECT  18.6 2.137 18.72 127.463 ;
        RECT  13.2 2.137 13.32 127.463 ;
        RECT  7.8 2.137 7.92 127.463 ;
        RECT  2.4 2.137 2.52 127.463 ;
    END
  END VSS
  OBS
    LAYER RVTN ;
     RECT  2.16 2.16 88.56 2.295 ;
     RECT  2.16 2.565 88.56 2.835 ;
     RECT  2.16 3.105 88.56 3.375 ;
     RECT  2.16 3.645 88.56 3.915 ;
     RECT  2.16 4.185 88.56 4.455 ;
     RECT  2.16 4.725 88.56 4.995 ;
     RECT  2.16 5.265 88.56 5.535 ;
     RECT  2.16 5.805 88.56 6.075 ;
     RECT  2.16 6.345 88.56 6.615 ;
     RECT  2.16 6.885 88.56 7.155 ;
     RECT  2.16 7.425 88.56 7.695 ;
     RECT  2.16 7.965 88.56 8.235 ;
     RECT  2.16 8.505 88.56 8.775 ;
     RECT  2.16 9.045 88.56 9.315 ;
     RECT  2.16 9.585 88.56 9.855 ;
     RECT  2.16 10.125 88.56 10.395 ;
     RECT  2.16 10.665 88.56 10.935 ;
     RECT  2.16 11.205 88.56 11.475 ;
     RECT  2.16 11.745 88.56 12.015 ;
     RECT  2.16 12.285 88.56 12.555 ;
     RECT  2.16 12.825 88.56 13.095 ;
     RECT  2.16 13.365 88.56 13.635 ;
     RECT  2.16 13.905 88.56 14.175 ;
     RECT  2.16 14.445 88.56 14.715 ;
     RECT  2.16 14.985 88.56 15.255 ;
     RECT  2.16 15.525 88.56 15.795 ;
     RECT  2.16 16.065 88.56 16.335 ;
     RECT  2.16 16.605 88.56 16.875 ;
     RECT  2.16 17.145 88.56 17.415 ;
     RECT  2.16 17.685 88.56 17.955 ;
     RECT  2.16 18.225 88.56 18.495 ;
     RECT  2.16 18.765 88.56 19.035 ;
     RECT  2.16 19.305 88.56 19.575 ;
     RECT  2.16 19.845 88.56 20.115 ;
     RECT  2.16 20.385 88.56 20.655 ;
     RECT  2.16 20.925 88.56 21.195 ;
     RECT  2.16 21.465 88.56 21.735 ;
     RECT  2.16 22.005 88.56 22.275 ;
     RECT  2.16 22.545 88.56 22.815 ;
     RECT  2.16 23.085 88.56 23.355 ;
     RECT  2.16 23.625 88.56 23.895 ;
     RECT  2.16 24.165 88.56 24.435 ;
     RECT  2.16 24.705 88.56 24.975 ;
     RECT  2.16 25.245 88.56 25.515 ;
     RECT  2.16 25.785 88.56 26.055 ;
     RECT  2.16 26.325 88.56 26.595 ;
     RECT  2.16 26.865 88.56 27.135 ;
     RECT  2.16 27.405 88.56 27.675 ;
     RECT  2.16 27.945 88.56 28.215 ;
     RECT  2.16 28.485 88.56 28.755 ;
     RECT  2.16 29.025 88.56 29.295 ;
     RECT  2.16 29.565 88.56 29.835 ;
     RECT  2.16 30.105 88.56 30.375 ;
     RECT  2.16 30.645 88.56 30.915 ;
     RECT  2.16 31.185 88.56 31.455 ;
     RECT  2.16 31.725 88.56 31.995 ;
     RECT  2.16 32.265 88.56 32.535 ;
     RECT  2.16 32.805 88.56 33.075 ;
     RECT  2.16 33.345 88.56 33.615 ;
     RECT  2.16 33.885 88.56 34.155 ;
     RECT  2.16 34.425 88.56 34.695 ;
     RECT  2.16 34.965 88.56 35.235 ;
     RECT  2.16 35.505 88.56 35.775 ;
     RECT  2.16 36.045 88.56 36.315 ;
     RECT  2.16 36.585 88.56 36.855 ;
     RECT  2.16 37.125 88.56 37.395 ;
     RECT  2.16 37.665 88.56 37.935 ;
     RECT  2.16 38.205 88.56 38.475 ;
     RECT  2.16 38.745 88.56 39.015 ;
     RECT  2.16 39.285 88.56 39.555 ;
     RECT  2.16 39.825 88.56 40.095 ;
     RECT  2.16 40.365 88.56 40.635 ;
     RECT  2.16 40.905 88.56 41.175 ;
     RECT  2.16 41.445 88.56 41.715 ;
     RECT  2.16 41.985 88.56 42.255 ;
     RECT  2.16 42.525 88.56 42.795 ;
     RECT  2.16 43.065 88.56 43.335 ;
     RECT  2.16 43.605 88.56 43.875 ;
     RECT  2.16 44.145 88.56 44.415 ;
     RECT  2.16 44.685 88.56 44.955 ;
     RECT  2.16 45.225 88.56 45.495 ;
     RECT  2.16 45.765 88.56 46.035 ;
     RECT  2.16 46.305 88.56 46.575 ;
     RECT  2.16 46.845 88.56 47.115 ;
     RECT  2.16 47.385 88.56 47.655 ;
     RECT  2.16 47.925 88.56 48.195 ;
     RECT  2.16 48.465 88.56 48.735 ;
     RECT  2.16 49.005 88.56 49.275 ;
     RECT  2.16 49.545 88.56 49.815 ;
     RECT  2.16 50.085 88.56 50.355 ;
     RECT  2.16 50.625 88.56 50.895 ;
     RECT  2.16 51.165 88.56 51.435 ;
     RECT  2.16 51.705 88.56 51.975 ;
     RECT  2.16 52.245 88.56 52.515 ;
     RECT  2.16 52.785 88.56 53.055 ;
     RECT  2.16 53.325 88.56 53.595 ;
     RECT  2.16 53.865 88.56 54.135 ;
     RECT  2.16 54.405 88.56 54.675 ;
     RECT  2.16 54.945 88.56 55.215 ;
     RECT  2.16 55.485 88.56 55.755 ;
     RECT  2.16 56.025 88.56 56.295 ;
     RECT  2.16 56.565 88.56 56.835 ;
     RECT  2.16 57.105 88.56 57.375 ;
     RECT  2.16 57.645 88.56 57.915 ;
     RECT  2.16 58.185 88.56 58.455 ;
     RECT  2.16 58.725 88.56 58.995 ;
     RECT  2.16 59.265 88.56 59.535 ;
     RECT  2.16 59.805 88.56 60.075 ;
     RECT  2.16 60.345 88.56 60.615 ;
     RECT  2.16 60.885 88.56 61.155 ;
     RECT  2.16 61.425 88.56 61.695 ;
     RECT  2.16 61.965 88.56 62.235 ;
     RECT  2.16 62.505 88.56 62.775 ;
     RECT  2.16 63.045 88.56 63.315 ;
     RECT  2.16 63.585 88.56 63.855 ;
     RECT  2.16 64.125 88.56 64.395 ;
     RECT  2.16 64.665 88.56 64.935 ;
     RECT  2.16 65.205 88.56 65.475 ;
     RECT  2.16 65.745 88.56 66.015 ;
     RECT  2.16 66.285 88.56 66.555 ;
     RECT  2.16 66.825 88.56 67.095 ;
     RECT  2.16 67.365 88.56 67.635 ;
     RECT  2.16 67.905 88.56 68.175 ;
     RECT  2.16 68.445 88.56 68.715 ;
     RECT  2.16 68.985 88.56 69.255 ;
     RECT  2.16 69.525 88.56 69.795 ;
     RECT  2.16 70.065 88.56 70.335 ;
     RECT  2.16 70.605 88.56 70.875 ;
     RECT  2.16 71.145 88.56 71.415 ;
     RECT  2.16 71.685 88.56 71.955 ;
     RECT  2.16 72.225 88.56 72.495 ;
     RECT  2.16 72.765 88.56 73.035 ;
     RECT  2.16 73.305 88.56 73.575 ;
     RECT  2.16 73.845 88.56 74.115 ;
     RECT  2.16 74.385 88.56 74.655 ;
     RECT  2.16 74.925 88.56 75.195 ;
     RECT  2.16 75.465 88.56 75.735 ;
     RECT  2.16 76.005 88.56 76.275 ;
     RECT  2.16 76.545 88.56 76.815 ;
     RECT  2.16 77.085 88.56 77.355 ;
     RECT  2.16 77.625 88.56 77.895 ;
     RECT  2.16 78.165 88.56 78.435 ;
     RECT  2.16 78.705 88.56 78.975 ;
     RECT  2.16 79.245 88.56 79.515 ;
     RECT  2.16 79.785 88.56 80.055 ;
     RECT  2.16 80.325 88.56 80.595 ;
     RECT  2.16 80.865 88.56 81.135 ;
     RECT  2.16 81.405 88.56 81.675 ;
     RECT  2.16 81.945 88.56 82.215 ;
     RECT  2.16 82.485 88.56 82.755 ;
     RECT  2.16 83.025 88.56 83.295 ;
     RECT  2.16 83.565 88.56 83.835 ;
     RECT  2.16 84.105 88.56 84.375 ;
     RECT  2.16 84.645 88.56 84.915 ;
     RECT  2.16 85.185 88.56 85.455 ;
     RECT  2.16 85.725 88.56 85.995 ;
     RECT  2.16 86.265 88.56 86.535 ;
     RECT  2.16 86.805 88.56 87.075 ;
     RECT  2.16 87.345 88.56 87.615 ;
     RECT  2.16 87.885 88.56 88.155 ;
     RECT  2.16 88.425 88.56 88.695 ;
     RECT  2.16 88.965 88.56 89.235 ;
     RECT  2.16 89.505 88.56 89.775 ;
     RECT  2.16 90.045 88.56 90.315 ;
     RECT  2.16 90.585 88.56 90.855 ;
     RECT  2.16 91.125 88.56 91.395 ;
     RECT  2.16 91.665 88.56 91.935 ;
     RECT  2.16 92.205 88.56 92.475 ;
     RECT  2.16 92.745 88.56 93.015 ;
     RECT  2.16 93.285 88.56 93.555 ;
     RECT  2.16 93.825 88.56 94.095 ;
     RECT  2.16 94.365 88.56 94.635 ;
     RECT  2.16 94.905 88.56 95.175 ;
     RECT  2.16 95.445 88.56 95.715 ;
     RECT  2.16 95.985 88.56 96.255 ;
     RECT  2.16 96.525 88.56 96.795 ;
     RECT  2.16 97.065 88.56 97.335 ;
     RECT  2.16 97.605 88.56 97.875 ;
     RECT  2.16 98.145 88.56 98.415 ;
     RECT  2.16 98.685 88.56 98.955 ;
     RECT  2.16 99.225 88.56 99.495 ;
     RECT  2.16 99.765 88.56 100.035 ;
     RECT  2.16 100.305 88.56 100.575 ;
     RECT  2.16 100.845 88.56 101.115 ;
     RECT  2.16 101.385 88.56 101.655 ;
     RECT  2.16 101.925 88.56 102.195 ;
     RECT  2.16 102.465 88.56 102.735 ;
     RECT  2.16 103.005 88.56 103.275 ;
     RECT  2.16 103.545 88.56 103.815 ;
     RECT  2.16 104.085 88.56 104.355 ;
     RECT  2.16 104.625 88.56 104.895 ;
     RECT  2.16 105.165 88.56 105.435 ;
     RECT  2.16 105.705 88.56 105.975 ;
     RECT  2.16 106.245 88.56 106.515 ;
     RECT  2.16 106.785 88.56 107.055 ;
     RECT  2.16 107.325 88.56 107.595 ;
     RECT  2.16 107.865 88.56 108.135 ;
     RECT  2.16 108.405 88.56 108.675 ;
     RECT  2.16 108.945 88.56 109.215 ;
     RECT  2.16 109.485 88.56 109.755 ;
     RECT  2.16 110.025 88.56 110.295 ;
     RECT  2.16 110.565 88.56 110.835 ;
     RECT  2.16 111.105 88.56 111.375 ;
     RECT  2.16 111.645 88.56 111.915 ;
     RECT  2.16 112.185 88.56 112.455 ;
     RECT  2.16 112.725 88.56 112.995 ;
     RECT  2.16 113.265 88.56 113.535 ;
     RECT  2.16 113.805 88.56 114.075 ;
     RECT  2.16 114.345 88.56 114.615 ;
     RECT  2.16 114.885 88.56 115.155 ;
     RECT  2.16 115.425 88.56 115.695 ;
     RECT  2.16 115.965 88.56 116.235 ;
     RECT  2.16 116.505 88.56 116.775 ;
     RECT  2.16 117.045 88.56 117.315 ;
     RECT  2.16 117.585 88.56 117.855 ;
     RECT  2.16 118.125 88.56 118.395 ;
     RECT  2.16 118.665 88.56 118.935 ;
     RECT  2.16 119.205 88.56 119.475 ;
     RECT  2.16 119.745 88.56 120.015 ;
     RECT  2.16 120.285 88.56 120.555 ;
     RECT  2.16 120.825 88.56 121.095 ;
     RECT  2.16 121.365 88.56 121.635 ;
     RECT  2.16 121.905 88.56 122.175 ;
     RECT  2.16 122.445 88.56 122.715 ;
     RECT  2.16 122.985 88.56 123.255 ;
     RECT  2.16 123.525 88.56 123.795 ;
     RECT  2.16 124.065 88.56 124.335 ;
     RECT  2.16 124.605 88.56 124.875 ;
     RECT  2.16 125.145 88.56 125.415 ;
     RECT  2.16 125.685 88.56 125.955 ;
     RECT  2.16 126.225 88.56 126.495 ;
     RECT  2.16 126.765 88.56 127.035 ;
     RECT  2.16 127.305 88.56 127.44 ;
    LAYER RVTP ;
     RECT  2.16 2.295 88.56 2.565 ;
     RECT  2.16 2.835 88.56 3.105 ;
     RECT  2.16 3.375 88.56 3.645 ;
     RECT  2.16 3.915 88.56 4.185 ;
     RECT  2.16 4.455 88.56 4.725 ;
     RECT  2.16 4.995 88.56 5.265 ;
     RECT  2.16 5.535 88.56 5.805 ;
     RECT  2.16 6.075 88.56 6.345 ;
     RECT  2.16 6.615 88.56 6.885 ;
     RECT  2.16 7.155 88.56 7.425 ;
     RECT  2.16 7.695 88.56 7.965 ;
     RECT  2.16 8.235 88.56 8.505 ;
     RECT  2.16 8.775 88.56 9.045 ;
     RECT  2.16 9.315 88.56 9.585 ;
     RECT  2.16 9.855 88.56 10.125 ;
     RECT  2.16 10.395 88.56 10.665 ;
     RECT  2.16 10.935 88.56 11.205 ;
     RECT  2.16 11.475 88.56 11.745 ;
     RECT  2.16 12.015 88.56 12.285 ;
     RECT  2.16 12.555 88.56 12.825 ;
     RECT  2.16 13.095 88.56 13.365 ;
     RECT  2.16 13.635 88.56 13.905 ;
     RECT  2.16 14.175 88.56 14.445 ;
     RECT  2.16 14.715 88.56 14.985 ;
     RECT  2.16 15.255 88.56 15.525 ;
     RECT  2.16 15.795 88.56 16.065 ;
     RECT  2.16 16.335 88.56 16.605 ;
     RECT  2.16 16.875 88.56 17.145 ;
     RECT  2.16 17.415 88.56 17.685 ;
     RECT  2.16 17.955 88.56 18.225 ;
     RECT  2.16 18.495 88.56 18.765 ;
     RECT  2.16 19.035 88.56 19.305 ;
     RECT  2.16 19.575 88.56 19.845 ;
     RECT  2.16 20.115 88.56 20.385 ;
     RECT  2.16 20.655 88.56 20.925 ;
     RECT  2.16 21.195 88.56 21.465 ;
     RECT  2.16 21.735 88.56 22.005 ;
     RECT  2.16 22.275 88.56 22.545 ;
     RECT  2.16 22.815 88.56 23.085 ;
     RECT  2.16 23.355 88.56 23.625 ;
     RECT  2.16 23.895 88.56 24.165 ;
     RECT  2.16 24.435 88.56 24.705 ;
     RECT  2.16 24.975 88.56 25.245 ;
     RECT  2.16 25.515 88.56 25.785 ;
     RECT  2.16 26.055 88.56 26.325 ;
     RECT  2.16 26.595 88.56 26.865 ;
     RECT  2.16 27.135 88.56 27.405 ;
     RECT  2.16 27.675 88.56 27.945 ;
     RECT  2.16 28.215 88.56 28.485 ;
     RECT  2.16 28.755 88.56 29.025 ;
     RECT  2.16 29.295 88.56 29.565 ;
     RECT  2.16 29.835 88.56 30.105 ;
     RECT  2.16 30.375 88.56 30.645 ;
     RECT  2.16 30.915 88.56 31.185 ;
     RECT  2.16 31.455 88.56 31.725 ;
     RECT  2.16 31.995 88.56 32.265 ;
     RECT  2.16 32.535 88.56 32.805 ;
     RECT  2.16 33.075 88.56 33.345 ;
     RECT  2.16 33.615 88.56 33.885 ;
     RECT  2.16 34.155 88.56 34.425 ;
     RECT  2.16 34.695 88.56 34.965 ;
     RECT  2.16 35.235 88.56 35.505 ;
     RECT  2.16 35.775 88.56 36.045 ;
     RECT  2.16 36.315 88.56 36.585 ;
     RECT  2.16 36.855 88.56 37.125 ;
     RECT  2.16 37.395 88.56 37.665 ;
     RECT  2.16 37.935 88.56 38.205 ;
     RECT  2.16 38.475 88.56 38.745 ;
     RECT  2.16 39.015 88.56 39.285 ;
     RECT  2.16 39.555 88.56 39.825 ;
     RECT  2.16 40.095 88.56 40.365 ;
     RECT  2.16 40.635 88.56 40.905 ;
     RECT  2.16 41.175 88.56 41.445 ;
     RECT  2.16 41.715 88.56 41.985 ;
     RECT  2.16 42.255 88.56 42.525 ;
     RECT  2.16 42.795 88.56 43.065 ;
     RECT  2.16 43.335 88.56 43.605 ;
     RECT  2.16 43.875 88.56 44.145 ;
     RECT  2.16 44.415 88.56 44.685 ;
     RECT  2.16 44.955 88.56 45.225 ;
     RECT  2.16 45.495 88.56 45.765 ;
     RECT  2.16 46.035 88.56 46.305 ;
     RECT  2.16 46.575 88.56 46.845 ;
     RECT  2.16 47.115 88.56 47.385 ;
     RECT  2.16 47.655 88.56 47.925 ;
     RECT  2.16 48.195 88.56 48.465 ;
     RECT  2.16 48.735 88.56 49.005 ;
     RECT  2.16 49.275 88.56 49.545 ;
     RECT  2.16 49.815 88.56 50.085 ;
     RECT  2.16 50.355 88.56 50.625 ;
     RECT  2.16 50.895 88.56 51.165 ;
     RECT  2.16 51.435 88.56 51.705 ;
     RECT  2.16 51.975 88.56 52.245 ;
     RECT  2.16 52.515 88.56 52.785 ;
     RECT  2.16 53.055 88.56 53.325 ;
     RECT  2.16 53.595 88.56 53.865 ;
     RECT  2.16 54.135 88.56 54.405 ;
     RECT  2.16 54.675 88.56 54.945 ;
     RECT  2.16 55.215 88.56 55.485 ;
     RECT  2.16 55.755 88.56 56.025 ;
     RECT  2.16 56.295 88.56 56.565 ;
     RECT  2.16 56.835 88.56 57.105 ;
     RECT  2.16 57.375 88.56 57.645 ;
     RECT  2.16 57.915 88.56 58.185 ;
     RECT  2.16 58.455 88.56 58.725 ;
     RECT  2.16 58.995 88.56 59.265 ;
     RECT  2.16 59.535 88.56 59.805 ;
     RECT  2.16 60.075 88.56 60.345 ;
     RECT  2.16 60.615 88.56 60.885 ;
     RECT  2.16 61.155 88.56 61.425 ;
     RECT  2.16 61.695 88.56 61.965 ;
     RECT  2.16 62.235 88.56 62.505 ;
     RECT  2.16 62.775 88.56 63.045 ;
     RECT  2.16 63.315 88.56 63.585 ;
     RECT  2.16 63.855 88.56 64.125 ;
     RECT  2.16 64.395 88.56 64.665 ;
     RECT  2.16 64.935 88.56 65.205 ;
     RECT  2.16 65.475 88.56 65.745 ;
     RECT  2.16 66.015 88.56 66.285 ;
     RECT  2.16 66.555 88.56 66.825 ;
     RECT  2.16 67.095 88.56 67.365 ;
     RECT  2.16 67.635 88.56 67.905 ;
     RECT  2.16 68.175 88.56 68.445 ;
     RECT  2.16 68.715 88.56 68.985 ;
     RECT  2.16 69.255 88.56 69.525 ;
     RECT  2.16 69.795 88.56 70.065 ;
     RECT  2.16 70.335 88.56 70.605 ;
     RECT  2.16 70.875 88.56 71.145 ;
     RECT  2.16 71.415 88.56 71.685 ;
     RECT  2.16 71.955 88.56 72.225 ;
     RECT  2.16 72.495 88.56 72.765 ;
     RECT  2.16 73.035 88.56 73.305 ;
     RECT  2.16 73.575 88.56 73.845 ;
     RECT  2.16 74.115 88.56 74.385 ;
     RECT  2.16 74.655 88.56 74.925 ;
     RECT  2.16 75.195 88.56 75.465 ;
     RECT  2.16 75.735 88.56 76.005 ;
     RECT  2.16 76.275 88.56 76.545 ;
     RECT  2.16 76.815 88.56 77.085 ;
     RECT  2.16 77.355 88.56 77.625 ;
     RECT  2.16 77.895 88.56 78.165 ;
     RECT  2.16 78.435 88.56 78.705 ;
     RECT  2.16 78.975 88.56 79.245 ;
     RECT  2.16 79.515 88.56 79.785 ;
     RECT  2.16 80.055 88.56 80.325 ;
     RECT  2.16 80.595 88.56 80.865 ;
     RECT  2.16 81.135 88.56 81.405 ;
     RECT  2.16 81.675 88.56 81.945 ;
     RECT  2.16 82.215 88.56 82.485 ;
     RECT  2.16 82.755 88.56 83.025 ;
     RECT  2.16 83.295 88.56 83.565 ;
     RECT  2.16 83.835 88.56 84.105 ;
     RECT  2.16 84.375 88.56 84.645 ;
     RECT  2.16 84.915 88.56 85.185 ;
     RECT  2.16 85.455 88.56 85.725 ;
     RECT  2.16 85.995 88.56 86.265 ;
     RECT  2.16 86.535 88.56 86.805 ;
     RECT  2.16 87.075 88.56 87.345 ;
     RECT  2.16 87.615 88.56 87.885 ;
     RECT  2.16 88.155 88.56 88.425 ;
     RECT  2.16 88.695 88.56 88.965 ;
     RECT  2.16 89.235 88.56 89.505 ;
     RECT  2.16 89.775 88.56 90.045 ;
     RECT  2.16 90.315 88.56 90.585 ;
     RECT  2.16 90.855 88.56 91.125 ;
     RECT  2.16 91.395 88.56 91.665 ;
     RECT  2.16 91.935 88.56 92.205 ;
     RECT  2.16 92.475 88.56 92.745 ;
     RECT  2.16 93.015 88.56 93.285 ;
     RECT  2.16 93.555 88.56 93.825 ;
     RECT  2.16 94.095 88.56 94.365 ;
     RECT  2.16 94.635 88.56 94.905 ;
     RECT  2.16 95.175 88.56 95.445 ;
     RECT  2.16 95.715 88.56 95.985 ;
     RECT  2.16 96.255 88.56 96.525 ;
     RECT  2.16 96.795 88.56 97.065 ;
     RECT  2.16 97.335 88.56 97.605 ;
     RECT  2.16 97.875 88.56 98.145 ;
     RECT  2.16 98.415 88.56 98.685 ;
     RECT  2.16 98.955 88.56 99.225 ;
     RECT  2.16 99.495 88.56 99.765 ;
     RECT  2.16 100.035 88.56 100.305 ;
     RECT  2.16 100.575 88.56 100.845 ;
     RECT  2.16 101.115 88.56 101.385 ;
     RECT  2.16 101.655 88.56 101.925 ;
     RECT  2.16 102.195 88.56 102.465 ;
     RECT  2.16 102.735 88.56 103.005 ;
     RECT  2.16 103.275 88.56 103.545 ;
     RECT  2.16 103.815 88.56 104.085 ;
     RECT  2.16 104.355 88.56 104.625 ;
     RECT  2.16 104.895 88.56 105.165 ;
     RECT  2.16 105.435 88.56 105.705 ;
     RECT  2.16 105.975 88.56 106.245 ;
     RECT  2.16 106.515 88.56 106.785 ;
     RECT  2.16 107.055 88.56 107.325 ;
     RECT  2.16 107.595 88.56 107.865 ;
     RECT  2.16 108.135 88.56 108.405 ;
     RECT  2.16 108.675 88.56 108.945 ;
     RECT  2.16 109.215 88.56 109.485 ;
     RECT  2.16 109.755 88.56 110.025 ;
     RECT  2.16 110.295 88.56 110.565 ;
     RECT  2.16 110.835 88.56 111.105 ;
     RECT  2.16 111.375 88.56 111.645 ;
     RECT  2.16 111.915 88.56 112.185 ;
     RECT  2.16 112.455 88.56 112.725 ;
     RECT  2.16 112.995 88.56 113.265 ;
     RECT  2.16 113.535 88.56 113.805 ;
     RECT  2.16 114.075 88.56 114.345 ;
     RECT  2.16 114.615 88.56 114.885 ;
     RECT  2.16 115.155 88.56 115.425 ;
     RECT  2.16 115.695 88.56 115.965 ;
     RECT  2.16 116.235 88.56 116.505 ;
     RECT  2.16 116.775 88.56 117.045 ;
     RECT  2.16 117.315 88.56 117.585 ;
     RECT  2.16 117.855 88.56 118.125 ;
     RECT  2.16 118.395 88.56 118.665 ;
     RECT  2.16 118.935 88.56 119.205 ;
     RECT  2.16 119.475 88.56 119.745 ;
     RECT  2.16 120.015 88.56 120.285 ;
     RECT  2.16 120.555 88.56 120.825 ;
     RECT  2.16 121.095 88.56 121.365 ;
     RECT  2.16 121.635 88.56 121.905 ;
     RECT  2.16 122.175 88.56 122.445 ;
     RECT  2.16 122.715 88.56 122.985 ;
     RECT  2.16 123.255 88.56 123.525 ;
     RECT  2.16 123.795 88.56 124.065 ;
     RECT  2.16 124.335 88.56 124.605 ;
     RECT  2.16 124.875 88.56 125.145 ;
     RECT  2.16 125.415 88.56 125.685 ;
     RECT  2.16 125.955 88.56 126.225 ;
     RECT  2.16 126.495 88.56 126.765 ;
     RECT  2.16 127.035 88.56 127.305 ;
    LAYER M1 ;
     RECT  2.16 2.151 88.56 127.449 ;
    LAYER M2 ;
     RECT  0.931 2.106 1.111 2.124 ;
     RECT  1.111 2.106 1.291 2.25 ;
     RECT  1.291 17.046 1.399 17.064 ;
     RECT  1.291 2.106 1.615 2.664 ;
     RECT  1.399 16.956 1.975 17.064 ;
     RECT  0.931 128.826 1.975 128.844 ;
     RECT  1.975 16.506 2.047 17.064 ;
     RECT  1.975 128.826 2.111 129.564 ;
     RECT  1.615 2.106 2.16 3.132 ;
     RECT  2.119 4.122 2.16 4.14 ;
     RECT  2.047 16.416 2.16 17.064 ;
     RECT  1.615 19.656 2.16 19.674 ;
     RECT  0.607 20.862 2.16 20.88 ;
     RECT  0.607 119.52 2.16 119.538 ;
     RECT  2.16 2.106 2.299 127.449 ;
     RECT  2.551 0.036 2.651 0.054 ;
     RECT  2.111 128.826 2.839 128.844 ;
     RECT  2.299 1.728 2.903 127.449 ;
     RECT  2.839 128.826 4.315 128.916 ;
     RECT  4.315 128.826 4.451 129.456 ;
     RECT  4.451 128.826 5.323 128.916 ;
     RECT  5.323 128.826 5.927 129.492 ;
     RECT  2.903 2.151 6.115 127.449 ;
     RECT  5.927 128.826 6.215 128.916 ;
     RECT  6.115 2.106 6.251 127.449 ;
     RECT  6.215 128.898 6.611 128.916 ;
     RECT  8.023 0.036 8.159 0.054 ;
     RECT  8.707 128.826 9.355 128.844 ;
     RECT  9.355 128.826 10.211 128.916 ;
     RECT  10.211 128.826 11.047 128.844 ;
     RECT  11.047 128.826 12.515 128.916 ;
     RECT  12.515 128.898 12.947 128.916 ;
     RECT  13.423 128.826 14.107 128.844 ;
     RECT  14.107 128.826 14.431 128.916 ;
     RECT  14.431 128.826 15.323 128.988 ;
     RECT  16.087 0.036 16.151 0.054 ;
     RECT  15.323 128.826 16.403 128.844 ;
     RECT  16.447 128.898 17.231 129.492 ;
     RECT  17.231 128.898 17.455 128.916 ;
     RECT  17.419 0.036 17.483 0.054 ;
     RECT  17.455 128.826 17.591 128.916 ;
     RECT  17.591 128.826 18.095 128.844 ;
     RECT  18.823 0.036 19.031 0.054 ;
     RECT  19.147 128.826 19.471 128.844 ;
     RECT  19.471 128.826 19.679 128.916 ;
     RECT  19.679 128.898 20.075 128.916 ;
     RECT  20.407 0.036 20.507 0.054 ;
     RECT  20.479 128.826 20.839 128.844 ;
     RECT  20.839 128.826 21.695 128.916 ;
     RECT  21.695 128.826 22.855 128.844 ;
     RECT  22.855 0.036 22.919 0.054 ;
     RECT  22.855 128.826 23.179 128.916 ;
     RECT  23.179 128.826 23.315 128.952 ;
     RECT  23.315 128.898 23.855 128.916 ;
     RECT  23.827 0.036 23.891 0.054 ;
     RECT  24.187 128.826 24.871 128.844 ;
     RECT  24.871 128.826 25.475 129.564 ;
     RECT  25.519 0.036 25.943 0.054 ;
     RECT  25.475 128.826 26.563 128.88 ;
     RECT  26.563 128.826 27.059 128.916 ;
     RECT  28.219 0.036 28.931 0.054 ;
     RECT  27.059 128.826 29.587 128.844 ;
     RECT  29.587 128.826 29.911 128.916 ;
     RECT  29.911 128.826 30.955 128.952 ;
     RECT  30.739 1.152 31.019 1.17 ;
     RECT  30.955 128.826 31.603 128.988 ;
     RECT  31.603 128.826 31.703 129.564 ;
     RECT  31.703 128.826 31.811 128.988 ;
     RECT  31.811 128.826 32.243 128.844 ;
     RECT  32.251 0.036 32.315 0.054 ;
     RECT  33.295 129.546 33.431 129.564 ;
     RECT  35.635 0.036 35.699 0.054 ;
     RECT  39.955 0.036 40.415 0.054 ;
     RECT  43.699 0.036 43.763 0.054 ;
     RECT  48.451 0.036 48.551 0.054 ;
     RECT  49.711 0.036 49.847 0.054 ;
     RECT  53.095 0.18 53.267 0.198 ;
     RECT  54.787 0.036 55.607 0.054 ;
     RECT  59.935 0.036 60.611 0.054 ;
     RECT  62.563 0.036 63.311 0.054 ;
     RECT  64.939 0.036 65.399 0.054 ;
     RECT  6.251 2.151 67.315 127.449 ;
     RECT  67.315 2.151 67.451 127.53 ;
     RECT  66.991 0.036 68.027 0.054 ;
     RECT  70.591 0.036 71.411 0.054 ;
     RECT  67.451 2.151 72.571 127.449 ;
     RECT  72.571 2.151 72.743 127.53 ;
     RECT  72.535 0.036 73.751 0.054 ;
     RECT  75.703 0.036 76.883 0.054 ;
     RECT  77.791 0.036 77.963 0.054 ;
     RECT  72.743 2.151 78.115 127.449 ;
     RECT  77.971 0.108 78.143 0.126 ;
     RECT  78.115 2.151 78.647 127.53 ;
     RECT  79.123 0.036 79.475 0.054 ;
     RECT  81.103 0.036 81.247 0.054 ;
     RECT  81.247 0.036 81.851 0.126 ;
     RECT  81.851 0.036 82.175 0.054 ;
     RECT  78.647 2.151 82.651 127.449 ;
     RECT  82.651 2.151 83.371 127.566 ;
     RECT  83.371 0.036 83.543 0.054 ;
     RECT  83.371 2.151 84.695 127.602 ;
     RECT  84.307 0.036 85.891 0.054 ;
     RECT  85.891 0.036 85.991 0.126 ;
     RECT  84.695 2.151 86.099 127.566 ;
     RECT  85.991 0.108 86.243 0.126 ;
     RECT  86.099 2.151 88.56 127.449 ;
     RECT  88.56 16.11 88.907 19.764 ;
     RECT  88.56 23.292 88.907 23.31 ;
     RECT  88.56 38.016 88.907 38.16 ;
     RECT  88.56 75.474 88.907 83.124 ;
     RECT  88.56 90.666 88.907 94.626 ;
     RECT  88.56 102.366 88.907 112.284 ;
     RECT  88.56 113.04 88.907 124.794 ;
     RECT  88.907 16.686 88.943 19.764 ;
     RECT  88.56 20.736 88.943 22.338 ;
     RECT  88.56 24.516 88.943 27.774 ;
     RECT  88.56 30.114 88.943 30.132 ;
     RECT  88.56 31.536 88.943 32.49 ;
     RECT  88.56 33.426 88.943 37.224 ;
     RECT  88.56 38.916 88.943 48.69 ;
     RECT  88.56 49.716 88.943 53.964 ;
     RECT  88.56 58.806 88.943 67.392 ;
     RECT  88.56 69.876 88.943 69.894 ;
     RECT  88.56 70.686 88.943 73.26 ;
     RECT  88.907 75.816 88.943 83.124 ;
     RECT  88.907 90.666 88.943 90.684 ;
     RECT  88.907 91.476 88.943 94.626 ;
     RECT  88.907 102.366 88.943 103.266 ;
     RECT  88.907 104.256 88.943 112.284 ;
     RECT  88.907 113.04 88.943 119.664 ;
     RECT  88.943 17.622 88.979 19.764 ;
     RECT  88.943 31.806 88.979 32.49 ;
     RECT  88.943 59.076 88.979 67.392 ;
     RECT  88.56 95.796 88.979 101.304 ;
     RECT  88.943 114.894 89.411 117.342 ;
     RECT  88.56 13.068 89.483 14.094 ;
     RECT  88.943 25.254 89.483 27.774 ;
     RECT  88.943 38.916 89.483 39.744 ;
     RECT  88.943 45.036 89.483 48.69 ;
     RECT  88.979 95.796 89.483 101.07 ;
     RECT  88.943 104.256 89.483 112.176 ;
     RECT  88.943 113.04 89.483 113.994 ;
     RECT  88.56 11.916 89.519 12.114 ;
     RECT  89.483 13.446 89.519 14.094 ;
     RECT  88.943 20.736 89.519 21.186 ;
     RECT  88.943 21.942 89.519 22.338 ;
     RECT  88.943 33.696 89.519 37.224 ;
     RECT  89.483 39.258 89.519 39.744 ;
     RECT  89.483 45.036 89.519 45.324 ;
     RECT  89.483 46.278 89.519 48.69 ;
     RECT  88.943 49.716 89.519 50.652 ;
     RECT  88.943 51.876 89.519 53.964 ;
     RECT  88.56 57.546 89.519 57.564 ;
     RECT  88.979 59.076 89.519 63.414 ;
     RECT  88.979 64.44 89.519 67.392 ;
     RECT  88.943 71.154 89.519 73.26 ;
     RECT  88.943 76.212 89.519 80.424 ;
     RECT  88.56 84.726 89.519 86.868 ;
     RECT  88.56 88.236 89.519 88.794 ;
     RECT  88.943 91.944 89.519 93.384 ;
     RECT  88.943 94.176 89.519 94.626 ;
     RECT  89.483 98.46 89.519 101.07 ;
     RECT  89.483 108.18 89.519 109.206 ;
     RECT  89.483 110.466 89.519 112.176 ;
     RECT  88.907 120.636 89.519 124.794 ;
     RECT  88.979 17.622 89.555 18.864 ;
     RECT  89.519 35.586 89.555 36.684 ;
     RECT  89.519 60.156 89.555 60.174 ;
     RECT  89.519 72.576 89.555 73.26 ;
     RECT  89.519 91.944 89.555 92.034 ;
     RECT  88.943 118.476 89.771 119.664 ;
     RECT  88.56 125.856 89.807 127.404 ;
     RECT  89.519 120.636 89.843 121.86 ;
     RECT  89.519 122.922 90.023 124.794 ;
     RECT  89.555 17.622 90.059 18.054 ;
     RECT  89.519 21.942 90.059 21.96 ;
     RECT  89.483 25.758 90.059 27.774 ;
     RECT  88.943 41.148 90.059 43.866 ;
     RECT  89.519 46.278 90.059 48.024 ;
     RECT  89.519 61.326 90.059 61.992 ;
     RECT  89.519 66.294 90.059 67.392 ;
     RECT  89.519 71.154 90.059 71.514 ;
     RECT  88.943 81.216 90.059 83.124 ;
     RECT  89.555 91.944 90.059 91.962 ;
     RECT  89.519 94.608 90.059 94.626 ;
     RECT  89.519 98.766 90.059 100.494 ;
     RECT  89.483 104.256 90.059 107.424 ;
     RECT  89.519 108.18 90.059 109.134 ;
     RECT  89.519 110.466 90.059 112.104 ;
     RECT  89.483 113.238 90.059 113.994 ;
     RECT  89.411 114.966 90.059 117.342 ;
     RECT  89.771 118.746 90.059 119.664 ;
     RECT  90.023 123.156 90.059 124.794 ;
     RECT  89.807 126.306 90.059 127.404 ;
     RECT  88.56 2.376 90.095 2.394 ;
     RECT  88.56 4.266 90.095 6.174 ;
     RECT  88.56 6.966 90.095 7.524 ;
     RECT  88.56 8.316 90.095 9.774 ;
     RECT  88.56 10.872 90.095 10.89 ;
     RECT  89.519 12.096 90.095 12.114 ;
     RECT  89.519 14.076 90.095 14.094 ;
     RECT  90.059 18.036 90.095 18.054 ;
     RECT  89.555 18.846 90.095 18.864 ;
     RECT  88.979 19.746 90.095 19.764 ;
     RECT  90.059 26.334 90.095 27.774 ;
     RECT  88.979 32.472 90.095 32.49 ;
     RECT  89.519 33.696 90.095 34.794 ;
     RECT  89.555 35.586 90.095 35.604 ;
     RECT  89.555 36.666 90.095 36.684 ;
     RECT  90.059 41.796 90.095 43.866 ;
     RECT  90.059 46.926 90.095 48.024 ;
     RECT  89.519 50.166 90.095 50.184 ;
     RECT  89.519 52.056 90.095 53.964 ;
     RECT  88.56 55.188 90.095 55.206 ;
     RECT  89.519 59.076 90.095 59.094 ;
     RECT  90.059 61.326 90.095 61.956 ;
     RECT  89.519 63.126 90.095 63.144 ;
     RECT  90.059 66.906 90.095 67.392 ;
     RECT  90.059 71.496 90.095 71.514 ;
     RECT  89.555 73.242 90.095 73.26 ;
     RECT  88.56 74.466 90.095 74.484 ;
     RECT  89.519 77.634 90.095 80.424 ;
     RECT  90.059 81.216 90.095 81.234 ;
     RECT  90.059 82.188 90.095 83.124 ;
     RECT  88.56 83.916 90.095 83.934 ;
     RECT  89.519 84.996 90.095 86.868 ;
     RECT  89.519 88.776 90.095 88.794 ;
     RECT  89.519 93.096 90.095 93.114 ;
     RECT  89.483 95.796 90.095 96.552 ;
     RECT  90.059 99.666 90.095 100.296 ;
     RECT  88.943 102.78 90.095 103.266 ;
     RECT  90.059 105.336 90.095 105.894 ;
     RECT  90.059 107.1 90.095 107.118 ;
     RECT  90.059 110.466 90.095 111.474 ;
     RECT  90.059 113.616 90.095 113.994 ;
     RECT  90.095 4.806 90.131 5.526 ;
     RECT  90.095 79.866 90.131 79.884 ;
     RECT  90.095 96.066 90.131 96.552 ;
     RECT  90.059 117.324 90.599 117.342 ;
     RECT  90.059 126.432 90.599 127.404 ;
     RECT  88.56 3.186 90.635 3.204 ;
     RECT  90.131 4.806 90.635 4.986 ;
     RECT  90.095 8.478 90.635 8.496 ;
     RECT  90.095 9.756 90.635 9.774 ;
     RECT  90.095 26.334 90.635 26.352 ;
     RECT  90.095 34.668 90.635 34.686 ;
     RECT  88.907 38.016 90.635 38.034 ;
     RECT  90.095 42.336 90.635 42.354 ;
     RECT  90.095 61.938 90.635 61.956 ;
     RECT  89.519 64.44 90.635 64.458 ;
     RECT  89.519 65.214 90.635 65.232 ;
     RECT  90.095 77.634 90.635 77.652 ;
     RECT  90.095 82.188 90.635 82.206 ;
     RECT  90.095 86.85 90.635 86.868 ;
     RECT  90.131 96.534 90.635 96.552 ;
     RECT  90.095 99.738 90.635 100.296 ;
     RECT  90.095 102.78 90.635 102.798 ;
     RECT  90.059 104.256 90.635 104.274 ;
     RECT  90.059 108.846 90.635 108.864 ;
     RECT  90.095 110.466 90.635 110.754 ;
     RECT  89.843 120.798 90.635 121.86 ;
     RECT  90.059 124.686 90.635 124.704 ;
     RECT  90.599 126.432 90.635 126.99 ;
     RECT  90.095 113.616 90.707 113.634 ;
     RECT  90.635 120.798 90.707 120.816 ;
    LAYER M3 ;
     RECT  89.1 0.012 89.118 0.269 ;
     RECT  0.612 0.012 87.246 2.155 ;
     RECT  90.072 2.371 90.09 2.477 ;
     RECT  0.612 2.155 87.282 2.669 ;
     RECT  1.62 2.669 87.282 3.137 ;
     RECT  90.612 2.923 90.63 3.209 ;
     RECT  90.54 3.451 90.558 3.677 ;
     RECT  2.304 3.137 87.282 3.979 ;
     RECT  2.124 3.979 87.282 4.145 ;
     RECT  90.072 4.261 90.09 4.493 ;
     RECT  2.268 4.145 87.282 4.685 ;
     RECT  90.612 4.699 90.63 4.991 ;
     RECT  90.072 5.341 90.126 5.947 ;
     RECT  90.072 5.947 90.63 6.077 ;
     RECT  2.304 4.685 87.282 6.809 ;
     RECT  9.972 6.809 87.282 7.949 ;
     RECT  90.072 6.077 90.09 8.251 ;
     RECT  90.072 8.251 90.63 8.501 ;
     RECT  9.972 7.949 11.97 9.121 ;
     RECT  9.972 9.121 12.078 9.211 ;
     RECT  9.972 9.211 12.15 9.248 ;
     RECT  9.972 9.248 11.934 9.275 ;
     RECT  12.888 7.949 87.282 9.391 ;
     RECT  90.072 8.501 90.09 9.533 ;
     RECT  90.612 9.739 90.63 9.779 ;
     RECT  2.304 6.809 9.126 9.787 ;
     RECT  9.972 9.275 11.826 9.787 ;
     RECT  12.852 9.391 87.282 9.787 ;
     RECT  88.416 0.667 88.434 9.787 ;
     RECT  2.304 9.787 11.826 10.193 ;
     RECT  12.852 9.787 88.434 10.201 ;
     RECT  12.78 10.201 88.434 10.267 ;
     RECT  2.304 10.193 11.718 10.319 ;
     RECT  12.636 10.267 88.434 10.471 ;
     RECT  12.456 10.471 88.434 10.859 ;
     RECT  90.072 10.867 90.09 11.069 ;
     RECT  12.528 10.859 88.434 11.309 ;
     RECT  88.344 11.309 88.434 11.549 ;
     RECT  2.304 10.319 11.646 11.821 ;
     RECT  89.496 11.911 89.514 12.077 ;
     RECT  90.072 12.091 90.09 12.317 ;
     RECT  2.304 11.821 11.754 12.523 ;
     RECT  12.528 11.309 87.282 12.523 ;
     RECT  88.416 11.549 88.434 12.523 ;
     RECT  88.344 12.523 88.434 12.845 ;
     RECT  89.46 13.051 89.478 13.441 ;
     RECT  89.46 13.441 89.514 13.937 ;
     RECT  90.072 14.071 90.09 14.333 ;
     RECT  2.304 12.523 87.282 14.521 ;
     RECT  88.416 12.845 88.434 14.521 ;
     RECT  2.304 14.521 88.434 14.621 ;
     RECT  88.308 14.621 88.434 16.075 ;
     RECT  88.308 16.075 88.902 16.169 ;
     RECT  2.304 14.621 87.282 16.411 ;
     RECT  2.052 16.411 87.282 16.501 ;
     RECT  88.416 16.169 88.902 16.681 ;
     RECT  1.98 16.501 87.282 16.951 ;
     RECT  88.416 16.681 88.938 16.951 ;
     RECT  0.612 2.669 0.63 17.041 ;
     RECT  1.404 16.951 87.282 17.041 ;
     RECT  88.344 16.951 88.938 17.117 ;
     RECT  88.416 17.117 88.938 17.885 ;
     RECT  90.036 17.608 90.054 18.031 ;
     RECT  88.416 17.885 88.434 18.265 ;
     RECT  90.036 18.031 90.09 18.301 ;
     RECT  88.344 18.265 88.434 18.413 ;
     RECT  89.496 18.301 90.09 18.893 ;
     RECT  88.416 18.413 88.434 19.309 ;
     RECT  88.416 19.309 88.974 19.661 ;
     RECT  90.072 18.893 90.09 19.901 ;
     RECT  88.416 19.661 88.434 20.083 ;
     RECT  88.344 20.083 88.434 20.669 ;
     RECT  0.612 17.041 87.282 20.885 ;
     RECT  89.496 20.731 89.514 21.197 ;
     RECT  88.416 20.669 88.434 21.271 ;
     RECT  88.416 21.271 88.938 21.437 ;
     RECT  90.036 21.883 90.054 21.965 ;
     RECT  1.296 20.885 87.282 22.081 ;
     RECT  89.496 22.315 89.514 22.445 ;
     RECT  1.296 22.081 87.318 22.685 ;
     RECT  88.416 21.437 88.434 23.179 ;
     RECT  88.416 23.179 88.902 23.315 ;
     RECT  1.296 22.685 87.282 23.431 ;
     RECT  88.416 23.315 88.434 23.431 ;
     RECT  1.296 23.431 88.434 24.461 ;
     RECT  88.344 24.461 88.434 24.511 ;
     RECT  88.344 24.511 88.938 24.701 ;
     RECT  89.46 25.195 89.478 25.277 ;
     RECT  88.344 24.701 88.434 25.469 ;
     RECT  89.496 25.675 90.054 25.781 ;
     RECT  89.496 25.781 89.514 25.997 ;
     RECT  88.416 25.469 88.434 26.257 ;
     RECT  90.612 26.203 90.63 26.357 ;
     RECT  88.416 26.257 88.938 27.485 ;
     RECT  90.072 27.031 90.09 28.013 ;
     RECT  88.416 27.485 88.434 30.109 ;
     RECT  1.296 24.461 87.282 30.221 ;
     RECT  88.416 30.109 88.938 30.269 ;
     RECT  21.168 30.221 87.282 30.451 ;
     RECT  21.168 30.451 87.318 30.649 ;
     RECT  88.416 30.269 88.434 30.649 ;
     RECT  90.612 30.763 90.63 30.893 ;
     RECT  1.296 30.221 20.358 30.991 ;
     RECT  21.168 30.649 88.434 30.991 ;
     RECT  1.296 30.991 88.434 31.037 ;
     RECT  88.416 31.037 88.434 31.531 ;
     RECT  88.416 31.531 88.938 31.801 ;
     RECT  88.416 31.801 88.974 32.045 ;
     RECT  1.296 31.037 87.318 32.071 ;
     RECT  88.416 32.045 88.434 32.071 ;
     RECT  1.296 32.071 88.434 32.285 ;
     RECT  90.072 32.467 90.09 32.573 ;
     RECT  88.344 32.285 88.434 33.341 ;
     RECT  88.416 33.341 88.434 33.421 ;
     RECT  88.416 33.421 88.938 33.581 ;
     RECT  90.072 33.691 90.09 34.231 ;
     RECT  89.496 34.231 90.09 34.349 ;
     RECT  90.072 34.349 90.09 34.555 ;
     RECT  90.072 34.555 90.63 34.691 ;
     RECT  1.296 32.285 87.282 34.699 ;
     RECT  88.416 33.581 88.434 34.699 ;
     RECT  1.296 34.699 88.434 34.829 ;
     RECT  88.344 34.829 88.434 35.357 ;
     RECT  90.072 34.691 90.09 35.509 ;
     RECT  89.496 35.509 90.09 35.837 ;
     RECT  89.496 35.837 89.55 36.125 ;
     RECT  89.532 36.125 89.55 36.365 ;
     RECT  1.296 34.829 87.282 36.571 ;
     RECT  88.416 35.357 88.434 36.571 ;
     RECT  1.296 36.571 88.434 36.617 ;
     RECT  90.072 36.661 90.09 36.845 ;
     RECT  88.416 36.617 88.434 36.931 ;
     RECT  88.416 36.931 88.938 37.133 ;
     RECT  89.496 37.201 89.514 37.373 ;
     RECT  1.296 36.617 87.282 37.471 ;
     RECT  88.416 37.133 88.434 37.471 ;
     RECT  90.612 37.819 90.63 38.039 ;
     RECT  1.296 37.471 88.434 38.107 ;
     RECT  1.296 38.107 88.902 38.165 ;
     RECT  1.296 38.165 88.434 38.381 ;
     RECT  1.296 38.381 87.318 38.621 ;
     RECT  89.46 38.875 89.478 38.939 ;
     RECT  89.496 39.253 89.514 39.917 ;
     RECT  88.344 38.381 88.434 40.157 ;
     RECT  88.416 40.157 88.434 40.171 ;
     RECT  1.296 38.621 87.282 40.667 ;
     RECT  88.416 40.171 88.938 40.925 ;
     RECT  28.332 40.667 87.282 40.973 ;
     RECT  90.036 41.131 90.054 41.251 ;
     RECT  89.496 41.251 90.054 41.405 ;
     RECT  90.036 41.405 90.054 41.711 ;
     RECT  1.296 40.667 27.522 41.791 ;
     RECT  28.404 40.973 87.282 42.061 ;
     RECT  88.416 40.925 88.434 42.061 ;
     RECT  90.072 41.791 90.09 42.139 ;
     RECT  90.072 42.139 90.63 42.359 ;
     RECT  88.344 42.061 88.434 42.413 ;
     RECT  90.072 42.359 90.09 42.601 ;
     RECT  28.332 42.061 87.282 43.411 ;
     RECT  89.496 42.601 90.09 43.421 ;
     RECT  88.416 42.413 88.434 43.501 ;
     RECT  88.416 43.501 88.938 43.709 ;
     RECT  90.072 43.421 90.09 43.949 ;
     RECT  88.416 43.709 88.434 44.113 ;
     RECT  88.344 44.113 88.434 44.491 ;
     RECT  88.344 44.491 88.938 44.717 ;
     RECT  88.344 44.717 88.434 44.957 ;
     RECT  89.496 45.031 89.514 45.691 ;
     RECT  88.416 44.957 88.434 45.841 ;
     RECT  89.46 45.691 89.514 45.841 ;
     RECT  88.416 45.841 89.514 45.965 ;
     RECT  89.496 45.965 89.514 46.171 ;
     RECT  89.496 46.171 90.054 46.921 ;
     RECT  28.332 43.411 87.318 48.263 ;
     RECT  89.496 46.921 90.09 48.269 ;
     RECT  33.444 48.263 87.318 48.425 ;
     RECT  89.496 48.269 89.514 48.749 ;
     RECT  88.416 45.965 88.434 48.811 ;
     RECT  28.332 48.263 32.706 49.351 ;
     RECT  33.48 48.425 87.318 49.351 ;
     RECT  89.496 49.711 89.514 49.757 ;
     RECT  88.344 48.811 88.434 49.997 ;
     RECT  90.072 50.161 90.09 50.285 ;
     RECT  88.416 49.997 88.434 50.431 ;
     RECT  88.416 50.431 88.938 50.629 ;
     RECT  88.416 50.629 89.514 50.765 ;
     RECT  88.416 50.765 88.938 50.863 ;
     RECT  88.344 50.863 88.938 51.053 ;
     RECT  88.416 51.053 88.938 51.773 ;
     RECT  89.496 51.871 89.514 52.051 ;
     RECT  89.496 52.051 90.09 52.061 ;
     RECT  28.332 49.351 87.318 53.123 ;
     RECT  28.332 53.123 35.694 53.869 ;
     RECT  36.432 53.123 87.318 53.869 ;
     RECT  28.332 53.869 87.318 53.933 ;
     RECT  90.072 52.061 90.09 54.077 ;
     RECT  28.332 53.933 36.018 55.021 ;
     RECT  36.9 53.933 87.318 55.021 ;
     RECT  90.072 55.183 90.09 55.325 ;
     RECT  28.332 55.021 87.318 56.731 ;
     RECT  88.416 51.773 88.434 56.731 ;
     RECT  28.332 56.731 88.434 56.861 ;
     RECT  88.308 56.861 88.434 57.029 ;
     RECT  88.308 57.029 88.326 57.137 ;
     RECT  89.496 57.541 89.514 57.629 ;
     RECT  28.332 56.861 87.318 57.713 ;
     RECT  39.528 57.713 87.318 57.721 ;
     RECT  39.528 57.721 87.822 57.991 ;
     RECT  39.528 57.991 88.362 58.349 ;
     RECT  28.332 57.713 38.718 58.531 ;
     RECT  88.344 58.349 88.362 58.637 ;
     RECT  88.92 58.801 88.938 58.843 ;
     RECT  28.332 58.531 38.754 59.071 ;
     RECT  39.528 58.349 87.318 59.071 ;
     RECT  88.92 58.843 89.478 59.071 ;
     RECT  88.92 59.071 90.09 59.357 ;
     RECT  88.92 59.357 89.514 59.885 ;
     RECT  89.496 59.885 89.514 60.151 ;
     RECT  28.332 59.071 87.318 60.413 ;
     RECT  89.496 60.151 89.55 60.413 ;
     RECT  89.496 60.413 89.514 61.133 ;
     RECT  28.332 60.413 40.497 61.231 ;
     RECT  41.256 60.413 87.318 61.231 ;
     RECT  90.036 61.321 90.09 61.867 ;
     RECT  90.036 61.867 90.63 61.961 ;
     RECT  28.332 61.231 87.318 61.997 ;
     RECT  90.036 61.961 90.054 61.997 ;
     RECT  88.884 62.107 88.902 62.231 ;
     RECT  88.92 62.311 89.514 62.669 ;
     RECT  42.516 61.997 87.318 62.735 ;
     RECT  28.332 61.997 41.598 62.851 ;
     RECT  28.332 62.851 41.742 63.121 ;
     RECT  90.072 63.121 90.09 63.197 ;
     RECT  88.92 62.669 88.938 63.391 ;
     RECT  28.332 63.121 41.958 63.589 ;
     RECT  42.876 62.735 87.318 63.589 ;
     RECT  88.92 63.391 89.514 63.677 ;
     RECT  28.332 63.589 87.318 64.085 ;
     RECT  88.92 63.677 88.974 64.205 ;
     RECT  43.596 64.085 87.318 64.895 ;
     RECT  44.352 64.895 87.318 64.931 ;
     RECT  28.332 64.085 42.714 64.939 ;
     RECT  43.596 64.895 43.614 64.939 ;
     RECT  88.92 64.205 88.938 65.011 ;
     RECT  90.612 64.411 90.63 65.237 ;
     RECT  88.92 65.011 89.514 65.693 ;
     RECT  28.332 64.939 43.614 65.785 ;
     RECT  44.388 64.931 87.318 65.785 ;
     RECT  89.496 65.693 89.514 66.187 ;
     RECT  89.496 66.187 90.054 66.701 ;
     RECT  90.072 66.901 90.09 67.709 ;
     RECT  28.332 65.785 87.318 69.421 ;
     RECT  88.344 68.521 88.362 69.421 ;
     RECT  28.332 69.421 88.362 69.871 ;
     RECT  28.332 69.871 88.938 70.253 ;
     RECT  88.344 70.253 88.938 70.493 ;
     RECT  88.92 70.493 88.938 71.261 ;
     RECT  90.036 70.747 90.054 71.383 ;
     RECT  89.496 71.383 90.054 71.491 ;
     RECT  89.496 71.491 90.09 71.789 ;
     RECT  28.332 70.253 87.318 71.951 ;
     RECT  89.496 71.789 89.514 72.556 ;
     RECT  89.496 72.556 89.55 72.557 ;
     RECT  28.332 71.951 48.222 72.769 ;
     RECT  48.996 71.951 87.318 72.769 ;
     RECT  89.532 72.557 89.55 72.797 ;
     RECT  90.072 73.237 90.09 73.277 ;
     RECT  28.332 72.769 87.318 73.381 ;
     RECT  28.332 73.381 87.822 73.565 ;
     RECT  28.332 73.565 87.354 74.285 ;
     RECT  90.072 74.461 90.09 74.573 ;
     RECT  28.332 74.285 87.318 74.615 ;
     RECT  50.472 74.615 87.318 74.885 ;
     RECT  88.308 74.779 88.326 75.029 ;
     RECT  88.884 75.259 88.902 75.497 ;
     RECT  50.616 74.885 87.318 75.505 ;
     RECT  28.332 74.615 49.662 75.541 ;
     RECT  28.332 75.541 49.842 75.811 ;
     RECT  50.616 75.505 87.822 75.811 ;
     RECT  28.332 75.811 87.822 75.821 ;
     RECT  88.92 75.811 88.938 76.061 ;
     RECT  88.344 76.549 88.362 76.589 ;
     RECT  89.496 76.207 89.514 77.035 ;
     RECT  89.46 77.035 89.514 77.081 ;
     RECT  90.612 77.563 90.63 77.657 ;
     RECT  89.496 77.081 89.514 77.837 ;
     RECT  88.92 78.511 88.938 78.845 ;
     RECT  90.072 77.971 90.09 79.051 ;
     RECT  89.496 79.051 90.09 79.373 ;
     RECT  90.072 79.373 90.09 79.852 ;
     RECT  90.072 79.852 90.126 80.141 ;
     RECT  88.92 80.293 88.938 80.861 ;
     RECT  90.072 80.141 90.09 81.115 ;
     RECT  89.46 81.115 90.09 81.389 ;
     RECT  89.46 81.389 90.054 81.437 ;
     RECT  90.036 81.437 90.054 81.671 ;
     RECT  88.344 81.751 88.362 81.917 ;
     RECT  90.612 82.123 90.63 82.211 ;
     RECT  89.496 82.291 89.514 82.397 ;
     RECT  28.332 75.821 87.318 83.131 ;
     RECT  88.344 82.831 88.362 83.131 ;
     RECT  28.332 83.131 88.362 83.633 ;
     RECT  88.344 83.633 88.362 83.645 ;
     RECT  90.072 82.489 90.09 84.173 ;
     RECT  89.496 84.721 89.514 84.941 ;
     RECT  90.072 84.991 90.09 86.683 ;
     RECT  90.072 86.683 90.63 86.873 ;
     RECT  90.072 86.873 90.09 86.957 ;
     RECT  89.496 88.231 89.514 88.493 ;
     RECT  90.072 88.771 90.09 88.973 ;
     RECT  28.332 83.633 87.318 89.167 ;
     RECT  28.332 89.167 87.822 89.213 ;
     RECT  88.344 90.187 88.362 90.239 ;
     RECT  28.332 89.213 87.318 90.319 ;
     RECT  88.884 90.661 88.938 90.815 ;
     RECT  88.92 90.815 88.938 91.757 ;
     RECT  90.036 91.243 90.054 91.963 ;
     RECT  89.46 91.963 90.054 91.967 ;
     RECT  89.46 91.967 89.55 92.003 ;
     RECT  89.532 92.003 89.55 92.285 ;
     RECT  28.332 90.319 87.822 92.551 ;
     RECT  28.332 92.551 87.858 92.765 ;
     RECT  89.496 92.749 89.514 93.091 ;
     RECT  89.496 93.091 90.09 93.293 ;
     RECT  28.332 92.765 87.318 93.631 ;
     RECT  28.332 93.631 87.822 93.773 ;
     RECT  89.496 93.293 89.514 94.021 ;
     RECT  88.92 94.021 89.514 94.061 ;
     RECT  89.496 94.061 89.514 94.507 ;
     RECT  89.496 94.507 90.054 94.631 ;
     RECT  89.496 94.631 89.514 94.781 ;
     RECT  28.332 93.773 87.318 95.071 ;
     RECT  88.344 95.251 88.362 95.549 ;
     RECT  28.332 95.071 87.354 95.683 ;
     RECT  28.332 95.683 87.822 95.789 ;
     RECT  90.072 95.791 90.09 96.061 ;
     RECT  90.072 96.061 90.126 96.077 ;
     RECT  90.108 96.077 90.126 96.317 ;
     RECT  90.612 96.52 90.63 96.557 ;
     RECT  88.92 96.601 88.938 96.845 ;
     RECT  89.46 97.051 89.478 98.059 ;
     RECT  89.388 98.059 89.478 98.177 ;
     RECT  89.46 98.177 89.478 98.333 ;
     RECT  89.496 98.455 89.514 98.761 ;
     RECT  89.496 98.761 90.054 99.307 ;
     RECT  89.352 99.307 90.054 99.563 ;
     RECT  89.46 99.563 90.054 99.661 ;
     RECT  89.46 99.661 90.09 99.733 ;
     RECT  89.46 99.733 90.63 100.112 ;
     RECT  90.036 100.112 90.63 100.637 ;
     RECT  88.92 100.543 88.938 101.047 ;
     RECT  90.036 100.637 90.09 101.047 ;
     RECT  88.92 101.047 90.09 101.117 ;
     RECT  88.92 101.117 88.974 101.357 ;
     RECT  88.956 101.357 88.974 101.645 ;
     RECT  90.072 101.117 90.09 102.125 ;
     RECT  88.92 102.331 88.938 102.389 ;
     RECT  90.612 102.619 90.63 102.803 ;
     RECT  28.332 95.789 87.318 102.811 ;
     RECT  28.332 102.811 87.822 103.133 ;
     RECT  90.072 103.243 90.09 103.421 ;
     RECT  88.884 103.621 88.902 104.009 ;
     RECT  90.612 104.107 90.63 104.279 ;
     RECT  28.332 103.133 87.318 104.701 ;
     RECT  28.332 104.701 88.038 104.855 ;
     RECT  89.46 104.395 89.478 104.863 ;
     RECT  89.46 104.863 90.054 105.331 ;
     RECT  89.46 105.331 90.09 105.917 ;
     RECT  89.496 105.917 90.09 106.205 ;
     RECT  28.332 104.855 87.318 106.439 ;
     RECT  89.496 106.205 90.054 106.861 ;
     RECT  89.46 106.861 90.054 107.095 ;
     RECT  89.46 107.095 90.09 107.213 ;
     RECT  89.46 107.213 90.054 107.453 ;
     RECT  28.332 106.439 67.95 107.755 ;
     RECT  68.688 106.439 87.318 107.755 ;
     RECT  89.46 107.453 89.478 107.933 ;
     RECT  28.332 107.755 87.318 107.941 ;
     RECT  28.332 107.941 87.498 108.139 ;
     RECT  28.332 108.139 87.822 108.751 ;
     RECT  90.036 108.175 90.054 108.841 ;
     RECT  90.036 108.841 90.63 108.941 ;
     RECT  90.036 108.941 90.054 109.139 ;
     RECT  28.332 108.751 89.082 109.183 ;
     RECT  28.332 109.183 89.514 109.229 ;
     RECT  89.46 109.229 89.514 109.709 ;
     RECT  89.46 109.709 89.478 109.949 ;
     RECT  28.332 109.229 88.434 110.203 ;
     RECT  90.612 109.963 90.63 110.759 ;
     RECT  28.332 110.203 88.938 111.001 ;
     RECT  28.332 111.001 89.514 111.137 ;
     RECT  28.332 111.137 88.434 111.245 ;
     RECT  89.496 111.137 89.514 111.451 ;
     RECT  28.332 111.245 87.822 111.569 ;
     RECT  87.408 111.569 87.822 111.713 ;
     RECT  87.48 111.713 87.822 112.081 ;
     RECT  87.48 112.081 88.29 112.145 ;
     RECT  88.272 112.145 88.29 112.181 ;
     RECT  87.48 112.145 87.498 112.217 ;
     RECT  89.496 111.451 90.09 112.253 ;
     RECT  89.496 112.253 89.514 112.261 ;
     RECT  28.332 111.569 86.598 112.387 ;
     RECT  88.92 112.261 89.514 112.493 ;
     RECT  28.332 112.387 86.706 112.657 ;
     RECT  28.332 112.657 87.066 113.071 ;
     RECT  89.46 112.493 89.514 113.224 ;
     RECT  28.332 113.071 87.678 113.539 ;
     RECT  89.46 113.224 90.054 113.611 ;
     RECT  28.332 113.539 87.93 113.639 ;
     RECT  28.332 113.639 87.03 113.729 ;
     RECT  87.768 113.639 87.93 113.881 ;
     RECT  28.332 113.729 86.814 113.885 ;
     RECT  89.46 113.611 90.702 114.029 ;
     RECT  87.768 113.881 88.146 114.035 ;
     RECT  28.332 113.885 86.598 114.341 ;
     RECT  87.912 114.035 88.146 114.377 ;
     RECT  88.452 114.385 88.47 114.421 ;
     RECT  88.452 114.421 88.938 114.509 ;
     RECT  90.072 114.029 90.702 114.763 ;
     RECT  89.388 114.763 90.702 114.917 ;
     RECT  28.332 114.341 86.49 115.079 ;
     RECT  87.264 115.231 87.282 115.421 ;
     RECT  88.452 114.509 88.47 115.501 ;
     RECT  90.036 114.917 90.702 115.663 ;
     RECT  89.496 115.663 90.702 116.005 ;
     RECT  28.332 115.079 86.418 116.041 ;
     RECT  28.332 116.041 86.634 116.069 ;
     RECT  89.46 116.005 90.702 116.167 ;
     RECT  89.424 116.167 90.702 116.699 ;
     RECT  89.424 116.699 89.478 116.843 ;
     RECT  88.02 115.501 88.47 117.049 ;
     RECT  89.424 116.843 89.442 117.053 ;
     RECT  71.316 116.069 86.634 117.121 ;
     RECT  71.316 117.121 86.778 117.247 ;
     RECT  71.316 117.247 87.03 117.391 ;
     RECT  87.876 117.049 88.47 117.391 ;
     RECT  71.316 117.391 88.47 117.481 ;
     RECT  28.332 116.069 70.47 117.661 ;
     RECT  71.208 117.481 88.47 117.661 ;
     RECT  90.576 116.699 90.702 117.725 ;
     RECT  90.576 117.725 90.63 117.821 ;
     RECT  28.332 117.661 88.47 117.859 ;
     RECT  28.332 117.859 88.938 118.061 ;
     RECT  28.332 118.061 88.902 118.349 ;
     RECT  89.748 118.471 89.766 118.741 ;
     RECT  90.576 117.821 90.594 118.741 ;
     RECT  28.332 118.349 88.326 119.323 ;
     RECT  1.296 41.791 27.594 119.515 ;
     RECT  89.748 118.741 90.594 119.597 ;
     RECT  28.332 119.323 88.902 119.705 ;
     RECT  28.332 119.705 86.778 119.813 ;
     RECT  89.748 119.597 90.054 119.837 ;
     RECT  87.66 119.705 88.902 120.083 ;
     RECT  89.748 119.837 89.766 120.331 ;
     RECT  28.332 119.813 86.742 120.631 ;
     RECT  87.66 120.083 88.326 120.631 ;
     RECT  89.316 120.331 89.766 120.631 ;
     RECT  90.684 120.793 90.702 120.811 ;
     RECT  89.316 120.631 89.838 121.027 ;
     RECT  28.332 120.631 88.326 121.289 ;
     RECT  28.332 121.289 87.426 121.325 ;
     RECT  89.28 121.027 89.838 121.703 ;
     RECT  88.236 121.289 88.326 121.711 ;
     RECT  89.424 121.703 89.838 121.937 ;
     RECT  28.332 121.325 87.318 122.251 ;
     RECT  88.236 121.711 88.434 122.251 ;
     RECT  89.496 121.937 89.838 122.381 ;
     RECT  89.748 122.381 89.838 122.587 ;
     RECT  90.612 120.811 90.702 122.587 ;
     RECT  89.748 122.587 90.702 123.115 ;
     RECT  89.46 123.115 90.702 123.355 ;
     RECT  28.332 122.251 88.434 123.421 ;
     RECT  89.424 123.355 90.702 123.421 ;
     RECT  28.332 123.421 90.702 124.397 ;
     RECT  89.748 124.397 90.702 124.799 ;
     RECT  28.332 124.397 88.938 125.165 ;
     RECT  28.332 125.165 88.434 125.405 ;
     RECT  90.612 124.799 90.702 125.549 ;
     RECT  90.612 125.549 90.63 125.645 ;
     RECT  28.332 125.405 88.29 126.193 ;
     RECT  89.748 124.799 89.838 126.301 ;
     RECT  89.748 126.301 90.054 126.427 ;
     RECT  28.332 126.193 88.938 126.499 ;
     RECT  89.748 126.427 90.63 126.499 ;
     RECT  0.612 119.515 27.594 126.535 ;
     RECT  28.332 126.499 90.63 126.535 ;
     RECT  0.612 126.535 90.63 127.181 ;
     RECT  89.28 127.181 90.63 127.421 ;
     RECT  0.612 127.181 88.434 127.457 ;
     RECT  89.28 127.421 90.594 127.709 ;
     RECT  29.736 127.457 88.434 128.189 ;
     RECT  29.736 128.189 88.29 128.285 ;
     RECT  88.092 128.285 88.29 128.429 ;
     RECT  0.612 127.457 28.926 128.821 ;
     RECT  29.736 128.285 87.246 128.821 ;
     RECT  0.612 128.821 87.246 129.581 ;
     RECT  88.272 128.429 88.29 129.581 ;
     RECT  89.28 127.709 90.018 129.581 ;
    LAYER M4 ;
     RECT  0.757 2.256 1.061 2.28 ;
     RECT  1.061 1.728 1.145 2.28 ;
     RECT  1.093 129.456 1.429 129.48 ;
     RECT  1.145 2.256 1.765 2.28 ;
     RECT  1.429 129.408 2.08 129.48 ;
     RECT  1.429 1.104 2.405 1.128 ;
     RECT  1.765 2.256 2.408 2.904 ;
     RECT  2.069 3.984 2.408 4.008 ;
     RECT  2.329 4.992 2.408 5.016 ;
     RECT  2.365 8.448 2.408 8.472 ;
     RECT  0.757 17.616 2.408 17.64 ;
     RECT  1.765 21.12 2.408 21.144 ;
     RECT  2.293 0.096 2.483 0.12 ;
     RECT  2.408 2.148 2.512 127.452 ;
     RECT  2.512 2.148 2.704 127.182 ;
     RECT  2.704 4.992 2.801 5.4 ;
     RECT  2.704 2.88 2.819 3.864 ;
     RECT  2.704 6.528 2.819 6.84 ;
     RECT  2.819 2.88 3.125 3.72 ;
     RECT  2.819 6.528 3.629 6.552 ;
     RECT  3.109 1.728 3.781 1.752 ;
     RECT  3.125 3.456 3.805 3.72 ;
     RECT  2.801 5.376 3.805 5.4 ;
     RECT  3.781 1.728 3.881 1.8 ;
     RECT  2.704 21.12 4.025 21.144 ;
     RECT  2.704 17.616 4.061 17.64 ;
     RECT  2.704 8.448 4.277 8.472 ;
     RECT  3.881 1.728 4.498 1.752 ;
     RECT  4.498 1.68 4.597 1.752 ;
     RECT  3.805 3.456 4.669 5.4 ;
     RECT  4.597 0.912 5.269 1.752 ;
     RECT  4.669 3.168 5.269 5.4 ;
     RECT  4.525 8.592 5.541 8.616 ;
     RECT  5.541 8.592 5.797 9.096 ;
     RECT  5.797 7.776 5.843 9.096 ;
     RECT  2.08 129.36 5.845 129.48 ;
     RECT  5.843 7.776 5.884 7.8 ;
     RECT  5.269 0.912 6.037 5.4 ;
     RECT  6.037 0.912 6.113 6.072 ;
     RECT  5.845 129.312 6.113 129.48 ;
     RECT  6.113 3.648 6.217 6.072 ;
     RECT  5.843 8.832 6.371 9.096 ;
     RECT  6.217 3.648 6.793 6.648 ;
     RECT  6.541 7.632 6.793 7.656 ;
     RECT  6.325 11.376 6.829 11.4 ;
     RECT  6.829 10.608 6.853 11.4 ;
     RECT  6.793 3.648 6.973 7.656 ;
     RECT  6.113 0.912 7.484 2.232 ;
     RECT  6.853 10.512 7.535 11.4 ;
     RECT  6.973 3.648 7.621 8.088 ;
     RECT  6.113 129.408 7.765 129.48 ;
     RECT  7.484 0.912 7.808 2.28 ;
     RECT  7.621 3.312 7.808 8.088 ;
     RECT  7.535 10.32 7.808 11.4 ;
     RECT  7.513 12.528 7.808 12.552 ;
     RECT  7.765 128.832 7.907 129.48 ;
     RECT  7.808 0.912 7.912 127.452 ;
     RECT  7.912 0.912 8.104 127.182 ;
     RECT  8.104 0.912 8.243 2.28 ;
     RECT  8.104 10.32 8.243 12.552 ;
     RECT  8.243 10.32 8.245 11.448 ;
     RECT  8.243 12.528 8.633 12.552 ;
     RECT  8.245 10.32 8.705 11.112 ;
     RECT  7.907 129.456 9.172 129.48 ;
     RECT  8.705 10.512 9.493 11.112 ;
     RECT  8.104 14.208 9.541 14.232 ;
     RECT  9.541 14.208 9.731 14.568 ;
     RECT  8.104 3.312 9.741 7.992 ;
     RECT  8.243 0.912 9.836 2.232 ;
     RECT  9.685 15.696 10.109 15.72 ;
     RECT  9.731 14.544 10.505 14.568 ;
     RECT  9.493 10.512 10.7 11.832 ;
     RECT  9.961 12.864 10.7 12.888 ;
     RECT  10.7 10.512 10.741 12.888 ;
     RECT  10.741 10.512 10.787 13.704 ;
     RECT  9.836 0.912 10.789 2.28 ;
     RECT  9.741 3.312 10.789 4.2 ;
     RECT  10.787 10.512 10.789 11.928 ;
     RECT  10.789 10.32 10.835 11.928 ;
     RECT  10.717 16.944 10.837 16.968 ;
     RECT  10.835 11.664 10.865 11.928 ;
     RECT  10.837 16.944 10.885 17.688 ;
     RECT  10.865 11.664 10.937 11.832 ;
     RECT  10.885 16.512 10.973 17.688 ;
     RECT  10.937 11.712 11.009 11.832 ;
     RECT  10.787 13.68 11.405 13.704 ;
     RECT  10.973 16.512 11.513 16.968 ;
     RECT  10.835 10.32 11.545 10.536 ;
     RECT  11.513 16.944 11.729 16.968 ;
     RECT  11.833 9.216 11.905 9.24 ;
     RECT  11.509 15.408 11.939 15.432 ;
     RECT  11.437 18.144 12.229 18.168 ;
     RECT  10.789 0.912 12.337 4.2 ;
     RECT  9.741 5.232 12.337 7.992 ;
     RECT  11.009 11.712 12.565 11.736 ;
     RECT  12.565 11.712 12.62 12.504 ;
     RECT  11.905 9.12 12.661 9.24 ;
     RECT  11.545 10.272 12.661 10.536 ;
     RECT  12.229 18.144 12.661 18.792 ;
     RECT  9.172 129.408 12.901 129.48 ;
     RECT  12.337 0.912 13.093 7.992 ;
     RECT  12.661 9.12 13.093 10.536 ;
     RECT  13.093 15.984 13.129 16.008 ;
     RECT  12.901 129.36 13.165 129.48 ;
     RECT  13.093 0.096 13.208 10.536 ;
     RECT  12.62 11.712 13.208 13.272 ;
     RECT  13.129 15.456 13.208 16.104 ;
     RECT  12.661 18.144 13.208 19.608 ;
     RECT  13.165 128.832 13.283 129.48 ;
     RECT  13.208 0.096 13.312 127.452 ;
     RECT  13.312 0.096 13.504 127.182 ;
     RECT  13.504 5.232 13.565 8.52 ;
     RECT  13.504 14.88 14.195 16.104 ;
     RECT  13.504 19.488 14.243 19.608 ;
     RECT  13.504 0.096 14.321 4.2 ;
     RECT  13.504 21.12 14.713 21.672 ;
     RECT  14.581 22.656 14.713 22.68 ;
     RECT  13.504 18.144 14.771 18.168 ;
     RECT  14.713 21.12 14.771 22.68 ;
     RECT  14.771 21.648 14.861 22.68 ;
     RECT  13.504 11.808 14.897 13.512 ;
     RECT  14.897 11.808 15.113 13.08 ;
     RECT  14.243 19.488 15.181 19.512 ;
     RECT  13.504 17.088 15.361 17.112 ;
     RECT  15.361 16.56 15.401 17.112 ;
     RECT  15.113 11.808 15.437 12.552 ;
     RECT  15.437 11.808 15.505 11.832 ;
     RECT  14.195 15.408 15.541 15.432 ;
     RECT  15.401 16.56 15.541 16.584 ;
     RECT  14.861 21.984 15.581 22.68 ;
     RECT  13.283 129.456 15.589 129.48 ;
     RECT  15.505 11.424 15.635 11.832 ;
     RECT  15.181 19.344 15.901 19.512 ;
     RECT  15.589 129.408 15.925 129.48 ;
     RECT  15.901 18.816 15.985 19.512 ;
     RECT  15.98 23.808 16.021 23.832 ;
     RECT  15.581 21.984 16.067 22.008 ;
     RECT  16.021 23.808 16.067 24.648 ;
     RECT  15.985 19.248 16.261 19.512 ;
     RECT  15.541 15.408 16.364 16.584 ;
     RECT  16.364 15.36 16.451 16.584 ;
     RECT  15.925 129.36 16.597 129.48 ;
     RECT  16.597 129.264 16.913 129.48 ;
     RECT  16.913 129.36 16.949 129.48 ;
     RECT  16.451 15.408 16.979 16.584 ;
     RECT  16.979 15.984 17.077 16.584 ;
     RECT  16.837 17.856 17.077 17.88 ;
     RECT  15.865 20.736 17.077 20.76 ;
     RECT  17.077 15.984 17.093 17.88 ;
     RECT  17.093 16.512 17.123 17.88 ;
     RECT  16.261 19.248 17.233 19.608 ;
     RECT  17.077 20.736 17.309 21.672 ;
     RECT  16.765 22.8 17.593 22.824 ;
     RECT  16.067 24.624 17.593 24.648 ;
     RECT  17.593 22.8 17.948 24.648 ;
     RECT  17.941 26.736 18.277 26.76 ;
     RECT  14.321 0.912 18.469 4.2 ;
     RECT  16.933 25.632 18.469 25.656 ;
     RECT  18.277 26.736 18.469 27.192 ;
     RECT  18.469 0.096 18.608 4.2 ;
     RECT  13.565 5.232 18.608 7.992 ;
     RECT  15.635 11.808 18.608 11.832 ;
     RECT  17.123 17.088 18.608 17.112 ;
     RECT  17.233 18.816 18.608 19.608 ;
     RECT  17.948 22.752 18.608 24.648 ;
     RECT  18.469 25.632 18.608 27.96 ;
     RECT  18.608 0.096 18.659 127.452 ;
     RECT  18.659 0.912 18.712 127.452 ;
     RECT  18.712 0.912 18.904 127.182 ;
     RECT  16.949 129.456 18.949 129.48 ;
     RECT  18.904 27.168 19.145 27.96 ;
     RECT  19.145 27.936 19.181 27.96 ;
     RECT  18.949 129.408 19.285 129.48 ;
     RECT  18.904 23.568 19.331 25.128 ;
     RECT  18.904 21.12 19.577 21.144 ;
     RECT  19.285 129.36 19.829 129.48 ;
     RECT  19.331 23.568 20.045 23.592 ;
     RECT  20.365 22.8 20.396 22.824 ;
     RECT  18.904 18.816 20.483 19.512 ;
     RECT  20.257 21.648 20.485 21.672 ;
     RECT  20.396 22.704 20.485 22.824 ;
     RECT  20.485 21.648 20.531 22.824 ;
     RECT  20.437 28.32 20.629 28.344 ;
     RECT  20.629 28.32 20.653 28.776 ;
     RECT  19.957 30.192 20.657 30.216 ;
     RECT  19.331 25.104 20.725 25.128 ;
     RECT  20.653 28.272 20.729 28.776 ;
     RECT  20.725 25.008 20.765 25.128 ;
     RECT  20.531 22.464 20.909 22.824 ;
     RECT  19.829 129.408 20.909 129.48 ;
     RECT  20.909 22.8 20.981 22.824 ;
     RECT  20.483 18.816 21.011 19.464 ;
     RECT  19.897 26.64 21.085 26.664 ;
     RECT  21.085 26.112 21.253 26.664 ;
     RECT  20.729 28.272 21.253 28.344 ;
     RECT  20.765 25.008 21.301 25.032 ;
     RECT  21.253 26.112 21.347 28.344 ;
     RECT  21.347 27.024 21.349 28.344 ;
     RECT  21.011 19.44 21.593 19.464 ;
     RECT  18.904 0.912 21.644 4.2 ;
     RECT  18.904 5.232 21.644 7.992 ;
     RECT  21.644 0.912 21.731 7.992 ;
     RECT  21.301 24.48 21.809 25.032 ;
     RECT  21.481 30.24 22.021 30.264 ;
     RECT  22.021 29.376 22.067 30.264 ;
     RECT  21.553 20.544 22.277 20.568 ;
     RECT  21.685 33.024 22.313 33.048 ;
     RECT  20.909 129.456 22.357 129.48 ;
     RECT  22.273 18.816 22.403 18.84 ;
     RECT  21.809 24.48 22.633 24.552 ;
     RECT  22.633 23.952 22.739 24.552 ;
     RECT  22.739 24.528 22.961 24.552 ;
     RECT  21.349 27.984 23.027 28.344 ;
     RECT  22.067 29.376 23.036 30.072 ;
     RECT  23.027 27.984 23.281 28.008 ;
     RECT  23.036 29.04 23.317 30.072 ;
     RECT  22.981 34.992 23.365 35.016 ;
     RECT  22.957 23.376 23.677 23.4 ;
     RECT  23.365 34.992 23.701 35.352 ;
     RECT  21.731 0.912 24.008 4.2 ;
     RECT  21.731 5.232 24.008 7.992 ;
     RECT  18.904 11.808 24.008 11.832 ;
     RECT  23.677 22.8 24.008 23.4 ;
     RECT  23.749 26.208 24.008 26.76 ;
     RECT  23.281 27.888 24.008 28.008 ;
     RECT  23.317 29.04 24.008 30.168 ;
     RECT  23.317 31.92 24.008 31.944 ;
     RECT  23.701 34.992 24.008 35.736 ;
     RECT  24.008 0.912 24.112 127.452 ;
     RECT  24.112 0.912 24.304 127.182 ;
     RECT  24.304 0.912 24.325 4.2 ;
     RECT  24.325 0.096 24.419 4.2 ;
     RECT  24.304 29.04 24.473 29.064 ;
     RECT  24.304 33.552 24.707 34.056 ;
     RECT  22.357 129.408 24.709 129.48 ;
     RECT  24.304 32.496 24.769 32.52 ;
     RECT  24.304 27.888 24.941 27.912 ;
     RECT  24.304 24.48 25.091 24.504 ;
     RECT  24.304 37.008 25.091 37.848 ;
     RECT  24.304 30.192 25.265 30.216 ;
     RECT  24.709 129.36 25.381 129.48 ;
     RECT  25.333 30.72 25.427 30.744 ;
     RECT  25.381 129.312 25.625 129.48 ;
     RECT  25.657 28.512 25.763 28.536 ;
     RECT  25.297 32.352 25.981 32.376 ;
     RECT  25.091 37.824 26.197 37.848 ;
     RECT  25.801 30.816 26.245 30.84 ;
     RECT  25.981 32.352 26.245 32.52 ;
     RECT  26.245 30.816 26.525 32.52 ;
     RECT  24.707 34.032 26.701 34.056 ;
     RECT  24.304 35.136 26.701 35.16 ;
     RECT  26.525 31.536 26.773 32.52 ;
     RECT  26.701 34.032 26.773 35.16 ;
     RECT  26.197 37.824 26.809 37.896 ;
     RECT  24.419 0.912 26.813 4.2 ;
     RECT  26.773 31.536 26.857 35.16 ;
     RECT  26.857 32.352 26.885 35.16 ;
     RECT  26.885 32.352 27.029 33.096 ;
     RECT  26.885 34.368 27.241 35.16 ;
     RECT  26.389 39.84 27.281 39.864 ;
     RECT  27.241 34.368 27.457 35.256 ;
     RECT  27.029 32.352 27.779 32.52 ;
     RECT  27.779 32.352 27.857 32.376 ;
     RECT  26.809 37.056 27.925 37.896 ;
     RECT  27.457 34.368 28.001 35.928 ;
     RECT  27.925 37.056 28.012 38.376 ;
     RECT  28.012 37.056 28.117 37.896 ;
     RECT  25.625 129.408 28.405 129.48 ;
     RECT  28.001 34.8 28.501 35.928 ;
     RECT  28.741 43.296 28.892 43.32 ;
     RECT  28.501 34.8 29.041 36.504 ;
     RECT  26.813 0.912 29.077 2.088 ;
     RECT  29.041 34.08 29.185 36.504 ;
     RECT  28.117 37.872 29.185 37.896 ;
     RECT  29.077 0.096 29.408 2.088 ;
     RECT  26.813 3.168 29.408 4.2 ;
     RECT  24.304 5.232 29.408 7.992 ;
     RECT  24.304 11.808 29.408 11.832 ;
     RECT  28.321 30.72 29.408 30.744 ;
     RECT  29.185 34.08 29.408 37.896 ;
     RECT  28.892 42.432 29.408 43.32 ;
     RECT  28.933 49.488 29.408 49.512 ;
     RECT  29.408 0.096 29.512 127.452 ;
     RECT  29.512 0.096 29.704 127.182 ;
     RECT  29.704 41.04 29.837 43.32 ;
     RECT  29.837 41.04 30.133 42.792 ;
     RECT  29.704 33.984 30.467 35.256 ;
     RECT  30.467 33.984 30.563 34.008 ;
     RECT  30.467 35.136 30.563 35.256 ;
     RECT  29.704 36.24 30.563 38.472 ;
     RECT  30.133 41.616 30.707 42.792 ;
     RECT  30.707 42.72 30.745 42.792 ;
     RECT  30.563 38.448 30.805 38.472 ;
     RECT  29.704 40.032 30.877 40.056 ;
     RECT  30.805 38.448 30.889 39 ;
     RECT  29.704 0.096 30.899 4.2 ;
     RECT  30.877 40.032 30.917 40.488 ;
     RECT  30.697 46.56 31.1 46.584 ;
     RECT  30.563 37.056 31.139 37.08 ;
     RECT  30.563 35.232 31.187 35.256 ;
     RECT  31.1 45.36 31.187 45.384 ;
     RECT  31.1 46.464 31.187 46.584 ;
     RECT  30.917 40.464 31.381 40.488 ;
     RECT  30.707 41.616 31.381 41.64 ;
     RECT  30.745 42.72 31.42 42.744 ;
     RECT  28.405 129.36 31.493 129.48 ;
     RECT  31.381 40.464 31.781 41.64 ;
     RECT  30.889 38.448 31.811 38.808 ;
     RECT  31.187 46.56 32.209 46.584 ;
     RECT  29.704 49.488 32.437 49.512 ;
     RECT  31.811 38.448 32.501 38.76 ;
     RECT  31.493 129.408 32.717 129.48 ;
     RECT  32.437 49.488 32.773 50.184 ;
     RECT  32.497 43.344 32.828 43.368 ;
     RECT  32.828 42.72 32.915 43.368 ;
     RECT  32.501 38.736 33.073 38.76 ;
     RECT  31.781 41.04 33.113 41.64 ;
     RECT  33.073 38.736 33.157 38.808 ;
     RECT  33.113 41.04 33.164 41.592 ;
     RECT  33.164 40.176 33.251 41.592 ;
     RECT  32.773 49.488 33.293 50.232 ;
     RECT  32.717 129.456 33.329 129.48 ;
     RECT  33.445 125.376 33.581 125.4 ;
     RECT  32.209 46.08 34.009 46.584 ;
     RECT  34.009 46.08 34.045 46.776 ;
     RECT  33.781 54.144 34.117 54.168 ;
     RECT  34.045 45.6 34.153 46.776 ;
     RECT  34.153 45.552 34.213 46.776 ;
     RECT  34.213 44.784 34.22 46.776 ;
     RECT  32.915 43.344 34.333 43.368 ;
     RECT  34.22 44.352 34.333 46.776 ;
     RECT  34.117 53.568 34.453 54.168 ;
     RECT  33.293 49.488 34.765 49.512 ;
     RECT  30.899 0.912 34.789 4.2 ;
     RECT  34.789 0.144 34.808 4.2 ;
     RECT  29.704 5.232 34.808 7.992 ;
     RECT  29.704 11.808 34.808 11.832 ;
     RECT  33.157 38.736 34.808 38.76 ;
     RECT  33.251 41.04 34.808 41.592 ;
     RECT  34.333 43.344 34.808 46.776 ;
     RECT  34.765 48.48 34.808 48.504 ;
     RECT  34.765 49.488 34.808 49.56 ;
     RECT  34.453 53.52 34.808 54.168 ;
     RECT  34.808 0.144 34.912 127.452 ;
     RECT  34.912 0.144 35.104 127.182 ;
     RECT  34.789 129.456 35.117 129.48 ;
     RECT  35.117 129.408 35.201 129.48 ;
     RECT  35.104 0.144 35.219 4.2 ;
     RECT  35.219 0.24 35.267 4.2 ;
     RECT  35.201 129.456 35.315 129.48 ;
     RECT  35.461 128.208 35.597 128.232 ;
     RECT  35.104 42.72 35.747 44.328 ;
     RECT  35.104 45.936 35.747 46.776 ;
     RECT  35.104 41.568 35.843 41.592 ;
     RECT  35.747 43.296 35.891 44.328 ;
     RECT  35.104 53.04 35.921 53.928 ;
     RECT  35.104 48.48 36.205 48.504 ;
     RECT  35.921 53.04 36.38 53.592 ;
     RECT  35.104 49.488 36.467 49.56 ;
     RECT  36.097 50.784 36.701 50.808 ;
     RECT  36.467 49.536 36.716 49.56 ;
     RECT  36.701 50.688 36.716 50.808 ;
     RECT  36.716 49.536 36.755 50.808 ;
     RECT  36.755 49.536 36.785 50.712 ;
     RECT  36.469 127.632 36.785 127.656 ;
     RECT  36.785 49.536 36.803 50.28 ;
     RECT  36.133 62.736 36.805 62.76 ;
     RECT  36.205 47.856 36.851 48.504 ;
     RECT  35.891 43.296 37.073 43.32 ;
     RECT  36.38 52.224 37.393 53.592 ;
     RECT  37.393 51.888 37.397 53.592 ;
     RECT  36.805 62.64 37.477 62.76 ;
     RECT  37.397 51.888 37.523 51.912 ;
     RECT  37.477 62.64 37.541 63.24 ;
     RECT  37.465 54.672 37.613 54.696 ;
     RECT  36.803 49.536 37.621 49.56 ;
     RECT  36.851 47.856 37.649 48.12 ;
     RECT  37.621 49.152 37.729 49.56 ;
     RECT  37.541 62.736 37.865 63.24 ;
     RECT  37.069 41.568 37.907 41.592 ;
     RECT  35.747 45.936 38.033 46.584 ;
     RECT  37.649 48.096 38.077 48.12 ;
     RECT  38.033 45.936 38.117 46.728 ;
     RECT  35.267 0.912 38.177 4.2 ;
     RECT  38.077 48.096 38.189 48.696 ;
     RECT  37.865 63.216 38.189 63.24 ;
     RECT  38.177 0.096 38.261 4.2 ;
     RECT  38.117 45.936 38.473 46.584 ;
     RECT  38.189 48.24 38.477 48.696 ;
     RECT  38.197 127.056 38.617 127.08 ;
     RECT  38.617 126.576 38.693 127.08 ;
     RECT  38.693 126.576 38.765 126.6 ;
     RECT  37.397 52.992 38.945 53.592 ;
     RECT  38.869 62.736 39.205 62.76 ;
     RECT  38.945 53.424 39.541 53.592 ;
     RECT  37.813 54.864 39.541 54.888 ;
     RECT  39.205 62.64 39.541 62.76 ;
     RECT  38.261 0.912 39.869 4.2 ;
     RECT  35.104 5.232 39.869 7.992 ;
     RECT  39.301 56.352 39.949 56.376 ;
     RECT  39.869 0.912 40.069 7.992 ;
     RECT  39.877 129.456 40.069 129.48 ;
     RECT  40.069 0.096 40.208 7.992 ;
     RECT  35.104 11.808 40.208 11.832 ;
     RECT  38.473 45.6 40.208 46.584 ;
     RECT  38.477 48.24 40.208 48.264 ;
     RECT  39.661 49.248 40.208 49.272 ;
     RECT  39.481 51.888 40.208 51.912 ;
     RECT  39.541 53.424 40.208 54.888 ;
     RECT  39.949 56.352 40.208 57.048 ;
     RECT  38.533 58.704 40.208 58.728 ;
     RECT  39.541 62.16 40.208 62.76 ;
     RECT  39.985 123.696 40.208 123.72 ;
     RECT  40.069 129.408 40.259 129.48 ;
     RECT  40.208 0.096 40.312 127.452 ;
     RECT  40.312 0.096 40.504 127.182 ;
     RECT  40.504 0.096 40.637 4.2 ;
     RECT  40.504 48.48 40.933 49.368 ;
     RECT  40.504 63.168 40.961 63.192 ;
     RECT  40.259 129.456 41.033 129.48 ;
     RECT  40.933 49.248 41.075 49.368 ;
     RECT  41.075 49.344 41.141 49.368 ;
     RECT  40.504 46.128 41.267 46.584 ;
     RECT  40.504 53.52 41.321 54.888 ;
     RECT  40.504 125.952 41.357 125.976 ;
     RECT  40.504 51.264 41.497 51.288 ;
     RECT  40.504 52.416 41.497 52.44 ;
     RECT  41.321 53.52 41.497 53.592 ;
     RECT  41.497 51.264 41.601 53.592 ;
     RECT  41.601 51.264 41.603 51.912 ;
     RECT  41.603 51.264 41.789 51.528 ;
     RECT  41.821 50.736 41.939 50.76 ;
     RECT  41.9 60.528 41.941 60.552 ;
     RECT  41.525 63.216 41.969 63.24 ;
     RECT  41.941 60.528 41.987 61.272 ;
     RECT  40.504 58.656 42.101 58.68 ;
     RECT  42.101 58.656 42.133 58.776 ;
     RECT  42.133 58.176 42.181 58.776 ;
     RECT  42.181 57.6 42.185 58.776 ;
     RECT  41.601 53.04 42.293 53.592 ;
     RECT  42.293 53.568 42.323 53.592 ;
     RECT  42.229 63.744 42.565 63.768 ;
     RECT  40.504 56.352 42.577 56.376 ;
     RECT  41.321 54.624 42.613 54.888 ;
     RECT  42.613 54.624 42.659 54.936 ;
     RECT  42.577 56.256 42.721 56.376 ;
     RECT  42.565 63.744 42.761 63.816 ;
     RECT  42.659 54.864 43.013 54.936 ;
     RECT  42.761 63.744 43.013 63.768 ;
     RECT  41.987 61.248 43.189 61.272 ;
     RECT  42.721 56.256 43.292 56.424 ;
     RECT  42.185 57.6 43.292 58.2 ;
     RECT  43.189 61.248 43.333 62.088 ;
     RECT  43.292 56.256 43.379 58.2 ;
     RECT  43.333 61.248 43.379 62.712 ;
     RECT  43.379 57.6 43.481 58.2 ;
     RECT  42.901 68.352 43.625 68.376 ;
     RECT  43.379 62.064 43.661 62.712 ;
     RECT  43.237 73.488 43.877 73.512 ;
     RECT  43.868 10.8 43.955 10.824 ;
     RECT  43.379 56.256 44.021 56.28 ;
     RECT  44.245 66.912 44.269 66.936 ;
     RECT  43.909 124.8 44.273 124.824 ;
     RECT  43.481 57.6 44.291 58.152 ;
     RECT  43.661 62.064 44.521 62.088 ;
     RECT  44.521 61.584 44.627 62.088 ;
     RECT  40.637 0.912 44.677 4.2 ;
     RECT  44.677 0.288 44.845 4.2 ;
     RECT  44.665 63.84 44.945 63.864 ;
     RECT  44.945 63.84 44.989 64.296 ;
     RECT  44.917 129.456 45.029 129.48 ;
     RECT  44.269 66.096 45.061 66.936 ;
     RECT  44.627 61.968 45.169 62.088 ;
     RECT  44.291 58.128 45.301 58.152 ;
     RECT  45.301 58.128 45.308 59.064 ;
     RECT  44.593 60.288 45.308 60.312 ;
     RECT  44.845 0.096 45.608 4.2 ;
     RECT  40.504 5.232 45.608 7.992 ;
     RECT  40.504 11.808 45.608 11.832 ;
     RECT  41.267 46.56 45.608 46.584 ;
     RECT  43.013 54.864 45.608 54.888 ;
     RECT  45.308 58.128 45.608 60.312 ;
     RECT  45.169 61.968 45.608 62.568 ;
     RECT  44.989 63.792 45.608 64.296 ;
     RECT  45.061 66.096 45.608 67.608 ;
     RECT  45.253 73.344 45.608 73.368 ;
     RECT  44.965 80.592 45.608 80.616 ;
     RECT  44.581 126.48 45.608 126.504 ;
     RECT  45.608 0.096 45.904 127.452 ;
     RECT  45.904 59.184 45.965 59.208 ;
     RECT  45.589 129.408 46.019 129.432 ;
     RECT  45.904 63.792 46.037 63.816 ;
     RECT  45.904 0.096 46.067 4.2 ;
     RECT  45.904 5.232 46.067 8.52 ;
     RECT  45.904 54.864 46.115 54.888 ;
     RECT  45.904 60.288 46.115 62.712 ;
     RECT  45.925 127.632 46.181 127.656 ;
     RECT  46.115 60.288 46.217 61.608 ;
     RECT  46.217 61.008 46.333 61.608 ;
     RECT  45.904 66.144 46.643 66.744 ;
     RECT  45.904 69.984 46.739 70.008 ;
     RECT  46.333 61.584 46.979 61.608 ;
     RECT  47.185 65.088 47.221 65.112 ;
     RECT  45.904 73.488 47.269 73.512 ;
     RECT  47.221 64.416 47.315 65.112 ;
     RECT  45.904 75.216 47.441 75.24 ;
     RECT  46.115 62.688 47.545 62.712 ;
     RECT  45.904 67.728 47.612 67.8 ;
     RECT  47.545 62.112 47.651 63.144 ;
     RECT  47.315 64.896 47.653 65.112 ;
     RECT  46.643 66.72 47.653 66.744 ;
     RECT  47.612 67.728 47.653 68.088 ;
     RECT  47.653 66.72 47.699 68.088 ;
     RECT  47.653 64.896 47.873 65.64 ;
     RECT  47.269 73.488 47.873 73.56 ;
     RECT  47.651 62.688 48.053 63.144 ;
     RECT  46.933 129.456 48.053 129.48 ;
     RECT  47.873 64.896 48.269 64.968 ;
     RECT  48.193 72.336 48.277 72.36 ;
     RECT  48.229 61.584 48.323 61.608 ;
     RECT  45.904 71.328 48.377 71.352 ;
     RECT  48.053 63.12 48.757 63.144 ;
     RECT  48.757 63.12 48.803 63.864 ;
     RECT  48.373 69.408 48.881 69.432 ;
     RECT  48.277 72.432 48.949 73.416 ;
     RECT  48.581 66.144 48.995 66.168 ;
     RECT  48.803 63.84 49.241 63.864 ;
     RECT  48.949 72.432 49.277 73.512 ;
     RECT  49.244 62.112 49.331 62.136 ;
     RECT  49.285 126.48 49.421 126.504 ;
     RECT  49.489 69.504 49.525 69.528 ;
     RECT  49.277 73.488 49.529 73.512 ;
     RECT  46.067 0.192 49.561 4.2 ;
     RECT  46.067 5.232 49.561 7.992 ;
     RECT  47.699 67.68 49.565 67.8 ;
     RECT  49.525 69.504 49.573 70.248 ;
     RECT  49.573 74.016 49.597 74.04 ;
     RECT  49.597 74.016 49.66 74.136 ;
     RECT  49.561 0.192 49.667 7.992 ;
     RECT  49.589 75.216 49.673 75.24 ;
     RECT  49.573 70.224 49.813 70.248 ;
     RECT  49.813 70.224 49.853 70.68 ;
     RECT  45.904 80.592 49.957 80.616 ;
     RECT  49.853 70.656 50.245 70.68 ;
     RECT  49.957 79.776 50.284 80.616 ;
     RECT  49.66 74.112 50.389 74.136 ;
     RECT  49.885 66.672 50.636 66.696 ;
     RECT  50.636 66.576 50.677 66.696 ;
     RECT  49.565 67.68 50.677 67.704 ;
     RECT  50.629 76.32 50.821 76.344 ;
     RECT  49.277 72.432 50.849 72.456 ;
     RECT  49.667 0.192 50.869 4.2 ;
     RECT  50.389 74.112 50.869 74.52 ;
     RECT  50.821 76.272 50.869 76.344 ;
     RECT  50.869 0.096 51.008 4.2 ;
     RECT  49.667 5.232 51.008 7.992 ;
     RECT  45.904 11.808 51.008 11.832 ;
     RECT  48.269 64.944 51.008 64.968 ;
     RECT  50.677 66.576 51.008 67.704 ;
     RECT  50.245 70.656 51.008 71.304 ;
     RECT  50.849 72.384 51.008 72.456 ;
     RECT  50.869 74.112 51.008 75.192 ;
     RECT  50.869 76.272 51.008 76.488 ;
     RECT  50.284 79.728 51.008 80.616 ;
     RECT  48.229 81.888 51.008 81.912 ;
     RECT  51.008 0.096 51.304 127.452 ;
     RECT  51.304 0.096 51.365 4.2 ;
     RECT  51.304 70.656 51.365 71.256 ;
     RECT  50.821 129.456 51.443 129.48 ;
     RECT  51.304 66.672 51.473 68.424 ;
     RECT  51.304 75.84 51.473 76.488 ;
     RECT  51.973 127.632 52.157 127.656 ;
     RECT  51.473 67.68 52.163 68.424 ;
     RECT  51.473 75.84 52.355 75.864 ;
     RECT  51.304 74.112 52.477 74.136 ;
     RECT  51.304 72.432 52.517 72.456 ;
     RECT  52.163 68.4 52.589 68.424 ;
     RECT  51.473 66.672 52.691 66.696 ;
     RECT  51.304 78.624 52.765 80.616 ;
     RECT  52.757 76.896 52.841 76.92 ;
     RECT  52.765 78.096 53.021 80.616 ;
     RECT  52.477 73.488 53.029 74.136 ;
     RECT  53.029 73.488 53.075 74.664 ;
     RECT  53.075 74.64 53.116 74.664 ;
     RECT  51.365 0.144 53.129 4.2 ;
     RECT  51.365 71.232 53.233 71.256 ;
     RECT  53.233 71.232 53.269 71.592 ;
     RECT  53.317 126.48 53.417 126.504 ;
     RECT  53.075 73.488 53.489 73.512 ;
     RECT  53.021 78.096 53.509 78.936 ;
     RECT  51.304 81.888 53.509 81.912 ;
     RECT  53.509 78.048 53.555 78.936 ;
     RECT  53.021 80.112 53.555 80.616 ;
     RECT  53.555 78.048 53.699 78.648 ;
     RECT  53.699 78.048 53.885 78.072 ;
     RECT  53.665 76.464 53.917 76.488 ;
     RECT  53.653 83.184 53.989 83.208 ;
     RECT  53.917 75.84 54.061 76.488 ;
     RECT  53.269 70.656 54.281 71.592 ;
     RECT  53.509 81.84 54.373 81.912 ;
     RECT  53.989 83.136 54.373 83.208 ;
     RECT  54.281 70.656 54.419 70.68 ;
     RECT  54.061 75.648 54.629 76.488 ;
     RECT  53.129 0.192 54.637 4.2 ;
     RECT  51.304 5.232 54.637 7.992 ;
     RECT  54.629 75.648 54.661 76.92 ;
     RECT  54.661 75.648 54.713 77.736 ;
     RECT  54.637 0.192 54.755 7.992 ;
     RECT  54.713 75.648 54.961 75.96 ;
     RECT  54.997 72.912 55.091 72.936 ;
     RECT  54.373 81.84 55.139 83.208 ;
     RECT  54.713 77.712 55.247 77.736 ;
     RECT  55.139 81.888 55.325 83.208 ;
     RECT  55.247 77.712 55.331 78.648 ;
     RECT  55.331 78.096 55.427 78.648 ;
     RECT  54.961 75.36 55.601 75.96 ;
     RECT  55.381 128.784 55.685 128.808 ;
     RECT  55.681 72.384 56.285 72.408 ;
     RECT  55.717 88.32 56.285 88.344 ;
     RECT  54.755 0.192 56.293 4.2 ;
     RECT  56.293 0.096 56.408 4.2 ;
     RECT  54.755 5.232 56.408 7.992 ;
     RECT  51.304 11.808 56.408 11.832 ;
     RECT  56.285 72.384 56.408 72.456 ;
     RECT  55.601 74.64 56.408 75.96 ;
     RECT  55.427 78.624 56.408 78.648 ;
     RECT  53.555 80.592 56.408 80.616 ;
     RECT  55.325 81.888 56.408 82.68 ;
     RECT  56.285 88.224 56.408 88.344 ;
     RECT  55.045 94.032 56.408 94.056 ;
     RECT  56.408 0.096 56.435 127.452 ;
     RECT  56.435 0.192 56.512 127.452 ;
     RECT  56.512 0.192 56.704 127.182 ;
     RECT  56.704 78.048 57.004 78.264 ;
     RECT  56.293 129.456 57.017 129.48 ;
     RECT  56.704 0.192 57.053 4.2 ;
     RECT  56.704 84.912 57.299 85.464 ;
     RECT  56.704 83.616 57.305 83.736 ;
     RECT  57.305 83.712 57.443 83.736 ;
     RECT  56.704 75.648 57.697 75.672 ;
     RECT  57.004 78.048 57.737 78.072 ;
     RECT  57.697 75.648 57.781 75.864 ;
     RECT  57.299 84.912 57.809 84.936 ;
     RECT  57.733 126.48 57.881 126.504 ;
     RECT  56.704 80.592 57.949 81.912 ;
     RECT  56.704 88.272 58.057 88.296 ;
     RECT  56.704 87.216 58.069 87.24 ;
     RECT  58.057 88.224 58.069 88.296 ;
     RECT  56.704 90.048 58.133 90.072 ;
     RECT  56.704 79.44 58.345 79.464 ;
     RECT  58.345 78.624 58.385 79.464 ;
     RECT  57.949 80.592 58.385 82.104 ;
     RECT  58.385 80.592 58.457 81.624 ;
     RECT  58.069 87.216 58.637 88.296 ;
     RECT  58.637 87.792 59.077 88.296 ;
     RECT  58.741 89.472 59.077 89.496 ;
     RECT  59.077 87.792 59.459 89.496 ;
     RECT  58.741 83.712 59.497 83.736 ;
     RECT  58.457 80.592 59.641 80.616 ;
     RECT  58.457 81.6 59.641 81.624 ;
     RECT  59.459 88.224 59.749 89.496 ;
     RECT  59.749 88.224 59.753 90.072 ;
     RECT  59.641 80.592 59.785 81.624 ;
     RECT  58.705 82.608 59.785 82.632 ;
     RECT  58.385 78.624 59.795 78.648 ;
     RECT  59.497 83.664 59.813 83.736 ;
     RECT  59.173 84.96 59.813 84.984 ;
     RECT  59.785 80.592 59.861 82.632 ;
     RECT  59.753 89.376 59.861 90.072 ;
     RECT  59.813 83.664 59.891 84.984 ;
     RECT  59.861 80.592 59.897 81.768 ;
     RECT  59.891 83.904 59.897 84.984 ;
     RECT  59.861 89.376 59.987 89.448 ;
     RECT  59.987 89.424 60.113 89.448 ;
     RECT  59.897 83.904 60.131 84.168 ;
     RECT  59.897 80.592 60.185 80.616 ;
     RECT  60.085 128.784 60.365 128.808 ;
     RECT  57.053 0.288 60.389 4.2 ;
     RECT  60.389 0.096 60.473 4.2 ;
     RECT  60.421 129.456 60.653 129.48 ;
     RECT  59.753 88.224 60.721 88.392 ;
     RECT  60.721 87.792 60.761 88.392 ;
     RECT  60.761 87.792 60.805 88.2 ;
     RECT  60.001 85.488 61.045 85.944 ;
     RECT  60.757 95.136 61.093 95.16 ;
     RECT  59.941 90.48 61.141 90.504 ;
     RECT  59.897 81.6 61.477 81.768 ;
     RECT  61.141 90.48 61.477 91.32 ;
     RECT  61.477 90.48 61.525 91.752 ;
     RECT  60.473 0.288 61.573 4.2 ;
     RECT  60.131 84.144 61.58 84.168 ;
     RECT  61.573 0.192 61.621 4.2 ;
     RECT  61.58 83.328 61.621 84.168 ;
     RECT  61.58 93.936 61.621 93.96 ;
     RECT  61.093 94.944 61.621 95.16 ;
     RECT  61.477 81.6 61.628 82.104 ;
     RECT  61.525 90.48 61.649 92.664 ;
     RECT  61.621 93.936 61.649 95.16 ;
     RECT  61.628 81.264 61.669 82.104 ;
     RECT  61.621 83.232 61.669 84.408 ;
     RECT  61.621 129.36 61.669 129.384 ;
     RECT  61.621 0.096 61.808 4.2 ;
     RECT  56.704 5.232 61.808 7.992 ;
     RECT  56.704 11.808 61.808 11.832 ;
     RECT  57.781 75.648 61.808 75.672 ;
     RECT  61.669 81.264 61.808 84.408 ;
     RECT  61.045 85.488 61.808 86.664 ;
     RECT  60.805 88.176 61.808 88.2 ;
     RECT  61.649 90.48 61.808 95.16 ;
     RECT  61.808 0.096 61.811 127.452 ;
     RECT  61.669 129.36 61.811 129.48 ;
     RECT  61.811 0.192 61.912 127.452 ;
     RECT  61.912 0.192 62.104 127.182 ;
     RECT  61.811 129.36 62.147 129.384 ;
     RECT  62.104 91.056 62.381 92.568 ;
     RECT  62.104 84.384 62.483 84.408 ;
     RECT  62.381 91.776 62.857 92.568 ;
     RECT  62.104 88.176 62.908 88.584 ;
     RECT  62.437 128.208 62.921 128.232 ;
     RECT  62.104 86.064 62.993 86.808 ;
     RECT  62.104 94.032 63.101 94.344 ;
     RECT  63.101 94.32 63.133 94.344 ;
     RECT  62.993 86.064 63.155 86.088 ;
     RECT  63.109 95.568 63.281 95.592 ;
     RECT  62.908 88.176 63.353 88.2 ;
     RECT  62.857 92.544 63.353 92.568 ;
     RECT  63.413 92.928 63.497 92.952 ;
     RECT  63.445 128.784 63.641 128.808 ;
     RECT  63.601 89.472 63.673 89.496 ;
     RECT  63.673 89.472 63.685 90.072 ;
     RECT  63.685 89.472 63.731 90.984 ;
     RECT  63.731 89.712 63.827 90.984 ;
     RECT  63.133 94.32 64.105 94.584 ;
     RECT  64.117 127.056 64.253 127.08 ;
     RECT  64.105 94.32 64.393 94.68 ;
     RECT  64.393 94.32 64.499 95.208 ;
     RECT  64.453 127.632 64.577 127.656 ;
     RECT  63.781 98.064 64.717 98.088 ;
     RECT  64.717 98.064 64.835 98.664 ;
     RECT  64.781 102 64.865 102.024 ;
     RECT  63.827 89.712 64.901 89.736 ;
     RECT  65.077 96.912 65.149 96.936 ;
     RECT  65.149 96.864 65.171 96.936 ;
     RECT  64.499 94.32 65.437 94.344 ;
     RECT  65.125 100.272 65.549 100.296 ;
     RECT  63.827 90.96 65.603 90.984 ;
     RECT  64.835 98.544 65.797 98.664 ;
     RECT  65.756 128.256 65.843 128.28 ;
     RECT  65.797 98.064 65.881 98.664 ;
     RECT  65.171 96.864 65.981 96.888 ;
     RECT  65.881 98.544 66.085 98.664 ;
     RECT  66.085 98.544 66.121 99.192 ;
     RECT  65.437 93.36 66.469 94.344 ;
     RECT  66.133 128.208 66.593 128.232 ;
     RECT  66.469 93.36 66.769 94.68 ;
     RECT  66.769 93.36 66.805 95.208 ;
     RECT  62.104 0.192 67.045 4.2 ;
     RECT  66.841 101.52 67.057 101.544 ;
     RECT  66.121 98.544 67.093 99.768 ;
     RECT  66.805 106.56 67.129 106.584 ;
     RECT  67.045 0.096 67.208 4.2 ;
     RECT  62.104 5.232 67.208 7.992 ;
     RECT  62.104 11.808 67.208 11.832 ;
     RECT  62.104 82.944 67.208 82.968 ;
     RECT  65.401 92.352 67.208 92.376 ;
     RECT  66.805 93.36 67.208 95.688 ;
     RECT  67.093 98.544 67.208 99.816 ;
     RECT  67.057 100.896 67.208 101.544 ;
     RECT  65.461 104.256 67.208 104.28 ;
     RECT  67.129 106.512 67.208 106.584 ;
     RECT  67.201 108.432 67.208 108.456 ;
     RECT  67.129 129.456 67.213 129.48 ;
     RECT  67.208 0.096 67.504 127.656 ;
     RECT  67.504 106.464 67.565 106.584 ;
     RECT  67.504 104.304 67.667 104.568 ;
     RECT  67.504 95.616 67.745 95.688 ;
     RECT  67.504 127.056 67.745 127.656 ;
     RECT  67.667 104.304 67.763 104.52 ;
     RECT  67.504 99.792 67.853 99.816 ;
     RECT  67.504 0.096 67.889 4.2 ;
     RECT  67.745 127.056 68.213 127.08 ;
     RECT  67.504 102.096 68.321 102.936 ;
     RECT  67.504 112.272 68.393 112.296 ;
     RECT  67.504 107.76 68.531 108.6 ;
     RECT  67.565 106.464 68.749 106.488 ;
     RECT  68.749 106.464 68.867 106.632 ;
     RECT  68.821 126.48 68.933 126.504 ;
     RECT  68.867 106.464 68.969 106.488 ;
     RECT  68.485 111.744 68.969 111.768 ;
     RECT  67.763 104.304 69.101 104.328 ;
     RECT  67.889 0.192 69.157 4.2 ;
     RECT  67.504 110.16 69.157 110.184 ;
     RECT  69.101 104.304 69.185 104.904 ;
     RECT  69.116 105.888 69.203 105.912 ;
     RECT  69.157 0.144 69.299 4.2 ;
     RECT  69.185 104.304 69.329 104.376 ;
     RECT  69.157 109.968 69.397 110.184 ;
     RECT  69.397 109.872 69.509 110.664 ;
     RECT  69.329 104.352 69.539 104.376 ;
     RECT  68.531 108.576 69.541 108.6 ;
     RECT  69.509 109.968 69.545 110.664 ;
     RECT  69.541 107.712 69.587 108.6 ;
     RECT  69.587 107.712 69.797 107.736 ;
     RECT  69.793 105.456 69.877 105.48 ;
     RECT  69.545 110.016 70.237 110.664 ;
     RECT  69.461 112.032 70.268 112.296 ;
     RECT  70.268 112.032 70.355 112.584 ;
     RECT  70.441 111.744 70.547 111.768 ;
     RECT  70.237 110.304 70.661 110.664 ;
     RECT  70.309 114 70.661 114.024 ;
     RECT  67.745 95.616 70.693 95.64 ;
     RECT  70.693 95.616 70.733 95.736 ;
     RECT  70.873 117.984 70.957 118.536 ;
     RECT  70.469 115.104 71.053 115.128 ;
     RECT  71.053 114.528 71.161 115.128 ;
     RECT  70.957 118.512 71.18 118.536 ;
     RECT  71.161 114.528 71.219 115.752 ;
     RECT  71.219 114.576 71.245 115.752 ;
     RECT  71.18 118.512 71.267 119.16 ;
     RECT  67.504 94.32 71.269 94.344 ;
     RECT  68.321 102.096 71.269 102.12 ;
     RECT  71.245 114.576 71.281 115.176 ;
     RECT  71.269 94.32 71.315 94.584 ;
     RECT  71.269 102.096 71.315 102.6 ;
     RECT  69.299 0.288 71.485 4.2 ;
     RECT  70.661 110.304 71.516 110.328 ;
     RECT  71.557 127.056 71.593 127.08 ;
     RECT  71.315 102.576 71.603 102.6 ;
     RECT  71.516 109.632 71.603 110.328 ;
     RECT  71.603 109.968 71.633 110.328 ;
     RECT  71.809 113.52 71.845 113.544 ;
     RECT  71.557 116.928 72.133 116.952 ;
     RECT  71.317 121.152 72.277 121.176 ;
     RECT  72.133 116.928 72.284 117 ;
     RECT  72.284 116.928 72.325 117.192 ;
     RECT  71.267 118.512 72.325 119.112 ;
     RECT  72.325 116.928 72.421 119.112 ;
     RECT  72.229 123.744 72.469 123.768 ;
     RECT  71.593 127.008 72.565 127.08 ;
     RECT  71.485 0.096 72.608 4.2 ;
     RECT  67.504 5.232 72.608 7.992 ;
     RECT  67.504 11.808 72.608 11.832 ;
     RECT  67.504 82.944 72.608 82.968 ;
     RECT  71.315 94.56 72.608 94.584 ;
     RECT  70.733 95.712 72.608 95.736 ;
     RECT  71.633 109.968 72.608 109.992 ;
     RECT  71.845 113.424 72.608 113.544 ;
     RECT  71.281 114.576 72.608 114.6 ;
     RECT  72.421 116.928 72.608 119.16 ;
     RECT  72.277 120.24 72.608 121.176 ;
     RECT  72.469 123.216 72.608 123.768 ;
     RECT  72.469 125.952 72.608 125.976 ;
     RECT  72.565 127.008 72.608 127.656 ;
     RECT  72.608 0.096 72.611 127.656 ;
     RECT  72.611 0.192 72.785 127.656 ;
     RECT  72.785 0.192 72.904 127.182 ;
     RECT  70.165 129.456 72.947 129.48 ;
     RECT  72.904 125.952 72.965 126.6 ;
     RECT  72.904 112.848 73.001 113.544 ;
     RECT  73.001 112.848 73.139 112.872 ;
     RECT  72.904 123.216 73.145 123.768 ;
     RECT  72.904 109.68 73.18 111.48 ;
     RECT  73.18 109.68 73.283 110.616 ;
     RECT  72.904 116.304 73.657 117.432 ;
     RECT  72.904 120.24 73.897 120.888 ;
     RECT  72.965 126.576 73.973 126.6 ;
     RECT  73.897 120.24 74.009 121.56 ;
     RECT  73.145 123.216 74.045 123.24 ;
     RECT  73.657 116.976 74.401 117.432 ;
     RECT  74.009 120.24 74.473 120.264 ;
     RECT  74.245 129.456 74.477 129.48 ;
     RECT  74.473 119.712 74.627 120.264 ;
     RECT  73.909 127.632 74.657 127.656 ;
     RECT  74.009 121.536 74.677 121.56 ;
     RECT  74.221 122.544 74.677 122.568 ;
     RECT  74.677 121.536 74.723 122.568 ;
     RECT  73.283 109.68 74.905 109.704 ;
     RECT  74.723 121.728 74.963 122.568 ;
     RECT  74.627 120.24 74.972 120.264 ;
     RECT  74.905 109.632 74.977 109.704 ;
     RECT  74.963 122.496 75.02 122.568 ;
     RECT  74.401 116.976 75.059 117.816 ;
     RECT  74.972 120.24 75.059 120.696 ;
     RECT  75.013 123.984 75.061 124.008 ;
     RECT  75.059 120.24 75.089 120.456 ;
     RECT  75.02 122.496 75.107 122.856 ;
     RECT  74.917 126.432 75.253 126.456 ;
     RECT  75.107 122.496 75.313 122.712 ;
     RECT  74.977 109.632 75.397 109.944 ;
     RECT  72.904 95.712 75.404 95.736 ;
     RECT  75.397 109.632 75.404 110.856 ;
     RECT  74.797 106.8 75.445 106.824 ;
     RECT  75.445 104.832 75.481 104.856 ;
     RECT  75.445 105.84 75.481 106.824 ;
     RECT  75.404 95.712 75.491 96.072 ;
     RECT  75.404 99.168 75.491 99.192 ;
     RECT  75.404 108.192 75.491 110.856 ;
     RECT  75.491 109.632 75.517 110.856 ;
     RECT  72.904 94.56 75.553 94.584 ;
     RECT  75.491 95.712 75.553 95.832 ;
     RECT  75.253 126.432 75.629 127.08 ;
     RECT  75.553 94.56 75.637 95.832 ;
     RECT  75.581 128.784 75.665 128.808 ;
     RECT  75.445 97.92 75.701 97.944 ;
     RECT  75.637 94.56 75.779 94.68 ;
     RECT  75.637 95.712 75.809 95.832 ;
     RECT  75.481 104.832 75.827 106.824 ;
     RECT  75.157 92.112 75.841 92.136 ;
     RECT  75.733 93.216 75.841 93.24 ;
     RECT  75.445 101.28 75.845 101.304 ;
     RECT  75.827 105.264 75.845 106.824 ;
     RECT  75.517 109.632 75.877 111.048 ;
     RECT  75.013 115.68 75.877 115.704 ;
     RECT  75.629 126.432 75.953 126.456 ;
     RECT  75.98 89.088 76.021 89.112 ;
     RECT  75.781 103.728 76.061 103.752 ;
     RECT  76.021 89.088 76.067 89.976 ;
     RECT  76.067 89.52 76.165 89.976 ;
     RECT  75.877 109.632 76.201 111.096 ;
     RECT  75.841 92.112 76.211 93.24 ;
     RECT  76.165 89.52 76.249 90.6 ;
     RECT  75.769 113.856 76.268 113.88 ;
     RECT  75.779 94.656 76.307 94.68 ;
     RECT  76.268 113.28 76.309 113.88 ;
     RECT  75.877 115.68 76.309 116.568 ;
     RECT  76.211 92.112 76.313 92.664 ;
     RECT  75.845 105.264 76.349 106.152 ;
     RECT  76.309 115.68 76.357 116.76 ;
     RECT  75.059 117.792 76.357 117.816 ;
     RECT  75.925 129.456 76.385 129.48 ;
     RECT  75.313 122.496 76.453 122.52 ;
     RECT  76.357 115.68 76.457 117.816 ;
     RECT  76.273 107.136 76.493 107.16 ;
     RECT  76.261 100.32 76.549 100.44 ;
     RECT  76.525 102.384 76.549 102.408 ;
     RECT  76.457 117.792 76.633 117.816 ;
     RECT  76.349 105.408 76.673 106.152 ;
     RECT  76.165 119.136 76.741 119.16 ;
     RECT  76.249 89.52 76.781 89.976 ;
     RECT  76.313 92.112 76.781 92.136 ;
     RECT  75.841 98.544 76.849 98.664 ;
     RECT  75.061 123.984 76.853 124.68 ;
     RECT  76.549 100.272 76.885 100.44 ;
     RECT  76.633 117.792 76.885 118.152 ;
     RECT  76.741 119.136 76.885 119.256 ;
     RECT  76.309 113.28 76.921 114.024 ;
     RECT  75.089 120.432 76.921 120.456 ;
     RECT  76.201 109.632 76.961 111.384 ;
     RECT  76.921 120.432 76.981 121.32 ;
     RECT  76.453 122.448 76.981 122.52 ;
     RECT  76.549 102.384 76.993 102.6 ;
     RECT  76.981 120.24 77.137 122.52 ;
     RECT  76.849 98.544 77.209 98.808 ;
     RECT  76.021 87.744 77.245 87.768 ;
     RECT  76.673 105.744 77.269 106.152 ;
     RECT  76.921 113.184 77.281 114.024 ;
     RECT  77.245 87.216 77.317 87.768 ;
     RECT  77.281 113.136 77.353 114.024 ;
     RECT  76.885 100.272 77.425 100.92 ;
     RECT  77.084 96.96 77.461 96.984 ;
     RECT  77.209 98.016 77.461 98.808 ;
     RECT  76.457 115.68 77.468 116.76 ;
     RECT  76.885 117.792 77.468 119.256 ;
     RECT  77.101 126.576 77.569 126.6 ;
     RECT  72.904 0.192 77.605 4.2 ;
     RECT  77.353 113.136 77.713 114.12 ;
     RECT  75.809 95.712 77.785 95.736 ;
     RECT  77.461 96.96 77.785 98.808 ;
     RECT  77.425 100.176 77.797 100.92 ;
     RECT  77.269 105.744 77.821 107.064 ;
     RECT  77.641 108.528 77.821 108.552 ;
     RECT  77.569 126.576 77.845 126.648 ;
     RECT  77.713 112.848 77.893 114.12 ;
     RECT  77.468 115.68 77.929 119.256 ;
     RECT  77.137 120.24 77.929 122.952 ;
     RECT  77.821 105.744 77.965 108.552 ;
     RECT  77.605 0.096 77.987 4.2 ;
     RECT  77.845 126.576 77.987 127.608 ;
     RECT  76.961 109.632 78.001 111.096 ;
     RECT  77.893 112.704 78.001 114.12 ;
     RECT  77.987 0.288 78.008 4.2 ;
     RECT  72.904 5.232 78.008 7.992 ;
     RECT  72.904 11.808 78.008 11.832 ;
     RECT  72.904 82.944 78.008 82.968 ;
     RECT  77.317 87.216 78.008 88.2 ;
     RECT  77.785 90.048 78.008 90.552 ;
     RECT  77.317 94.032 78.008 94.056 ;
     RECT  77.785 95.376 78.008 95.736 ;
     RECT  77.785 96.96 78.008 98.904 ;
     RECT  77.797 100.08 78.008 100.92 ;
     RECT  76.993 102.384 78.008 102.984 ;
     RECT  77.965 105.168 78.008 108.552 ;
     RECT  78.001 109.632 78.008 114.12 ;
     RECT  77.929 115.68 78.008 122.952 ;
     RECT  76.853 123.984 78.008 124.008 ;
     RECT  77.987 126.576 78.008 127.452 ;
     RECT  78.008 0.288 78.112 127.452 ;
     RECT  78.112 0.288 78.304 127.182 ;
     RECT  78.304 104.544 78.365 113.976 ;
     RECT  78.277 129.456 78.419 129.48 ;
     RECT  78.304 87.168 78.481 88.968 ;
     RECT  78.304 115.584 78.509 119.976 ;
     RECT  78.365 108 78.545 113.976 ;
     RECT  78.481 87.792 78.659 88.968 ;
     RECT  78.509 115.584 78.659 116.856 ;
     RECT  78.509 117.888 78.689 119.976 ;
     RECT  78.659 87.792 78.707 88.824 ;
     RECT  78.304 96.864 78.905 100.92 ;
     RECT  78.545 110.496 78.905 113.976 ;
     RECT  78.365 104.544 78.947 106.488 ;
     RECT  78.707 87.792 78.995 88.632 ;
     RECT  78.304 93.312 79.085 94.056 ;
     RECT  78.905 98.064 79.139 100.92 ;
     RECT  79.139 99.792 79.193 100.92 ;
     RECT  78.304 82.656 79.235 82.968 ;
     RECT  78.304 0.288 79.253 4.2 ;
     RECT  78.304 102 79.265 102.984 ;
     RECT  78.947 104.544 79.265 106.296 ;
     RECT  78.659 115.728 79.265 116.856 ;
     RECT  78.905 96.864 79.273 96.888 ;
     RECT  79.265 102.096 79.273 102.984 ;
     RECT  79.193 99.936 79.283 100.92 ;
     RECT  78.304 121.584 79.285 122.952 ;
     RECT  78.304 123.984 79.285 125.4 ;
     RECT  78.304 91.728 79.292 91.752 ;
     RECT  79.265 115.728 79.301 115.752 ;
     RECT  79.292 91.536 79.333 91.752 ;
     RECT  79.285 121.584 79.333 125.4 ;
     RECT  79.253 0.096 79.337 4.2 ;
     RECT  79.333 121.44 79.337 125.4 ;
     RECT  79.333 91.536 79.379 91.848 ;
     RECT  79.265 104.544 79.523 105.96 ;
     RECT  79.139 98.064 79.553 98.616 ;
     RECT  79.265 116.832 79.58 116.856 ;
     RECT  78.689 117.888 79.58 119.304 ;
     RECT  79.379 91.824 79.621 91.848 ;
     RECT  79.085 93.312 79.621 93.528 ;
     RECT  78.545 108 79.657 109.512 ;
     RECT  78.905 110.496 79.657 111.096 ;
     RECT  78.304 95.376 79.661 95.4 ;
     RECT  79.58 116.832 79.661 119.304 ;
     RECT  79.661 117.12 79.667 119.304 ;
     RECT  79.337 124.848 79.667 125.4 ;
     RECT  79.621 91.824 79.697 93.528 ;
     RECT  79.697 91.824 79.705 93.336 ;
     RECT  78.304 126.432 79.729 126.6 ;
     RECT  79.621 129.408 79.763 129.432 ;
     RECT  79.337 121.44 79.769 123.672 ;
     RECT  79.667 117.216 79.801 119.304 ;
     RECT  79.273 102.144 79.837 102.984 ;
     RECT  79.801 117.216 79.945 119.448 ;
     RECT  79.729 126.432 79.985 127.128 ;
     RECT  79.945 117.216 80.021 119.784 ;
     RECT  79.705 92.928 80.029 93.336 ;
     RECT  79.705 91.824 80.093 91.848 ;
     RECT  80.029 93.216 80.201 93.336 ;
     RECT  78.995 88.608 80.269 88.632 ;
     RECT  78.304 90.528 80.269 90.552 ;
     RECT  80.269 90.528 80.309 90.648 ;
     RECT  79.283 99.936 80.341 100.488 ;
     RECT  79.837 102.144 80.341 103.512 ;
     RECT  79.553 98.064 80.381 98.088 ;
     RECT  80.341 102.048 80.389 103.512 ;
     RECT  80.269 88.608 80.417 89.544 ;
     RECT  78.905 112.8 80.424 113.976 ;
     RECT  80.341 99.168 80.435 100.488 ;
     RECT  79.523 105.6 80.449 105.96 ;
     RECT  79.657 108 80.449 111.096 ;
     RECT  80.021 117.408 80.449 119.784 ;
     RECT  79.523 104.544 80.485 104.568 ;
     RECT  80.449 105.6 80.485 106.392 ;
     RECT  80.424 112.704 80.485 113.976 ;
     RECT  80.485 104.544 80.489 106.392 ;
     RECT  80.435 99.168 80.525 99.72 ;
     RECT  80.389 101.568 80.561 103.512 ;
     RECT  80.417 89.52 80.677 89.544 ;
     RECT  79.667 124.848 80.705 124.872 ;
     RECT  80.489 104.544 80.741 105.24 ;
     RECT  80.489 106.368 80.773 106.392 ;
     RECT  80.449 107.376 80.773 111.096 ;
     RECT  80.773 106.368 80.777 111.096 ;
     RECT  80.732 96.96 80.819 96.984 ;
     RECT  80.777 106.512 80.917 111.096 ;
     RECT  80.485 112.704 80.917 114.024 ;
     RECT  80.201 93.216 80.957 93.24 ;
     RECT  80.917 106.512 80.957 114.024 ;
     RECT  80.293 115.728 80.957 115.752 ;
     RECT  80.449 117.408 81.025 119.976 ;
     RECT  80.309 90.624 81.029 90.648 ;
     RECT  80.773 95.712 81.317 95.736 ;
     RECT  80.965 127.632 81.317 127.656 ;
     RECT  81.277 94.656 81.361 94.68 ;
     RECT  80.957 112.848 81.533 114.024 ;
     RECT  81.349 124.992 81.565 125.016 ;
     RECT  80.593 126.096 81.565 126.12 ;
     RECT  81.025 117.264 81.637 119.976 ;
     RECT  79.769 121.44 81.637 122.856 ;
     RECT  81.529 128.832 81.683 128.856 ;
     RECT  80.741 105.216 81.817 105.24 ;
     RECT  80.957 106.512 81.817 111.864 ;
     RECT  81.637 117.024 81.853 119.976 ;
     RECT  81.637 121.008 81.853 122.856 ;
     RECT  81.853 117.024 81.925 122.856 ;
     RECT  81.817 105.216 82.019 111.864 ;
     RECT  81.889 127.68 82.019 127.704 ;
     RECT  81.565 124.992 82.033 126.12 ;
     RECT  82.033 124.992 82.069 126.312 ;
     RECT  82.019 105.216 82.109 110.904 ;
     RECT  82.028 71.232 82.115 71.256 ;
     RECT  80.561 102.144 82.165 103.512 ;
     RECT  81.925 116.976 82.177 122.856 ;
     RECT  82.069 124.992 82.181 126.6 ;
     RECT  79.235 82.656 82.213 82.68 ;
     RECT  81.533 112.848 82.213 113.976 ;
     RECT  82.165 101.904 82.252 103.8 ;
     RECT  82.172 84.192 82.259 84.216 ;
     RECT  82.181 124.992 82.285 126.504 ;
     RECT  82.252 101.904 82.289 103.08 ;
     RECT  82.213 86.592 82.297 86.616 ;
     RECT  82.289 102.144 82.307 103.08 ;
     RECT  82.277 128.784 82.361 128.808 ;
     RECT  82.285 124.944 82.393 126.504 ;
     RECT  82.177 116.88 82.397 122.856 ;
     RECT  81.997 115.392 82.465 115.416 ;
     RECT  82.397 121.44 82.573 122.856 ;
     RECT  82.213 80.64 82.597 80.664 ;
     RECT  82.393 124.896 82.609 126.504 ;
     RECT  82.213 112.512 82.681 113.976 ;
     RECT  82.465 115.344 82.681 115.416 ;
     RECT  82.681 112.512 82.861 115.416 ;
     RECT  82.397 116.88 82.861 120.264 ;
     RECT  82.897 128.208 83.027 128.232 ;
     RECT  82.609 124.848 83.041 126.504 ;
     RECT  79.337 0.288 83.077 4.2 ;
     RECT  78.304 5.232 83.077 7.992 ;
     RECT  82.109 109.536 83.173 110.904 ;
     RECT  82.861 112.512 83.185 120.264 ;
     RECT  83.077 0.288 83.221 7.992 ;
     RECT  83.221 0.096 83.363 7.992 ;
     RECT  83.285 129.456 83.369 129.48 ;
     RECT  83.363 0.192 83.408 7.992 ;
     RECT  78.304 11.808 83.408 11.832 ;
     RECT  82.681 76.368 83.408 76.392 ;
     RECT  82.069 77.808 83.408 77.832 ;
     RECT  82.597 80.016 83.408 80.664 ;
     RECT  82.213 82.656 83.408 83.16 ;
     RECT  82.213 89.712 83.408 89.736 ;
     RECT  82.645 100.848 83.408 100.872 ;
     RECT  82.307 102.144 83.408 102.84 ;
     RECT  82.109 105.216 83.408 108.168 ;
     RECT  83.173 109.392 83.408 110.904 ;
     RECT  83.185 112.464 83.408 120.264 ;
     RECT  82.573 121.44 83.408 123.144 ;
     RECT  83.041 124.224 83.408 126.504 ;
     RECT  83.408 0.192 83.699 127.656 ;
     RECT  83.699 0.24 83.704 127.656 ;
     RECT  83.704 108.144 83.981 111.144 ;
     RECT  83.704 127.104 83.989 127.656 ;
     RECT  83.704 120.864 84.323 126.072 ;
     RECT  83.704 116.16 84.419 116.28 ;
     RECT  83.704 104.784 84.485 107.112 ;
     RECT  84.323 120.864 84.485 124.008 ;
     RECT  84.485 120.864 84.593 123.72 ;
     RECT  83.989 127.104 84.629 128.232 ;
     RECT  84.593 121.152 84.665 123.72 ;
     RECT  83.704 119.568 84.697 119.592 ;
     RECT  83.704 114.576 84.707 115.176 ;
     RECT  84.697 119.568 84.769 120.072 ;
     RECT  84.707 115.152 84.805 115.176 ;
     RECT  83.704 117.888 84.805 118.488 ;
     RECT  84.805 117.408 84.841 118.488 ;
     RECT  84.769 119.52 84.841 120.072 ;
     RECT  84.841 15.6 84.877 15.624 ;
     RECT  84.323 125.136 84.953 126.072 ;
     RECT  84.805 115.152 85.043 115.752 ;
     RECT  84.841 117.408 85.045 120.072 ;
     RECT  84.665 122.448 85.105 123.72 ;
     RECT  83.704 100.848 85.201 100.872 ;
     RECT  83.704 102.144 85.201 102.216 ;
     RECT  84.485 106.368 85.201 107.112 ;
     RECT  83.981 110.592 85.201 110.904 ;
     RECT  83.704 112.176 85.201 113.208 ;
     RECT  85.105 122.448 85.241 122.568 ;
     RECT  85.201 110.592 85.273 113.208 ;
     RECT  85.273 110.592 85.379 113.448 ;
     RECT  85.201 100.848 85.477 102.216 ;
     RECT  84.877 15.072 85.489 15.624 ;
     RECT  84.629 127.632 85.493 128.232 ;
     RECT  85.477 100.272 85.523 102.216 ;
     RECT  85.105 123.696 85.525 123.72 ;
     RECT  84.953 125.136 85.525 126.024 ;
     RECT  85.045 116.832 85.529 120.072 ;
     RECT  85.201 106.368 85.597 107.16 ;
     RECT  85.597 106.128 85.601 107.16 ;
     RECT  85.529 117.408 85.628 120.072 ;
     RECT  83.981 108.144 85.633 109.56 ;
     RECT  85.379 110.592 85.633 112.632 ;
     RECT  84.553 129.504 85.661 129.528 ;
     RECT  85.628 117.408 85.715 120.12 ;
     RECT  84.485 104.784 85.763 104.808 ;
     RECT  85.601 107.136 85.813 107.16 ;
     RECT  85.633 108.144 85.813 112.632 ;
     RECT  85.523 100.272 85.853 100.872 ;
     RECT  85.601 106.128 85.889 106.152 ;
     RECT  85.661 129.456 85.993 129.528 ;
     RECT  85.525 123.696 85.997 126.024 ;
     RECT  83.704 0.24 86.005 4.2 ;
     RECT  85.489 27.744 86.065 27.768 ;
     RECT  85.489 28.752 86.065 28.776 ;
     RECT  85.813 107.136 86.069 112.632 ;
     RECT  85.997 123.696 86.069 125.976 ;
     RECT  85.993 128.256 86.077 129.528 ;
     RECT  85.715 117.408 86.099 120.072 ;
     RECT  83.704 80.016 86.141 80.04 ;
     RECT  85.241 122.544 86.209 122.568 ;
     RECT  86.069 123.696 86.249 125.592 ;
     RECT  85.523 101.856 86.285 102.216 ;
     RECT  86.209 122.544 86.321 122.664 ;
     RECT  86.321 122.64 86.339 122.664 ;
     RECT  85.043 115.728 86.357 115.752 ;
     RECT  84.665 121.152 86.38 121.176 ;
     RECT  86.069 107.136 86.387 109.416 ;
     RECT  86.077 128.256 86.387 128.28 ;
     RECT  86.069 110.688 86.389 112.632 ;
     RECT  86.387 107.136 86.393 107.976 ;
     RECT  86.249 123.792 86.393 125.592 ;
     RECT  86.393 107.952 86.428 107.976 ;
     RECT  86.389 110.688 86.429 112.824 ;
     RECT  86.429 112.464 86.465 112.824 ;
     RECT  86.393 123.792 86.537 123.816 ;
     RECT  83.704 11.808 86.605 11.832 ;
     RECT  86.005 0.096 86.609 4.2 ;
     RECT  86.099 117.6 86.609 120.072 ;
     RECT  86.317 114.576 86.629 114.6 ;
     RECT  86.065 22.896 86.641 22.92 ;
     RECT  86.065 27.744 86.641 28.776 ;
     RECT  86.065 29.76 86.641 29.784 ;
     RECT  86.065 53.76 86.641 55.08 ;
     RECT  83.704 67.968 86.641 69 ;
     RECT  86.065 87.168 86.641 88.728 ;
     RECT  83.704 89.712 86.641 89.736 ;
     RECT  86.387 109.392 86.645 109.416 ;
     RECT  86.629 113.856 86.675 114.6 ;
     RECT  85.853 100.848 86.677 100.872 ;
     RECT  86.285 101.856 86.677 101.88 ;
     RECT  86.609 117.792 86.717 120.072 ;
     RECT  86.429 110.688 86.753 111.336 ;
     RECT  86.717 117.792 86.753 119.592 ;
     RECT  86.393 125.088 86.789 125.592 ;
     RECT  86.753 110.688 86.825 110.712 ;
     RECT  86.675 113.856 86.825 113.88 ;
     RECT  86.753 118.368 86.933 119.592 ;
     RECT  86.677 100.848 87.059 101.88 ;
     RECT  86.465 112.8 87.077 112.824 ;
     RECT  86.677 128.208 87.085 128.232 ;
     RECT  86.789 125.184 87.109 125.592 ;
     RECT  86.933 118.368 87.113 118.488 ;
     RECT  85.489 14.832 87.181 15.624 ;
     RECT  86.641 53.76 87.181 56.088 ;
     RECT  86.933 119.568 87.185 119.592 ;
     RECT  87.109 125.184 87.221 125.928 ;
     RECT  87.181 53.76 87.253 56.568 ;
     RECT  86.641 84.672 87.253 84.696 ;
     RECT  86.641 87.168 87.253 89.736 ;
     RECT  86.065 21.648 87.289 21.672 ;
     RECT  86.641 22.896 87.289 23.448 ;
     RECT  86.641 27.744 87.289 30.024 ;
     RECT  86.641 31.248 87.289 31.272 ;
     RECT  87.221 125.472 87.293 125.928 ;
     RECT  87.289 21.648 87.325 23.976 ;
     RECT  87.253 73.008 87.325 74.04 ;
     RECT  87.253 75.024 87.325 75.576 ;
     RECT  87.253 95.04 87.325 95.064 ;
     RECT  87.113 118.464 87.365 118.488 ;
     RECT  87.253 83.904 87.757 84.696 ;
     RECT  86.605 11.808 87.793 12.552 ;
     RECT  87.325 21.648 87.793 24.216 ;
     RECT  87.289 27.744 87.793 31.56 ;
     RECT  87.289 38.592 87.793 38.616 ;
     RECT  87.253 53.76 87.793 57.336 ;
     RECT  86.641 67.2 87.793 69 ;
     RECT  87.325 73.008 87.793 75.576 ;
     RECT  87.253 87.168 87.793 89.976 ;
     RECT  87.325 95.04 87.793 95.304 ;
     RECT  86.929 102.864 87.793 102.888 ;
     RECT  87.793 92.496 87.829 92.52 ;
     RECT  87.356 128.256 88.081 128.28 ;
     RECT  88.081 128.256 88.117 128.424 ;
     RECT  87.793 10.032 88.333 12.552 ;
     RECT  87.181 14.064 88.333 15.624 ;
     RECT  86.029 16.608 88.333 16.632 ;
     RECT  87.793 21.648 88.333 24.456 ;
     RECT  87.793 27.744 88.333 32.28 ;
     RECT  87.793 34.8 88.333 34.824 ;
     RECT  87.793 37.584 88.333 38.616 ;
     RECT  87.793 53.76 88.333 58.344 ;
     RECT  87.793 67.2 88.333 70.248 ;
     RECT  87.793 73.008 88.333 75.816 ;
     RECT  87.757 83.136 88.333 84.696 ;
     RECT  87.293 125.904 88.405 125.928 ;
     RECT  88.009 117.264 88.441 117.288 ;
     RECT  87.793 87.168 88.873 90.504 ;
     RECT  87.793 91.488 88.873 91.512 ;
     RECT  87.793 102.864 88.873 103.128 ;
     RECT  88.405 111.216 88.873 111.24 ;
     RECT  88.441 117.264 88.873 117.576 ;
     RECT  88.261 118.56 88.873 118.584 ;
     RECT  88.333 14.064 88.909 17.112 ;
     RECT  88.333 18.384 88.909 18.408 ;
     RECT  88.333 20.112 88.909 20.664 ;
     RECT  88.333 21.648 88.909 25.464 ;
     RECT  85.489 26.736 88.909 26.76 ;
     RECT  88.333 27.744 88.909 33.336 ;
     RECT  87.757 36.576 88.909 36.6 ;
     RECT  88.333 37.584 88.909 40.152 ;
     RECT  88.333 44.16 88.909 44.952 ;
     RECT  88.333 48.96 88.909 49.992 ;
     RECT  88.333 51.024 88.909 51.048 ;
     RECT  88.333 53.76 88.909 58.632 ;
     RECT  88.873 62.112 88.909 62.136 ;
     RECT  88.333 67.2 88.909 70.488 ;
     RECT  88.873 87.168 88.909 91.512 ;
     RECT  87.829 92.496 88.909 92.76 ;
     RECT  87.793 93.744 88.909 93.768 ;
     RECT  87.059 100.848 88.909 100.872 ;
     RECT  87.059 101.856 88.909 101.88 ;
     RECT  88.873 102.864 88.909 103.896 ;
     RECT  88.405 125.376 88.909 125.928 ;
     RECT  88.117 127.92 88.909 128.424 ;
     RECT  86.609 0.24 89.129 4.2 ;
     RECT  88.873 117.264 89.305 120.072 ;
     RECT  89.269 121.056 89.305 121.608 ;
     RECT  88.909 114.48 89.377 114.504 ;
     RECT  89.305 117.264 89.413 121.608 ;
     RECT  88.333 10.032 89.449 12.84 ;
     RECT  88.909 14.064 89.449 18.408 ;
     RECT  88.909 43.68 89.449 44.952 ;
     RECT  88.909 45.936 89.449 45.96 ;
     RECT  88.333 73.008 89.449 76.584 ;
     RECT  88.909 80.352 89.449 80.856 ;
     RECT  88.333 81.888 89.449 81.912 ;
     RECT  88.909 96.816 89.449 96.84 ;
     RECT  89.377 98.064 89.449 98.088 ;
     RECT  89.341 99.312 89.449 99.336 ;
     RECT  88.909 100.848 89.449 103.896 ;
     RECT  89.053 109.2 89.449 109.224 ;
     RECT  88.873 110.208 89.449 111.24 ;
     RECT  88.909 112.464 89.449 112.488 ;
     RECT  89.377 114.48 89.449 114.792 ;
     RECT  89.413 117.024 89.449 121.848 ;
     RECT  89.413 123.36 89.449 123.384 ;
     RECT  89.449 10.032 89.485 18.408 ;
     RECT  88.909 19.392 89.485 25.464 ;
     RECT  88.909 26.448 89.485 33.576 ;
     RECT  88.333 34.8 89.485 35.352 ;
     RECT  88.909 36.576 89.485 40.92 ;
     RECT  88.333 42.384 89.485 42.408 ;
     RECT  89.449 43.68 89.485 45.96 ;
     RECT  88.909 48.96 89.485 51.768 ;
     RECT  88.909 53.76 89.485 59.88 ;
     RECT  88.909 62.112 89.485 65.688 ;
     RECT  88.909 67.2 89.485 71.256 ;
     RECT  89.449 73.008 89.485 77.064 ;
     RECT  88.909 78.816 89.485 78.84 ;
     RECT  89.449 80.352 89.485 81.912 ;
     RECT  88.333 82.896 89.485 84.696 ;
     RECT  88.909 87.168 89.485 92.76 ;
     RECT  88.909 93.744 89.485 94.056 ;
     RECT  87.793 95.04 89.485 95.784 ;
     RECT  89.449 96.816 89.485 98.328 ;
     RECT  89.449 99.312 89.485 105.912 ;
     RECT  89.449 106.896 89.485 107.928 ;
     RECT  89.449 109.2 89.485 111.24 ;
     RECT  89.449 116.016 89.485 121.848 ;
     RECT  89.449 123.12 89.485 123.864 ;
     RECT  88.909 125.136 89.485 125.928 ;
     RECT  86.077 129.504 89.509 129.528 ;
     RECT  89.509 129.408 89.555 129.528 ;
     RECT  89.555 129.408 89.651 129.432 ;
     RECT  89.485 115.776 89.737 125.928 ;
     RECT  88.909 127.152 89.737 128.424 ;
     RECT  89.737 115.776 89.773 128.424 ;
     RECT  89.485 10.032 90.025 41.4 ;
     RECT  89.485 42.384 90.025 52.056 ;
     RECT  89.485 53.76 90.025 61.128 ;
     RECT  89.485 62.112 90.025 77.832 ;
     RECT  89.485 96.816 90.025 107.928 ;
     RECT  89.485 109.2 90.025 111.48 ;
     RECT  89.449 112.464 90.025 114.792 ;
     RECT  89.773 115.776 90.025 128.952 ;
     RECT  89.129 0.672 90.061 4.2 ;
     RECT  83.704 5.232 90.061 7.992 ;
     RECT  90.025 10.032 90.061 52.056 ;
     RECT  90.025 53.76 90.061 77.832 ;
     RECT  89.485 78.816 90.061 79.368 ;
     RECT  89.485 80.352 90.061 84.936 ;
     RECT  89.485 87.168 90.061 95.784 ;
     RECT  90.025 96.816 90.061 128.952 ;
     RECT  90.061 0.672 90.684 128.952 ;
     RECT  90.684 117.696 90.713 117.72 ;
     RECT  90.684 125.52 90.713 125.544 ;
    LAYER M5 ;
     RECT  0.768 0.016 87.432 0.179 ;
     RECT  0.768 0.179 85.704 0.515 ;
     RECT  0.768 0.515 77.64 0.563 ;
     RECT  78.624 0.515 85.704 0.563 ;
     RECT  0.768 0.563 77.304 1.763 ;
     RECT  3.792 1.763 3.816 1.811 ;
     RECT  9.888 1.763 77.304 2.137 ;
     RECT  78.624 0.563 82.008 2.137 ;
     RECT  82.992 0.563 83.304 2.137 ;
     RECT  84.336 0.563 85.704 2.137 ;
     RECT  0.768 1.763 0.792 2.291 ;
     RECT  5.28 1.763 5.88 2.291 ;
     RECT  7.536 1.763 8.232 2.291 ;
     RECT  9.888 2.137 82.008 2.291 ;
     RECT  86.688 0.179 87.432 2.291 ;
     RECT  1.776 1.763 2.808 2.915 ;
     RECT  5.28 2.291 5.304 3.203 ;
     RECT  86.688 2.291 87.048 3.443 ;
     RECT  2.112 2.915 2.808 4.019 ;
     RECT  11.232 2.291 11.928 4.261 ;
     RECT  13.104 2.291 82.008 4.261 ;
     RECT  7.8 2.291 8.112 4.645 ;
     RECT  7.8 4.645 8.712 5.077 ;
     RECT  6.816 5.077 8.712 5.125 ;
     RECT  2.4 4.019 2.808 5.365 ;
     RECT  6.816 5.125 9.672 5.507 ;
     RECT  6.816 5.507 8.712 5.747 ;
     RECT  7.8 5.747 8.712 6.805 ;
     RECT  7.8 6.805 8.808 7.765 ;
     RECT  5.808 7.765 5.832 8.581 ;
     RECT  5.568 8.581 5.832 8.821 ;
     RECT  5.568 8.821 6.36 9.107 ;
     RECT  11.232 4.261 82.008 10.309 ;
     RECT  6.336 9.107 6.36 10.501 ;
     RECT  7.584 7.765 8.808 10.501 ;
     RECT  6.336 10.501 8.808 10.643 ;
     RECT  6.336 10.643 8.232 11.411 ;
     RECT  10.8 10.309 82.008 12.517 ;
     RECT  6.864 11.411 8.232 12.563 ;
     RECT  10.752 12.517 82.008 13.715 ;
     RECT  9.696 14.197 9.72 14.533 ;
     RECT  11.232 13.715 82.008 15.443 ;
     RECT  9.552 14.533 9.72 15.731 ;
     RECT  12.672 15.443 14.184 16.115 ;
     RECT  11.232 15.443 11.256 16.501 ;
     RECT  10.896 16.501 11.256 16.643 ;
     RECT  10.896 16.643 10.92 16.933 ;
     RECT  10.848 16.933 10.92 17.699 ;
     RECT  12.672 16.115 13.512 18.757 ;
     RECT  15.936 15.443 82.008 18.851 ;
     RECT  16.608 18.851 16.632 19.283 ;
     RECT  12.24 18.757 13.512 19.477 ;
     RECT  14.736 18.133 14.76 19.477 ;
     RECT  2.4 5.365 3.144 21.109 ;
     RECT  12.24 19.477 14.76 21.155 ;
     RECT  17.952 18.851 19.368 21.155 ;
     RECT  17.952 21.155 19.32 21.637 ;
     RECT  12.24 21.155 14.28 22.645 ;
     RECT  17.088 21.637 19.32 22.835 ;
     RECT  20.448 18.851 82.008 23.411 ;
     RECT  17.952 22.835 19.32 23.987 ;
     RECT  20.448 23.411 22.728 23.987 ;
     RECT  18.48 23.987 19.32 24.515 ;
     RECT  20.448 23.987 22.056 24.515 ;
     RECT  16.032 21.973 16.056 24.659 ;
     RECT  20.448 24.515 20.664 26.101 ;
     RECT  18.48 24.515 18.912 26.725 ;
     RECT  20.448 26.101 21.336 27.059 ;
     RECT  20.448 27.059 21.288 28.307 ;
     RECT  20.448 28.307 20.664 28.355 ;
     RECT  20.64 28.355 20.664 28.787 ;
     RECT  22.992 28.309 23.016 29.029 ;
     RECT  24 23.411 82.008 29.029 ;
     RECT  22.992 29.029 82.008 29.365 ;
     RECT  22.032 29.365 82.008 30.275 ;
     RECT  22.992 30.275 82.008 30.755 ;
     RECT  22.992 30.755 24.744 31.955 ;
     RECT  24 31.955 24.744 32.531 ;
     RECT  26.064 30.755 82.008 32.531 ;
     RECT  26.736 32.531 26.808 33.107 ;
     RECT  24 32.531 24.312 33.541 ;
     RECT  24 33.541 24.696 34.067 ;
     RECT  26.736 33.107 26.76 34.259 ;
     RECT  28.08 32.531 82.008 34.835 ;
     RECT  22.992 31.955 23.016 35.027 ;
     RECT  24 34.067 24.312 35.317 ;
     RECT  28.08 34.835 28.104 35.893 ;
     RECT  29.28 34.835 82.008 35.893 ;
     RECT  28.08 35.893 82.008 36.515 ;
     RECT  23.376 35.317 24.312 36.997 ;
     RECT  28.08 36.515 28.104 37.091 ;
     RECT  23.376 36.997 25.08 37.859 ;
     RECT  29.28 36.515 82.008 37.861 ;
     RECT  27.936 37.141 27.96 38.387 ;
     RECT  28.944 37.861 82.008 40.067 ;
     RECT  31.152 40.067 82.008 41.603 ;
     RECT  28.944 40.067 30.12 41.605 ;
     RECT  31.152 41.603 31.368 41.605 ;
     RECT  28.944 41.605 31.368 42.755 ;
     RECT  28.944 42.755 31.176 42.803 ;
     RECT  28.944 42.803 29.712 43.285 ;
     RECT  32.88 41.603 32.904 43.379 ;
     RECT  34.128 41.603 37.512 45.635 ;
     RECT  38.544 41.603 82.008 45.635 ;
     RECT  38.88 45.635 82.008 46.163 ;
     RECT  34.176 45.635 37.512 46.309 ;
     RECT  31.152 42.803 31.176 46.499 ;
     RECT  34.176 46.309 37.656 46.693 ;
     RECT  34.176 46.693 38.088 46.787 ;
     RECT  34.8 46.787 38.088 48.131 ;
     RECT  34.8 48.131 37.656 48.515 ;
     RECT  36.432 49.477 36.456 49.525 ;
     RECT  37.488 48.515 37.656 49.525 ;
     RECT  32.448 50.149 32.472 50.197 ;
     RECT  39.552 46.163 82.008 51.299 ;
     RECT  39.552 51.299 40.512 51.923 ;
     RECT  41.52 51.299 82.008 52.451 ;
     RECT  36.432 49.525 37.704 52.691 ;
     RECT  34.8 48.515 35.112 53.029 ;
     RECT  40.2 51.923 40.512 53.413 ;
     RECT  36.432 52.691 36.456 53.507 ;
     RECT  34.8 53.029 35.304 53.509 ;
     RECT  42.24 52.451 82.008 53.509 ;
     RECT  34.464 53.509 35.304 53.557 ;
     RECT  37.68 52.691 37.704 53.557 ;
     RECT  37.68 53.557 37.848 53.603 ;
     RECT  34.128 53.557 35.304 53.893 ;
     RECT  39.552 53.413 40.512 54.131 ;
     RECT  34.128 53.893 35.832 54.133 ;
     RECT  37.824 53.603 37.848 54.899 ;
     RECT  40.2 54.131 40.512 56.341 ;
     RECT  40.08 56.341 40.512 57.059 ;
     RECT  41.952 53.509 82.008 57.635 ;
     RECT  41.952 57.635 43.368 58.163 ;
     RECT  41.952 58.163 42.888 58.211 ;
     RECT  41.952 58.211 42.168 58.787 ;
     RECT  41.952 58.787 41.976 61.283 ;
     RECT  44.592 57.635 82.008 61.619 ;
     RECT  44.688 61.619 82.008 62.147 ;
     RECT  40.2 57.059 40.512 62.149 ;
     RECT  38.544 58.693 38.568 62.629 ;
     RECT  39.552 62.149 40.512 62.629 ;
     RECT  43.344 61.237 43.368 62.723 ;
     RECT  33.792 54.133 35.832 62.725 ;
     RECT  36.816 62.629 36.84 62.725 ;
     RECT  38.544 62.629 40.512 63.157 ;
     RECT  33.792 62.725 37.176 63.205 ;
     RECT  38.544 63.157 40.92 63.205 ;
     RECT  33.792 63.205 41.928 63.733 ;
     RECT  33.792 63.733 42.264 63.781 ;
     RECT  44.688 62.147 48.984 63.875 ;
     RECT  44.976 63.875 48.984 64.451 ;
     RECT  44.976 64.451 46.632 66.179 ;
     RECT  47.664 64.451 48.984 66.179 ;
     RECT  49.968 62.147 82.008 66.707 ;
     RECT  44.976 66.179 46.104 66.901 ;
     RECT  44.256 66.901 46.104 67.717 ;
     RECT  47.664 66.179 47.688 67.717 ;
     RECT  44.256 67.717 47.688 68.099 ;
     RECT  33.792 63.781 42.6 68.341 ;
     RECT  50.304 66.707 82.008 69.493 ;
     RECT  49.536 69.493 82.008 70.259 ;
     RECT  50.304 70.259 82.008 70.691 ;
     RECT  55.056 70.691 82.008 71.221 ;
     RECT  82.992 2.137 85.704 71.221 ;
     RECT  50.304 70.691 54.024 71.315 ;
     RECT  44.256 68.099 46.728 71.363 ;
     RECT  50.88 71.315 54.024 72.419 ;
     RECT  55.056 71.221 85.704 72.947 ;
     RECT  48.24 72.325 48.264 72.949 ;
     RECT  48.24 72.949 48.312 73.381 ;
     RECT  49.584 72.421 49.608 73.381 ;
     RECT  33.792 68.341 42.936 73.477 ;
     RECT  44.256 71.363 45.912 73.477 ;
     RECT  48.24 73.381 49.608 73.477 ;
     RECT  47.616 73.477 49.608 73.525 ;
     RECT  47.28 73.525 49.608 74.051 ;
     RECT  51 72.419 54.024 74.485 ;
     RECT  33.792 73.477 46.296 75.205 ;
     RECT  47.28 74.051 48.984 75.205 ;
     RECT  50.88 74.485 54.024 75.685 ;
     RECT  55.392 72.947 85.704 75.685 ;
     RECT  50.88 75.685 85.704 75.875 ;
     RECT  50.88 75.875 51.312 76.261 ;
     RECT  50.832 76.261 51.312 76.309 ;
     RECT  54.672 75.875 85.704 76.403 ;
     RECT  52.992 75.875 53.688 76.885 ;
     RECT  54.672 76.403 82.104 77.747 ;
     RECT  55.296 77.747 82.104 77.797 ;
     RECT  83.232 76.403 85.704 77.797 ;
     RECT  52.8 76.885 53.688 78.659 ;
     RECT  55.296 77.797 85.704 78.659 ;
     RECT  50.64 76.309 51.312 79.189 ;
     RECT  33.792 75.205 49.656 79.717 ;
     RECT  50.64 79.189 51.672 79.717 ;
     RECT  53.52 78.659 53.544 79.813 ;
     RECT  33.792 79.717 51.672 80.341 ;
     RECT  52.656 79.813 53.544 80.341 ;
     RECT  33.792 80.341 53.544 80.627 ;
     RECT  59.424 78.659 85.704 80.675 ;
     RECT  56.064 78.659 58.104 81.829 ;
     RECT  45.264 80.627 53.544 81.875 ;
     RECT  55.104 81.829 58.104 82.115 ;
     RECT  55.104 82.115 57.432 82.691 ;
     RECT  54.384 82.693 54.744 83.125 ;
     RECT  45.264 81.875 53.016 83.173 ;
     RECT  54 83.125 54.744 83.173 ;
     RECT  56.4 82.691 57.432 83.747 ;
     RECT  59.424 80.675 82.248 84.419 ;
     RECT  56.4 83.747 56.712 85.429 ;
     RECT  56.4 85.429 57.288 87.251 ;
     RECT  60.768 84.419 82.248 87.251 ;
     RECT  59.424 84.419 59.448 87.827 ;
     RECT  60.768 87.251 76.632 87.827 ;
     RECT  56.4 87.251 56.712 88.213 ;
     RECT  56.304 88.213 56.712 88.261 ;
     RECT  58.08 87.781 58.104 88.261 ;
     RECT  56.304 88.261 57.096 88.309 ;
     RECT  59.952 88.213 60.408 88.403 ;
     RECT  58.08 88.261 58.44 88.933 ;
     RECT  59.952 88.403 59.976 88.933 ;
     RECT  61.44 87.827 76.632 89.555 ;
     RECT  78 87.251 82.248 89.555 ;
     RECT  81.312 89.555 82.248 89.747 ;
     RECT  55.728 88.309 57.096 90.037 ;
     RECT  58.08 88.933 59.976 90.037 ;
     RECT  61.44 89.555 76.296 90.469 ;
     RECT  55.728 90.037 59.976 90.515 ;
     RECT  61.152 90.469 76.296 91.331 ;
     RECT  61.536 91.331 76.296 91.811 ;
     RECT  61.536 91.811 62.112 92.675 ;
     RECT  63.456 91.811 76.296 92.963 ;
     RECT  78 89.555 79.992 92.963 ;
     RECT  45.264 83.173 54.744 94.021 ;
     RECT  55.728 90.515 59.784 94.021 ;
     RECT  64.128 92.963 76.296 94.691 ;
     RECT  81.312 89.747 82.008 94.691 ;
     RECT  61.632 92.675 62.112 94.933 ;
     RECT  61.104 94.933 62.112 95.125 ;
     RECT  64.464 94.691 75.768 95.219 ;
     RECT  78 92.963 79.08 95.701 ;
     RECT  64.8 95.219 75.768 95.747 ;
     RECT  77.136 95.701 79.08 96.853 ;
     RECT  64.8 95.747 75.48 96.947 ;
     RECT  77.136 96.853 79.224 96.995 ;
     RECT  80.784 95.701 80.808 96.995 ;
     RECT  63.12 95.557 63.144 98.053 ;
     RECT  64.8 96.947 64.824 98.099 ;
     RECT  65.808 96.947 75.48 98.099 ;
     RECT  78 96.995 79.224 98.099 ;
     RECT  78 98.099 79.128 98.915 ;
     RECT  66.144 98.099 75.48 99.779 ;
     RECT  78 98.915 79.08 100.069 ;
     RECT  67.104 99.779 75.48 100.309 ;
     RECT  76.56 100.261 76.584 100.309 ;
     RECT  77.808 100.069 79.08 100.453 ;
     RECT  77.808 100.453 79.272 100.931 ;
     RECT  67.104 100.309 76.584 101.315 ;
     RECT  87.024 3.443 87.048 101.507 ;
     RECT  67.104 101.315 75.288 101.555 ;
     RECT  81.984 94.691 82.008 101.893 ;
     RECT  65.136 100.261 65.16 101.989 ;
     RECT  80.4 99.685 80.424 102.083 ;
     RECT  78 100.931 78.936 102.085 ;
     RECT  83.232 80.675 85.704 102.085 ;
     RECT  81.984 101.893 82.2 102.133 ;
     RECT  83.232 102.085 85.752 102.133 ;
     RECT  78 102.085 79.224 102.517 ;
     RECT  76.272 101.315 76.584 102.611 ;
     RECT  77.616 102.517 79.224 102.611 ;
     RECT  77.616 102.611 78.936 102.995 ;
     RECT  81.984 102.133 85.752 103.045 ;
     RECT  81.888 103.045 85.752 103.091 ;
     RECT  67.2 101.555 75.288 103.717 ;
     RECT  76.272 102.611 76.296 103.717 ;
     RECT  64.8 101.989 65.16 104.245 ;
     RECT  67.2 103.717 76.296 104.245 ;
     RECT  78 102.995 78.936 104.533 ;
     RECT  80.352 103.477 80.376 104.533 ;
     RECT  66.48 104.245 76.296 104.579 ;
     RECT  78 104.533 80.376 104.579 ;
     RECT  78 104.579 79.512 105.347 ;
     RECT  68.496 104.579 76.296 105.397 ;
     RECT  68.496 105.397 76.632 105.491 ;
     RECT  81.888 103.091 82.2 105.779 ;
     RECT  81.984 105.779 82.2 105.781 ;
     RECT  83.232 103.091 85.752 105.781 ;
     RECT  68.496 105.491 69.192 105.923 ;
     RECT  81.984 105.781 85.752 106.163 ;
     RECT  78 105.347 78.936 106.499 ;
     RECT  78 106.499 78.696 106.597 ;
     RECT  68.496 105.923 68.856 106.643 ;
     RECT  70.176 105.491 76.632 107.029 ;
     RECT  77.904 106.597 78.696 107.029 ;
     RECT  70.176 107.029 78.696 107.701 ;
     RECT  68.496 106.643 68.52 107.795 ;
     RECT  81.984 106.163 85.704 107.941 ;
     RECT  69.552 107.701 78.696 108.035 ;
     RECT  69.552 108.035 78.312 108.565 ;
     RECT  69.408 108.565 78.312 108.899 ;
     RECT  81.984 107.941 86.376 108.899 ;
     RECT  76.272 108.899 78.312 109.285 ;
     RECT  79.44 108.805 79.464 109.285 ;
     RECT  76.272 109.285 79.464 109.331 ;
     RECT  69.408 108.899 75.288 109.861 ;
     RECT  76.272 109.331 78.888 109.861 ;
     RECT  69.408 109.861 78.888 109.957 ;
     RECT  81.984 108.899 85.704 109.957 ;
     RECT  69.168 109.957 78.888 110.627 ;
     RECT  81.456 109.957 85.704 110.675 ;
     RECT  70.512 110.627 78.888 110.867 ;
     RECT  69.168 110.627 69.192 111.733 ;
     RECT  81.984 110.675 85.704 111.779 ;
     RECT  76.272 110.867 78.888 111.971 ;
     RECT  68.496 111.733 69.192 112.021 ;
     RECT  70.512 110.867 75.288 112.021 ;
     RECT  66.48 104.579 67.512 112.261 ;
     RECT  68.496 112.021 75.288 112.261 ;
     RECT  82.032 111.779 85.704 112.643 ;
     RECT  80.496 112.693 80.52 112.981 ;
     RECT  79.728 112.981 80.52 113.029 ;
     RECT  82.032 112.643 85.368 113.029 ;
     RECT  79.728 113.029 85.368 113.459 ;
     RECT  81.312 113.459 85.224 113.843 ;
     RECT  76.272 111.971 78.312 113.941 ;
     RECT  66.48 112.261 75.288 114.035 ;
     RECT  86.64 113.845 86.664 114.611 ;
     RECT  66.48 114.035 69.864 115.093 ;
     RECT  70.896 114.035 75.288 115.093 ;
     RECT  82.608 113.843 85.224 115.187 ;
     RECT  82.608 115.187 83.712 115.379 ;
     RECT  82.992 115.379 83.712 115.427 ;
     RECT  79.728 113.459 79.752 115.717 ;
     RECT  83.28 115.427 83.712 116.149 ;
     RECT  85.2 115.187 85.224 116.149 ;
     RECT  66.48 115.093 75.288 116.339 ;
     RECT  83.28 116.149 85.224 116.867 ;
     RECT  66.48 116.339 72.912 116.963 ;
     RECT  79.728 115.717 80.328 117.109 ;
     RECT  83.28 116.867 85.08 117.491 ;
     RECT  76.272 113.941 78.648 117.925 ;
     RECT  79.632 117.109 80.328 117.925 ;
     RECT  76.272 117.925 80.328 118.549 ;
     RECT  81.312 113.843 81.336 118.549 ;
     RECT  76.272 118.549 81.336 118.595 ;
     RECT  66.48 116.963 70.92 118.741 ;
     RECT  86.064 117.397 86.088 118.835 ;
     RECT  66.48 118.741 71.352 119.077 ;
     RECT  72.336 116.963 72.912 119.077 ;
     RECT  83.4 117.491 85.08 120.085 ;
     RECT  79.728 118.595 81.336 120.133 ;
     RECT  66.48 119.077 72.912 120.275 ;
     RECT  72.384 120.275 72.912 120.323 ;
     RECT  73.92 116.339 75.288 120.323 ;
     RECT  79.728 120.133 82.296 120.803 ;
     RECT  72.48 120.323 72.912 120.853 ;
     RECT  83.4 120.085 85.704 121.141 ;
     RECT  66.48 120.275 71.352 121.187 ;
     RECT  83.4 121.141 86.328 121.187 ;
     RECT  76.272 118.595 78.648 121.669 ;
     RECT  79.728 120.803 81.336 121.669 ;
     RECT  74.256 120.323 75.288 122.579 ;
     RECT  86.304 121.187 86.328 122.675 ;
     RECT  75.024 122.579 75.288 122.723 ;
     RECT  83.4 121.187 85.08 123.109 ;
     RECT  82.656 123.109 85.08 123.155 ;
     RECT  72.48 120.853 73.272 123.733 ;
     RECT  75.024 122.723 75.096 124.019 ;
     RECT  75.072 124.019 75.096 124.691 ;
     RECT  82.656 123.155 84.936 125.219 ;
     RECT  32.448 50.197 32.808 125.365 ;
     RECT  33.792 80.627 44.28 125.365 ;
     RECT  86.256 124.213 86.28 125.603 ;
     RECT  82.656 125.219 84.408 125.797 ;
     RECT  82.512 125.797 84.408 125.939 ;
     RECT  82.656 125.939 84.408 125.987 ;
     RECT  32.448 125.365 44.28 126.469 ;
     RECT  45.264 94.021 59.784 126.469 ;
     RECT  72.24 123.733 73.272 126.565 ;
     RECT  63.12 98.053 63.816 127.045 ;
     RECT  64.8 104.245 65.496 127.045 ;
     RECT  66.48 121.187 71.256 127.045 ;
     RECT  72.24 126.565 73.608 127.045 ;
     RECT  74.928 126.421 74.952 127.045 ;
     RECT  82.656 125.987 83.712 127.093 ;
     RECT  6.864 12.563 8.112 127.449 ;
     RECT  17.952 26.725 18.912 127.449 ;
     RECT  23.376 37.859 24.312 127.449 ;
     RECT  28.752 43.285 29.712 127.449 ;
     RECT  1.776 21.109 3.144 127.463 ;
     RECT  6.864 127.449 7.92 127.463 ;
     RECT  12.24 22.645 14.616 127.463 ;
     RECT  17.952 127.449 18.72 127.463 ;
     RECT  23.376 127.449 24.12 127.463 ;
     RECT  28.752 127.449 29.52 127.463 ;
     RECT  66.48 127.045 73.608 127.621 ;
     RECT  74.928 127.045 75.288 127.621 ;
     RECT  82.656 127.093 84.36 127.621 ;
     RECT  76.272 121.669 81.336 127.669 ;
     RECT  82.656 127.621 85.368 127.669 ;
     RECT  60.768 95.125 62.112 128.197 ;
     RECT  63.12 127.045 65.496 128.197 ;
     RECT  66.48 127.621 75.288 128.197 ;
     RECT  86.688 128.197 87.048 128.245 ;
     RECT  32.448 126.469 59.784 128.773 ;
     RECT  60.768 128.197 75.288 128.773 ;
     RECT  76.272 127.669 85.368 128.773 ;
     RECT  86.352 128.245 87.432 128.773 ;
     RECT  6.864 127.463 7.56 128.821 ;
     RECT  16.944 25.621 16.968 129.253 ;
     RECT  1.776 127.463 1.8 129.349 ;
     RECT  12.24 127.463 12.264 129.349 ;
     RECT  13.248 128.821 13.272 129.349 ;
     RECT  16.608 129.253 16.968 129.349 ;
     RECT  19.968 30.181 19.992 129.349 ;
     RECT  25.392 129.301 25.416 129.349 ;
     RECT  28.752 127.463 28.776 129.349 ;
     RECT  0.768 17.605 0.792 129.397 ;
     RECT  1.776 129.349 2.136 129.397 ;
     RECT  3.12 127.463 3.144 129.397 ;
     RECT  4.128 129.349 4.488 129.397 ;
     RECT  5.856 129.301 5.88 129.397 ;
     RECT  6.864 128.821 7.896 129.397 ;
     RECT  9.552 15.731 9.576 129.397 ;
     RECT  10.896 17.699 10.92 129.397 ;
     RECT  12.24 129.349 13.272 129.397 ;
     RECT  15.936 129.349 16.968 129.397 ;
     RECT  17.952 127.463 18.312 129.397 ;
     RECT  19.296 129.349 19.992 129.397 ;
     RECT  21.696 33.013 21.72 129.397 ;
     RECT  23.376 127.463 23.736 129.397 ;
     RECT  24.72 129.349 25.416 129.397 ;
     RECT  26.4 39.829 26.424 129.397 ;
     RECT  28.416 129.349 28.776 129.397 ;
     RECT  29.76 129.349 29.784 129.397 ;
     RECT  31.104 129.349 31.128 129.397 ;
     RECT  32.448 128.773 87.432 129.397 ;
     RECT  0.768 129.397 7.896 129.445 ;
     RECT  9.216 129.397 13.272 129.445 ;
     RECT  14.256 127.463 14.616 129.445 ;
     RECT  15.6 129.397 16.968 129.445 ;
     RECT  17.952 129.397 20.664 129.445 ;
     RECT  21.696 129.397 27.096 129.445 ;
     RECT  28.08 129.397 87.432 129.445 ;
     RECT  89.52 129.397 89.64 129.539 ;
     RECT  0.768 129.445 87.432 129.552 ;
     RECT  89.616 129.539 89.64 129.552 ;
  END
END qfd_c_xstn_safe
END LIBRARY
